VERSION 5.8 ;
BUSBITCHARS "[]" ;
DIVIDERCHAR "/" ;
UNITS
    DATABASE MICRONS 1000 ;
END UNITS

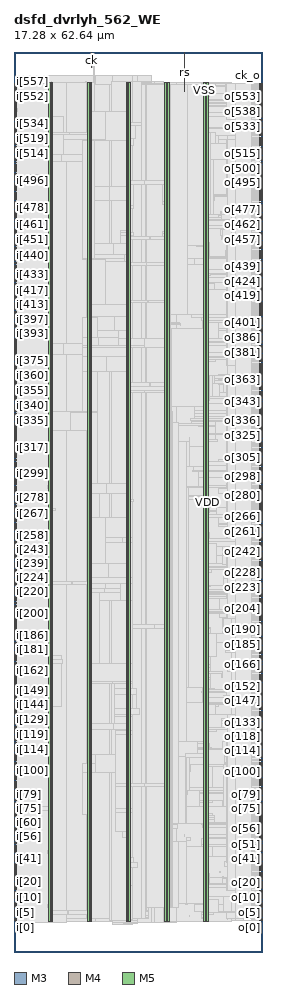
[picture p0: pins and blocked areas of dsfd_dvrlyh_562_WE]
MACRO dsfd_dvrlyh_562_WE
  FOREIGN dsfd_dvrlyh_562_WE 0 0 ;
  CLASS BLOCK ;
  SIZE 17.28 BY 62.64 ;
  PIN ck
    DIRECTION INPUT ;
    USE SIGNAL ;
    PORT
      LAYER M3 ;
        RECT  5.4 62.496 5.418 62.64 ;
    END
    PORT
      LAYER M3 ;
        RECT  5.4 61.579 5.418 62.508 ;
    END
  END ck
  PIN ck_o
    DIRECTION OUTPUT ;
    USE SIGNAL ;
    PORT
      LAYER M4 ;
        RECT  17.088 60.432 17.28 60.456 ;
    END
  END ck_o
  PIN i[0]
    DIRECTION INPUT ;
    USE SIGNAL ;
    PORT
      LAYER M4 ;
        RECT  0 2.208 0.192 2.232 ;
    END
  END i[0]
  PIN i[100]
    DIRECTION INPUT ;
    USE SIGNAL ;
    PORT
      LAYER M4 ;
        RECT  0 12.624 0.192 12.648 ;
    END
  END i[100]
  PIN i[101]
    DIRECTION INPUT ;
    USE SIGNAL ;
    PORT
      LAYER M4 ;
        RECT  0 12.72 0.192 12.744 ;
    END
  END i[101]
  PIN i[102]
    DIRECTION INPUT ;
    USE SIGNAL ;
    PORT
      LAYER M4 ;
        RECT  0 12.816 0.192 12.84 ;
    END
  END i[102]
  PIN i[103]
    DIRECTION INPUT ;
    USE SIGNAL ;
    PORT
      LAYER M4 ;
        RECT  0 12.912 0.192 12.936 ;
    END
  END i[103]
  PIN i[104]
    DIRECTION INPUT ;
    USE SIGNAL ;
    PORT
      LAYER M4 ;
        RECT  0 13.008 0.192 13.032 ;
    END
  END i[104]
  PIN i[105]
    DIRECTION INPUT ;
    USE SIGNAL ;
    PORT
      LAYER M4 ;
        RECT  0 13.104 0.192 13.128 ;
    END
  END i[105]
  PIN i[106]
    DIRECTION INPUT ;
    USE SIGNAL ;
    PORT
      LAYER M4 ;
        RECT  0 13.2 0.192 13.224 ;
    END
  END i[106]
  PIN i[107]
    DIRECTION INPUT ;
    USE SIGNAL ;
    PORT
      LAYER M4 ;
        RECT  0 13.344 0.192 13.368 ;
    END
  END i[107]
  PIN i[108]
    DIRECTION INPUT ;
    USE SIGNAL ;
    PORT
      LAYER M4 ;
        RECT  0 13.44 0.192 13.464 ;
    END
  END i[108]
  PIN i[109]
    DIRECTION INPUT ;
    USE SIGNAL ;
    PORT
      LAYER M4 ;
        RECT  0 13.536 0.192 13.56 ;
    END
  END i[109]
  PIN i[10]
    DIRECTION INPUT ;
    USE SIGNAL ;
    PORT
      LAYER M4 ;
        RECT  0 3.264 0.192 3.288 ;
    END
  END i[10]
  PIN i[110]
    DIRECTION INPUT ;
    USE SIGNAL ;
    PORT
      LAYER M4 ;
        RECT  0 13.632 0.192 13.656 ;
    END
  END i[110]
  PIN i[111]
    DIRECTION INPUT ;
    USE SIGNAL ;
    PORT
      LAYER M4 ;
        RECT  0 13.728 0.192 13.752 ;
    END
  END i[111]
  PIN i[112]
    DIRECTION INPUT ;
    USE SIGNAL ;
    PORT
      LAYER M4 ;
        RECT  0 13.824 0.192 13.848 ;
    END
  END i[112]
  PIN i[113]
    DIRECTION INPUT ;
    USE SIGNAL ;
    PORT
      LAYER M4 ;
        RECT  0 13.968 0.192 13.992 ;
    END
  END i[113]
  PIN i[114]
    DIRECTION INPUT ;
    USE SIGNAL ;
    PORT
      LAYER M4 ;
        RECT  0 14.064 0.192 14.088 ;
    END
  END i[114]
  PIN i[115]
    DIRECTION INPUT ;
    USE SIGNAL ;
    PORT
      LAYER M4 ;
        RECT  0 14.16 0.192 14.184 ;
    END
  END i[115]
  PIN i[116]
    DIRECTION INPUT ;
    USE SIGNAL ;
    PORT
      LAYER M4 ;
        RECT  0 14.256 0.192 14.28 ;
    END
  END i[116]
  PIN i[117]
    DIRECTION INPUT ;
    USE SIGNAL ;
    PORT
      LAYER M4 ;
        RECT  0 14.352 0.192 14.376 ;
    END
  END i[117]
  PIN i[118]
    DIRECTION INPUT ;
    USE SIGNAL ;
    PORT
      LAYER M4 ;
        RECT  0 14.448 0.192 14.472 ;
    END
  END i[118]
  PIN i[119]
    DIRECTION INPUT ;
    USE SIGNAL ;
    PORT
      LAYER M4 ;
        RECT  0 14.592 0.192 14.616 ;
    END
  END i[119]
  PIN i[11]
    DIRECTION INPUT ;
    USE SIGNAL ;
    PORT
      LAYER M4 ;
        RECT  0 3.36 0.192 3.384 ;
    END
  END i[11]
  PIN i[120]
    DIRECTION INPUT ;
    USE SIGNAL ;
    PORT
      LAYER M4 ;
        RECT  0 14.688 0.192 14.712 ;
    END
  END i[120]
  PIN i[121]
    DIRECTION INPUT ;
    USE SIGNAL ;
    PORT
      LAYER M4 ;
        RECT  0 14.784 0.192 14.808 ;
    END
  END i[121]
  PIN i[122]
    DIRECTION INPUT ;
    USE SIGNAL ;
    PORT
      LAYER M4 ;
        RECT  0 14.88 0.192 14.904 ;
    END
  END i[122]
  PIN i[123]
    DIRECTION INPUT ;
    USE SIGNAL ;
    PORT
      LAYER M4 ;
        RECT  0 14.976 0.192 15 ;
    END
  END i[123]
  PIN i[124]
    DIRECTION INPUT ;
    USE SIGNAL ;
    PORT
      LAYER M4 ;
        RECT  0 15.072 0.192 15.096 ;
    END
  END i[124]
  PIN i[125]
    DIRECTION INPUT ;
    USE SIGNAL ;
    PORT
      LAYER M4 ;
        RECT  0 15.216 0.192 15.24 ;
    END
  END i[125]
  PIN i[126]
    DIRECTION INPUT ;
    USE SIGNAL ;
    PORT
      LAYER M4 ;
        RECT  0 15.312 0.192 15.336 ;
    END
  END i[126]
  PIN i[127]
    DIRECTION INPUT ;
    USE SIGNAL ;
    PORT
      LAYER M4 ;
        RECT  0 15.408 0.192 15.432 ;
    END
  END i[127]
  PIN i[128]
    DIRECTION INPUT ;
    USE SIGNAL ;
    PORT
      LAYER M4 ;
        RECT  0 15.504 0.192 15.528 ;
    END
  END i[128]
  PIN i[129]
    DIRECTION INPUT ;
    USE SIGNAL ;
    PORT
      LAYER M4 ;
        RECT  0 15.6 0.192 15.624 ;
    END
  END i[129]
  PIN i[12]
    DIRECTION INPUT ;
    USE SIGNAL ;
    PORT
      LAYER M4 ;
        RECT  0 3.456 0.192 3.48 ;
    END
  END i[12]
  PIN i[130]
    DIRECTION INPUT ;
    USE SIGNAL ;
    PORT
      LAYER M4 ;
        RECT  0 15.696 0.192 15.72 ;
    END
  END i[130]
  PIN i[131]
    DIRECTION INPUT ;
    USE SIGNAL ;
    PORT
      LAYER M4 ;
        RECT  0 15.84 0.192 15.864 ;
    END
  END i[131]
  PIN i[132]
    DIRECTION INPUT ;
    USE SIGNAL ;
    PORT
      LAYER M4 ;
        RECT  0 15.936 0.192 15.96 ;
    END
  END i[132]
  PIN i[133]
    DIRECTION INPUT ;
    USE SIGNAL ;
    PORT
      LAYER M4 ;
        RECT  0 16.032 0.192 16.056 ;
    END
  END i[133]
  PIN i[134]
    DIRECTION INPUT ;
    USE SIGNAL ;
    PORT
      LAYER M4 ;
        RECT  0 16.128 0.192 16.152 ;
    END
  END i[134]
  PIN i[135]
    DIRECTION INPUT ;
    USE SIGNAL ;
    PORT
      LAYER M4 ;
        RECT  0 16.224 0.192 16.248 ;
    END
  END i[135]
  PIN i[136]
    DIRECTION INPUT ;
    USE SIGNAL ;
    PORT
      LAYER M4 ;
        RECT  0 16.32 0.192 16.344 ;
    END
  END i[136]
  PIN i[137]
    DIRECTION INPUT ;
    USE SIGNAL ;
    PORT
      LAYER M4 ;
        RECT  0 16.464 0.192 16.488 ;
    END
  END i[137]
  PIN i[138]
    DIRECTION INPUT ;
    USE SIGNAL ;
    PORT
      LAYER M4 ;
        RECT  0 16.56 0.192 16.584 ;
    END
  END i[138]
  PIN i[139]
    DIRECTION INPUT ;
    USE SIGNAL ;
    PORT
      LAYER M4 ;
        RECT  0 16.656 0.192 16.68 ;
    END
  END i[139]
  PIN i[13]
    DIRECTION INPUT ;
    USE SIGNAL ;
    PORT
      LAYER M4 ;
        RECT  0 3.552 0.192 3.576 ;
    END
  END i[13]
  PIN i[140]
    DIRECTION INPUT ;
    USE SIGNAL ;
    PORT
      LAYER M4 ;
        RECT  0 16.752 0.192 16.776 ;
    END
  END i[140]
  PIN i[141]
    DIRECTION INPUT ;
    USE SIGNAL ;
    PORT
      LAYER M4 ;
        RECT  0 16.848 0.192 16.872 ;
    END
  END i[141]
  PIN i[142]
    DIRECTION INPUT ;
    USE SIGNAL ;
    PORT
      LAYER M4 ;
        RECT  0 16.944 0.192 16.968 ;
    END
  END i[142]
  PIN i[143]
    DIRECTION INPUT ;
    USE SIGNAL ;
    PORT
      LAYER M4 ;
        RECT  0 17.04 0.192 17.064 ;
    END
  END i[143]
  PIN i[144]
    DIRECTION INPUT ;
    USE SIGNAL ;
    PORT
      LAYER M4 ;
        RECT  0 17.184 0.192 17.208 ;
    END
  END i[144]
  PIN i[145]
    DIRECTION INPUT ;
    USE SIGNAL ;
    PORT
      LAYER M4 ;
        RECT  0 17.28 0.192 17.304 ;
    END
  END i[145]
  PIN i[146]
    DIRECTION INPUT ;
    USE SIGNAL ;
    PORT
      LAYER M4 ;
        RECT  0 17.376 0.192 17.4 ;
    END
  END i[146]
  PIN i[147]
    DIRECTION INPUT ;
    USE SIGNAL ;
    PORT
      LAYER M4 ;
        RECT  0 17.472 0.192 17.496 ;
    END
  END i[147]
  PIN i[148]
    DIRECTION INPUT ;
    USE SIGNAL ;
    PORT
      LAYER M4 ;
        RECT  0 17.568 0.192 17.592 ;
    END
  END i[148]
  PIN i[149]
    DIRECTION INPUT ;
    USE SIGNAL ;
    PORT
      LAYER M4 ;
        RECT  0 17.664 0.192 17.688 ;
    END
  END i[149]
  PIN i[14]
    DIRECTION INPUT ;
    USE SIGNAL ;
    PORT
      LAYER M4 ;
        RECT  0 3.696 0.192 3.72 ;
    END
  END i[14]
  PIN i[150]
    DIRECTION INPUT ;
    USE SIGNAL ;
    PORT
      LAYER M4 ;
        RECT  0 17.808 0.192 17.832 ;
    END
  END i[150]
  PIN i[151]
    DIRECTION INPUT ;
    USE SIGNAL ;
    PORT
      LAYER M4 ;
        RECT  0 17.904 0.192 17.928 ;
    END
  END i[151]
  PIN i[152]
    DIRECTION INPUT ;
    USE SIGNAL ;
    PORT
      LAYER M4 ;
        RECT  0 18 0.192 18.024 ;
    END
  END i[152]
  PIN i[153]
    DIRECTION INPUT ;
    USE SIGNAL ;
    PORT
      LAYER M4 ;
        RECT  0 18.096 0.192 18.12 ;
    END
  END i[153]
  PIN i[154]
    DIRECTION INPUT ;
    USE SIGNAL ;
    PORT
      LAYER M4 ;
        RECT  0 18.192 0.192 18.216 ;
    END
  END i[154]
  PIN i[155]
    DIRECTION INPUT ;
    USE SIGNAL ;
    PORT
      LAYER M4 ;
        RECT  0 18.288 0.192 18.312 ;
    END
  END i[155]
  PIN i[156]
    DIRECTION INPUT ;
    USE SIGNAL ;
    PORT
      LAYER M4 ;
        RECT  0 18.432 0.192 18.456 ;
    END
  END i[156]
  PIN i[157]
    DIRECTION INPUT ;
    USE SIGNAL ;
    PORT
      LAYER M4 ;
        RECT  0 18.528 0.192 18.552 ;
    END
  END i[157]
  PIN i[158]
    DIRECTION INPUT ;
    USE SIGNAL ;
    PORT
      LAYER M4 ;
        RECT  0 18.624 0.192 18.648 ;
    END
  END i[158]
  PIN i[159]
    DIRECTION INPUT ;
    USE SIGNAL ;
    PORT
      LAYER M4 ;
        RECT  0 18.72 0.192 18.744 ;
    END
  END i[159]
  PIN i[15]
    DIRECTION INPUT ;
    USE SIGNAL ;
    PORT
      LAYER M4 ;
        RECT  0 3.792 0.192 3.816 ;
    END
  END i[15]
  PIN i[160]
    DIRECTION INPUT ;
    USE SIGNAL ;
    PORT
      LAYER M4 ;
        RECT  0 18.816 0.192 18.84 ;
    END
  END i[160]
  PIN i[161]
    DIRECTION INPUT ;
    USE SIGNAL ;
    PORT
      LAYER M4 ;
        RECT  0 18.912 0.192 18.936 ;
    END
  END i[161]
  PIN i[162]
    DIRECTION INPUT ;
    USE SIGNAL ;
    PORT
      LAYER M4 ;
        RECT  0 19.056 0.192 19.08 ;
    END
  END i[162]
  PIN i[163]
    DIRECTION INPUT ;
    USE SIGNAL ;
    PORT
      LAYER M4 ;
        RECT  0 19.152 0.192 19.176 ;
    END
  END i[163]
  PIN i[164]
    DIRECTION INPUT ;
    USE SIGNAL ;
    PORT
      LAYER M4 ;
        RECT  0 19.248 0.192 19.272 ;
    END
  END i[164]
  PIN i[165]
    DIRECTION INPUT ;
    USE SIGNAL ;
    PORT
      LAYER M4 ;
        RECT  0 19.344 0.192 19.368 ;
    END
  END i[165]
  PIN i[166]
    DIRECTION INPUT ;
    USE SIGNAL ;
    PORT
      LAYER M4 ;
        RECT  0 19.44 0.192 19.464 ;
    END
  END i[166]
  PIN i[167]
    DIRECTION INPUT ;
    USE SIGNAL ;
    PORT
      LAYER M4 ;
        RECT  0 19.536 0.192 19.56 ;
    END
  END i[167]
  PIN i[168]
    DIRECTION INPUT ;
    USE SIGNAL ;
    PORT
      LAYER M4 ;
        RECT  0 19.68 0.192 19.704 ;
    END
  END i[168]
  PIN i[169]
    DIRECTION INPUT ;
    USE SIGNAL ;
    PORT
      LAYER M4 ;
        RECT  0 19.776 0.192 19.8 ;
    END
  END i[169]
  PIN i[16]
    DIRECTION INPUT ;
    USE SIGNAL ;
    PORT
      LAYER M4 ;
        RECT  0 3.888 0.192 3.912 ;
    END
  END i[16]
  PIN i[170]
    DIRECTION INPUT ;
    USE SIGNAL ;
    PORT
      LAYER M4 ;
        RECT  0 19.872 0.192 19.896 ;
    END
  END i[170]
  PIN i[171]
    DIRECTION INPUT ;
    USE SIGNAL ;
    PORT
      LAYER M4 ;
        RECT  0 19.968 0.192 19.992 ;
    END
  END i[171]
  PIN i[172]
    DIRECTION INPUT ;
    USE SIGNAL ;
    PORT
      LAYER M4 ;
        RECT  0 20.064 0.192 20.088 ;
    END
  END i[172]
  PIN i[173]
    DIRECTION INPUT ;
    USE SIGNAL ;
    PORT
      LAYER M4 ;
        RECT  0 20.16 0.192 20.184 ;
    END
  END i[173]
  PIN i[174]
    DIRECTION INPUT ;
    USE SIGNAL ;
    PORT
      LAYER M4 ;
        RECT  0 20.304 0.192 20.328 ;
    END
  END i[174]
  PIN i[175]
    DIRECTION INPUT ;
    USE SIGNAL ;
    PORT
      LAYER M4 ;
        RECT  0 20.4 0.192 20.424 ;
    END
  END i[175]
  PIN i[176]
    DIRECTION INPUT ;
    USE SIGNAL ;
    PORT
      LAYER M4 ;
        RECT  0 20.496 0.192 20.52 ;
    END
  END i[176]
  PIN i[177]
    DIRECTION INPUT ;
    USE SIGNAL ;
    PORT
      LAYER M4 ;
        RECT  0 20.592 0.192 20.616 ;
    END
  END i[177]
  PIN i[178]
    DIRECTION INPUT ;
    USE SIGNAL ;
    PORT
      LAYER M4 ;
        RECT  0 20.688 0.192 20.712 ;
    END
  END i[178]
  PIN i[179]
    DIRECTION INPUT ;
    USE SIGNAL ;
    PORT
      LAYER M4 ;
        RECT  0 20.784 0.192 20.808 ;
    END
  END i[179]
  PIN i[17]
    DIRECTION INPUT ;
    USE SIGNAL ;
    PORT
      LAYER M4 ;
        RECT  0 3.984 0.192 4.008 ;
    END
  END i[17]
  PIN i[180]
    DIRECTION INPUT ;
    USE SIGNAL ;
    PORT
      LAYER M4 ;
        RECT  0 20.88 0.192 20.904 ;
    END
  END i[180]
  PIN i[181]
    DIRECTION INPUT ;
    USE SIGNAL ;
    PORT
      LAYER M4 ;
        RECT  0 21.024 0.192 21.048 ;
    END
  END i[181]
  PIN i[182]
    DIRECTION INPUT ;
    USE SIGNAL ;
    PORT
      LAYER M4 ;
        RECT  0 21.12 0.192 21.144 ;
    END
  END i[182]
  PIN i[183]
    DIRECTION INPUT ;
    USE SIGNAL ;
    PORT
      LAYER M4 ;
        RECT  0 21.216 0.192 21.24 ;
    END
  END i[183]
  PIN i[184]
    DIRECTION INPUT ;
    USE SIGNAL ;
    PORT
      LAYER M4 ;
        RECT  0 21.312 0.192 21.336 ;
    END
  END i[184]
  PIN i[185]
    DIRECTION INPUT ;
    USE SIGNAL ;
    PORT
      LAYER M4 ;
        RECT  0 21.408 0.192 21.432 ;
    END
  END i[185]
  PIN i[186]
    DIRECTION INPUT ;
    USE SIGNAL ;
    PORT
      LAYER M4 ;
        RECT  0 21.504 0.192 21.528 ;
    END
  END i[186]
  PIN i[187]
    DIRECTION INPUT ;
    USE SIGNAL ;
    PORT
      LAYER M4 ;
        RECT  0 21.648 0.192 21.672 ;
    END
  END i[187]
  PIN i[188]
    DIRECTION INPUT ;
    USE SIGNAL ;
    PORT
      LAYER M4 ;
        RECT  0 21.744 0.192 21.768 ;
    END
  END i[188]
  PIN i[189]
    DIRECTION INPUT ;
    USE SIGNAL ;
    PORT
      LAYER M4 ;
        RECT  0 21.84 0.192 21.864 ;
    END
  END i[189]
  PIN i[18]
    DIRECTION INPUT ;
    USE SIGNAL ;
    PORT
      LAYER M4 ;
        RECT  0 4.08 0.192 4.104 ;
    END
  END i[18]
  PIN i[190]
    DIRECTION INPUT ;
    USE SIGNAL ;
    PORT
      LAYER M4 ;
        RECT  0 21.936 0.192 21.96 ;
    END
  END i[190]
  PIN i[191]
    DIRECTION INPUT ;
    USE SIGNAL ;
    PORT
      LAYER M4 ;
        RECT  0 22.032 0.192 22.056 ;
    END
  END i[191]
  PIN i[192]
    DIRECTION INPUT ;
    USE SIGNAL ;
    PORT
      LAYER M4 ;
        RECT  0 22.128 0.192 22.152 ;
    END
  END i[192]
  PIN i[193]
    DIRECTION INPUT ;
    USE SIGNAL ;
    PORT
      LAYER M4 ;
        RECT  0 22.272 0.192 22.296 ;
    END
  END i[193]
  PIN i[194]
    DIRECTION INPUT ;
    USE SIGNAL ;
    PORT
      LAYER M4 ;
        RECT  0 22.368 0.192 22.392 ;
    END
  END i[194]
  PIN i[195]
    DIRECTION INPUT ;
    USE SIGNAL ;
    PORT
      LAYER M4 ;
        RECT  0 22.464 0.192 22.488 ;
    END
  END i[195]
  PIN i[196]
    DIRECTION INPUT ;
    USE SIGNAL ;
    PORT
      LAYER M4 ;
        RECT  0 22.56 0.192 22.584 ;
    END
  END i[196]
  PIN i[197]
    DIRECTION INPUT ;
    USE SIGNAL ;
    PORT
      LAYER M4 ;
        RECT  0 22.656 0.192 22.68 ;
    END
  END i[197]
  PIN i[198]
    DIRECTION INPUT ;
    USE SIGNAL ;
    PORT
      LAYER M4 ;
        RECT  0 22.752 0.192 22.776 ;
    END
  END i[198]
  PIN i[199]
    DIRECTION INPUT ;
    USE SIGNAL ;
    PORT
      LAYER M4 ;
        RECT  0 22.896 0.192 22.92 ;
    END
  END i[199]
  PIN i[19]
    DIRECTION INPUT ;
    USE SIGNAL ;
    PORT
      LAYER M4 ;
        RECT  0 4.176 0.192 4.2 ;
    END
  END i[19]
  PIN i[1]
    DIRECTION INPUT ;
    USE SIGNAL ;
    PORT
      LAYER M4 ;
        RECT  0 2.304 0.192 2.328 ;
    END
  END i[1]
  PIN i[200]
    DIRECTION INPUT ;
    USE SIGNAL ;
    PORT
      LAYER M4 ;
        RECT  0 22.992 0.192 23.016 ;
    END
  END i[200]
  PIN i[201]
    DIRECTION INPUT ;
    USE SIGNAL ;
    PORT
      LAYER M4 ;
        RECT  0 23.088 0.192 23.112 ;
    END
  END i[201]
  PIN i[202]
    DIRECTION INPUT ;
    USE SIGNAL ;
    PORT
      LAYER M4 ;
        RECT  0 23.184 0.192 23.208 ;
    END
  END i[202]
  PIN i[203]
    DIRECTION INPUT ;
    USE SIGNAL ;
    PORT
      LAYER M4 ;
        RECT  0 23.28 0.192 23.304 ;
    END
  END i[203]
  PIN i[204]
    DIRECTION INPUT ;
    USE SIGNAL ;
    PORT
      LAYER M4 ;
        RECT  0 23.376 0.192 23.4 ;
    END
  END i[204]
  PIN i[205]
    DIRECTION INPUT ;
    USE SIGNAL ;
    PORT
      LAYER M4 ;
        RECT  0 23.52 0.192 23.544 ;
    END
  END i[205]
  PIN i[206]
    DIRECTION INPUT ;
    USE SIGNAL ;
    PORT
      LAYER M4 ;
        RECT  0 23.616 0.192 23.64 ;
    END
  END i[206]
  PIN i[207]
    DIRECTION INPUT ;
    USE SIGNAL ;
    PORT
      LAYER M4 ;
        RECT  0 23.712 0.192 23.736 ;
    END
  END i[207]
  PIN i[208]
    DIRECTION INPUT ;
    USE SIGNAL ;
    PORT
      LAYER M4 ;
        RECT  0 23.808 0.192 23.832 ;
    END
  END i[208]
  PIN i[209]
    DIRECTION INPUT ;
    USE SIGNAL ;
    PORT
      LAYER M4 ;
        RECT  0 23.904 0.192 23.928 ;
    END
  END i[209]
  PIN i[20]
    DIRECTION INPUT ;
    USE SIGNAL ;
    PORT
      LAYER M4 ;
        RECT  0 4.32 0.192 4.344 ;
    END
  END i[20]
  PIN i[210]
    DIRECTION INPUT ;
    USE SIGNAL ;
    PORT
      LAYER M4 ;
        RECT  0 24 0.192 24.024 ;
    END
  END i[210]
  PIN i[211]
    DIRECTION INPUT ;
    USE SIGNAL ;
    PORT
      LAYER M4 ;
        RECT  0 24.096 0.192 24.12 ;
    END
  END i[211]
  PIN i[212]
    DIRECTION INPUT ;
    USE SIGNAL ;
    PORT
      LAYER M4 ;
        RECT  0 24.24 0.192 24.264 ;
    END
  END i[212]
  PIN i[213]
    DIRECTION INPUT ;
    USE SIGNAL ;
    PORT
      LAYER M4 ;
        RECT  0 24.336 0.192 24.36 ;
    END
  END i[213]
  PIN i[214]
    DIRECTION INPUT ;
    USE SIGNAL ;
    PORT
      LAYER M4 ;
        RECT  0 24.432 0.192 24.456 ;
    END
  END i[214]
  PIN i[215]
    DIRECTION INPUT ;
    USE SIGNAL ;
    PORT
      LAYER M4 ;
        RECT  0 24.528 0.192 24.552 ;
    END
  END i[215]
  PIN i[216]
    DIRECTION INPUT ;
    USE SIGNAL ;
    PORT
      LAYER M4 ;
        RECT  0 24.624 0.192 24.648 ;
    END
  END i[216]
  PIN i[217]
    DIRECTION INPUT ;
    USE SIGNAL ;
    PORT
      LAYER M4 ;
        RECT  0 24.72 0.192 24.744 ;
    END
  END i[217]
  PIN i[218]
    DIRECTION INPUT ;
    USE SIGNAL ;
    PORT
      LAYER M4 ;
        RECT  0 24.864 0.192 24.888 ;
    END
  END i[218]
  PIN i[219]
    DIRECTION INPUT ;
    USE SIGNAL ;
    PORT
      LAYER M4 ;
        RECT  0 24.96 0.192 24.984 ;
    END
  END i[219]
  PIN i[21]
    DIRECTION INPUT ;
    USE SIGNAL ;
    PORT
      LAYER M4 ;
        RECT  0 4.416 0.192 4.44 ;
    END
  END i[21]
  PIN i[220]
    DIRECTION INPUT ;
    USE SIGNAL ;
    PORT
      LAYER M4 ;
        RECT  0 25.056 0.192 25.08 ;
    END
  END i[220]
  PIN i[221]
    DIRECTION INPUT ;
    USE SIGNAL ;
    PORT
      LAYER M4 ;
        RECT  0 25.152 0.192 25.176 ;
    END
  END i[221]
  PIN i[222]
    DIRECTION INPUT ;
    USE SIGNAL ;
    PORT
      LAYER M4 ;
        RECT  0 25.248 0.192 25.272 ;
    END
  END i[222]
  PIN i[223]
    DIRECTION INPUT ;
    USE SIGNAL ;
    PORT
      LAYER M4 ;
        RECT  0 25.344 0.192 25.368 ;
    END
  END i[223]
  PIN i[224]
    DIRECTION INPUT ;
    USE SIGNAL ;
    PORT
      LAYER M4 ;
        RECT  0 25.488 0.192 25.512 ;
    END
  END i[224]
  PIN i[225]
    DIRECTION INPUT ;
    USE SIGNAL ;
    PORT
      LAYER M4 ;
        RECT  0 25.584 0.192 25.608 ;
    END
  END i[225]
  PIN i[226]
    DIRECTION INPUT ;
    USE SIGNAL ;
    PORT
      LAYER M4 ;
        RECT  0 25.68 0.192 25.704 ;
    END
  END i[226]
  PIN i[227]
    DIRECTION INPUT ;
    USE SIGNAL ;
    PORT
      LAYER M4 ;
        RECT  0 25.776 0.192 25.8 ;
    END
  END i[227]
  PIN i[228]
    DIRECTION INPUT ;
    USE SIGNAL ;
    PORT
      LAYER M4 ;
        RECT  0 25.872 0.192 25.896 ;
    END
  END i[228]
  PIN i[229]
    DIRECTION INPUT ;
    USE SIGNAL ;
    PORT
      LAYER M4 ;
        RECT  0 25.968 0.192 25.992 ;
    END
  END i[229]
  PIN i[22]
    DIRECTION INPUT ;
    USE SIGNAL ;
    PORT
      LAYER M4 ;
        RECT  0 4.512 0.192 4.536 ;
    END
  END i[22]
  PIN i[230]
    DIRECTION INPUT ;
    USE SIGNAL ;
    PORT
      LAYER M4 ;
        RECT  0 26.112 0.192 26.136 ;
    END
  END i[230]
  PIN i[231]
    DIRECTION INPUT ;
    USE SIGNAL ;
    PORT
      LAYER M4 ;
        RECT  0 26.208 0.192 26.232 ;
    END
  END i[231]
  PIN i[232]
    DIRECTION INPUT ;
    USE SIGNAL ;
    PORT
      LAYER M4 ;
        RECT  0 26.304 0.192 26.328 ;
    END
  END i[232]
  PIN i[233]
    DIRECTION INPUT ;
    USE SIGNAL ;
    PORT
      LAYER M4 ;
        RECT  0 26.4 0.192 26.424 ;
    END
  END i[233]
  PIN i[234]
    DIRECTION INPUT ;
    USE SIGNAL ;
    PORT
      LAYER M4 ;
        RECT  0 26.496 0.192 26.52 ;
    END
  END i[234]
  PIN i[235]
    DIRECTION INPUT ;
    USE SIGNAL ;
    PORT
      LAYER M4 ;
        RECT  0 26.592 0.192 26.616 ;
    END
  END i[235]
  PIN i[236]
    DIRECTION INPUT ;
    USE SIGNAL ;
    PORT
      LAYER M4 ;
        RECT  0 26.736 0.192 26.76 ;
    END
  END i[236]
  PIN i[237]
    DIRECTION INPUT ;
    USE SIGNAL ;
    PORT
      LAYER M4 ;
        RECT  0 26.832 0.192 26.856 ;
    END
  END i[237]
  PIN i[238]
    DIRECTION INPUT ;
    USE SIGNAL ;
    PORT
      LAYER M4 ;
        RECT  0 26.928 0.192 26.952 ;
    END
  END i[238]
  PIN i[239]
    DIRECTION INPUT ;
    USE SIGNAL ;
    PORT
      LAYER M4 ;
        RECT  0 27.024 0.192 27.048 ;
    END
  END i[239]
  PIN i[23]
    DIRECTION INPUT ;
    USE SIGNAL ;
    PORT
      LAYER M4 ;
        RECT  0 4.608 0.192 4.632 ;
    END
  END i[23]
  PIN i[240]
    DIRECTION INPUT ;
    USE SIGNAL ;
    PORT
      LAYER M4 ;
        RECT  0 27.12 0.192 27.144 ;
    END
  END i[240]
  PIN i[241]
    DIRECTION INPUT ;
    USE SIGNAL ;
    PORT
      LAYER M4 ;
        RECT  0 27.216 0.192 27.24 ;
    END
  END i[241]
  PIN i[242]
    DIRECTION INPUT ;
    USE SIGNAL ;
    PORT
      LAYER M4 ;
        RECT  0 27.36 0.192 27.384 ;
    END
  END i[242]
  PIN i[243]
    DIRECTION INPUT ;
    USE SIGNAL ;
    PORT
      LAYER M4 ;
        RECT  0 27.456 0.192 27.48 ;
    END
  END i[243]
  PIN i[244]
    DIRECTION INPUT ;
    USE SIGNAL ;
    PORT
      LAYER M4 ;
        RECT  0 27.552 0.192 27.576 ;
    END
  END i[244]
  PIN i[245]
    DIRECTION INPUT ;
    USE SIGNAL ;
    PORT
      LAYER M4 ;
        RECT  0 27.648 0.192 27.672 ;
    END
  END i[245]
  PIN i[246]
    DIRECTION INPUT ;
    USE SIGNAL ;
    PORT
      LAYER M4 ;
        RECT  0 27.744 0.192 27.768 ;
    END
  END i[246]
  PIN i[247]
    DIRECTION INPUT ;
    USE SIGNAL ;
    PORT
      LAYER M4 ;
        RECT  0 27.84 0.192 27.864 ;
    END
  END i[247]
  PIN i[248]
    DIRECTION INPUT ;
    USE SIGNAL ;
    PORT
      LAYER M4 ;
        RECT  0 27.936 0.192 27.96 ;
    END
  END i[248]
  PIN i[249]
    DIRECTION INPUT ;
    USE SIGNAL ;
    PORT
      LAYER M4 ;
        RECT  0 28.08 0.192 28.104 ;
    END
  END i[249]
  PIN i[24]
    DIRECTION INPUT ;
    USE SIGNAL ;
    PORT
      LAYER M4 ;
        RECT  0 4.704 0.192 4.728 ;
    END
  END i[24]
  PIN i[250]
    DIRECTION INPUT ;
    USE SIGNAL ;
    PORT
      LAYER M4 ;
        RECT  0 28.176 0.192 28.2 ;
    END
  END i[250]
  PIN i[251]
    DIRECTION INPUT ;
    USE SIGNAL ;
    PORT
      LAYER M4 ;
        RECT  0 28.272 0.192 28.296 ;
    END
  END i[251]
  PIN i[252]
    DIRECTION INPUT ;
    USE SIGNAL ;
    PORT
      LAYER M4 ;
        RECT  0 28.368 0.192 28.392 ;
    END
  END i[252]
  PIN i[253]
    DIRECTION INPUT ;
    USE SIGNAL ;
    PORT
      LAYER M4 ;
        RECT  0 28.464 0.192 28.488 ;
    END
  END i[253]
  PIN i[254]
    DIRECTION INPUT ;
    USE SIGNAL ;
    PORT
      LAYER M4 ;
        RECT  0 28.56 0.192 28.584 ;
    END
  END i[254]
  PIN i[255]
    DIRECTION INPUT ;
    USE SIGNAL ;
    PORT
      LAYER M4 ;
        RECT  0 28.704 0.192 28.728 ;
    END
  END i[255]
  PIN i[256]
    DIRECTION INPUT ;
    USE SIGNAL ;
    PORT
      LAYER M4 ;
        RECT  0 28.8 0.192 28.824 ;
    END
  END i[256]
  PIN i[257]
    DIRECTION INPUT ;
    USE SIGNAL ;
    PORT
      LAYER M4 ;
        RECT  0 28.896 0.192 28.92 ;
    END
  END i[257]
  PIN i[258]
    DIRECTION INPUT ;
    USE SIGNAL ;
    PORT
      LAYER M4 ;
        RECT  0 28.992 0.192 29.016 ;
    END
  END i[258]
  PIN i[259]
    DIRECTION INPUT ;
    USE SIGNAL ;
    PORT
      LAYER M4 ;
        RECT  0 29.088 0.192 29.112 ;
    END
  END i[259]
  PIN i[25]
    DIRECTION INPUT ;
    USE SIGNAL ;
    PORT
      LAYER M4 ;
        RECT  0 4.8 0.192 4.824 ;
    END
  END i[25]
  PIN i[260]
    DIRECTION INPUT ;
    USE SIGNAL ;
    PORT
      LAYER M4 ;
        RECT  0 29.184 0.192 29.208 ;
    END
  END i[260]
  PIN i[261]
    DIRECTION INPUT ;
    USE SIGNAL ;
    PORT
      LAYER M4 ;
        RECT  0 29.328 0.192 29.352 ;
    END
  END i[261]
  PIN i[262]
    DIRECTION INPUT ;
    USE SIGNAL ;
    PORT
      LAYER M4 ;
        RECT  0 29.424 0.192 29.448 ;
    END
  END i[262]
  PIN i[263]
    DIRECTION INPUT ;
    USE SIGNAL ;
    PORT
      LAYER M4 ;
        RECT  0 29.52 0.192 29.544 ;
    END
  END i[263]
  PIN i[264]
    DIRECTION INPUT ;
    USE SIGNAL ;
    PORT
      LAYER M4 ;
        RECT  0 29.616 0.192 29.64 ;
    END
  END i[264]
  PIN i[265]
    DIRECTION INPUT ;
    USE SIGNAL ;
    PORT
      LAYER M4 ;
        RECT  0 29.712 0.192 29.736 ;
    END
  END i[265]
  PIN i[266]
    DIRECTION INPUT ;
    USE SIGNAL ;
    PORT
      LAYER M4 ;
        RECT  0 29.808 0.192 29.832 ;
    END
  END i[266]
  PIN i[267]
    DIRECTION INPUT ;
    USE SIGNAL ;
    PORT
      LAYER M4 ;
        RECT  0 29.952 0.192 29.976 ;
    END
  END i[267]
  PIN i[268]
    DIRECTION INPUT ;
    USE SIGNAL ;
    PORT
      LAYER M4 ;
        RECT  0 30.048 0.192 30.072 ;
    END
  END i[268]
  PIN i[269]
    DIRECTION INPUT ;
    USE SIGNAL ;
    PORT
      LAYER M4 ;
        RECT  0 30.144 0.192 30.168 ;
    END
  END i[269]
  PIN i[26]
    DIRECTION INPUT ;
    USE SIGNAL ;
    PORT
      LAYER M4 ;
        RECT  0 4.944 0.192 4.968 ;
    END
  END i[26]
  PIN i[270]
    DIRECTION INPUT ;
    USE SIGNAL ;
    PORT
      LAYER M4 ;
        RECT  0 30.24 0.192 30.264 ;
    END
  END i[270]
  PIN i[271]
    DIRECTION INPUT ;
    USE SIGNAL ;
    PORT
      LAYER M4 ;
        RECT  0 30.336 0.192 30.36 ;
    END
  END i[271]
  PIN i[272]
    DIRECTION INPUT ;
    USE SIGNAL ;
    PORT
      LAYER M4 ;
        RECT  0 30.432 0.192 30.456 ;
    END
  END i[272]
  PIN i[273]
    DIRECTION INPUT ;
    USE SIGNAL ;
    PORT
      LAYER M4 ;
        RECT  0 30.576 0.192 30.6 ;
    END
  END i[273]
  PIN i[274]
    DIRECTION INPUT ;
    USE SIGNAL ;
    PORT
      LAYER M4 ;
        RECT  0 30.672 0.192 30.696 ;
    END
  END i[274]
  PIN i[275]
    DIRECTION INPUT ;
    USE SIGNAL ;
    PORT
      LAYER M4 ;
        RECT  0 30.768 0.192 30.792 ;
    END
  END i[275]
  PIN i[276]
    DIRECTION INPUT ;
    USE SIGNAL ;
    PORT
      LAYER M4 ;
        RECT  0 30.864 0.192 30.888 ;
    END
  END i[276]
  PIN i[277]
    DIRECTION INPUT ;
    USE SIGNAL ;
    PORT
      LAYER M4 ;
        RECT  0 30.96 0.192 30.984 ;
    END
  END i[277]
  PIN i[278]
    DIRECTION INPUT ;
    USE SIGNAL ;
    PORT
      LAYER M4 ;
        RECT  0 31.056 0.192 31.08 ;
    END
  END i[278]
  PIN i[279]
    DIRECTION INPUT ;
    USE SIGNAL ;
    PORT
      LAYER M4 ;
        RECT  0 31.2 0.192 31.224 ;
    END
  END i[279]
  PIN i[27]
    DIRECTION INPUT ;
    USE SIGNAL ;
    PORT
      LAYER M4 ;
        RECT  0 5.04 0.192 5.064 ;
    END
  END i[27]
  PIN i[280]
    DIRECTION INPUT ;
    USE SIGNAL ;
    PORT
      LAYER M4 ;
        RECT  0 31.296 0.192 31.32 ;
    END
  END i[280]
  PIN i[281]
    DIRECTION INPUT ;
    USE SIGNAL ;
    PORT
      LAYER M4 ;
        RECT  0 31.392 0.192 31.416 ;
    END
  END i[281]
  PIN i[282]
    DIRECTION INPUT ;
    USE SIGNAL ;
    PORT
      LAYER M4 ;
        RECT  0 31.488 0.192 31.512 ;
    END
  END i[282]
  PIN i[283]
    DIRECTION INPUT ;
    USE SIGNAL ;
    PORT
      LAYER M4 ;
        RECT  0 31.584 0.192 31.608 ;
    END
  END i[283]
  PIN i[284]
    DIRECTION INPUT ;
    USE SIGNAL ;
    PORT
      LAYER M4 ;
        RECT  0 31.68 0.192 31.704 ;
    END
  END i[284]
  PIN i[285]
    DIRECTION INPUT ;
    USE SIGNAL ;
    PORT
      LAYER M4 ;
        RECT  0 31.776 0.192 31.8 ;
    END
  END i[285]
  PIN i[286]
    DIRECTION INPUT ;
    USE SIGNAL ;
    PORT
      LAYER M4 ;
        RECT  0 31.92 0.192 31.944 ;
    END
  END i[286]
  PIN i[287]
    DIRECTION INPUT ;
    USE SIGNAL ;
    PORT
      LAYER M4 ;
        RECT  0 32.016 0.192 32.04 ;
    END
  END i[287]
  PIN i[288]
    DIRECTION INPUT ;
    USE SIGNAL ;
    PORT
      LAYER M4 ;
        RECT  0 32.112 0.192 32.136 ;
    END
  END i[288]
  PIN i[289]
    DIRECTION INPUT ;
    USE SIGNAL ;
    PORT
      LAYER M4 ;
        RECT  0 32.208 0.192 32.232 ;
    END
  END i[289]
  PIN i[28]
    DIRECTION INPUT ;
    USE SIGNAL ;
    PORT
      LAYER M4 ;
        RECT  0 5.136 0.192 5.16 ;
    END
  END i[28]
  PIN i[290]
    DIRECTION INPUT ;
    USE SIGNAL ;
    PORT
      LAYER M4 ;
        RECT  0 32.304 0.192 32.328 ;
    END
  END i[290]
  PIN i[291]
    DIRECTION INPUT ;
    USE SIGNAL ;
    PORT
      LAYER M4 ;
        RECT  0 32.4 0.192 32.424 ;
    END
  END i[291]
  PIN i[292]
    DIRECTION INPUT ;
    USE SIGNAL ;
    PORT
      LAYER M4 ;
        RECT  0 32.544 0.192 32.568 ;
    END
  END i[292]
  PIN i[293]
    DIRECTION INPUT ;
    USE SIGNAL ;
    PORT
      LAYER M4 ;
        RECT  0 32.64 0.192 32.664 ;
    END
  END i[293]
  PIN i[294]
    DIRECTION INPUT ;
    USE SIGNAL ;
    PORT
      LAYER M4 ;
        RECT  0 32.736 0.192 32.76 ;
    END
  END i[294]
  PIN i[295]
    DIRECTION INPUT ;
    USE SIGNAL ;
    PORT
      LAYER M4 ;
        RECT  0 32.832 0.192 32.856 ;
    END
  END i[295]
  PIN i[296]
    DIRECTION INPUT ;
    USE SIGNAL ;
    PORT
      LAYER M4 ;
        RECT  0 32.928 0.192 32.952 ;
    END
  END i[296]
  PIN i[297]
    DIRECTION INPUT ;
    USE SIGNAL ;
    PORT
      LAYER M4 ;
        RECT  0 33.024 0.192 33.048 ;
    END
  END i[297]
  PIN i[298]
    DIRECTION INPUT ;
    USE SIGNAL ;
    PORT
      LAYER M4 ;
        RECT  0 33.168 0.192 33.192 ;
    END
  END i[298]
  PIN i[299]
    DIRECTION INPUT ;
    USE SIGNAL ;
    PORT
      LAYER M4 ;
        RECT  0 33.264 0.192 33.288 ;
    END
  END i[299]
  PIN i[29]
    DIRECTION INPUT ;
    USE SIGNAL ;
    PORT
      LAYER M4 ;
        RECT  0 5.232 0.192 5.256 ;
    END
  END i[29]
  PIN i[2]
    DIRECTION INPUT ;
    USE SIGNAL ;
    PORT
      LAYER M4 ;
        RECT  0 2.448 0.192 2.472 ;
    END
  END i[2]
  PIN i[300]
    DIRECTION INPUT ;
    USE SIGNAL ;
    PORT
      LAYER M4 ;
        RECT  0 33.36 0.192 33.384 ;
    END
  END i[300]
  PIN i[301]
    DIRECTION INPUT ;
    USE SIGNAL ;
    PORT
      LAYER M4 ;
        RECT  0 33.456 0.192 33.48 ;
    END
  END i[301]
  PIN i[302]
    DIRECTION INPUT ;
    USE SIGNAL ;
    PORT
      LAYER M4 ;
        RECT  0 33.552 0.192 33.576 ;
    END
  END i[302]
  PIN i[303]
    DIRECTION INPUT ;
    USE SIGNAL ;
    PORT
      LAYER M4 ;
        RECT  0 33.648 0.192 33.672 ;
    END
  END i[303]
  PIN i[304]
    DIRECTION INPUT ;
    USE SIGNAL ;
    PORT
      LAYER M4 ;
        RECT  0 33.792 0.192 33.816 ;
    END
  END i[304]
  PIN i[305]
    DIRECTION INPUT ;
    USE SIGNAL ;
    PORT
      LAYER M4 ;
        RECT  0 33.888 0.192 33.912 ;
    END
  END i[305]
  PIN i[306]
    DIRECTION INPUT ;
    USE SIGNAL ;
    PORT
      LAYER M4 ;
        RECT  0 33.984 0.192 34.008 ;
    END
  END i[306]
  PIN i[307]
    DIRECTION INPUT ;
    USE SIGNAL ;
    PORT
      LAYER M4 ;
        RECT  0 34.08 0.192 34.104 ;
    END
  END i[307]
  PIN i[308]
    DIRECTION INPUT ;
    USE SIGNAL ;
    PORT
      LAYER M4 ;
        RECT  0 34.176 0.192 34.2 ;
    END
  END i[308]
  PIN i[309]
    DIRECTION INPUT ;
    USE SIGNAL ;
    PORT
      LAYER M4 ;
        RECT  0 34.272 0.192 34.296 ;
    END
  END i[309]
  PIN i[30]
    DIRECTION INPUT ;
    USE SIGNAL ;
    PORT
      LAYER M4 ;
        RECT  0 5.328 0.192 5.352 ;
    END
  END i[30]
  PIN i[310]
    DIRECTION INPUT ;
    USE SIGNAL ;
    PORT
      LAYER M4 ;
        RECT  0 34.416 0.192 34.44 ;
    END
  END i[310]
  PIN i[311]
    DIRECTION INPUT ;
    USE SIGNAL ;
    PORT
      LAYER M4 ;
        RECT  0 34.512 0.192 34.536 ;
    END
  END i[311]
  PIN i[312]
    DIRECTION INPUT ;
    USE SIGNAL ;
    PORT
      LAYER M4 ;
        RECT  0 34.608 0.192 34.632 ;
    END
  END i[312]
  PIN i[313]
    DIRECTION INPUT ;
    USE SIGNAL ;
    PORT
      LAYER M4 ;
        RECT  0 34.704 0.192 34.728 ;
    END
  END i[313]
  PIN i[314]
    DIRECTION INPUT ;
    USE SIGNAL ;
    PORT
      LAYER M4 ;
        RECT  0 34.8 0.192 34.824 ;
    END
  END i[314]
  PIN i[315]
    DIRECTION INPUT ;
    USE SIGNAL ;
    PORT
      LAYER M4 ;
        RECT  0 34.896 0.192 34.92 ;
    END
  END i[315]
  PIN i[316]
    DIRECTION INPUT ;
    USE SIGNAL ;
    PORT
      LAYER M4 ;
        RECT  0 34.992 0.192 35.016 ;
    END
  END i[316]
  PIN i[317]
    DIRECTION INPUT ;
    USE SIGNAL ;
    PORT
      LAYER M4 ;
        RECT  0 35.136 0.192 35.16 ;
    END
  END i[317]
  PIN i[318]
    DIRECTION INPUT ;
    USE SIGNAL ;
    PORT
      LAYER M4 ;
        RECT  0 35.232 0.192 35.256 ;
    END
  END i[318]
  PIN i[319]
    DIRECTION INPUT ;
    USE SIGNAL ;
    PORT
      LAYER M4 ;
        RECT  0 35.328 0.192 35.352 ;
    END
  END i[319]
  PIN i[31]
    DIRECTION INPUT ;
    USE SIGNAL ;
    PORT
      LAYER M4 ;
        RECT  0 5.424 0.192 5.448 ;
    END
  END i[31]
  PIN i[320]
    DIRECTION INPUT ;
    USE SIGNAL ;
    PORT
      LAYER M4 ;
        RECT  0 35.424 0.192 35.448 ;
    END
  END i[320]
  PIN i[321]
    DIRECTION INPUT ;
    USE SIGNAL ;
    PORT
      LAYER M4 ;
        RECT  0 35.52 0.192 35.544 ;
    END
  END i[321]
  PIN i[322]
    DIRECTION INPUT ;
    USE SIGNAL ;
    PORT
      LAYER M4 ;
        RECT  0 35.616 0.192 35.64 ;
    END
  END i[322]
  PIN i[323]
    DIRECTION INPUT ;
    USE SIGNAL ;
    PORT
      LAYER M4 ;
        RECT  0 35.76 0.192 35.784 ;
    END
  END i[323]
  PIN i[324]
    DIRECTION INPUT ;
    USE SIGNAL ;
    PORT
      LAYER M4 ;
        RECT  0 35.856 0.192 35.88 ;
    END
  END i[324]
  PIN i[325]
    DIRECTION INPUT ;
    USE SIGNAL ;
    PORT
      LAYER M4 ;
        RECT  0 35.952 0.192 35.976 ;
    END
  END i[325]
  PIN i[326]
    DIRECTION INPUT ;
    USE SIGNAL ;
    PORT
      LAYER M4 ;
        RECT  0 36.048 0.192 36.072 ;
    END
  END i[326]
  PIN i[327]
    DIRECTION INPUT ;
    USE SIGNAL ;
    PORT
      LAYER M4 ;
        RECT  0 36.144 0.192 36.168 ;
    END
  END i[327]
  PIN i[328]
    DIRECTION INPUT ;
    USE SIGNAL ;
    PORT
      LAYER M4 ;
        RECT  0 36.24 0.192 36.264 ;
    END
  END i[328]
  PIN i[329]
    DIRECTION INPUT ;
    USE SIGNAL ;
    PORT
      LAYER M4 ;
        RECT  0 36.384 0.192 36.408 ;
    END
  END i[329]
  PIN i[32]
    DIRECTION INPUT ;
    USE SIGNAL ;
    PORT
      LAYER M4 ;
        RECT  0 5.568 0.192 5.592 ;
    END
  END i[32]
  PIN i[330]
    DIRECTION INPUT ;
    USE SIGNAL ;
    PORT
      LAYER M4 ;
        RECT  0 36.48 0.192 36.504 ;
    END
  END i[330]
  PIN i[331]
    DIRECTION INPUT ;
    USE SIGNAL ;
    PORT
      LAYER M4 ;
        RECT  0 36.576 0.192 36.6 ;
    END
  END i[331]
  PIN i[332]
    DIRECTION INPUT ;
    USE SIGNAL ;
    PORT
      LAYER M4 ;
        RECT  0 36.672 0.192 36.696 ;
    END
  END i[332]
  PIN i[333]
    DIRECTION INPUT ;
    USE SIGNAL ;
    PORT
      LAYER M4 ;
        RECT  0 36.768 0.192 36.792 ;
    END
  END i[333]
  PIN i[334]
    DIRECTION INPUT ;
    USE SIGNAL ;
    PORT
      LAYER M4 ;
        RECT  0 36.864 0.192 36.888 ;
    END
  END i[334]
  PIN i[335]
    DIRECTION INPUT ;
    USE SIGNAL ;
    PORT
      LAYER M4 ;
        RECT  0 37.008 0.192 37.032 ;
    END
  END i[335]
  PIN i[336]
    DIRECTION INPUT ;
    USE SIGNAL ;
    PORT
      LAYER M4 ;
        RECT  0 37.104 0.192 37.128 ;
    END
  END i[336]
  PIN i[337]
    DIRECTION INPUT ;
    USE SIGNAL ;
    PORT
      LAYER M4 ;
        RECT  0 37.2 0.192 37.224 ;
    END
  END i[337]
  PIN i[338]
    DIRECTION INPUT ;
    USE SIGNAL ;
    PORT
      LAYER M4 ;
        RECT  0 37.296 0.192 37.32 ;
    END
  END i[338]
  PIN i[339]
    DIRECTION INPUT ;
    USE SIGNAL ;
    PORT
      LAYER M4 ;
        RECT  0 37.392 0.192 37.416 ;
    END
  END i[339]
  PIN i[33]
    DIRECTION INPUT ;
    USE SIGNAL ;
    PORT
      LAYER M4 ;
        RECT  0 5.664 0.192 5.688 ;
    END
  END i[33]
  PIN i[340]
    DIRECTION INPUT ;
    USE SIGNAL ;
    PORT
      LAYER M4 ;
        RECT  0 37.488 0.192 37.512 ;
    END
  END i[340]
  PIN i[341]
    DIRECTION INPUT ;
    USE SIGNAL ;
    PORT
      LAYER M4 ;
        RECT  0 37.632 0.192 37.656 ;
    END
  END i[341]
  PIN i[342]
    DIRECTION INPUT ;
    USE SIGNAL ;
    PORT
      LAYER M4 ;
        RECT  0 37.728 0.192 37.752 ;
    END
  END i[342]
  PIN i[343]
    DIRECTION INPUT ;
    USE SIGNAL ;
    PORT
      LAYER M4 ;
        RECT  0 37.824 0.192 37.848 ;
    END
  END i[343]
  PIN i[344]
    DIRECTION INPUT ;
    USE SIGNAL ;
    PORT
      LAYER M4 ;
        RECT  0 37.92 0.192 37.944 ;
    END
  END i[344]
  PIN i[345]
    DIRECTION INPUT ;
    USE SIGNAL ;
    PORT
      LAYER M4 ;
        RECT  0 38.016 0.192 38.04 ;
    END
  END i[345]
  PIN i[346]
    DIRECTION INPUT ;
    USE SIGNAL ;
    PORT
      LAYER M4 ;
        RECT  0 38.112 0.192 38.136 ;
    END
  END i[346]
  PIN i[347]
    DIRECTION INPUT ;
    USE SIGNAL ;
    PORT
      LAYER M4 ;
        RECT  0 38.256 0.192 38.28 ;
    END
  END i[347]
  PIN i[348]
    DIRECTION INPUT ;
    USE SIGNAL ;
    PORT
      LAYER M4 ;
        RECT  0 38.352 0.192 38.376 ;
    END
  END i[348]
  PIN i[349]
    DIRECTION INPUT ;
    USE SIGNAL ;
    PORT
      LAYER M4 ;
        RECT  0 38.448 0.192 38.472 ;
    END
  END i[349]
  PIN i[34]
    DIRECTION INPUT ;
    USE SIGNAL ;
    PORT
      LAYER M4 ;
        RECT  0 5.76 0.192 5.784 ;
    END
  END i[34]
  PIN i[350]
    DIRECTION INPUT ;
    USE SIGNAL ;
    PORT
      LAYER M4 ;
        RECT  0 38.544 0.192 38.568 ;
    END
  END i[350]
  PIN i[351]
    DIRECTION INPUT ;
    USE SIGNAL ;
    PORT
      LAYER M4 ;
        RECT  0 38.64 0.192 38.664 ;
    END
  END i[351]
  PIN i[352]
    DIRECTION INPUT ;
    USE SIGNAL ;
    PORT
      LAYER M4 ;
        RECT  0 38.736 0.192 38.76 ;
    END
  END i[352]
  PIN i[353]
    DIRECTION INPUT ;
    USE SIGNAL ;
    PORT
      LAYER M4 ;
        RECT  0 38.832 0.192 38.856 ;
    END
  END i[353]
  PIN i[354]
    DIRECTION INPUT ;
    USE SIGNAL ;
    PORT
      LAYER M4 ;
        RECT  0 38.976 0.192 39 ;
    END
  END i[354]
  PIN i[355]
    DIRECTION INPUT ;
    USE SIGNAL ;
    PORT
      LAYER M4 ;
        RECT  0 39.072 0.192 39.096 ;
    END
  END i[355]
  PIN i[356]
    DIRECTION INPUT ;
    USE SIGNAL ;
    PORT
      LAYER M4 ;
        RECT  0 39.168 0.192 39.192 ;
    END
  END i[356]
  PIN i[357]
    DIRECTION INPUT ;
    USE SIGNAL ;
    PORT
      LAYER M4 ;
        RECT  0 39.264 0.192 39.288 ;
    END
  END i[357]
  PIN i[358]
    DIRECTION INPUT ;
    USE SIGNAL ;
    PORT
      LAYER M4 ;
        RECT  0 39.36 0.192 39.384 ;
    END
  END i[358]
  PIN i[359]
    DIRECTION INPUT ;
    USE SIGNAL ;
    PORT
      LAYER M4 ;
        RECT  0 39.456 0.192 39.48 ;
    END
  END i[359]
  PIN i[35]
    DIRECTION INPUT ;
    USE SIGNAL ;
    PORT
      LAYER M4 ;
        RECT  0 5.856 0.192 5.88 ;
    END
  END i[35]
  PIN i[360]
    DIRECTION INPUT ;
    USE SIGNAL ;
    PORT
      LAYER M4 ;
        RECT  0 39.6 0.192 39.624 ;
    END
  END i[360]
  PIN i[361]
    DIRECTION INPUT ;
    USE SIGNAL ;
    PORT
      LAYER M4 ;
        RECT  0 39.696 0.192 39.72 ;
    END
  END i[361]
  PIN i[362]
    DIRECTION INPUT ;
    USE SIGNAL ;
    PORT
      LAYER M4 ;
        RECT  0 39.792 0.192 39.816 ;
    END
  END i[362]
  PIN i[363]
    DIRECTION INPUT ;
    USE SIGNAL ;
    PORT
      LAYER M4 ;
        RECT  0 39.888 0.192 39.912 ;
    END
  END i[363]
  PIN i[364]
    DIRECTION INPUT ;
    USE SIGNAL ;
    PORT
      LAYER M4 ;
        RECT  0 39.984 0.192 40.008 ;
    END
  END i[364]
  PIN i[365]
    DIRECTION INPUT ;
    USE SIGNAL ;
    PORT
      LAYER M4 ;
        RECT  0 40.08 0.192 40.104 ;
    END
  END i[365]
  PIN i[366]
    DIRECTION INPUT ;
    USE SIGNAL ;
    PORT
      LAYER M4 ;
        RECT  0 40.224 0.192 40.248 ;
    END
  END i[366]
  PIN i[367]
    DIRECTION INPUT ;
    USE SIGNAL ;
    PORT
      LAYER M4 ;
        RECT  0 40.32 0.192 40.344 ;
    END
  END i[367]
  PIN i[368]
    DIRECTION INPUT ;
    USE SIGNAL ;
    PORT
      LAYER M4 ;
        RECT  0 40.416 0.192 40.44 ;
    END
  END i[368]
  PIN i[369]
    DIRECTION INPUT ;
    USE SIGNAL ;
    PORT
      LAYER M4 ;
        RECT  0 40.512 0.192 40.536 ;
    END
  END i[369]
  PIN i[36]
    DIRECTION INPUT ;
    USE SIGNAL ;
    PORT
      LAYER M4 ;
        RECT  0 5.952 0.192 5.976 ;
    END
  END i[36]
  PIN i[370]
    DIRECTION INPUT ;
    USE SIGNAL ;
    PORT
      LAYER M4 ;
        RECT  0 40.608 0.192 40.632 ;
    END
  END i[370]
  PIN i[371]
    DIRECTION INPUT ;
    USE SIGNAL ;
    PORT
      LAYER M4 ;
        RECT  0 40.704 0.192 40.728 ;
    END
  END i[371]
  PIN i[372]
    DIRECTION INPUT ;
    USE SIGNAL ;
    PORT
      LAYER M4 ;
        RECT  0 40.848 0.192 40.872 ;
    END
  END i[372]
  PIN i[373]
    DIRECTION INPUT ;
    USE SIGNAL ;
    PORT
      LAYER M4 ;
        RECT  0 40.944 0.192 40.968 ;
    END
  END i[373]
  PIN i[374]
    DIRECTION INPUT ;
    USE SIGNAL ;
    PORT
      LAYER M4 ;
        RECT  0 41.04 0.192 41.064 ;
    END
  END i[374]
  PIN i[375]
    DIRECTION INPUT ;
    USE SIGNAL ;
    PORT
      LAYER M4 ;
        RECT  0 41.136 0.192 41.16 ;
    END
  END i[375]
  PIN i[376]
    DIRECTION INPUT ;
    USE SIGNAL ;
    PORT
      LAYER M4 ;
        RECT  0 41.232 0.192 41.256 ;
    END
  END i[376]
  PIN i[377]
    DIRECTION INPUT ;
    USE SIGNAL ;
    PORT
      LAYER M4 ;
        RECT  0 41.328 0.192 41.352 ;
    END
  END i[377]
  PIN i[378]
    DIRECTION INPUT ;
    USE SIGNAL ;
    PORT
      LAYER M4 ;
        RECT  0 41.472 0.192 41.496 ;
    END
  END i[378]
  PIN i[379]
    DIRECTION INPUT ;
    USE SIGNAL ;
    PORT
      LAYER M4 ;
        RECT  0 41.568 0.192 41.592 ;
    END
  END i[379]
  PIN i[37]
    DIRECTION INPUT ;
    USE SIGNAL ;
    PORT
      LAYER M4 ;
        RECT  0 6.048 0.192 6.072 ;
    END
  END i[37]
  PIN i[380]
    DIRECTION INPUT ;
    USE SIGNAL ;
    PORT
      LAYER M4 ;
        RECT  0 41.664 0.192 41.688 ;
    END
  END i[380]
  PIN i[381]
    DIRECTION INPUT ;
    USE SIGNAL ;
    PORT
      LAYER M4 ;
        RECT  0 41.76 0.192 41.784 ;
    END
  END i[381]
  PIN i[382]
    DIRECTION INPUT ;
    USE SIGNAL ;
    PORT
      LAYER M4 ;
        RECT  0 41.856 0.192 41.88 ;
    END
  END i[382]
  PIN i[383]
    DIRECTION INPUT ;
    USE SIGNAL ;
    PORT
      LAYER M4 ;
        RECT  0 41.952 0.192 41.976 ;
    END
  END i[383]
  PIN i[384]
    DIRECTION INPUT ;
    USE SIGNAL ;
    PORT
      LAYER M4 ;
        RECT  0 42.096 0.192 42.12 ;
    END
  END i[384]
  PIN i[385]
    DIRECTION INPUT ;
    USE SIGNAL ;
    PORT
      LAYER M4 ;
        RECT  0 42.192 0.192 42.216 ;
    END
  END i[385]
  PIN i[386]
    DIRECTION INPUT ;
    USE SIGNAL ;
    PORT
      LAYER M4 ;
        RECT  0 42.288 0.192 42.312 ;
    END
  END i[386]
  PIN i[387]
    DIRECTION INPUT ;
    USE SIGNAL ;
    PORT
      LAYER M4 ;
        RECT  0 42.384 0.192 42.408 ;
    END
  END i[387]
  PIN i[388]
    DIRECTION INPUT ;
    USE SIGNAL ;
    PORT
      LAYER M4 ;
        RECT  0 42.48 0.192 42.504 ;
    END
  END i[388]
  PIN i[389]
    DIRECTION INPUT ;
    USE SIGNAL ;
    PORT
      LAYER M4 ;
        RECT  0 42.576 0.192 42.6 ;
    END
  END i[389]
  PIN i[38]
    DIRECTION INPUT ;
    USE SIGNAL ;
    PORT
      LAYER M4 ;
        RECT  0 6.144 0.192 6.168 ;
    END
  END i[38]
  PIN i[390]
    DIRECTION INPUT ;
    USE SIGNAL ;
    PORT
      LAYER M4 ;
        RECT  0 42.672 0.192 42.696 ;
    END
  END i[390]
  PIN i[391]
    DIRECTION INPUT ;
    USE SIGNAL ;
    PORT
      LAYER M4 ;
        RECT  0 42.816 0.192 42.84 ;
    END
  END i[391]
  PIN i[392]
    DIRECTION INPUT ;
    USE SIGNAL ;
    PORT
      LAYER M4 ;
        RECT  0 42.912 0.192 42.936 ;
    END
  END i[392]
  PIN i[393]
    DIRECTION INPUT ;
    USE SIGNAL ;
    PORT
      LAYER M4 ;
        RECT  0 43.008 0.192 43.032 ;
    END
  END i[393]
  PIN i[394]
    DIRECTION INPUT ;
    USE SIGNAL ;
    PORT
      LAYER M4 ;
        RECT  0 43.104 0.192 43.128 ;
    END
  END i[394]
  PIN i[395]
    DIRECTION INPUT ;
    USE SIGNAL ;
    PORT
      LAYER M4 ;
        RECT  0 43.2 0.192 43.224 ;
    END
  END i[395]
  PIN i[396]
    DIRECTION INPUT ;
    USE SIGNAL ;
    PORT
      LAYER M4 ;
        RECT  0 43.296 0.192 43.32 ;
    END
  END i[396]
  PIN i[397]
    DIRECTION INPUT ;
    USE SIGNAL ;
    PORT
      LAYER M4 ;
        RECT  0 43.44 0.192 43.464 ;
    END
  END i[397]
  PIN i[398]
    DIRECTION INPUT ;
    USE SIGNAL ;
    PORT
      LAYER M4 ;
        RECT  0 43.536 0.192 43.56 ;
    END
  END i[398]
  PIN i[399]
    DIRECTION INPUT ;
    USE SIGNAL ;
    PORT
      LAYER M4 ;
        RECT  0 43.632 0.192 43.656 ;
    END
  END i[399]
  PIN i[39]
    DIRECTION INPUT ;
    USE SIGNAL ;
    PORT
      LAYER M4 ;
        RECT  0 6.288 0.192 6.312 ;
    END
  END i[39]
  PIN i[3]
    DIRECTION INPUT ;
    USE SIGNAL ;
    PORT
      LAYER M4 ;
        RECT  0 2.544 0.192 2.568 ;
    END
  END i[3]
  PIN i[400]
    DIRECTION INPUT ;
    USE SIGNAL ;
    PORT
      LAYER M4 ;
        RECT  0 43.728 0.192 43.752 ;
    END
  END i[400]
  PIN i[401]
    DIRECTION INPUT ;
    USE SIGNAL ;
    PORT
      LAYER M4 ;
        RECT  0 43.824 0.192 43.848 ;
    END
  END i[401]
  PIN i[402]
    DIRECTION INPUT ;
    USE SIGNAL ;
    PORT
      LAYER M4 ;
        RECT  0 43.92 0.192 43.944 ;
    END
  END i[402]
  PIN i[403]
    DIRECTION INPUT ;
    USE SIGNAL ;
    PORT
      LAYER M4 ;
        RECT  0 44.064 0.192 44.088 ;
    END
  END i[403]
  PIN i[404]
    DIRECTION INPUT ;
    USE SIGNAL ;
    PORT
      LAYER M4 ;
        RECT  0 44.16 0.192 44.184 ;
    END
  END i[404]
  PIN i[405]
    DIRECTION INPUT ;
    USE SIGNAL ;
    PORT
      LAYER M4 ;
        RECT  0 44.256 0.192 44.28 ;
    END
  END i[405]
  PIN i[406]
    DIRECTION INPUT ;
    USE SIGNAL ;
    PORT
      LAYER M4 ;
        RECT  0 44.352 0.192 44.376 ;
    END
  END i[406]
  PIN i[407]
    DIRECTION INPUT ;
    USE SIGNAL ;
    PORT
      LAYER M4 ;
        RECT  0 44.448 0.192 44.472 ;
    END
  END i[407]
  PIN i[408]
    DIRECTION INPUT ;
    USE SIGNAL ;
    PORT
      LAYER M4 ;
        RECT  0 44.544 0.192 44.568 ;
    END
  END i[408]
  PIN i[409]
    DIRECTION INPUT ;
    USE SIGNAL ;
    PORT
      LAYER M4 ;
        RECT  0 44.688 0.192 44.712 ;
    END
  END i[409]
  PIN i[40]
    DIRECTION INPUT ;
    USE SIGNAL ;
    PORT
      LAYER M4 ;
        RECT  0 6.384 0.192 6.408 ;
    END
  END i[40]
  PIN i[410]
    DIRECTION INPUT ;
    USE SIGNAL ;
    PORT
      LAYER M4 ;
        RECT  0 44.784 0.192 44.808 ;
    END
  END i[410]
  PIN i[411]
    DIRECTION INPUT ;
    USE SIGNAL ;
    PORT
      LAYER M4 ;
        RECT  0 44.88 0.192 44.904 ;
    END
  END i[411]
  PIN i[412]
    DIRECTION INPUT ;
    USE SIGNAL ;
    PORT
      LAYER M4 ;
        RECT  0 44.976 0.192 45 ;
    END
  END i[412]
  PIN i[413]
    DIRECTION INPUT ;
    USE SIGNAL ;
    PORT
      LAYER M4 ;
        RECT  0 45.072 0.192 45.096 ;
    END
  END i[413]
  PIN i[414]
    DIRECTION INPUT ;
    USE SIGNAL ;
    PORT
      LAYER M4 ;
        RECT  0 45.168 0.192 45.192 ;
    END
  END i[414]
  PIN i[415]
    DIRECTION INPUT ;
    USE SIGNAL ;
    PORT
      LAYER M4 ;
        RECT  0 45.312 0.192 45.336 ;
    END
  END i[415]
  PIN i[416]
    DIRECTION INPUT ;
    USE SIGNAL ;
    PORT
      LAYER M4 ;
        RECT  0 45.408 0.192 45.432 ;
    END
  END i[416]
  PIN i[417]
    DIRECTION INPUT ;
    USE SIGNAL ;
    PORT
      LAYER M4 ;
        RECT  0 45.504 0.192 45.528 ;
    END
  END i[417]
  PIN i[418]
    DIRECTION INPUT ;
    USE SIGNAL ;
    PORT
      LAYER M4 ;
        RECT  0 45.6 0.192 45.624 ;
    END
  END i[418]
  PIN i[419]
    DIRECTION INPUT ;
    USE SIGNAL ;
    PORT
      LAYER M4 ;
        RECT  0 45.696 0.192 45.72 ;
    END
  END i[419]
  PIN i[41]
    DIRECTION INPUT ;
    USE SIGNAL ;
    PORT
      LAYER M4 ;
        RECT  0 6.48 0.192 6.504 ;
    END
  END i[41]
  PIN i[420]
    DIRECTION INPUT ;
    USE SIGNAL ;
    PORT
      LAYER M4 ;
        RECT  0 45.792 0.192 45.816 ;
    END
  END i[420]
  PIN i[421]
    DIRECTION INPUT ;
    USE SIGNAL ;
    PORT
      LAYER M4 ;
        RECT  0 45.936 0.192 45.96 ;
    END
  END i[421]
  PIN i[422]
    DIRECTION INPUT ;
    USE SIGNAL ;
    PORT
      LAYER M4 ;
        RECT  0 46.032 0.192 46.056 ;
    END
  END i[422]
  PIN i[423]
    DIRECTION INPUT ;
    USE SIGNAL ;
    PORT
      LAYER M4 ;
        RECT  0 46.128 0.192 46.152 ;
    END
  END i[423]
  PIN i[424]
    DIRECTION INPUT ;
    USE SIGNAL ;
    PORT
      LAYER M4 ;
        RECT  0 46.224 0.192 46.248 ;
    END
  END i[424]
  PIN i[425]
    DIRECTION INPUT ;
    USE SIGNAL ;
    PORT
      LAYER M4 ;
        RECT  0 46.32 0.192 46.344 ;
    END
  END i[425]
  PIN i[426]
    DIRECTION INPUT ;
    USE SIGNAL ;
    PORT
      LAYER M4 ;
        RECT  0 46.416 0.192 46.44 ;
    END
  END i[426]
  PIN i[427]
    DIRECTION INPUT ;
    USE SIGNAL ;
    PORT
      LAYER M4 ;
        RECT  0 46.512 0.192 46.536 ;
    END
  END i[427]
  PIN i[428]
    DIRECTION INPUT ;
    USE SIGNAL ;
    PORT
      LAYER M4 ;
        RECT  0 46.656 0.192 46.68 ;
    END
  END i[428]
  PIN i[429]
    DIRECTION INPUT ;
    USE SIGNAL ;
    PORT
      LAYER M4 ;
        RECT  0 46.752 0.192 46.776 ;
    END
  END i[429]
  PIN i[42]
    DIRECTION INPUT ;
    USE SIGNAL ;
    PORT
      LAYER M4 ;
        RECT  0 6.576 0.192 6.6 ;
    END
  END i[42]
  PIN i[430]
    DIRECTION INPUT ;
    USE SIGNAL ;
    PORT
      LAYER M4 ;
        RECT  0 46.848 0.192 46.872 ;
    END
  END i[430]
  PIN i[431]
    DIRECTION INPUT ;
    USE SIGNAL ;
    PORT
      LAYER M4 ;
        RECT  0 46.944 0.192 46.968 ;
    END
  END i[431]
  PIN i[432]
    DIRECTION INPUT ;
    USE SIGNAL ;
    PORT
      LAYER M4 ;
        RECT  0 47.04 0.192 47.064 ;
    END
  END i[432]
  PIN i[433]
    DIRECTION INPUT ;
    USE SIGNAL ;
    PORT
      LAYER M4 ;
        RECT  0 47.136 0.192 47.16 ;
    END
  END i[433]
  PIN i[434]
    DIRECTION INPUT ;
    USE SIGNAL ;
    PORT
      LAYER M4 ;
        RECT  0 47.28 0.192 47.304 ;
    END
  END i[434]
  PIN i[435]
    DIRECTION INPUT ;
    USE SIGNAL ;
    PORT
      LAYER M4 ;
        RECT  0 47.376 0.192 47.4 ;
    END
  END i[435]
  PIN i[436]
    DIRECTION INPUT ;
    USE SIGNAL ;
    PORT
      LAYER M4 ;
        RECT  0 47.472 0.192 47.496 ;
    END
  END i[436]
  PIN i[437]
    DIRECTION INPUT ;
    USE SIGNAL ;
    PORT
      LAYER M4 ;
        RECT  0 47.568 0.192 47.592 ;
    END
  END i[437]
  PIN i[438]
    DIRECTION INPUT ;
    USE SIGNAL ;
    PORT
      LAYER M4 ;
        RECT  0 47.664 0.192 47.688 ;
    END
  END i[438]
  PIN i[439]
    DIRECTION INPUT ;
    USE SIGNAL ;
    PORT
      LAYER M4 ;
        RECT  0 47.76 0.192 47.784 ;
    END
  END i[439]
  PIN i[43]
    DIRECTION INPUT ;
    USE SIGNAL ;
    PORT
      LAYER M4 ;
        RECT  0 6.672 0.192 6.696 ;
    END
  END i[43]
  PIN i[440]
    DIRECTION INPUT ;
    USE SIGNAL ;
    PORT
      LAYER M4 ;
        RECT  0 47.904 0.192 47.928 ;
    END
  END i[440]
  PIN i[441]
    DIRECTION INPUT ;
    USE SIGNAL ;
    PORT
      LAYER M4 ;
        RECT  0 48 0.192 48.024 ;
    END
  END i[441]
  PIN i[442]
    DIRECTION INPUT ;
    USE SIGNAL ;
    PORT
      LAYER M4 ;
        RECT  0 48.096 0.192 48.12 ;
    END
  END i[442]
  PIN i[443]
    DIRECTION INPUT ;
    USE SIGNAL ;
    PORT
      LAYER M4 ;
        RECT  0 48.192 0.192 48.216 ;
    END
  END i[443]
  PIN i[444]
    DIRECTION INPUT ;
    USE SIGNAL ;
    PORT
      LAYER M4 ;
        RECT  0 48.288 0.192 48.312 ;
    END
  END i[444]
  PIN i[445]
    DIRECTION INPUT ;
    USE SIGNAL ;
    PORT
      LAYER M4 ;
        RECT  0 48.384 0.192 48.408 ;
    END
  END i[445]
  PIN i[446]
    DIRECTION INPUT ;
    USE SIGNAL ;
    PORT
      LAYER M4 ;
        RECT  0 48.528 0.192 48.552 ;
    END
  END i[446]
  PIN i[447]
    DIRECTION INPUT ;
    USE SIGNAL ;
    PORT
      LAYER M4 ;
        RECT  0 48.624 0.192 48.648 ;
    END
  END i[447]
  PIN i[448]
    DIRECTION INPUT ;
    USE SIGNAL ;
    PORT
      LAYER M4 ;
        RECT  0 48.72 0.192 48.744 ;
    END
  END i[448]
  PIN i[449]
    DIRECTION INPUT ;
    USE SIGNAL ;
    PORT
      LAYER M4 ;
        RECT  0 48.816 0.192 48.84 ;
    END
  END i[449]
  PIN i[44]
    DIRECTION INPUT ;
    USE SIGNAL ;
    PORT
      LAYER M4 ;
        RECT  0 6.768 0.192 6.792 ;
    END
  END i[44]
  PIN i[450]
    DIRECTION INPUT ;
    USE SIGNAL ;
    PORT
      LAYER M4 ;
        RECT  0 48.912 0.192 48.936 ;
    END
  END i[450]
  PIN i[451]
    DIRECTION INPUT ;
    USE SIGNAL ;
    PORT
      LAYER M4 ;
        RECT  0 49.008 0.192 49.032 ;
    END
  END i[451]
  PIN i[452]
    DIRECTION INPUT ;
    USE SIGNAL ;
    PORT
      LAYER M4 ;
        RECT  0 49.152 0.192 49.176 ;
    END
  END i[452]
  PIN i[453]
    DIRECTION INPUT ;
    USE SIGNAL ;
    PORT
      LAYER M4 ;
        RECT  0 49.248 0.192 49.272 ;
    END
  END i[453]
  PIN i[454]
    DIRECTION INPUT ;
    USE SIGNAL ;
    PORT
      LAYER M4 ;
        RECT  0 49.344 0.192 49.368 ;
    END
  END i[454]
  PIN i[455]
    DIRECTION INPUT ;
    USE SIGNAL ;
    PORT
      LAYER M4 ;
        RECT  0 49.44 0.192 49.464 ;
    END
  END i[455]
  PIN i[456]
    DIRECTION INPUT ;
    USE SIGNAL ;
    PORT
      LAYER M4 ;
        RECT  0 49.536 0.192 49.56 ;
    END
  END i[456]
  PIN i[457]
    DIRECTION INPUT ;
    USE SIGNAL ;
    PORT
      LAYER M4 ;
        RECT  0 49.632 0.192 49.656 ;
    END
  END i[457]
  PIN i[458]
    DIRECTION INPUT ;
    USE SIGNAL ;
    PORT
      LAYER M4 ;
        RECT  0 49.728 0.192 49.752 ;
    END
  END i[458]
  PIN i[459]
    DIRECTION INPUT ;
    USE SIGNAL ;
    PORT
      LAYER M4 ;
        RECT  0 49.872 0.192 49.896 ;
    END
  END i[459]
  PIN i[45]
    DIRECTION INPUT ;
    USE SIGNAL ;
    PORT
      LAYER M4 ;
        RECT  0 6.912 0.192 6.936 ;
    END
  END i[45]
  PIN i[460]
    DIRECTION INPUT ;
    USE SIGNAL ;
    PORT
      LAYER M4 ;
        RECT  0 49.968 0.192 49.992 ;
    END
  END i[460]
  PIN i[461]
    DIRECTION INPUT ;
    USE SIGNAL ;
    PORT
      LAYER M4 ;
        RECT  0 50.064 0.192 50.088 ;
    END
  END i[461]
  PIN i[462]
    DIRECTION INPUT ;
    USE SIGNAL ;
    PORT
      LAYER M4 ;
        RECT  0 50.16 0.192 50.184 ;
    END
  END i[462]
  PIN i[463]
    DIRECTION INPUT ;
    USE SIGNAL ;
    PORT
      LAYER M4 ;
        RECT  0 50.256 0.192 50.28 ;
    END
  END i[463]
  PIN i[464]
    DIRECTION INPUT ;
    USE SIGNAL ;
    PORT
      LAYER M4 ;
        RECT  0 50.352 0.192 50.376 ;
    END
  END i[464]
  PIN i[465]
    DIRECTION INPUT ;
    USE SIGNAL ;
    PORT
      LAYER M4 ;
        RECT  0 50.496 0.192 50.52 ;
    END
  END i[465]
  PIN i[466]
    DIRECTION INPUT ;
    USE SIGNAL ;
    PORT
      LAYER M4 ;
        RECT  0 50.592 0.192 50.616 ;
    END
  END i[466]
  PIN i[467]
    DIRECTION INPUT ;
    USE SIGNAL ;
    PORT
      LAYER M4 ;
        RECT  0 50.688 0.192 50.712 ;
    END
  END i[467]
  PIN i[468]
    DIRECTION INPUT ;
    USE SIGNAL ;
    PORT
      LAYER M4 ;
        RECT  0 50.784 0.192 50.808 ;
    END
  END i[468]
  PIN i[469]
    DIRECTION INPUT ;
    USE SIGNAL ;
    PORT
      LAYER M4 ;
        RECT  0 50.88 0.192 50.904 ;
    END
  END i[469]
  PIN i[46]
    DIRECTION INPUT ;
    USE SIGNAL ;
    PORT
      LAYER M4 ;
        RECT  0 7.008 0.192 7.032 ;
    END
  END i[46]
  PIN i[470]
    DIRECTION INPUT ;
    USE SIGNAL ;
    PORT
      LAYER M4 ;
        RECT  0 50.976 0.192 51 ;
    END
  END i[470]
  PIN i[471]
    DIRECTION INPUT ;
    USE SIGNAL ;
    PORT
      LAYER M4 ;
        RECT  0 51.12 0.192 51.144 ;
    END
  END i[471]
  PIN i[472]
    DIRECTION INPUT ;
    USE SIGNAL ;
    PORT
      LAYER M4 ;
        RECT  0 51.216 0.192 51.24 ;
    END
  END i[472]
  PIN i[473]
    DIRECTION INPUT ;
    USE SIGNAL ;
    PORT
      LAYER M4 ;
        RECT  0 51.312 0.192 51.336 ;
    END
  END i[473]
  PIN i[474]
    DIRECTION INPUT ;
    USE SIGNAL ;
    PORT
      LAYER M4 ;
        RECT  0 51.408 0.192 51.432 ;
    END
  END i[474]
  PIN i[475]
    DIRECTION INPUT ;
    USE SIGNAL ;
    PORT
      LAYER M4 ;
        RECT  0 51.504 0.192 51.528 ;
    END
  END i[475]
  PIN i[476]
    DIRECTION INPUT ;
    USE SIGNAL ;
    PORT
      LAYER M4 ;
        RECT  0 51.6 0.192 51.624 ;
    END
  END i[476]
  PIN i[477]
    DIRECTION INPUT ;
    USE SIGNAL ;
    PORT
      LAYER M4 ;
        RECT  0 51.744 0.192 51.768 ;
    END
  END i[477]
  PIN i[478]
    DIRECTION INPUT ;
    USE SIGNAL ;
    PORT
      LAYER M4 ;
        RECT  0 51.84 0.192 51.864 ;
    END
  END i[478]
  PIN i[479]
    DIRECTION INPUT ;
    USE SIGNAL ;
    PORT
      LAYER M4 ;
        RECT  0 51.936 0.192 51.96 ;
    END
  END i[479]
  PIN i[47]
    DIRECTION INPUT ;
    USE SIGNAL ;
    PORT
      LAYER M4 ;
        RECT  0 7.104 0.192 7.128 ;
    END
  END i[47]
  PIN i[480]
    DIRECTION INPUT ;
    USE SIGNAL ;
    PORT
      LAYER M4 ;
        RECT  0 52.032 0.192 52.056 ;
    END
  END i[480]
  PIN i[481]
    DIRECTION INPUT ;
    USE SIGNAL ;
    PORT
      LAYER M4 ;
        RECT  0 52.128 0.192 52.152 ;
    END
  END i[481]
  PIN i[482]
    DIRECTION INPUT ;
    USE SIGNAL ;
    PORT
      LAYER M4 ;
        RECT  0 52.224 0.192 52.248 ;
    END
  END i[482]
  PIN i[483]
    DIRECTION INPUT ;
    USE SIGNAL ;
    PORT
      LAYER M4 ;
        RECT  0 52.368 0.192 52.392 ;
    END
  END i[483]
  PIN i[484]
    DIRECTION INPUT ;
    USE SIGNAL ;
    PORT
      LAYER M4 ;
        RECT  0 52.464 0.192 52.488 ;
    END
  END i[484]
  PIN i[485]
    DIRECTION INPUT ;
    USE SIGNAL ;
    PORT
      LAYER M4 ;
        RECT  0 52.56 0.192 52.584 ;
    END
  END i[485]
  PIN i[486]
    DIRECTION INPUT ;
    USE SIGNAL ;
    PORT
      LAYER M4 ;
        RECT  0 52.656 0.192 52.68 ;
    END
  END i[486]
  PIN i[487]
    DIRECTION INPUT ;
    USE SIGNAL ;
    PORT
      LAYER M4 ;
        RECT  0 52.752 0.192 52.776 ;
    END
  END i[487]
  PIN i[488]
    DIRECTION INPUT ;
    USE SIGNAL ;
    PORT
      LAYER M4 ;
        RECT  0 52.848 0.192 52.872 ;
    END
  END i[488]
  PIN i[489]
    DIRECTION INPUT ;
    USE SIGNAL ;
    PORT
      LAYER M4 ;
        RECT  0 52.992 0.192 53.016 ;
    END
  END i[489]
  PIN i[48]
    DIRECTION INPUT ;
    USE SIGNAL ;
    PORT
      LAYER M4 ;
        RECT  0 7.2 0.192 7.224 ;
    END
  END i[48]
  PIN i[490]
    DIRECTION INPUT ;
    USE SIGNAL ;
    PORT
      LAYER M4 ;
        RECT  0 53.088 0.192 53.112 ;
    END
  END i[490]
  PIN i[491]
    DIRECTION INPUT ;
    USE SIGNAL ;
    PORT
      LAYER M4 ;
        RECT  0 53.184 0.192 53.208 ;
    END
  END i[491]
  PIN i[492]
    DIRECTION INPUT ;
    USE SIGNAL ;
    PORT
      LAYER M4 ;
        RECT  0 53.28 0.192 53.304 ;
    END
  END i[492]
  PIN i[493]
    DIRECTION INPUT ;
    USE SIGNAL ;
    PORT
      LAYER M4 ;
        RECT  0 53.376 0.192 53.4 ;
    END
  END i[493]
  PIN i[494]
    DIRECTION INPUT ;
    USE SIGNAL ;
    PORT
      LAYER M4 ;
        RECT  0 53.472 0.192 53.496 ;
    END
  END i[494]
  PIN i[495]
    DIRECTION INPUT ;
    USE SIGNAL ;
    PORT
      LAYER M4 ;
        RECT  0 53.568 0.192 53.592 ;
    END
  END i[495]
  PIN i[496]
    DIRECTION INPUT ;
    USE SIGNAL ;
    PORT
      LAYER M4 ;
        RECT  0 53.712 0.192 53.736 ;
    END
  END i[496]
  PIN i[497]
    DIRECTION INPUT ;
    USE SIGNAL ;
    PORT
      LAYER M4 ;
        RECT  0 53.808 0.192 53.832 ;
    END
  END i[497]
  PIN i[498]
    DIRECTION INPUT ;
    USE SIGNAL ;
    PORT
      LAYER M4 ;
        RECT  0 53.904 0.192 53.928 ;
    END
  END i[498]
  PIN i[499]
    DIRECTION INPUT ;
    USE SIGNAL ;
    PORT
      LAYER M4 ;
        RECT  0 54 0.192 54.024 ;
    END
  END i[499]
  PIN i[49]
    DIRECTION INPUT ;
    USE SIGNAL ;
    PORT
      LAYER M4 ;
        RECT  0 7.296 0.192 7.32 ;
    END
  END i[49]
  PIN i[4]
    DIRECTION INPUT ;
    USE SIGNAL ;
    PORT
      LAYER M4 ;
        RECT  0 2.64 0.192 2.664 ;
    END
  END i[4]
  PIN i[500]
    DIRECTION INPUT ;
    USE SIGNAL ;
    PORT
      LAYER M4 ;
        RECT  0 54.096 0.192 54.12 ;
    END
  END i[500]
  PIN i[501]
    DIRECTION INPUT ;
    USE SIGNAL ;
    PORT
      LAYER M4 ;
        RECT  0 54.192 0.192 54.216 ;
    END
  END i[501]
  PIN i[502]
    DIRECTION INPUT ;
    USE SIGNAL ;
    PORT
      LAYER M4 ;
        RECT  0 54.336 0.192 54.36 ;
    END
  END i[502]
  PIN i[503]
    DIRECTION INPUT ;
    USE SIGNAL ;
    PORT
      LAYER M4 ;
        RECT  0 54.432 0.192 54.456 ;
    END
  END i[503]
  PIN i[504]
    DIRECTION INPUT ;
    USE SIGNAL ;
    PORT
      LAYER M4 ;
        RECT  0 54.528 0.192 54.552 ;
    END
  END i[504]
  PIN i[505]
    DIRECTION INPUT ;
    USE SIGNAL ;
    PORT
      LAYER M4 ;
        RECT  0 54.624 0.192 54.648 ;
    END
  END i[505]
  PIN i[506]
    DIRECTION INPUT ;
    USE SIGNAL ;
    PORT
      LAYER M4 ;
        RECT  0 54.72 0.192 54.744 ;
    END
  END i[506]
  PIN i[507]
    DIRECTION INPUT ;
    USE SIGNAL ;
    PORT
      LAYER M4 ;
        RECT  0 54.816 0.192 54.84 ;
    END
  END i[507]
  PIN i[508]
    DIRECTION INPUT ;
    USE SIGNAL ;
    PORT
      LAYER M4 ;
        RECT  0 54.96 0.192 54.984 ;
    END
  END i[508]
  PIN i[509]
    DIRECTION INPUT ;
    USE SIGNAL ;
    PORT
      LAYER M4 ;
        RECT  0 55.056 0.192 55.08 ;
    END
  END i[509]
  PIN i[50]
    DIRECTION INPUT ;
    USE SIGNAL ;
    PORT
      LAYER M4 ;
        RECT  0 7.392 0.192 7.416 ;
    END
  END i[50]
  PIN i[510]
    DIRECTION INPUT ;
    USE SIGNAL ;
    PORT
      LAYER M4 ;
        RECT  0 55.152 0.192 55.176 ;
    END
  END i[510]
  PIN i[511]
    DIRECTION INPUT ;
    USE SIGNAL ;
    PORT
      LAYER M4 ;
        RECT  0 55.248 0.192 55.272 ;
    END
  END i[511]
  PIN i[512]
    DIRECTION INPUT ;
    USE SIGNAL ;
    PORT
      LAYER M4 ;
        RECT  0 55.344 0.192 55.368 ;
    END
  END i[512]
  PIN i[513]
    DIRECTION INPUT ;
    USE SIGNAL ;
    PORT
      LAYER M4 ;
        RECT  0 55.44 0.192 55.464 ;
    END
  END i[513]
  PIN i[514]
    DIRECTION INPUT ;
    USE SIGNAL ;
    PORT
      LAYER M4 ;
        RECT  0 55.584 0.192 55.608 ;
    END
  END i[514]
  PIN i[515]
    DIRECTION INPUT ;
    USE SIGNAL ;
    PORT
      LAYER M4 ;
        RECT  0 55.68 0.192 55.704 ;
    END
  END i[515]
  PIN i[516]
    DIRECTION INPUT ;
    USE SIGNAL ;
    PORT
      LAYER M4 ;
        RECT  0 55.776 0.192 55.8 ;
    END
  END i[516]
  PIN i[517]
    DIRECTION INPUT ;
    USE SIGNAL ;
    PORT
      LAYER M4 ;
        RECT  0 55.872 0.192 55.896 ;
    END
  END i[517]
  PIN i[518]
    DIRECTION INPUT ;
    USE SIGNAL ;
    PORT
      LAYER M4 ;
        RECT  0 55.968 0.192 55.992 ;
    END
  END i[518]
  PIN i[519]
    DIRECTION INPUT ;
    USE SIGNAL ;
    PORT
      LAYER M4 ;
        RECT  0 56.064 0.192 56.088 ;
    END
  END i[519]
  PIN i[51]
    DIRECTION INPUT ;
    USE SIGNAL ;
    PORT
      LAYER M4 ;
        RECT  0 7.536 0.192 7.56 ;
    END
  END i[51]
  PIN i[520]
    DIRECTION INPUT ;
    USE SIGNAL ;
    PORT
      LAYER M4 ;
        RECT  0 56.208 0.192 56.232 ;
    END
  END i[520]
  PIN i[521]
    DIRECTION INPUT ;
    USE SIGNAL ;
    PORT
      LAYER M4 ;
        RECT  0 56.304 0.192 56.328 ;
    END
  END i[521]
  PIN i[522]
    DIRECTION INPUT ;
    USE SIGNAL ;
    PORT
      LAYER M4 ;
        RECT  0 56.4 0.192 56.424 ;
    END
  END i[522]
  PIN i[523]
    DIRECTION INPUT ;
    USE SIGNAL ;
    PORT
      LAYER M4 ;
        RECT  0 56.496 0.192 56.52 ;
    END
  END i[523]
  PIN i[524]
    DIRECTION INPUT ;
    USE SIGNAL ;
    PORT
      LAYER M4 ;
        RECT  0 56.592 0.192 56.616 ;
    END
  END i[524]
  PIN i[525]
    DIRECTION INPUT ;
    USE SIGNAL ;
    PORT
      LAYER M4 ;
        RECT  0 56.688 0.192 56.712 ;
    END
  END i[525]
  PIN i[526]
    DIRECTION INPUT ;
    USE SIGNAL ;
    PORT
      LAYER M4 ;
        RECT  0 56.832 0.192 56.856 ;
    END
  END i[526]
  PIN i[527]
    DIRECTION INPUT ;
    USE SIGNAL ;
    PORT
      LAYER M4 ;
        RECT  0 56.928 0.192 56.952 ;
    END
  END i[527]
  PIN i[528]
    DIRECTION INPUT ;
    USE SIGNAL ;
    PORT
      LAYER M4 ;
        RECT  0 57.024 0.192 57.048 ;
    END
  END i[528]
  PIN i[529]
    DIRECTION INPUT ;
    USE SIGNAL ;
    PORT
      LAYER M4 ;
        RECT  0 57.12 0.192 57.144 ;
    END
  END i[529]
  PIN i[52]
    DIRECTION INPUT ;
    USE SIGNAL ;
    PORT
      LAYER M4 ;
        RECT  0 7.632 0.192 7.656 ;
    END
  END i[52]
  PIN i[530]
    DIRECTION INPUT ;
    USE SIGNAL ;
    PORT
      LAYER M4 ;
        RECT  0 57.216 0.192 57.24 ;
    END
  END i[530]
  PIN i[531]
    DIRECTION INPUT ;
    USE SIGNAL ;
    PORT
      LAYER M4 ;
        RECT  0 57.312 0.192 57.336 ;
    END
  END i[531]
  PIN i[532]
    DIRECTION INPUT ;
    USE SIGNAL ;
    PORT
      LAYER M4 ;
        RECT  0 57.408 0.192 57.432 ;
    END
  END i[532]
  PIN i[533]
    DIRECTION INPUT ;
    USE SIGNAL ;
    PORT
      LAYER M4 ;
        RECT  0 57.552 0.192 57.576 ;
    END
  END i[533]
  PIN i[534]
    DIRECTION INPUT ;
    USE SIGNAL ;
    PORT
      LAYER M4 ;
        RECT  0 57.648 0.192 57.672 ;
    END
  END i[534]
  PIN i[535]
    DIRECTION INPUT ;
    USE SIGNAL ;
    PORT
      LAYER M4 ;
        RECT  0 57.744 0.192 57.768 ;
    END
  END i[535]
  PIN i[536]
    DIRECTION INPUT ;
    USE SIGNAL ;
    PORT
      LAYER M4 ;
        RECT  0 57.84 0.192 57.864 ;
    END
  END i[536]
  PIN i[537]
    DIRECTION INPUT ;
    USE SIGNAL ;
    PORT
      LAYER M4 ;
        RECT  0 57.936 0.192 57.96 ;
    END
  END i[537]
  PIN i[538]
    DIRECTION INPUT ;
    USE SIGNAL ;
    PORT
      LAYER M4 ;
        RECT  0 58.032 0.192 58.056 ;
    END
  END i[538]
  PIN i[539]
    DIRECTION INPUT ;
    USE SIGNAL ;
    PORT
      LAYER M4 ;
        RECT  0 58.176 0.192 58.2 ;
    END
  END i[539]
  PIN i[53]
    DIRECTION INPUT ;
    USE SIGNAL ;
    PORT
      LAYER M4 ;
        RECT  0 7.728 0.192 7.752 ;
    END
  END i[53]
  PIN i[540]
    DIRECTION INPUT ;
    USE SIGNAL ;
    PORT
      LAYER M4 ;
        RECT  0 58.272 0.192 58.296 ;
    END
  END i[540]
  PIN i[541]
    DIRECTION INPUT ;
    USE SIGNAL ;
    PORT
      LAYER M4 ;
        RECT  0 58.368 0.192 58.392 ;
    END
  END i[541]
  PIN i[542]
    DIRECTION INPUT ;
    USE SIGNAL ;
    PORT
      LAYER M4 ;
        RECT  0 58.464 0.192 58.488 ;
    END
  END i[542]
  PIN i[543]
    DIRECTION INPUT ;
    USE SIGNAL ;
    PORT
      LAYER M4 ;
        RECT  0 58.56 0.192 58.584 ;
    END
  END i[543]
  PIN i[544]
    DIRECTION INPUT ;
    USE SIGNAL ;
    PORT
      LAYER M4 ;
        RECT  0 58.656 0.192 58.68 ;
    END
  END i[544]
  PIN i[545]
    DIRECTION INPUT ;
    USE SIGNAL ;
    PORT
      LAYER M4 ;
        RECT  0 58.8 0.192 58.824 ;
    END
  END i[545]
  PIN i[546]
    DIRECTION INPUT ;
    USE SIGNAL ;
    PORT
      LAYER M4 ;
        RECT  0 58.896 0.192 58.92 ;
    END
  END i[546]
  PIN i[547]
    DIRECTION INPUT ;
    USE SIGNAL ;
    PORT
      LAYER M4 ;
        RECT  0 58.992 0.192 59.016 ;
    END
  END i[547]
  PIN i[548]
    DIRECTION INPUT ;
    USE SIGNAL ;
    PORT
      LAYER M4 ;
        RECT  0 59.088 0.192 59.112 ;
    END
  END i[548]
  PIN i[549]
    DIRECTION INPUT ;
    USE SIGNAL ;
    PORT
      LAYER M4 ;
        RECT  0 59.184 0.192 59.208 ;
    END
  END i[549]
  PIN i[54]
    DIRECTION INPUT ;
    USE SIGNAL ;
    PORT
      LAYER M4 ;
        RECT  0 7.824 0.192 7.848 ;
    END
  END i[54]
  PIN i[550]
    DIRECTION INPUT ;
    USE SIGNAL ;
    PORT
      LAYER M4 ;
        RECT  0 59.28 0.192 59.304 ;
    END
  END i[550]
  PIN i[551]
    DIRECTION INPUT ;
    USE SIGNAL ;
    PORT
      LAYER M4 ;
        RECT  0 59.424 0.192 59.448 ;
    END
  END i[551]
  PIN i[552]
    DIRECTION INPUT ;
    USE SIGNAL ;
    PORT
      LAYER M4 ;
        RECT  0 59.52 0.192 59.544 ;
    END
  END i[552]
  PIN i[553]
    DIRECTION INPUT ;
    USE SIGNAL ;
    PORT
      LAYER M4 ;
        RECT  0 59.616 0.192 59.64 ;
    END
  END i[553]
  PIN i[554]
    DIRECTION INPUT ;
    USE SIGNAL ;
    PORT
      LAYER M4 ;
        RECT  0 59.712 0.192 59.736 ;
    END
  END i[554]
  PIN i[555]
    DIRECTION INPUT ;
    USE SIGNAL ;
    PORT
      LAYER M4 ;
        RECT  0 59.808 0.192 59.832 ;
    END
  END i[555]
  PIN i[556]
    DIRECTION INPUT ;
    USE SIGNAL ;
    PORT
      LAYER M4 ;
        RECT  0 59.904 0.192 59.928 ;
    END
  END i[556]
  PIN i[557]
    DIRECTION INPUT ;
    USE SIGNAL ;
    PORT
      LAYER M4 ;
        RECT  0 60.048 0.192 60.072 ;
    END
  END i[557]
  PIN i[558]
    DIRECTION INPUT ;
    USE SIGNAL ;
    PORT
      LAYER M4 ;
        RECT  0 60.144 0.192 60.168 ;
    END
  END i[558]
  PIN i[559]
    DIRECTION INPUT ;
    USE SIGNAL ;
    PORT
      LAYER M4 ;
        RECT  0 60.24 0.192 60.264 ;
    END
  END i[559]
  PIN i[55]
    DIRECTION INPUT ;
    USE SIGNAL ;
    PORT
      LAYER M4 ;
        RECT  0 7.92 0.192 7.944 ;
    END
  END i[55]
  PIN i[560]
    DIRECTION INPUT ;
    USE SIGNAL ;
    PORT
      LAYER M4 ;
        RECT  0 60.336 0.192 60.36 ;
    END
  END i[560]
  PIN i[561]
    DIRECTION INPUT ;
    USE SIGNAL ;
    PORT
      LAYER M4 ;
        RECT  0 60.432 0.192 60.456 ;
    END
  END i[561]
  PIN i[56]
    DIRECTION INPUT ;
    USE SIGNAL ;
    PORT
      LAYER M4 ;
        RECT  0 8.016 0.192 8.04 ;
    END
  END i[56]
  PIN i[57]
    DIRECTION INPUT ;
    USE SIGNAL ;
    PORT
      LAYER M4 ;
        RECT  0 8.16 0.192 8.184 ;
    END
  END i[57]
  PIN i[58]
    DIRECTION INPUT ;
    USE SIGNAL ;
    PORT
      LAYER M4 ;
        RECT  0 8.256 0.192 8.28 ;
    END
  END i[58]
  PIN i[59]
    DIRECTION INPUT ;
    USE SIGNAL ;
    PORT
      LAYER M4 ;
        RECT  0 8.352 0.192 8.376 ;
    END
  END i[59]
  PIN i[5]
    DIRECTION INPUT ;
    USE SIGNAL ;
    PORT
      LAYER M4 ;
        RECT  0 2.736 0.192 2.76 ;
    END
  END i[5]
  PIN i[60]
    DIRECTION INPUT ;
    USE SIGNAL ;
    PORT
      LAYER M4 ;
        RECT  0 8.448 0.192 8.472 ;
    END
  END i[60]
  PIN i[61]
    DIRECTION INPUT ;
    USE SIGNAL ;
    PORT
      LAYER M4 ;
        RECT  0 8.544 0.192 8.568 ;
    END
  END i[61]
  PIN i[62]
    DIRECTION INPUT ;
    USE SIGNAL ;
    PORT
      LAYER M4 ;
        RECT  0 8.64 0.192 8.664 ;
    END
  END i[62]
  PIN i[63]
    DIRECTION INPUT ;
    USE SIGNAL ;
    PORT
      LAYER M4 ;
        RECT  0 8.784 0.192 8.808 ;
    END
  END i[63]
  PIN i[64]
    DIRECTION INPUT ;
    USE SIGNAL ;
    PORT
      LAYER M4 ;
        RECT  0 8.88 0.192 8.904 ;
    END
  END i[64]
  PIN i[65]
    DIRECTION INPUT ;
    USE SIGNAL ;
    PORT
      LAYER M4 ;
        RECT  0 8.976 0.192 9 ;
    END
  END i[65]
  PIN i[66]
    DIRECTION INPUT ;
    USE SIGNAL ;
    PORT
      LAYER M4 ;
        RECT  0 9.072 0.192 9.096 ;
    END
  END i[66]
  PIN i[67]
    DIRECTION INPUT ;
    USE SIGNAL ;
    PORT
      LAYER M4 ;
        RECT  0 9.168 0.192 9.192 ;
    END
  END i[67]
  PIN i[68]
    DIRECTION INPUT ;
    USE SIGNAL ;
    PORT
      LAYER M4 ;
        RECT  0 9.264 0.192 9.288 ;
    END
  END i[68]
  PIN i[69]
    DIRECTION INPUT ;
    USE SIGNAL ;
    PORT
      LAYER M4 ;
        RECT  0 9.408 0.192 9.432 ;
    END
  END i[69]
  PIN i[6]
    DIRECTION INPUT ;
    USE SIGNAL ;
    PORT
      LAYER M4 ;
        RECT  0 2.832 0.192 2.856 ;
    END
  END i[6]
  PIN i[70]
    DIRECTION INPUT ;
    USE SIGNAL ;
    PORT
      LAYER M4 ;
        RECT  0 9.504 0.192 9.528 ;
    END
  END i[70]
  PIN i[71]
    DIRECTION INPUT ;
    USE SIGNAL ;
    PORT
      LAYER M4 ;
        RECT  0 9.6 0.192 9.624 ;
    END
  END i[71]
  PIN i[72]
    DIRECTION INPUT ;
    USE SIGNAL ;
    PORT
      LAYER M4 ;
        RECT  0 9.696 0.192 9.72 ;
    END
  END i[72]
  PIN i[73]
    DIRECTION INPUT ;
    USE SIGNAL ;
    PORT
      LAYER M4 ;
        RECT  0 9.792 0.192 9.816 ;
    END
  END i[73]
  PIN i[74]
    DIRECTION INPUT ;
    USE SIGNAL ;
    PORT
      LAYER M4 ;
        RECT  0 9.888 0.192 9.912 ;
    END
  END i[74]
  PIN i[75]
    DIRECTION INPUT ;
    USE SIGNAL ;
    PORT
      LAYER M4 ;
        RECT  0 9.984 0.192 10.008 ;
    END
  END i[75]
  PIN i[76]
    DIRECTION INPUT ;
    USE SIGNAL ;
    PORT
      LAYER M4 ;
        RECT  0 10.128 0.192 10.152 ;
    END
  END i[76]
  PIN i[77]
    DIRECTION INPUT ;
    USE SIGNAL ;
    PORT
      LAYER M4 ;
        RECT  0 10.224 0.192 10.248 ;
    END
  END i[77]
  PIN i[78]
    DIRECTION INPUT ;
    USE SIGNAL ;
    PORT
      LAYER M4 ;
        RECT  0 10.32 0.192 10.344 ;
    END
  END i[78]
  PIN i[79]
    DIRECTION INPUT ;
    USE SIGNAL ;
    PORT
      LAYER M4 ;
        RECT  0 10.416 0.192 10.44 ;
    END
  END i[79]
  PIN i[7]
    DIRECTION INPUT ;
    USE SIGNAL ;
    PORT
      LAYER M4 ;
        RECT  0 2.928 0.192 2.952 ;
    END
  END i[7]
  PIN i[80]
    DIRECTION INPUT ;
    USE SIGNAL ;
    PORT
      LAYER M4 ;
        RECT  0 10.512 0.192 10.536 ;
    END
  END i[80]
  PIN i[81]
    DIRECTION INPUT ;
    USE SIGNAL ;
    PORT
      LAYER M4 ;
        RECT  0 10.608 0.192 10.632 ;
    END
  END i[81]
  PIN i[82]
    DIRECTION INPUT ;
    USE SIGNAL ;
    PORT
      LAYER M4 ;
        RECT  0 10.752 0.192 10.776 ;
    END
  END i[82]
  PIN i[83]
    DIRECTION INPUT ;
    USE SIGNAL ;
    PORT
      LAYER M4 ;
        RECT  0 10.848 0.192 10.872 ;
    END
  END i[83]
  PIN i[84]
    DIRECTION INPUT ;
    USE SIGNAL ;
    PORT
      LAYER M4 ;
        RECT  0 10.944 0.192 10.968 ;
    END
  END i[84]
  PIN i[85]
    DIRECTION INPUT ;
    USE SIGNAL ;
    PORT
      LAYER M4 ;
        RECT  0 11.04 0.192 11.064 ;
    END
  END i[85]
  PIN i[86]
    DIRECTION INPUT ;
    USE SIGNAL ;
    PORT
      LAYER M4 ;
        RECT  0 11.136 0.192 11.16 ;
    END
  END i[86]
  PIN i[87]
    DIRECTION INPUT ;
    USE SIGNAL ;
    PORT
      LAYER M4 ;
        RECT  0 11.232 0.192 11.256 ;
    END
  END i[87]
  PIN i[88]
    DIRECTION INPUT ;
    USE SIGNAL ;
    PORT
      LAYER M4 ;
        RECT  0 11.376 0.192 11.4 ;
    END
  END i[88]
  PIN i[89]
    DIRECTION INPUT ;
    USE SIGNAL ;
    PORT
      LAYER M4 ;
        RECT  0 11.472 0.192 11.496 ;
    END
  END i[89]
  PIN i[8]
    DIRECTION INPUT ;
    USE SIGNAL ;
    PORT
      LAYER M4 ;
        RECT  0 3.072 0.192 3.096 ;
    END
  END i[8]
  PIN i[90]
    DIRECTION INPUT ;
    USE SIGNAL ;
    PORT
      LAYER M4 ;
        RECT  0 11.568 0.192 11.592 ;
    END
  END i[90]
  PIN i[91]
    DIRECTION INPUT ;
    USE SIGNAL ;
    PORT
      LAYER M4 ;
        RECT  0 11.664 0.192 11.688 ;
    END
  END i[91]
  PIN i[92]
    DIRECTION INPUT ;
    USE SIGNAL ;
    PORT
      LAYER M4 ;
        RECT  0 11.76 0.192 11.784 ;
    END
  END i[92]
  PIN i[93]
    DIRECTION INPUT ;
    USE SIGNAL ;
    PORT
      LAYER M4 ;
        RECT  0 11.856 0.192 11.88 ;
    END
  END i[93]
  PIN i[94]
    DIRECTION INPUT ;
    USE SIGNAL ;
    PORT
      LAYER M4 ;
        RECT  0 12 0.192 12.024 ;
    END
  END i[94]
  PIN i[95]
    DIRECTION INPUT ;
    USE SIGNAL ;
    PORT
      LAYER M4 ;
        RECT  0 12.096 0.192 12.12 ;
    END
  END i[95]
  PIN i[96]
    DIRECTION INPUT ;
    USE SIGNAL ;
    PORT
      LAYER M4 ;
        RECT  0 12.192 0.192 12.216 ;
    END
  END i[96]
  PIN i[97]
    DIRECTION INPUT ;
    USE SIGNAL ;
    PORT
      LAYER M4 ;
        RECT  0 12.288 0.192 12.312 ;
    END
  END i[97]
  PIN i[98]
    DIRECTION INPUT ;
    USE SIGNAL ;
    PORT
      LAYER M4 ;
        RECT  0 12.384 0.192 12.408 ;
    END
  END i[98]
  PIN i[99]
    DIRECTION INPUT ;
    USE SIGNAL ;
    PORT
      LAYER M4 ;
        RECT  0 12.48 0.192 12.504 ;
    END
  END i[99]
  PIN i[9]
    DIRECTION INPUT ;
    USE SIGNAL ;
    PORT
      LAYER M4 ;
        RECT  0 3.168 0.192 3.192 ;
    END
  END i[9]
  PIN o[0]
    DIRECTION OUTPUT ;
    USE SIGNAL ;
    PORT
      LAYER M4 ;
        RECT  17.088 2.208 17.28 2.232 ;
    END
  END o[0]
  PIN o[100]
    DIRECTION OUTPUT ;
    USE SIGNAL ;
    PORT
      LAYER M4 ;
        RECT  17.088 12.576 17.28 12.6 ;
    END
  END o[100]
  PIN o[101]
    DIRECTION OUTPUT ;
    USE SIGNAL ;
    PORT
      LAYER M4 ;
        RECT  17.088 12.672 17.28 12.696 ;
    END
  END o[101]
  PIN o[102]
    DIRECTION OUTPUT ;
    USE SIGNAL ;
    PORT
      LAYER M4 ;
        RECT  17.088 12.768 17.28 12.792 ;
    END
  END o[102]
  PIN o[103]
    DIRECTION OUTPUT ;
    USE SIGNAL ;
    PORT
      LAYER M4 ;
        RECT  17.088 12.912 17.28 12.936 ;
    END
  END o[103]
  PIN o[104]
    DIRECTION OUTPUT ;
    USE SIGNAL ;
    PORT
      LAYER M4 ;
        RECT  17.088 13.008 17.28 13.032 ;
    END
  END o[104]
  PIN o[105]
    DIRECTION OUTPUT ;
    USE SIGNAL ;
    PORT
      LAYER M4 ;
        RECT  17.088 13.104 17.28 13.128 ;
    END
  END o[105]
  PIN o[106]
    DIRECTION OUTPUT ;
    USE SIGNAL ;
    PORT
      LAYER M4 ;
        RECT  17.088 13.2 17.28 13.224 ;
    END
  END o[106]
  PIN o[107]
    DIRECTION OUTPUT ;
    USE SIGNAL ;
    PORT
      LAYER M4 ;
        RECT  17.088 13.296 17.28 13.32 ;
    END
  END o[107]
  PIN o[108]
    DIRECTION OUTPUT ;
    USE SIGNAL ;
    PORT
      LAYER M4 ;
        RECT  17.088 13.392 17.28 13.416 ;
    END
  END o[108]
  PIN o[109]
    DIRECTION OUTPUT ;
    USE SIGNAL ;
    PORT
      LAYER M4 ;
        RECT  17.088 13.536 17.28 13.56 ;
    END
  END o[109]
  PIN o[10]
    DIRECTION OUTPUT ;
    USE SIGNAL ;
    PORT
      LAYER M4 ;
        RECT  17.088 3.264 17.28 3.288 ;
    END
  END o[10]
  PIN o[110]
    DIRECTION OUTPUT ;
    USE SIGNAL ;
    PORT
      LAYER M4 ;
        RECT  17.088 13.632 17.28 13.656 ;
    END
  END o[110]
  PIN o[111]
    DIRECTION OUTPUT ;
    USE SIGNAL ;
    PORT
      LAYER M4 ;
        RECT  17.088 13.728 17.28 13.752 ;
    END
  END o[111]
  PIN o[112]
    DIRECTION OUTPUT ;
    USE SIGNAL ;
    PORT
      LAYER M4 ;
        RECT  17.088 13.824 17.28 13.848 ;
    END
  END o[112]
  PIN o[113]
    DIRECTION OUTPUT ;
    USE SIGNAL ;
    PORT
      LAYER M4 ;
        RECT  17.088 13.92 17.28 13.944 ;
    END
  END o[113]
  PIN o[114]
    DIRECTION OUTPUT ;
    USE SIGNAL ;
    PORT
      LAYER M4 ;
        RECT  17.088 14.016 17.28 14.04 ;
    END
  END o[114]
  PIN o[115]
    DIRECTION OUTPUT ;
    USE SIGNAL ;
    PORT
      LAYER M4 ;
        RECT  17.088 14.16 17.28 14.184 ;
    END
  END o[115]
  PIN o[116]
    DIRECTION OUTPUT ;
    USE SIGNAL ;
    PORT
      LAYER M4 ;
        RECT  17.088 14.256 17.28 14.28 ;
    END
  END o[116]
  PIN o[117]
    DIRECTION OUTPUT ;
    USE SIGNAL ;
    PORT
      LAYER M4 ;
        RECT  17.088 14.352 17.28 14.376 ;
    END
  END o[117]
  PIN o[118]
    DIRECTION OUTPUT ;
    USE SIGNAL ;
    PORT
      LAYER M4 ;
        RECT  17.088 14.448 17.28 14.472 ;
    END
  END o[118]
  PIN o[119]
    DIRECTION OUTPUT ;
    USE SIGNAL ;
    PORT
      LAYER M4 ;
        RECT  17.088 14.544 17.28 14.568 ;
    END
  END o[119]
  PIN o[11]
    DIRECTION OUTPUT ;
    USE SIGNAL ;
    PORT
      LAYER M4 ;
        RECT  17.088 3.36 17.28 3.384 ;
    END
  END o[11]
  PIN o[120]
    DIRECTION OUTPUT ;
    USE SIGNAL ;
    PORT
      LAYER M4 ;
        RECT  17.088 14.64 17.28 14.664 ;
    END
  END o[120]
  PIN o[121]
    DIRECTION OUTPUT ;
    USE SIGNAL ;
    PORT
      LAYER M4 ;
        RECT  17.088 14.736 17.28 14.76 ;
    END
  END o[121]
  PIN o[122]
    DIRECTION OUTPUT ;
    USE SIGNAL ;
    PORT
      LAYER M4 ;
        RECT  17.088 14.88 17.28 14.904 ;
    END
  END o[122]
  PIN o[123]
    DIRECTION OUTPUT ;
    USE SIGNAL ;
    PORT
      LAYER M4 ;
        RECT  17.088 14.976 17.28 15 ;
    END
  END o[123]
  PIN o[124]
    DIRECTION OUTPUT ;
    USE SIGNAL ;
    PORT
      LAYER M4 ;
        RECT  17.088 15.072 17.28 15.096 ;
    END
  END o[124]
  PIN o[125]
    DIRECTION OUTPUT ;
    USE SIGNAL ;
    PORT
      LAYER M4 ;
        RECT  17.088 15.168 17.28 15.192 ;
    END
  END o[125]
  PIN o[126]
    DIRECTION OUTPUT ;
    USE SIGNAL ;
    PORT
      LAYER M4 ;
        RECT  17.088 15.264 17.28 15.288 ;
    END
  END o[126]
  PIN o[127]
    DIRECTION OUTPUT ;
    USE SIGNAL ;
    PORT
      LAYER M4 ;
        RECT  17.088 15.36 17.28 15.384 ;
    END
  END o[127]
  PIN o[128]
    DIRECTION OUTPUT ;
    USE SIGNAL ;
    PORT
      LAYER M4 ;
        RECT  17.088 15.504 17.28 15.528 ;
    END
  END o[128]
  PIN o[129]
    DIRECTION OUTPUT ;
    USE SIGNAL ;
    PORT
      LAYER M4 ;
        RECT  17.088 15.6 17.28 15.624 ;
    END
  END o[129]
  PIN o[12]
    DIRECTION OUTPUT ;
    USE SIGNAL ;
    PORT
      LAYER M4 ;
        RECT  17.088 3.456 17.28 3.48 ;
    END
  END o[12]
  PIN o[130]
    DIRECTION OUTPUT ;
    USE SIGNAL ;
    PORT
      LAYER M4 ;
        RECT  17.088 15.696 17.28 15.72 ;
    END
  END o[130]
  PIN o[131]
    DIRECTION OUTPUT ;
    USE SIGNAL ;
    PORT
      LAYER M4 ;
        RECT  17.088 15.792 17.28 15.816 ;
    END
  END o[131]
  PIN o[132]
    DIRECTION OUTPUT ;
    USE SIGNAL ;
    PORT
      LAYER M4 ;
        RECT  17.088 15.888 17.28 15.912 ;
    END
  END o[132]
  PIN o[133]
    DIRECTION OUTPUT ;
    USE SIGNAL ;
    PORT
      LAYER M4 ;
        RECT  17.088 15.984 17.28 16.008 ;
    END
  END o[133]
  PIN o[134]
    DIRECTION OUTPUT ;
    USE SIGNAL ;
    PORT
      LAYER M4 ;
        RECT  17.088 16.128 17.28 16.152 ;
    END
  END o[134]
  PIN o[135]
    DIRECTION OUTPUT ;
    USE SIGNAL ;
    PORT
      LAYER M4 ;
        RECT  17.088 16.224 17.28 16.248 ;
    END
  END o[135]
  PIN o[136]
    DIRECTION OUTPUT ;
    USE SIGNAL ;
    PORT
      LAYER M4 ;
        RECT  17.088 16.32 17.28 16.344 ;
    END
  END o[136]
  PIN o[137]
    DIRECTION OUTPUT ;
    USE SIGNAL ;
    PORT
      LAYER M4 ;
        RECT  17.088 16.416 17.28 16.44 ;
    END
  END o[137]
  PIN o[138]
    DIRECTION OUTPUT ;
    USE SIGNAL ;
    PORT
      LAYER M4 ;
        RECT  17.088 16.512 17.28 16.536 ;
    END
  END o[138]
  PIN o[139]
    DIRECTION OUTPUT ;
    USE SIGNAL ;
    PORT
      LAYER M4 ;
        RECT  17.088 16.608 17.28 16.632 ;
    END
  END o[139]
  PIN o[13]
    DIRECTION OUTPUT ;
    USE SIGNAL ;
    PORT
      LAYER M4 ;
        RECT  17.088 3.552 17.28 3.576 ;
    END
  END o[13]
  PIN o[140]
    DIRECTION OUTPUT ;
    USE SIGNAL ;
    PORT
      LAYER M4 ;
        RECT  17.088 16.704 17.28 16.728 ;
    END
  END o[140]
  PIN o[141]
    DIRECTION OUTPUT ;
    USE SIGNAL ;
    PORT
      LAYER M4 ;
        RECT  17.088 16.848 17.28 16.872 ;
    END
  END o[141]
  PIN o[142]
    DIRECTION OUTPUT ;
    USE SIGNAL ;
    PORT
      LAYER M4 ;
        RECT  17.088 16.944 17.28 16.968 ;
    END
  END o[142]
  PIN o[143]
    DIRECTION OUTPUT ;
    USE SIGNAL ;
    PORT
      LAYER M4 ;
        RECT  17.088 17.04 17.28 17.064 ;
    END
  END o[143]
  PIN o[144]
    DIRECTION OUTPUT ;
    USE SIGNAL ;
    PORT
      LAYER M4 ;
        RECT  17.088 17.136 17.28 17.16 ;
    END
  END o[144]
  PIN o[145]
    DIRECTION OUTPUT ;
    USE SIGNAL ;
    PORT
      LAYER M4 ;
        RECT  17.088 17.232 17.28 17.256 ;
    END
  END o[145]
  PIN o[146]
    DIRECTION OUTPUT ;
    USE SIGNAL ;
    PORT
      LAYER M4 ;
        RECT  17.088 17.328 17.28 17.352 ;
    END
  END o[146]
  PIN o[147]
    DIRECTION OUTPUT ;
    USE SIGNAL ;
    PORT
      LAYER M4 ;
        RECT  17.088 17.472 17.28 17.496 ;
    END
  END o[147]
  PIN o[148]
    DIRECTION OUTPUT ;
    USE SIGNAL ;
    PORT
      LAYER M4 ;
        RECT  17.088 17.568 17.28 17.592 ;
    END
  END o[148]
  PIN o[149]
    DIRECTION OUTPUT ;
    USE SIGNAL ;
    PORT
      LAYER M4 ;
        RECT  17.088 17.664 17.28 17.688 ;
    END
  END o[149]
  PIN o[14]
    DIRECTION OUTPUT ;
    USE SIGNAL ;
    PORT
      LAYER M4 ;
        RECT  17.088 3.696 17.28 3.72 ;
    END
  END o[14]
  PIN o[150]
    DIRECTION OUTPUT ;
    USE SIGNAL ;
    PORT
      LAYER M4 ;
        RECT  17.088 17.76 17.28 17.784 ;
    END
  END o[150]
  PIN o[151]
    DIRECTION OUTPUT ;
    USE SIGNAL ;
    PORT
      LAYER M4 ;
        RECT  17.088 17.856 17.28 17.88 ;
    END
  END o[151]
  PIN o[152]
    DIRECTION OUTPUT ;
    USE SIGNAL ;
    PORT
      LAYER M4 ;
        RECT  17.088 17.952 17.28 17.976 ;
    END
  END o[152]
  PIN o[153]
    DIRECTION OUTPUT ;
    USE SIGNAL ;
    PORT
      LAYER M4 ;
        RECT  17.088 18.096 17.28 18.12 ;
    END
  END o[153]
  PIN o[154]
    DIRECTION OUTPUT ;
    USE SIGNAL ;
    PORT
      LAYER M4 ;
        RECT  17.088 18.192 17.28 18.216 ;
    END
  END o[154]
  PIN o[155]
    DIRECTION OUTPUT ;
    USE SIGNAL ;
    PORT
      LAYER M4 ;
        RECT  17.088 18.288 17.28 18.312 ;
    END
  END o[155]
  PIN o[156]
    DIRECTION OUTPUT ;
    USE SIGNAL ;
    PORT
      LAYER M4 ;
        RECT  17.088 18.384 17.28 18.408 ;
    END
  END o[156]
  PIN o[157]
    DIRECTION OUTPUT ;
    USE SIGNAL ;
    PORT
      LAYER M4 ;
        RECT  17.088 18.48 17.28 18.504 ;
    END
  END o[157]
  PIN o[158]
    DIRECTION OUTPUT ;
    USE SIGNAL ;
    PORT
      LAYER M4 ;
        RECT  17.088 18.576 17.28 18.6 ;
    END
  END o[158]
  PIN o[159]
    DIRECTION OUTPUT ;
    USE SIGNAL ;
    PORT
      LAYER M4 ;
        RECT  17.088 18.672 17.28 18.696 ;
    END
  END o[159]
  PIN o[15]
    DIRECTION OUTPUT ;
    USE SIGNAL ;
    PORT
      LAYER M4 ;
        RECT  17.088 3.792 17.28 3.816 ;
    END
  END o[15]
  PIN o[160]
    DIRECTION OUTPUT ;
    USE SIGNAL ;
    PORT
      LAYER M4 ;
        RECT  17.088 18.816 17.28 18.84 ;
    END
  END o[160]
  PIN o[161]
    DIRECTION OUTPUT ;
    USE SIGNAL ;
    PORT
      LAYER M4 ;
        RECT  17.088 18.912 17.28 18.936 ;
    END
  END o[161]
  PIN o[162]
    DIRECTION OUTPUT ;
    USE SIGNAL ;
    PORT
      LAYER M4 ;
        RECT  17.088 19.008 17.28 19.032 ;
    END
  END o[162]
  PIN o[163]
    DIRECTION OUTPUT ;
    USE SIGNAL ;
    PORT
      LAYER M4 ;
        RECT  17.088 19.104 17.28 19.128 ;
    END
  END o[163]
  PIN o[164]
    DIRECTION OUTPUT ;
    USE SIGNAL ;
    PORT
      LAYER M4 ;
        RECT  17.088 19.2 17.28 19.224 ;
    END
  END o[164]
  PIN o[165]
    DIRECTION OUTPUT ;
    USE SIGNAL ;
    PORT
      LAYER M4 ;
        RECT  17.088 19.296 17.28 19.32 ;
    END
  END o[165]
  PIN o[166]
    DIRECTION OUTPUT ;
    USE SIGNAL ;
    PORT
      LAYER M4 ;
        RECT  17.088 19.44 17.28 19.464 ;
    END
  END o[166]
  PIN o[167]
    DIRECTION OUTPUT ;
    USE SIGNAL ;
    PORT
      LAYER M4 ;
        RECT  17.088 19.536 17.28 19.56 ;
    END
  END o[167]
  PIN o[168]
    DIRECTION OUTPUT ;
    USE SIGNAL ;
    PORT
      LAYER M4 ;
        RECT  17.088 19.632 17.28 19.656 ;
    END
  END o[168]
  PIN o[169]
    DIRECTION OUTPUT ;
    USE SIGNAL ;
    PORT
      LAYER M4 ;
        RECT  17.088 19.728 17.28 19.752 ;
    END
  END o[169]
  PIN o[16]
    DIRECTION OUTPUT ;
    USE SIGNAL ;
    PORT
      LAYER M4 ;
        RECT  17.088 3.888 17.28 3.912 ;
    END
  END o[16]
  PIN o[170]
    DIRECTION OUTPUT ;
    USE SIGNAL ;
    PORT
      LAYER M4 ;
        RECT  17.088 19.824 17.28 19.848 ;
    END
  END o[170]
  PIN o[171]
    DIRECTION OUTPUT ;
    USE SIGNAL ;
    PORT
      LAYER M4 ;
        RECT  17.088 19.92 17.28 19.944 ;
    END
  END o[171]
  PIN o[172]
    DIRECTION OUTPUT ;
    USE SIGNAL ;
    PORT
      LAYER M4 ;
        RECT  17.088 20.064 17.28 20.088 ;
    END
  END o[172]
  PIN o[173]
    DIRECTION OUTPUT ;
    USE SIGNAL ;
    PORT
      LAYER M4 ;
        RECT  17.088 20.16 17.28 20.184 ;
    END
  END o[173]
  PIN o[174]
    DIRECTION OUTPUT ;
    USE SIGNAL ;
    PORT
      LAYER M4 ;
        RECT  17.088 20.256 17.28 20.28 ;
    END
  END o[174]
  PIN o[175]
    DIRECTION OUTPUT ;
    USE SIGNAL ;
    PORT
      LAYER M4 ;
        RECT  17.088 20.352 17.28 20.376 ;
    END
  END o[175]
  PIN o[176]
    DIRECTION OUTPUT ;
    USE SIGNAL ;
    PORT
      LAYER M4 ;
        RECT  17.088 20.448 17.28 20.472 ;
    END
  END o[176]
  PIN o[177]
    DIRECTION OUTPUT ;
    USE SIGNAL ;
    PORT
      LAYER M4 ;
        RECT  17.088 20.544 17.28 20.568 ;
    END
  END o[177]
  PIN o[178]
    DIRECTION OUTPUT ;
    USE SIGNAL ;
    PORT
      LAYER M4 ;
        RECT  17.088 20.64 17.28 20.664 ;
    END
  END o[178]
  PIN o[179]
    DIRECTION OUTPUT ;
    USE SIGNAL ;
    PORT
      LAYER M4 ;
        RECT  17.088 20.784 17.28 20.808 ;
    END
  END o[179]
  PIN o[17]
    DIRECTION OUTPUT ;
    USE SIGNAL ;
    PORT
      LAYER M4 ;
        RECT  17.088 3.984 17.28 4.008 ;
    END
  END o[17]
  PIN o[180]
    DIRECTION OUTPUT ;
    USE SIGNAL ;
    PORT
      LAYER M4 ;
        RECT  17.088 20.88 17.28 20.904 ;
    END
  END o[180]
  PIN o[181]
    DIRECTION OUTPUT ;
    USE SIGNAL ;
    PORT
      LAYER M4 ;
        RECT  17.088 20.976 17.28 21 ;
    END
  END o[181]
  PIN o[182]
    DIRECTION OUTPUT ;
    USE SIGNAL ;
    PORT
      LAYER M4 ;
        RECT  17.088 21.072 17.28 21.096 ;
    END
  END o[182]
  PIN o[183]
    DIRECTION OUTPUT ;
    USE SIGNAL ;
    PORT
      LAYER M4 ;
        RECT  17.088 21.168 17.28 21.192 ;
    END
  END o[183]
  PIN o[184]
    DIRECTION OUTPUT ;
    USE SIGNAL ;
    PORT
      LAYER M4 ;
        RECT  17.088 21.264 17.28 21.288 ;
    END
  END o[184]
  PIN o[185]
    DIRECTION OUTPUT ;
    USE SIGNAL ;
    PORT
      LAYER M4 ;
        RECT  17.088 21.408 17.28 21.432 ;
    END
  END o[185]
  PIN o[186]
    DIRECTION OUTPUT ;
    USE SIGNAL ;
    PORT
      LAYER M4 ;
        RECT  17.088 21.504 17.28 21.528 ;
    END
  END o[186]
  PIN o[187]
    DIRECTION OUTPUT ;
    USE SIGNAL ;
    PORT
      LAYER M4 ;
        RECT  17.088 21.6 17.28 21.624 ;
    END
  END o[187]
  PIN o[188]
    DIRECTION OUTPUT ;
    USE SIGNAL ;
    PORT
      LAYER M4 ;
        RECT  17.088 21.696 17.28 21.72 ;
    END
  END o[188]
  PIN o[189]
    DIRECTION OUTPUT ;
    USE SIGNAL ;
    PORT
      LAYER M4 ;
        RECT  17.088 21.792 17.28 21.816 ;
    END
  END o[189]
  PIN o[18]
    DIRECTION OUTPUT ;
    USE SIGNAL ;
    PORT
      LAYER M4 ;
        RECT  17.088 4.08 17.28 4.104 ;
    END
  END o[18]
  PIN o[190]
    DIRECTION OUTPUT ;
    USE SIGNAL ;
    PORT
      LAYER M4 ;
        RECT  17.088 21.888 17.28 21.912 ;
    END
  END o[190]
  PIN o[191]
    DIRECTION OUTPUT ;
    USE SIGNAL ;
    PORT
      LAYER M4 ;
        RECT  17.088 22.032 17.28 22.056 ;
    END
  END o[191]
  PIN o[192]
    DIRECTION OUTPUT ;
    USE SIGNAL ;
    PORT
      LAYER M4 ;
        RECT  17.088 22.128 17.28 22.152 ;
    END
  END o[192]
  PIN o[193]
    DIRECTION OUTPUT ;
    USE SIGNAL ;
    PORT
      LAYER M4 ;
        RECT  17.088 22.224 17.28 22.248 ;
    END
  END o[193]
  PIN o[194]
    DIRECTION OUTPUT ;
    USE SIGNAL ;
    PORT
      LAYER M4 ;
        RECT  17.088 22.32 17.28 22.344 ;
    END
  END o[194]
  PIN o[195]
    DIRECTION OUTPUT ;
    USE SIGNAL ;
    PORT
      LAYER M4 ;
        RECT  17.088 22.416 17.28 22.44 ;
    END
  END o[195]
  PIN o[196]
    DIRECTION OUTPUT ;
    USE SIGNAL ;
    PORT
      LAYER M4 ;
        RECT  17.088 22.512 17.28 22.536 ;
    END
  END o[196]
  PIN o[197]
    DIRECTION OUTPUT ;
    USE SIGNAL ;
    PORT
      LAYER M4 ;
        RECT  17.088 22.608 17.28 22.632 ;
    END
  END o[197]
  PIN o[198]
    DIRECTION OUTPUT ;
    USE SIGNAL ;
    PORT
      LAYER M4 ;
        RECT  17.088 22.752 17.28 22.776 ;
    END
  END o[198]
  PIN o[199]
    DIRECTION OUTPUT ;
    USE SIGNAL ;
    PORT
      LAYER M4 ;
        RECT  17.088 22.848 17.28 22.872 ;
    END
  END o[199]
  PIN o[19]
    DIRECTION OUTPUT ;
    USE SIGNAL ;
    PORT
      LAYER M4 ;
        RECT  17.088 4.176 17.28 4.2 ;
    END
  END o[19]
  PIN o[1]
    DIRECTION OUTPUT ;
    USE SIGNAL ;
    PORT
      LAYER M4 ;
        RECT  17.088 2.304 17.28 2.328 ;
    END
  END o[1]
  PIN o[200]
    DIRECTION OUTPUT ;
    USE SIGNAL ;
    PORT
      LAYER M4 ;
        RECT  17.088 22.944 17.28 22.968 ;
    END
  END o[200]
  PIN o[201]
    DIRECTION OUTPUT ;
    USE SIGNAL ;
    PORT
      LAYER M4 ;
        RECT  17.088 23.04 17.28 23.064 ;
    END
  END o[201]
  PIN o[202]
    DIRECTION OUTPUT ;
    USE SIGNAL ;
    PORT
      LAYER M4 ;
        RECT  17.088 23.136 17.28 23.16 ;
    END
  END o[202]
  PIN o[203]
    DIRECTION OUTPUT ;
    USE SIGNAL ;
    PORT
      LAYER M4 ;
        RECT  17.088 23.232 17.28 23.256 ;
    END
  END o[203]
  PIN o[204]
    DIRECTION OUTPUT ;
    USE SIGNAL ;
    PORT
      LAYER M4 ;
        RECT  17.088 23.376 17.28 23.4 ;
    END
  END o[204]
  PIN o[205]
    DIRECTION OUTPUT ;
    USE SIGNAL ;
    PORT
      LAYER M4 ;
        RECT  17.088 23.472 17.28 23.496 ;
    END
  END o[205]
  PIN o[206]
    DIRECTION OUTPUT ;
    USE SIGNAL ;
    PORT
      LAYER M4 ;
        RECT  17.088 23.568 17.28 23.592 ;
    END
  END o[206]
  PIN o[207]
    DIRECTION OUTPUT ;
    USE SIGNAL ;
    PORT
      LAYER M4 ;
        RECT  17.088 23.664 17.28 23.688 ;
    END
  END o[207]
  PIN o[208]
    DIRECTION OUTPUT ;
    USE SIGNAL ;
    PORT
      LAYER M4 ;
        RECT  17.088 23.76 17.28 23.784 ;
    END
  END o[208]
  PIN o[209]
    DIRECTION OUTPUT ;
    USE SIGNAL ;
    PORT
      LAYER M4 ;
        RECT  17.088 23.856 17.28 23.88 ;
    END
  END o[209]
  PIN o[20]
    DIRECTION OUTPUT ;
    USE SIGNAL ;
    PORT
      LAYER M4 ;
        RECT  17.088 4.272 17.28 4.296 ;
    END
  END o[20]
  PIN o[210]
    DIRECTION OUTPUT ;
    USE SIGNAL ;
    PORT
      LAYER M4 ;
        RECT  17.088 24 17.28 24.024 ;
    END
  END o[210]
  PIN o[211]
    DIRECTION OUTPUT ;
    USE SIGNAL ;
    PORT
      LAYER M4 ;
        RECT  17.088 24.096 17.28 24.12 ;
    END
  END o[211]
  PIN o[212]
    DIRECTION OUTPUT ;
    USE SIGNAL ;
    PORT
      LAYER M4 ;
        RECT  17.088 24.192 17.28 24.216 ;
    END
  END o[212]
  PIN o[213]
    DIRECTION OUTPUT ;
    USE SIGNAL ;
    PORT
      LAYER M4 ;
        RECT  17.088 24.288 17.28 24.312 ;
    END
  END o[213]
  PIN o[214]
    DIRECTION OUTPUT ;
    USE SIGNAL ;
    PORT
      LAYER M4 ;
        RECT  17.088 24.384 17.28 24.408 ;
    END
  END o[214]
  PIN o[215]
    DIRECTION OUTPUT ;
    USE SIGNAL ;
    PORT
      LAYER M4 ;
        RECT  17.088 24.48 17.28 24.504 ;
    END
  END o[215]
  PIN o[216]
    DIRECTION OUTPUT ;
    USE SIGNAL ;
    PORT
      LAYER M4 ;
        RECT  17.088 24.576 17.28 24.6 ;
    END
  END o[216]
  PIN o[217]
    DIRECTION OUTPUT ;
    USE SIGNAL ;
    PORT
      LAYER M4 ;
        RECT  17.088 24.72 17.28 24.744 ;
    END
  END o[217]
  PIN o[218]
    DIRECTION OUTPUT ;
    USE SIGNAL ;
    PORT
      LAYER M4 ;
        RECT  17.088 24.816 17.28 24.84 ;
    END
  END o[218]
  PIN o[219]
    DIRECTION OUTPUT ;
    USE SIGNAL ;
    PORT
      LAYER M4 ;
        RECT  17.088 24.912 17.28 24.936 ;
    END
  END o[219]
  PIN o[21]
    DIRECTION OUTPUT ;
    USE SIGNAL ;
    PORT
      LAYER M4 ;
        RECT  17.088 4.416 17.28 4.44 ;
    END
  END o[21]
  PIN o[220]
    DIRECTION OUTPUT ;
    USE SIGNAL ;
    PORT
      LAYER M4 ;
        RECT  17.088 25.008 17.28 25.032 ;
    END
  END o[220]
  PIN o[221]
    DIRECTION OUTPUT ;
    USE SIGNAL ;
    PORT
      LAYER M4 ;
        RECT  17.088 25.104 17.28 25.128 ;
    END
  END o[221]
  PIN o[222]
    DIRECTION OUTPUT ;
    USE SIGNAL ;
    PORT
      LAYER M4 ;
        RECT  17.088 25.2 17.28 25.224 ;
    END
  END o[222]
  PIN o[223]
    DIRECTION OUTPUT ;
    USE SIGNAL ;
    PORT
      LAYER M4 ;
        RECT  17.088 25.344 17.28 25.368 ;
    END
  END o[223]
  PIN o[224]
    DIRECTION OUTPUT ;
    USE SIGNAL ;
    PORT
      LAYER M4 ;
        RECT  17.088 25.44 17.28 25.464 ;
    END
  END o[224]
  PIN o[225]
    DIRECTION OUTPUT ;
    USE SIGNAL ;
    PORT
      LAYER M4 ;
        RECT  17.088 25.536 17.28 25.56 ;
    END
  END o[225]
  PIN o[226]
    DIRECTION OUTPUT ;
    USE SIGNAL ;
    PORT
      LAYER M4 ;
        RECT  17.088 25.632 17.28 25.656 ;
    END
  END o[226]
  PIN o[227]
    DIRECTION OUTPUT ;
    USE SIGNAL ;
    PORT
      LAYER M4 ;
        RECT  17.088 25.728 17.28 25.752 ;
    END
  END o[227]
  PIN o[228]
    DIRECTION OUTPUT ;
    USE SIGNAL ;
    PORT
      LAYER M4 ;
        RECT  17.088 25.824 17.28 25.848 ;
    END
  END o[228]
  PIN o[229]
    DIRECTION OUTPUT ;
    USE SIGNAL ;
    PORT
      LAYER M4 ;
        RECT  17.088 25.968 17.28 25.992 ;
    END
  END o[229]
  PIN o[22]
    DIRECTION OUTPUT ;
    USE SIGNAL ;
    PORT
      LAYER M4 ;
        RECT  17.088 4.512 17.28 4.536 ;
    END
  END o[22]
  PIN o[230]
    DIRECTION OUTPUT ;
    USE SIGNAL ;
    PORT
      LAYER M4 ;
        RECT  17.088 26.064 17.28 26.088 ;
    END
  END o[230]
  PIN o[231]
    DIRECTION OUTPUT ;
    USE SIGNAL ;
    PORT
      LAYER M4 ;
        RECT  17.088 26.16 17.28 26.184 ;
    END
  END o[231]
  PIN o[232]
    DIRECTION OUTPUT ;
    USE SIGNAL ;
    PORT
      LAYER M4 ;
        RECT  17.088 26.256 17.28 26.28 ;
    END
  END o[232]
  PIN o[233]
    DIRECTION OUTPUT ;
    USE SIGNAL ;
    PORT
      LAYER M4 ;
        RECT  17.088 26.352 17.28 26.376 ;
    END
  END o[233]
  PIN o[234]
    DIRECTION OUTPUT ;
    USE SIGNAL ;
    PORT
      LAYER M4 ;
        RECT  17.088 26.448 17.28 26.472 ;
    END
  END o[234]
  PIN o[235]
    DIRECTION OUTPUT ;
    USE SIGNAL ;
    PORT
      LAYER M4 ;
        RECT  17.088 26.544 17.28 26.568 ;
    END
  END o[235]
  PIN o[236]
    DIRECTION OUTPUT ;
    USE SIGNAL ;
    PORT
      LAYER M4 ;
        RECT  17.088 26.688 17.28 26.712 ;
    END
  END o[236]
  PIN o[237]
    DIRECTION OUTPUT ;
    USE SIGNAL ;
    PORT
      LAYER M4 ;
        RECT  17.088 26.784 17.28 26.808 ;
    END
  END o[237]
  PIN o[238]
    DIRECTION OUTPUT ;
    USE SIGNAL ;
    PORT
      LAYER M4 ;
        RECT  17.088 26.88 17.28 26.904 ;
    END
  END o[238]
  PIN o[239]
    DIRECTION OUTPUT ;
    USE SIGNAL ;
    PORT
      LAYER M4 ;
        RECT  17.088 26.976 17.28 27 ;
    END
  END o[239]
  PIN o[23]
    DIRECTION OUTPUT ;
    USE SIGNAL ;
    PORT
      LAYER M4 ;
        RECT  17.088 4.608 17.28 4.632 ;
    END
  END o[23]
  PIN o[240]
    DIRECTION OUTPUT ;
    USE SIGNAL ;
    PORT
      LAYER M4 ;
        RECT  17.088 27.072 17.28 27.096 ;
    END
  END o[240]
  PIN o[241]
    DIRECTION OUTPUT ;
    USE SIGNAL ;
    PORT
      LAYER M4 ;
        RECT  17.088 27.168 17.28 27.192 ;
    END
  END o[241]
  PIN o[242]
    DIRECTION OUTPUT ;
    USE SIGNAL ;
    PORT
      LAYER M4 ;
        RECT  17.088 27.312 17.28 27.336 ;
    END
  END o[242]
  PIN o[243]
    DIRECTION OUTPUT ;
    USE SIGNAL ;
    PORT
      LAYER M4 ;
        RECT  17.088 27.408 17.28 27.432 ;
    END
  END o[243]
  PIN o[244]
    DIRECTION OUTPUT ;
    USE SIGNAL ;
    PORT
      LAYER M4 ;
        RECT  17.088 27.504 17.28 27.528 ;
    END
  END o[244]
  PIN o[245]
    DIRECTION OUTPUT ;
    USE SIGNAL ;
    PORT
      LAYER M4 ;
        RECT  17.088 27.6 17.28 27.624 ;
    END
  END o[245]
  PIN o[246]
    DIRECTION OUTPUT ;
    USE SIGNAL ;
    PORT
      LAYER M4 ;
        RECT  17.088 27.696 17.28 27.72 ;
    END
  END o[246]
  PIN o[247]
    DIRECTION OUTPUT ;
    USE SIGNAL ;
    PORT
      LAYER M4 ;
        RECT  17.088 27.792 17.28 27.816 ;
    END
  END o[247]
  PIN o[248]
    DIRECTION OUTPUT ;
    USE SIGNAL ;
    PORT
      LAYER M4 ;
        RECT  17.088 27.936 17.28 27.96 ;
    END
  END o[248]
  PIN o[249]
    DIRECTION OUTPUT ;
    USE SIGNAL ;
    PORT
      LAYER M4 ;
        RECT  17.088 28.032 17.28 28.056 ;
    END
  END o[249]
  PIN o[24]
    DIRECTION OUTPUT ;
    USE SIGNAL ;
    PORT
      LAYER M4 ;
        RECT  17.088 4.704 17.28 4.728 ;
    END
  END o[24]
  PIN o[250]
    DIRECTION OUTPUT ;
    USE SIGNAL ;
    PORT
      LAYER M4 ;
        RECT  17.088 28.128 17.28 28.152 ;
    END
  END o[250]
  PIN o[251]
    DIRECTION OUTPUT ;
    USE SIGNAL ;
    PORT
      LAYER M4 ;
        RECT  17.088 28.224 17.28 28.248 ;
    END
  END o[251]
  PIN o[252]
    DIRECTION OUTPUT ;
    USE SIGNAL ;
    PORT
      LAYER M4 ;
        RECT  17.088 28.32 17.28 28.344 ;
    END
  END o[252]
  PIN o[253]
    DIRECTION OUTPUT ;
    USE SIGNAL ;
    PORT
      LAYER M4 ;
        RECT  17.088 28.416 17.28 28.44 ;
    END
  END o[253]
  PIN o[254]
    DIRECTION OUTPUT ;
    USE SIGNAL ;
    PORT
      LAYER M4 ;
        RECT  17.088 28.512 17.28 28.536 ;
    END
  END o[254]
  PIN o[255]
    DIRECTION OUTPUT ;
    USE SIGNAL ;
    PORT
      LAYER M4 ;
        RECT  17.088 28.656 17.28 28.68 ;
    END
  END o[255]
  PIN o[256]
    DIRECTION OUTPUT ;
    USE SIGNAL ;
    PORT
      LAYER M4 ;
        RECT  17.088 28.752 17.28 28.776 ;
    END
  END o[256]
  PIN o[257]
    DIRECTION OUTPUT ;
    USE SIGNAL ;
    PORT
      LAYER M4 ;
        RECT  17.088 28.848 17.28 28.872 ;
    END
  END o[257]
  PIN o[258]
    DIRECTION OUTPUT ;
    USE SIGNAL ;
    PORT
      LAYER M4 ;
        RECT  17.088 28.944 17.28 28.968 ;
    END
  END o[258]
  PIN o[259]
    DIRECTION OUTPUT ;
    USE SIGNAL ;
    PORT
      LAYER M4 ;
        RECT  17.088 29.04 17.28 29.064 ;
    END
  END o[259]
  PIN o[25]
    DIRECTION OUTPUT ;
    USE SIGNAL ;
    PORT
      LAYER M4 ;
        RECT  17.088 4.8 17.28 4.824 ;
    END
  END o[25]
  PIN o[260]
    DIRECTION OUTPUT ;
    USE SIGNAL ;
    PORT
      LAYER M4 ;
        RECT  17.088 29.136 17.28 29.16 ;
    END
  END o[260]
  PIN o[261]
    DIRECTION OUTPUT ;
    USE SIGNAL ;
    PORT
      LAYER M4 ;
        RECT  17.088 29.28 17.28 29.304 ;
    END
  END o[261]
  PIN o[262]
    DIRECTION OUTPUT ;
    USE SIGNAL ;
    PORT
      LAYER M4 ;
        RECT  17.088 29.376 17.28 29.4 ;
    END
  END o[262]
  PIN o[263]
    DIRECTION OUTPUT ;
    USE SIGNAL ;
    PORT
      LAYER M4 ;
        RECT  17.088 29.472 17.28 29.496 ;
    END
  END o[263]
  PIN o[264]
    DIRECTION OUTPUT ;
    USE SIGNAL ;
    PORT
      LAYER M4 ;
        RECT  17.088 29.568 17.28 29.592 ;
    END
  END o[264]
  PIN o[265]
    DIRECTION OUTPUT ;
    USE SIGNAL ;
    PORT
      LAYER M4 ;
        RECT  17.088 29.664 17.28 29.688 ;
    END
  END o[265]
  PIN o[266]
    DIRECTION OUTPUT ;
    USE SIGNAL ;
    PORT
      LAYER M4 ;
        RECT  17.088 29.76 17.28 29.784 ;
    END
  END o[266]
  PIN o[267]
    DIRECTION OUTPUT ;
    USE SIGNAL ;
    PORT
      LAYER M4 ;
        RECT  17.088 29.904 17.28 29.928 ;
    END
  END o[267]
  PIN o[268]
    DIRECTION OUTPUT ;
    USE SIGNAL ;
    PORT
      LAYER M4 ;
        RECT  17.088 30 17.28 30.024 ;
    END
  END o[268]
  PIN o[269]
    DIRECTION OUTPUT ;
    USE SIGNAL ;
    PORT
      LAYER M4 ;
        RECT  17.088 30.096 17.28 30.12 ;
    END
  END o[269]
  PIN o[26]
    DIRECTION OUTPUT ;
    USE SIGNAL ;
    PORT
      LAYER M4 ;
        RECT  17.088 4.896 17.28 4.92 ;
    END
  END o[26]
  PIN o[270]
    DIRECTION OUTPUT ;
    USE SIGNAL ;
    PORT
      LAYER M4 ;
        RECT  17.088 30.192 17.28 30.216 ;
    END
  END o[270]
  PIN o[271]
    DIRECTION OUTPUT ;
    USE SIGNAL ;
    PORT
      LAYER M4 ;
        RECT  17.088 30.288 17.28 30.312 ;
    END
  END o[271]
  PIN o[272]
    DIRECTION OUTPUT ;
    USE SIGNAL ;
    PORT
      LAYER M4 ;
        RECT  17.088 30.384 17.28 30.408 ;
    END
  END o[272]
  PIN o[273]
    DIRECTION OUTPUT ;
    USE SIGNAL ;
    PORT
      LAYER M4 ;
        RECT  17.088 30.48 17.28 30.504 ;
    END
  END o[273]
  PIN o[274]
    DIRECTION OUTPUT ;
    USE SIGNAL ;
    PORT
      LAYER M4 ;
        RECT  17.088 30.624 17.28 30.648 ;
    END
  END o[274]
  PIN o[275]
    DIRECTION OUTPUT ;
    USE SIGNAL ;
    PORT
      LAYER M4 ;
        RECT  17.088 30.72 17.28 30.744 ;
    END
  END o[275]
  PIN o[276]
    DIRECTION OUTPUT ;
    USE SIGNAL ;
    PORT
      LAYER M4 ;
        RECT  17.088 30.816 17.28 30.84 ;
    END
  END o[276]
  PIN o[277]
    DIRECTION OUTPUT ;
    USE SIGNAL ;
    PORT
      LAYER M4 ;
        RECT  17.088 30.912 17.28 30.936 ;
    END
  END o[277]
  PIN o[278]
    DIRECTION OUTPUT ;
    USE SIGNAL ;
    PORT
      LAYER M4 ;
        RECT  17.088 31.008 17.28 31.032 ;
    END
  END o[278]
  PIN o[279]
    DIRECTION OUTPUT ;
    USE SIGNAL ;
    PORT
      LAYER M4 ;
        RECT  17.088 31.104 17.28 31.128 ;
    END
  END o[279]
  PIN o[27]
    DIRECTION OUTPUT ;
    USE SIGNAL ;
    PORT
      LAYER M4 ;
        RECT  17.088 5.04 17.28 5.064 ;
    END
  END o[27]
  PIN o[280]
    DIRECTION OUTPUT ;
    USE SIGNAL ;
    PORT
      LAYER M4 ;
        RECT  17.088 31.248 17.28 31.272 ;
    END
  END o[280]
  PIN o[281]
    DIRECTION OUTPUT ;
    USE SIGNAL ;
    PORT
      LAYER M4 ;
        RECT  17.088 31.344 17.28 31.368 ;
    END
  END o[281]
  PIN o[282]
    DIRECTION OUTPUT ;
    USE SIGNAL ;
    PORT
      LAYER M4 ;
        RECT  17.088 31.44 17.28 31.464 ;
    END
  END o[282]
  PIN o[283]
    DIRECTION OUTPUT ;
    USE SIGNAL ;
    PORT
      LAYER M4 ;
        RECT  17.088 31.536 17.28 31.56 ;
    END
  END o[283]
  PIN o[284]
    DIRECTION OUTPUT ;
    USE SIGNAL ;
    PORT
      LAYER M4 ;
        RECT  17.088 31.632 17.28 31.656 ;
    END
  END o[284]
  PIN o[285]
    DIRECTION OUTPUT ;
    USE SIGNAL ;
    PORT
      LAYER M4 ;
        RECT  17.088 31.728 17.28 31.752 ;
    END
  END o[285]
  PIN o[286]
    DIRECTION OUTPUT ;
    USE SIGNAL ;
    PORT
      LAYER M4 ;
        RECT  17.088 31.872 17.28 31.896 ;
    END
  END o[286]
  PIN o[287]
    DIRECTION OUTPUT ;
    USE SIGNAL ;
    PORT
      LAYER M4 ;
        RECT  17.088 31.968 17.28 31.992 ;
    END
  END o[287]
  PIN o[288]
    DIRECTION OUTPUT ;
    USE SIGNAL ;
    PORT
      LAYER M4 ;
        RECT  17.088 32.064 17.28 32.088 ;
    END
  END o[288]
  PIN o[289]
    DIRECTION OUTPUT ;
    USE SIGNAL ;
    PORT
      LAYER M4 ;
        RECT  17.088 32.16 17.28 32.184 ;
    END
  END o[289]
  PIN o[28]
    DIRECTION OUTPUT ;
    USE SIGNAL ;
    PORT
      LAYER M4 ;
        RECT  17.088 5.136 17.28 5.16 ;
    END
  END o[28]
  PIN o[290]
    DIRECTION OUTPUT ;
    USE SIGNAL ;
    PORT
      LAYER M4 ;
        RECT  17.088 32.256 17.28 32.28 ;
    END
  END o[290]
  PIN o[291]
    DIRECTION OUTPUT ;
    USE SIGNAL ;
    PORT
      LAYER M4 ;
        RECT  17.088 32.352 17.28 32.376 ;
    END
  END o[291]
  PIN o[292]
    DIRECTION OUTPUT ;
    USE SIGNAL ;
    PORT
      LAYER M4 ;
        RECT  17.088 32.448 17.28 32.472 ;
    END
  END o[292]
  PIN o[293]
    DIRECTION OUTPUT ;
    USE SIGNAL ;
    PORT
      LAYER M4 ;
        RECT  17.088 32.592 17.28 32.616 ;
    END
  END o[293]
  PIN o[294]
    DIRECTION OUTPUT ;
    USE SIGNAL ;
    PORT
      LAYER M4 ;
        RECT  17.088 32.688 17.28 32.712 ;
    END
  END o[294]
  PIN o[295]
    DIRECTION OUTPUT ;
    USE SIGNAL ;
    PORT
      LAYER M4 ;
        RECT  17.088 32.784 17.28 32.808 ;
    END
  END o[295]
  PIN o[296]
    DIRECTION OUTPUT ;
    USE SIGNAL ;
    PORT
      LAYER M4 ;
        RECT  17.088 32.88 17.28 32.904 ;
    END
  END o[296]
  PIN o[297]
    DIRECTION OUTPUT ;
    USE SIGNAL ;
    PORT
      LAYER M4 ;
        RECT  17.088 32.976 17.28 33 ;
    END
  END o[297]
  PIN o[298]
    DIRECTION OUTPUT ;
    USE SIGNAL ;
    PORT
      LAYER M4 ;
        RECT  17.088 33.072 17.28 33.096 ;
    END
  END o[298]
  PIN o[299]
    DIRECTION OUTPUT ;
    USE SIGNAL ;
    PORT
      LAYER M4 ;
        RECT  17.088 33.216 17.28 33.24 ;
    END
  END o[299]
  PIN o[29]
    DIRECTION OUTPUT ;
    USE SIGNAL ;
    PORT
      LAYER M4 ;
        RECT  17.088 5.232 17.28 5.256 ;
    END
  END o[29]
  PIN o[2]
    DIRECTION OUTPUT ;
    USE SIGNAL ;
    PORT
      LAYER M4 ;
        RECT  17.088 2.448 17.28 2.472 ;
    END
  END o[2]
  PIN o[300]
    DIRECTION OUTPUT ;
    USE SIGNAL ;
    PORT
      LAYER M4 ;
        RECT  17.088 33.312 17.28 33.336 ;
    END
  END o[300]
  PIN o[301]
    DIRECTION OUTPUT ;
    USE SIGNAL ;
    PORT
      LAYER M4 ;
        RECT  17.088 33.408 17.28 33.432 ;
    END
  END o[301]
  PIN o[302]
    DIRECTION OUTPUT ;
    USE SIGNAL ;
    PORT
      LAYER M4 ;
        RECT  17.088 33.504 17.28 33.528 ;
    END
  END o[302]
  PIN o[303]
    DIRECTION OUTPUT ;
    USE SIGNAL ;
    PORT
      LAYER M4 ;
        RECT  17.088 33.6 17.28 33.624 ;
    END
  END o[303]
  PIN o[304]
    DIRECTION OUTPUT ;
    USE SIGNAL ;
    PORT
      LAYER M4 ;
        RECT  17.088 33.696 17.28 33.72 ;
    END
  END o[304]
  PIN o[305]
    DIRECTION OUTPUT ;
    USE SIGNAL ;
    PORT
      LAYER M4 ;
        RECT  17.088 33.84 17.28 33.864 ;
    END
  END o[305]
  PIN o[306]
    DIRECTION OUTPUT ;
    USE SIGNAL ;
    PORT
      LAYER M4 ;
        RECT  17.088 33.936 17.28 33.96 ;
    END
  END o[306]
  PIN o[307]
    DIRECTION OUTPUT ;
    USE SIGNAL ;
    PORT
      LAYER M4 ;
        RECT  17.088 34.032 17.28 34.056 ;
    END
  END o[307]
  PIN o[308]
    DIRECTION OUTPUT ;
    USE SIGNAL ;
    PORT
      LAYER M4 ;
        RECT  17.088 34.128 17.28 34.152 ;
    END
  END o[308]
  PIN o[309]
    DIRECTION OUTPUT ;
    USE SIGNAL ;
    PORT
      LAYER M4 ;
        RECT  17.088 34.224 17.28 34.248 ;
    END
  END o[309]
  PIN o[30]
    DIRECTION OUTPUT ;
    USE SIGNAL ;
    PORT
      LAYER M4 ;
        RECT  17.088 5.328 17.28 5.352 ;
    END
  END o[30]
  PIN o[310]
    DIRECTION OUTPUT ;
    USE SIGNAL ;
    PORT
      LAYER M4 ;
        RECT  17.088 34.32 17.28 34.344 ;
    END
  END o[310]
  PIN o[311]
    DIRECTION OUTPUT ;
    USE SIGNAL ;
    PORT
      LAYER M4 ;
        RECT  17.088 34.416 17.28 34.44 ;
    END
  END o[311]
  PIN o[312]
    DIRECTION OUTPUT ;
    USE SIGNAL ;
    PORT
      LAYER M4 ;
        RECT  17.088 34.56 17.28 34.584 ;
    END
  END o[312]
  PIN o[313]
    DIRECTION OUTPUT ;
    USE SIGNAL ;
    PORT
      LAYER M4 ;
        RECT  17.088 34.656 17.28 34.68 ;
    END
  END o[313]
  PIN o[314]
    DIRECTION OUTPUT ;
    USE SIGNAL ;
    PORT
      LAYER M4 ;
        RECT  17.088 34.752 17.28 34.776 ;
    END
  END o[314]
  PIN o[315]
    DIRECTION OUTPUT ;
    USE SIGNAL ;
    PORT
      LAYER M4 ;
        RECT  17.088 34.848 17.28 34.872 ;
    END
  END o[315]
  PIN o[316]
    DIRECTION OUTPUT ;
    USE SIGNAL ;
    PORT
      LAYER M4 ;
        RECT  17.088 34.944 17.28 34.968 ;
    END
  END o[316]
  PIN o[317]
    DIRECTION OUTPUT ;
    USE SIGNAL ;
    PORT
      LAYER M4 ;
        RECT  17.088 35.04 17.28 35.064 ;
    END
  END o[317]
  PIN o[318]
    DIRECTION OUTPUT ;
    USE SIGNAL ;
    PORT
      LAYER M4 ;
        RECT  17.088 35.184 17.28 35.208 ;
    END
  END o[318]
  PIN o[319]
    DIRECTION OUTPUT ;
    USE SIGNAL ;
    PORT
      LAYER M4 ;
        RECT  17.088 35.28 17.28 35.304 ;
    END
  END o[319]
  PIN o[31]
    DIRECTION OUTPUT ;
    USE SIGNAL ;
    PORT
      LAYER M4 ;
        RECT  17.088 5.424 17.28 5.448 ;
    END
  END o[31]
  PIN o[320]
    DIRECTION OUTPUT ;
    USE SIGNAL ;
    PORT
      LAYER M4 ;
        RECT  17.088 35.376 17.28 35.4 ;
    END
  END o[320]
  PIN o[321]
    DIRECTION OUTPUT ;
    USE SIGNAL ;
    PORT
      LAYER M4 ;
        RECT  17.088 35.472 17.28 35.496 ;
    END
  END o[321]
  PIN o[322]
    DIRECTION OUTPUT ;
    USE SIGNAL ;
    PORT
      LAYER M4 ;
        RECT  17.088 35.568 17.28 35.592 ;
    END
  END o[322]
  PIN o[323]
    DIRECTION OUTPUT ;
    USE SIGNAL ;
    PORT
      LAYER M4 ;
        RECT  17.088 35.664 17.28 35.688 ;
    END
  END o[323]
  PIN o[324]
    DIRECTION OUTPUT ;
    USE SIGNAL ;
    PORT
      LAYER M4 ;
        RECT  17.088 35.808 17.28 35.832 ;
    END
  END o[324]
  PIN o[325]
    DIRECTION OUTPUT ;
    USE SIGNAL ;
    PORT
      LAYER M4 ;
        RECT  17.088 35.904 17.28 35.928 ;
    END
  END o[325]
  PIN o[326]
    DIRECTION OUTPUT ;
    USE SIGNAL ;
    PORT
      LAYER M4 ;
        RECT  17.088 36 17.28 36.024 ;
    END
  END o[326]
  PIN o[327]
    DIRECTION OUTPUT ;
    USE SIGNAL ;
    PORT
      LAYER M4 ;
        RECT  17.088 36.096 17.28 36.12 ;
    END
  END o[327]
  PIN o[328]
    DIRECTION OUTPUT ;
    USE SIGNAL ;
    PORT
      LAYER M4 ;
        RECT  17.088 36.192 17.28 36.216 ;
    END
  END o[328]
  PIN o[329]
    DIRECTION OUTPUT ;
    USE SIGNAL ;
    PORT
      LAYER M4 ;
        RECT  17.088 36.288 17.28 36.312 ;
    END
  END o[329]
  PIN o[32]
    DIRECTION OUTPUT ;
    USE SIGNAL ;
    PORT
      LAYER M4 ;
        RECT  17.088 5.52 17.28 5.544 ;
    END
  END o[32]
  PIN o[330]
    DIRECTION OUTPUT ;
    USE SIGNAL ;
    PORT
      LAYER M4 ;
        RECT  17.088 36.384 17.28 36.408 ;
    END
  END o[330]
  PIN o[331]
    DIRECTION OUTPUT ;
    USE SIGNAL ;
    PORT
      LAYER M4 ;
        RECT  17.088 36.528 17.28 36.552 ;
    END
  END o[331]
  PIN o[332]
    DIRECTION OUTPUT ;
    USE SIGNAL ;
    PORT
      LAYER M4 ;
        RECT  17.088 36.624 17.28 36.648 ;
    END
  END o[332]
  PIN o[333]
    DIRECTION OUTPUT ;
    USE SIGNAL ;
    PORT
      LAYER M4 ;
        RECT  17.088 36.72 17.28 36.744 ;
    END
  END o[333]
  PIN o[334]
    DIRECTION OUTPUT ;
    USE SIGNAL ;
    PORT
      LAYER M4 ;
        RECT  17.088 36.816 17.28 36.84 ;
    END
  END o[334]
  PIN o[335]
    DIRECTION OUTPUT ;
    USE SIGNAL ;
    PORT
      LAYER M4 ;
        RECT  17.088 36.912 17.28 36.936 ;
    END
  END o[335]
  PIN o[336]
    DIRECTION OUTPUT ;
    USE SIGNAL ;
    PORT
      LAYER M4 ;
        RECT  17.088 37.008 17.28 37.032 ;
    END
  END o[336]
  PIN o[337]
    DIRECTION OUTPUT ;
    USE SIGNAL ;
    PORT
      LAYER M4 ;
        RECT  17.088 37.152 17.28 37.176 ;
    END
  END o[337]
  PIN o[338]
    DIRECTION OUTPUT ;
    USE SIGNAL ;
    PORT
      LAYER M4 ;
        RECT  17.088 37.248 17.28 37.272 ;
    END
  END o[338]
  PIN o[339]
    DIRECTION OUTPUT ;
    USE SIGNAL ;
    PORT
      LAYER M4 ;
        RECT  17.088 37.344 17.28 37.368 ;
    END
  END o[339]
  PIN o[33]
    DIRECTION OUTPUT ;
    USE SIGNAL ;
    PORT
      LAYER M4 ;
        RECT  17.088 5.664 17.28 5.688 ;
    END
  END o[33]
  PIN o[340]
    DIRECTION OUTPUT ;
    USE SIGNAL ;
    PORT
      LAYER M4 ;
        RECT  17.088 37.44 17.28 37.464 ;
    END
  END o[340]
  PIN o[341]
    DIRECTION OUTPUT ;
    USE SIGNAL ;
    PORT
      LAYER M4 ;
        RECT  17.088 37.536 17.28 37.56 ;
    END
  END o[341]
  PIN o[342]
    DIRECTION OUTPUT ;
    USE SIGNAL ;
    PORT
      LAYER M4 ;
        RECT  17.088 37.632 17.28 37.656 ;
    END
  END o[342]
  PIN o[343]
    DIRECTION OUTPUT ;
    USE SIGNAL ;
    PORT
      LAYER M4 ;
        RECT  17.088 37.776 17.28 37.8 ;
    END
  END o[343]
  PIN o[344]
    DIRECTION OUTPUT ;
    USE SIGNAL ;
    PORT
      LAYER M4 ;
        RECT  17.088 37.872 17.28 37.896 ;
    END
  END o[344]
  PIN o[345]
    DIRECTION OUTPUT ;
    USE SIGNAL ;
    PORT
      LAYER M4 ;
        RECT  17.088 37.968 17.28 37.992 ;
    END
  END o[345]
  PIN o[346]
    DIRECTION OUTPUT ;
    USE SIGNAL ;
    PORT
      LAYER M4 ;
        RECT  17.088 38.064 17.28 38.088 ;
    END
  END o[346]
  PIN o[347]
    DIRECTION OUTPUT ;
    USE SIGNAL ;
    PORT
      LAYER M4 ;
        RECT  17.088 38.16 17.28 38.184 ;
    END
  END o[347]
  PIN o[348]
    DIRECTION OUTPUT ;
    USE SIGNAL ;
    PORT
      LAYER M4 ;
        RECT  17.088 38.256 17.28 38.28 ;
    END
  END o[348]
  PIN o[349]
    DIRECTION OUTPUT ;
    USE SIGNAL ;
    PORT
      LAYER M4 ;
        RECT  17.088 38.352 17.28 38.376 ;
    END
  END o[349]
  PIN o[34]
    DIRECTION OUTPUT ;
    USE SIGNAL ;
    PORT
      LAYER M4 ;
        RECT  17.088 5.76 17.28 5.784 ;
    END
  END o[34]
  PIN o[350]
    DIRECTION OUTPUT ;
    USE SIGNAL ;
    PORT
      LAYER M4 ;
        RECT  17.088 38.496 17.28 38.52 ;
    END
  END o[350]
  PIN o[351]
    DIRECTION OUTPUT ;
    USE SIGNAL ;
    PORT
      LAYER M4 ;
        RECT  17.088 38.592 17.28 38.616 ;
    END
  END o[351]
  PIN o[352]
    DIRECTION OUTPUT ;
    USE SIGNAL ;
    PORT
      LAYER M4 ;
        RECT  17.088 38.688 17.28 38.712 ;
    END
  END o[352]
  PIN o[353]
    DIRECTION OUTPUT ;
    USE SIGNAL ;
    PORT
      LAYER M4 ;
        RECT  17.088 38.784 17.28 38.808 ;
    END
  END o[353]
  PIN o[354]
    DIRECTION OUTPUT ;
    USE SIGNAL ;
    PORT
      LAYER M4 ;
        RECT  17.088 38.88 17.28 38.904 ;
    END
  END o[354]
  PIN o[355]
    DIRECTION OUTPUT ;
    USE SIGNAL ;
    PORT
      LAYER M4 ;
        RECT  17.088 38.976 17.28 39 ;
    END
  END o[355]
  PIN o[356]
    DIRECTION OUTPUT ;
    USE SIGNAL ;
    PORT
      LAYER M4 ;
        RECT  17.088 39.12 17.28 39.144 ;
    END
  END o[356]
  PIN o[357]
    DIRECTION OUTPUT ;
    USE SIGNAL ;
    PORT
      LAYER M4 ;
        RECT  17.088 39.216 17.28 39.24 ;
    END
  END o[357]
  PIN o[358]
    DIRECTION OUTPUT ;
    USE SIGNAL ;
    PORT
      LAYER M4 ;
        RECT  17.088 39.312 17.28 39.336 ;
    END
  END o[358]
  PIN o[359]
    DIRECTION OUTPUT ;
    USE SIGNAL ;
    PORT
      LAYER M4 ;
        RECT  17.088 39.408 17.28 39.432 ;
    END
  END o[359]
  PIN o[35]
    DIRECTION OUTPUT ;
    USE SIGNAL ;
    PORT
      LAYER M4 ;
        RECT  17.088 5.856 17.28 5.88 ;
    END
  END o[35]
  PIN o[360]
    DIRECTION OUTPUT ;
    USE SIGNAL ;
    PORT
      LAYER M4 ;
        RECT  17.088 39.504 17.28 39.528 ;
    END
  END o[360]
  PIN o[361]
    DIRECTION OUTPUT ;
    USE SIGNAL ;
    PORT
      LAYER M4 ;
        RECT  17.088 39.6 17.28 39.624 ;
    END
  END o[361]
  PIN o[362]
    DIRECTION OUTPUT ;
    USE SIGNAL ;
    PORT
      LAYER M4 ;
        RECT  17.088 39.744 17.28 39.768 ;
    END
  END o[362]
  PIN o[363]
    DIRECTION OUTPUT ;
    USE SIGNAL ;
    PORT
      LAYER M4 ;
        RECT  17.088 39.84 17.28 39.864 ;
    END
  END o[363]
  PIN o[364]
    DIRECTION OUTPUT ;
    USE SIGNAL ;
    PORT
      LAYER M4 ;
        RECT  17.088 39.936 17.28 39.96 ;
    END
  END o[364]
  PIN o[365]
    DIRECTION OUTPUT ;
    USE SIGNAL ;
    PORT
      LAYER M4 ;
        RECT  17.088 40.032 17.28 40.056 ;
    END
  END o[365]
  PIN o[366]
    DIRECTION OUTPUT ;
    USE SIGNAL ;
    PORT
      LAYER M4 ;
        RECT  17.088 40.128 17.28 40.152 ;
    END
  END o[366]
  PIN o[367]
    DIRECTION OUTPUT ;
    USE SIGNAL ;
    PORT
      LAYER M4 ;
        RECT  17.088 40.224 17.28 40.248 ;
    END
  END o[367]
  PIN o[368]
    DIRECTION OUTPUT ;
    USE SIGNAL ;
    PORT
      LAYER M4 ;
        RECT  17.088 40.368 17.28 40.392 ;
    END
  END o[368]
  PIN o[369]
    DIRECTION OUTPUT ;
    USE SIGNAL ;
    PORT
      LAYER M4 ;
        RECT  17.088 40.464 17.28 40.488 ;
    END
  END o[369]
  PIN o[36]
    DIRECTION OUTPUT ;
    USE SIGNAL ;
    PORT
      LAYER M4 ;
        RECT  17.088 5.952 17.28 5.976 ;
    END
  END o[36]
  PIN o[370]
    DIRECTION OUTPUT ;
    USE SIGNAL ;
    PORT
      LAYER M4 ;
        RECT  17.088 40.56 17.28 40.584 ;
    END
  END o[370]
  PIN o[371]
    DIRECTION OUTPUT ;
    USE SIGNAL ;
    PORT
      LAYER M4 ;
        RECT  17.088 40.656 17.28 40.68 ;
    END
  END o[371]
  PIN o[372]
    DIRECTION OUTPUT ;
    USE SIGNAL ;
    PORT
      LAYER M4 ;
        RECT  17.088 40.752 17.28 40.776 ;
    END
  END o[372]
  PIN o[373]
    DIRECTION OUTPUT ;
    USE SIGNAL ;
    PORT
      LAYER M4 ;
        RECT  17.088 40.848 17.28 40.872 ;
    END
  END o[373]
  PIN o[374]
    DIRECTION OUTPUT ;
    USE SIGNAL ;
    PORT
      LAYER M4 ;
        RECT  17.088 40.944 17.28 40.968 ;
    END
  END o[374]
  PIN o[375]
    DIRECTION OUTPUT ;
    USE SIGNAL ;
    PORT
      LAYER M4 ;
        RECT  17.088 41.088 17.28 41.112 ;
    END
  END o[375]
  PIN o[376]
    DIRECTION OUTPUT ;
    USE SIGNAL ;
    PORT
      LAYER M4 ;
        RECT  17.088 41.184 17.28 41.208 ;
    END
  END o[376]
  PIN o[377]
    DIRECTION OUTPUT ;
    USE SIGNAL ;
    PORT
      LAYER M4 ;
        RECT  17.088 41.28 17.28 41.304 ;
    END
  END o[377]
  PIN o[378]
    DIRECTION OUTPUT ;
    USE SIGNAL ;
    PORT
      LAYER M4 ;
        RECT  17.088 41.376 17.28 41.4 ;
    END
  END o[378]
  PIN o[379]
    DIRECTION OUTPUT ;
    USE SIGNAL ;
    PORT
      LAYER M4 ;
        RECT  17.088 41.472 17.28 41.496 ;
    END
  END o[379]
  PIN o[37]
    DIRECTION OUTPUT ;
    USE SIGNAL ;
    PORT
      LAYER M4 ;
        RECT  17.088 6.048 17.28 6.072 ;
    END
  END o[37]
  PIN o[380]
    DIRECTION OUTPUT ;
    USE SIGNAL ;
    PORT
      LAYER M4 ;
        RECT  17.088 41.568 17.28 41.592 ;
    END
  END o[380]
  PIN o[381]
    DIRECTION OUTPUT ;
    USE SIGNAL ;
    PORT
      LAYER M4 ;
        RECT  17.088 41.712 17.28 41.736 ;
    END
  END o[381]
  PIN o[382]
    DIRECTION OUTPUT ;
    USE SIGNAL ;
    PORT
      LAYER M4 ;
        RECT  17.088 41.808 17.28 41.832 ;
    END
  END o[382]
  PIN o[383]
    DIRECTION OUTPUT ;
    USE SIGNAL ;
    PORT
      LAYER M4 ;
        RECT  17.088 41.904 17.28 41.928 ;
    END
  END o[383]
  PIN o[384]
    DIRECTION OUTPUT ;
    USE SIGNAL ;
    PORT
      LAYER M4 ;
        RECT  17.088 42 17.28 42.024 ;
    END
  END o[384]
  PIN o[385]
    DIRECTION OUTPUT ;
    USE SIGNAL ;
    PORT
      LAYER M4 ;
        RECT  17.088 42.096 17.28 42.12 ;
    END
  END o[385]
  PIN o[386]
    DIRECTION OUTPUT ;
    USE SIGNAL ;
    PORT
      LAYER M4 ;
        RECT  17.088 42.192 17.28 42.216 ;
    END
  END o[386]
  PIN o[387]
    DIRECTION OUTPUT ;
    USE SIGNAL ;
    PORT
      LAYER M4 ;
        RECT  17.088 42.336 17.28 42.36 ;
    END
  END o[387]
  PIN o[388]
    DIRECTION OUTPUT ;
    USE SIGNAL ;
    PORT
      LAYER M4 ;
        RECT  17.088 42.432 17.28 42.456 ;
    END
  END o[388]
  PIN o[389]
    DIRECTION OUTPUT ;
    USE SIGNAL ;
    PORT
      LAYER M4 ;
        RECT  17.088 42.528 17.28 42.552 ;
    END
  END o[389]
  PIN o[38]
    DIRECTION OUTPUT ;
    USE SIGNAL ;
    PORT
      LAYER M4 ;
        RECT  17.088 6.144 17.28 6.168 ;
    END
  END o[38]
  PIN o[390]
    DIRECTION OUTPUT ;
    USE SIGNAL ;
    PORT
      LAYER M4 ;
        RECT  17.088 42.624 17.28 42.648 ;
    END
  END o[390]
  PIN o[391]
    DIRECTION OUTPUT ;
    USE SIGNAL ;
    PORT
      LAYER M4 ;
        RECT  17.088 42.72 17.28 42.744 ;
    END
  END o[391]
  PIN o[392]
    DIRECTION OUTPUT ;
    USE SIGNAL ;
    PORT
      LAYER M4 ;
        RECT  17.088 42.816 17.28 42.84 ;
    END
  END o[392]
  PIN o[393]
    DIRECTION OUTPUT ;
    USE SIGNAL ;
    PORT
      LAYER M4 ;
        RECT  17.088 42.912 17.28 42.936 ;
    END
  END o[393]
  PIN o[394]
    DIRECTION OUTPUT ;
    USE SIGNAL ;
    PORT
      LAYER M4 ;
        RECT  17.088 43.056 17.28 43.08 ;
    END
  END o[394]
  PIN o[395]
    DIRECTION OUTPUT ;
    USE SIGNAL ;
    PORT
      LAYER M4 ;
        RECT  17.088 43.152 17.28 43.176 ;
    END
  END o[395]
  PIN o[396]
    DIRECTION OUTPUT ;
    USE SIGNAL ;
    PORT
      LAYER M4 ;
        RECT  17.088 43.248 17.28 43.272 ;
    END
  END o[396]
  PIN o[397]
    DIRECTION OUTPUT ;
    USE SIGNAL ;
    PORT
      LAYER M4 ;
        RECT  17.088 43.344 17.28 43.368 ;
    END
  END o[397]
  PIN o[398]
    DIRECTION OUTPUT ;
    USE SIGNAL ;
    PORT
      LAYER M4 ;
        RECT  17.088 43.44 17.28 43.464 ;
    END
  END o[398]
  PIN o[399]
    DIRECTION OUTPUT ;
    USE SIGNAL ;
    PORT
      LAYER M4 ;
        RECT  17.088 43.536 17.28 43.56 ;
    END
  END o[399]
  PIN o[39]
    DIRECTION OUTPUT ;
    USE SIGNAL ;
    PORT
      LAYER M4 ;
        RECT  17.088 6.24 17.28 6.264 ;
    END
  END o[39]
  PIN o[3]
    DIRECTION OUTPUT ;
    USE SIGNAL ;
    PORT
      LAYER M4 ;
        RECT  17.088 2.544 17.28 2.568 ;
    END
  END o[3]
  PIN o[400]
    DIRECTION OUTPUT ;
    USE SIGNAL ;
    PORT
      LAYER M4 ;
        RECT  17.088 43.68 17.28 43.704 ;
    END
  END o[400]
  PIN o[401]
    DIRECTION OUTPUT ;
    USE SIGNAL ;
    PORT
      LAYER M4 ;
        RECT  17.088 43.776 17.28 43.8 ;
    END
  END o[401]
  PIN o[402]
    DIRECTION OUTPUT ;
    USE SIGNAL ;
    PORT
      LAYER M4 ;
        RECT  17.088 43.872 17.28 43.896 ;
    END
  END o[402]
  PIN o[403]
    DIRECTION OUTPUT ;
    USE SIGNAL ;
    PORT
      LAYER M4 ;
        RECT  17.088 43.968 17.28 43.992 ;
    END
  END o[403]
  PIN o[404]
    DIRECTION OUTPUT ;
    USE SIGNAL ;
    PORT
      LAYER M4 ;
        RECT  17.088 44.064 17.28 44.088 ;
    END
  END o[404]
  PIN o[405]
    DIRECTION OUTPUT ;
    USE SIGNAL ;
    PORT
      LAYER M4 ;
        RECT  17.088 44.16 17.28 44.184 ;
    END
  END o[405]
  PIN o[406]
    DIRECTION OUTPUT ;
    USE SIGNAL ;
    PORT
      LAYER M4 ;
        RECT  17.088 44.304 17.28 44.328 ;
    END
  END o[406]
  PIN o[407]
    DIRECTION OUTPUT ;
    USE SIGNAL ;
    PORT
      LAYER M4 ;
        RECT  17.088 44.4 17.28 44.424 ;
    END
  END o[407]
  PIN o[408]
    DIRECTION OUTPUT ;
    USE SIGNAL ;
    PORT
      LAYER M4 ;
        RECT  17.088 44.496 17.28 44.52 ;
    END
  END o[408]
  PIN o[409]
    DIRECTION OUTPUT ;
    USE SIGNAL ;
    PORT
      LAYER M4 ;
        RECT  17.088 44.592 17.28 44.616 ;
    END
  END o[409]
  PIN o[40]
    DIRECTION OUTPUT ;
    USE SIGNAL ;
    PORT
      LAYER M4 ;
        RECT  17.088 6.384 17.28 6.408 ;
    END
  END o[40]
  PIN o[410]
    DIRECTION OUTPUT ;
    USE SIGNAL ;
    PORT
      LAYER M4 ;
        RECT  17.088 44.688 17.28 44.712 ;
    END
  END o[410]
  PIN o[411]
    DIRECTION OUTPUT ;
    USE SIGNAL ;
    PORT
      LAYER M4 ;
        RECT  17.088 44.784 17.28 44.808 ;
    END
  END o[411]
  PIN o[412]
    DIRECTION OUTPUT ;
    USE SIGNAL ;
    PORT
      LAYER M4 ;
        RECT  17.088 44.88 17.28 44.904 ;
    END
  END o[412]
  PIN o[413]
    DIRECTION OUTPUT ;
    USE SIGNAL ;
    PORT
      LAYER M4 ;
        RECT  17.088 45.024 17.28 45.048 ;
    END
  END o[413]
  PIN o[414]
    DIRECTION OUTPUT ;
    USE SIGNAL ;
    PORT
      LAYER M4 ;
        RECT  17.088 45.12 17.28 45.144 ;
    END
  END o[414]
  PIN o[415]
    DIRECTION OUTPUT ;
    USE SIGNAL ;
    PORT
      LAYER M4 ;
        RECT  17.088 45.216 17.28 45.24 ;
    END
  END o[415]
  PIN o[416]
    DIRECTION OUTPUT ;
    USE SIGNAL ;
    PORT
      LAYER M4 ;
        RECT  17.088 45.312 17.28 45.336 ;
    END
  END o[416]
  PIN o[417]
    DIRECTION OUTPUT ;
    USE SIGNAL ;
    PORT
      LAYER M4 ;
        RECT  17.088 45.408 17.28 45.432 ;
    END
  END o[417]
  PIN o[418]
    DIRECTION OUTPUT ;
    USE SIGNAL ;
    PORT
      LAYER M4 ;
        RECT  17.088 45.504 17.28 45.528 ;
    END
  END o[418]
  PIN o[419]
    DIRECTION OUTPUT ;
    USE SIGNAL ;
    PORT
      LAYER M4 ;
        RECT  17.088 45.648 17.28 45.672 ;
    END
  END o[419]
  PIN o[41]
    DIRECTION OUTPUT ;
    USE SIGNAL ;
    PORT
      LAYER M4 ;
        RECT  17.088 6.48 17.28 6.504 ;
    END
  END o[41]
  PIN o[420]
    DIRECTION OUTPUT ;
    USE SIGNAL ;
    PORT
      LAYER M4 ;
        RECT  17.088 45.744 17.28 45.768 ;
    END
  END o[420]
  PIN o[421]
    DIRECTION OUTPUT ;
    USE SIGNAL ;
    PORT
      LAYER M4 ;
        RECT  17.088 45.84 17.28 45.864 ;
    END
  END o[421]
  PIN o[422]
    DIRECTION OUTPUT ;
    USE SIGNAL ;
    PORT
      LAYER M4 ;
        RECT  17.088 45.936 17.28 45.96 ;
    END
  END o[422]
  PIN o[423]
    DIRECTION OUTPUT ;
    USE SIGNAL ;
    PORT
      LAYER M4 ;
        RECT  17.088 46.032 17.28 46.056 ;
    END
  END o[423]
  PIN o[424]
    DIRECTION OUTPUT ;
    USE SIGNAL ;
    PORT
      LAYER M4 ;
        RECT  17.088 46.128 17.28 46.152 ;
    END
  END o[424]
  PIN o[425]
    DIRECTION OUTPUT ;
    USE SIGNAL ;
    PORT
      LAYER M4 ;
        RECT  17.088 46.272 17.28 46.296 ;
    END
  END o[425]
  PIN o[426]
    DIRECTION OUTPUT ;
    USE SIGNAL ;
    PORT
      LAYER M4 ;
        RECT  17.088 46.368 17.28 46.392 ;
    END
  END o[426]
  PIN o[427]
    DIRECTION OUTPUT ;
    USE SIGNAL ;
    PORT
      LAYER M4 ;
        RECT  17.088 46.464 17.28 46.488 ;
    END
  END o[427]
  PIN o[428]
    DIRECTION OUTPUT ;
    USE SIGNAL ;
    PORT
      LAYER M4 ;
        RECT  17.088 46.56 17.28 46.584 ;
    END
  END o[428]
  PIN o[429]
    DIRECTION OUTPUT ;
    USE SIGNAL ;
    PORT
      LAYER M4 ;
        RECT  17.088 46.656 17.28 46.68 ;
    END
  END o[429]
  PIN o[42]
    DIRECTION OUTPUT ;
    USE SIGNAL ;
    PORT
      LAYER M4 ;
        RECT  17.088 6.576 17.28 6.6 ;
    END
  END o[42]
  PIN o[430]
    DIRECTION OUTPUT ;
    USE SIGNAL ;
    PORT
      LAYER M4 ;
        RECT  17.088 46.752 17.28 46.776 ;
    END
  END o[430]
  PIN o[431]
    DIRECTION OUTPUT ;
    USE SIGNAL ;
    PORT
      LAYER M4 ;
        RECT  17.088 46.848 17.28 46.872 ;
    END
  END o[431]
  PIN o[432]
    DIRECTION OUTPUT ;
    USE SIGNAL ;
    PORT
      LAYER M4 ;
        RECT  17.088 46.992 17.28 47.016 ;
    END
  END o[432]
  PIN o[433]
    DIRECTION OUTPUT ;
    USE SIGNAL ;
    PORT
      LAYER M4 ;
        RECT  17.088 47.088 17.28 47.112 ;
    END
  END o[433]
  PIN o[434]
    DIRECTION OUTPUT ;
    USE SIGNAL ;
    PORT
      LAYER M4 ;
        RECT  17.088 47.184 17.28 47.208 ;
    END
  END o[434]
  PIN o[435]
    DIRECTION OUTPUT ;
    USE SIGNAL ;
    PORT
      LAYER M4 ;
        RECT  17.088 47.28 17.28 47.304 ;
    END
  END o[435]
  PIN o[436]
    DIRECTION OUTPUT ;
    USE SIGNAL ;
    PORT
      LAYER M4 ;
        RECT  17.088 47.376 17.28 47.4 ;
    END
  END o[436]
  PIN o[437]
    DIRECTION OUTPUT ;
    USE SIGNAL ;
    PORT
      LAYER M4 ;
        RECT  17.088 47.472 17.28 47.496 ;
    END
  END o[437]
  PIN o[438]
    DIRECTION OUTPUT ;
    USE SIGNAL ;
    PORT
      LAYER M4 ;
        RECT  17.088 47.616 17.28 47.64 ;
    END
  END o[438]
  PIN o[439]
    DIRECTION OUTPUT ;
    USE SIGNAL ;
    PORT
      LAYER M4 ;
        RECT  17.088 47.712 17.28 47.736 ;
    END
  END o[439]
  PIN o[43]
    DIRECTION OUTPUT ;
    USE SIGNAL ;
    PORT
      LAYER M4 ;
        RECT  17.088 6.672 17.28 6.696 ;
    END
  END o[43]
  PIN o[440]
    DIRECTION OUTPUT ;
    USE SIGNAL ;
    PORT
      LAYER M4 ;
        RECT  17.088 47.808 17.28 47.832 ;
    END
  END o[440]
  PIN o[441]
    DIRECTION OUTPUT ;
    USE SIGNAL ;
    PORT
      LAYER M4 ;
        RECT  17.088 47.904 17.28 47.928 ;
    END
  END o[441]
  PIN o[442]
    DIRECTION OUTPUT ;
    USE SIGNAL ;
    PORT
      LAYER M4 ;
        RECT  17.088 48 17.28 48.024 ;
    END
  END o[442]
  PIN o[443]
    DIRECTION OUTPUT ;
    USE SIGNAL ;
    PORT
      LAYER M4 ;
        RECT  17.088 48.096 17.28 48.12 ;
    END
  END o[443]
  PIN o[444]
    DIRECTION OUTPUT ;
    USE SIGNAL ;
    PORT
      LAYER M4 ;
        RECT  17.088 48.24 17.28 48.264 ;
    END
  END o[444]
  PIN o[445]
    DIRECTION OUTPUT ;
    USE SIGNAL ;
    PORT
      LAYER M4 ;
        RECT  17.088 48.336 17.28 48.36 ;
    END
  END o[445]
  PIN o[446]
    DIRECTION OUTPUT ;
    USE SIGNAL ;
    PORT
      LAYER M4 ;
        RECT  17.088 48.432 17.28 48.456 ;
    END
  END o[446]
  PIN o[447]
    DIRECTION OUTPUT ;
    USE SIGNAL ;
    PORT
      LAYER M4 ;
        RECT  17.088 48.528 17.28 48.552 ;
    END
  END o[447]
  PIN o[448]
    DIRECTION OUTPUT ;
    USE SIGNAL ;
    PORT
      LAYER M4 ;
        RECT  17.088 48.624 17.28 48.648 ;
    END
  END o[448]
  PIN o[449]
    DIRECTION OUTPUT ;
    USE SIGNAL ;
    PORT
      LAYER M4 ;
        RECT  17.088 48.72 17.28 48.744 ;
    END
  END o[449]
  PIN o[44]
    DIRECTION OUTPUT ;
    USE SIGNAL ;
    PORT
      LAYER M4 ;
        RECT  17.088 6.768 17.28 6.792 ;
    END
  END o[44]
  PIN o[450]
    DIRECTION OUTPUT ;
    USE SIGNAL ;
    PORT
      LAYER M4 ;
        RECT  17.088 48.816 17.28 48.84 ;
    END
  END o[450]
  PIN o[451]
    DIRECTION OUTPUT ;
    USE SIGNAL ;
    PORT
      LAYER M4 ;
        RECT  17.088 48.96 17.28 48.984 ;
    END
  END o[451]
  PIN o[452]
    DIRECTION OUTPUT ;
    USE SIGNAL ;
    PORT
      LAYER M4 ;
        RECT  17.088 49.056 17.28 49.08 ;
    END
  END o[452]
  PIN o[453]
    DIRECTION OUTPUT ;
    USE SIGNAL ;
    PORT
      LAYER M4 ;
        RECT  17.088 49.152 17.28 49.176 ;
    END
  END o[453]
  PIN o[454]
    DIRECTION OUTPUT ;
    USE SIGNAL ;
    PORT
      LAYER M4 ;
        RECT  17.088 49.248 17.28 49.272 ;
    END
  END o[454]
  PIN o[455]
    DIRECTION OUTPUT ;
    USE SIGNAL ;
    PORT
      LAYER M4 ;
        RECT  17.088 49.344 17.28 49.368 ;
    END
  END o[455]
  PIN o[456]
    DIRECTION OUTPUT ;
    USE SIGNAL ;
    PORT
      LAYER M4 ;
        RECT  17.088 49.44 17.28 49.464 ;
    END
  END o[456]
  PIN o[457]
    DIRECTION OUTPUT ;
    USE SIGNAL ;
    PORT
      LAYER M4 ;
        RECT  17.088 49.584 17.28 49.608 ;
    END
  END o[457]
  PIN o[458]
    DIRECTION OUTPUT ;
    USE SIGNAL ;
    PORT
      LAYER M4 ;
        RECT  17.088 49.68 17.28 49.704 ;
    END
  END o[458]
  PIN o[459]
    DIRECTION OUTPUT ;
    USE SIGNAL ;
    PORT
      LAYER M4 ;
        RECT  17.088 49.776 17.28 49.8 ;
    END
  END o[459]
  PIN o[45]
    DIRECTION OUTPUT ;
    USE SIGNAL ;
    PORT
      LAYER M4 ;
        RECT  17.088 6.864 17.28 6.888 ;
    END
  END o[45]
  PIN o[460]
    DIRECTION OUTPUT ;
    USE SIGNAL ;
    PORT
      LAYER M4 ;
        RECT  17.088 49.872 17.28 49.896 ;
    END
  END o[460]
  PIN o[461]
    DIRECTION OUTPUT ;
    USE SIGNAL ;
    PORT
      LAYER M4 ;
        RECT  17.088 49.968 17.28 49.992 ;
    END
  END o[461]
  PIN o[462]
    DIRECTION OUTPUT ;
    USE SIGNAL ;
    PORT
      LAYER M4 ;
        RECT  17.088 50.064 17.28 50.088 ;
    END
  END o[462]
  PIN o[463]
    DIRECTION OUTPUT ;
    USE SIGNAL ;
    PORT
      LAYER M4 ;
        RECT  17.088 50.208 17.28 50.232 ;
    END
  END o[463]
  PIN o[464]
    DIRECTION OUTPUT ;
    USE SIGNAL ;
    PORT
      LAYER M4 ;
        RECT  17.088 50.304 17.28 50.328 ;
    END
  END o[464]
  PIN o[465]
    DIRECTION OUTPUT ;
    USE SIGNAL ;
    PORT
      LAYER M4 ;
        RECT  17.088 50.4 17.28 50.424 ;
    END
  END o[465]
  PIN o[466]
    DIRECTION OUTPUT ;
    USE SIGNAL ;
    PORT
      LAYER M4 ;
        RECT  17.088 50.496 17.28 50.52 ;
    END
  END o[466]
  PIN o[467]
    DIRECTION OUTPUT ;
    USE SIGNAL ;
    PORT
      LAYER M4 ;
        RECT  17.088 50.592 17.28 50.616 ;
    END
  END o[467]
  PIN o[468]
    DIRECTION OUTPUT ;
    USE SIGNAL ;
    PORT
      LAYER M4 ;
        RECT  17.088 50.688 17.28 50.712 ;
    END
  END o[468]
  PIN o[469]
    DIRECTION OUTPUT ;
    USE SIGNAL ;
    PORT
      LAYER M4 ;
        RECT  17.088 50.784 17.28 50.808 ;
    END
  END o[469]
  PIN o[46]
    DIRECTION OUTPUT ;
    USE SIGNAL ;
    PORT
      LAYER M4 ;
        RECT  17.088 7.008 17.28 7.032 ;
    END
  END o[46]
  PIN o[470]
    DIRECTION OUTPUT ;
    USE SIGNAL ;
    PORT
      LAYER M4 ;
        RECT  17.088 50.928 17.28 50.952 ;
    END
  END o[470]
  PIN o[471]
    DIRECTION OUTPUT ;
    USE SIGNAL ;
    PORT
      LAYER M4 ;
        RECT  17.088 51.024 17.28 51.048 ;
    END
  END o[471]
  PIN o[472]
    DIRECTION OUTPUT ;
    USE SIGNAL ;
    PORT
      LAYER M4 ;
        RECT  17.088 51.12 17.28 51.144 ;
    END
  END o[472]
  PIN o[473]
    DIRECTION OUTPUT ;
    USE SIGNAL ;
    PORT
      LAYER M4 ;
        RECT  17.088 51.216 17.28 51.24 ;
    END
  END o[473]
  PIN o[474]
    DIRECTION OUTPUT ;
    USE SIGNAL ;
    PORT
      LAYER M4 ;
        RECT  17.088 51.312 17.28 51.336 ;
    END
  END o[474]
  PIN o[475]
    DIRECTION OUTPUT ;
    USE SIGNAL ;
    PORT
      LAYER M4 ;
        RECT  17.088 51.408 17.28 51.432 ;
    END
  END o[475]
  PIN o[476]
    DIRECTION OUTPUT ;
    USE SIGNAL ;
    PORT
      LAYER M4 ;
        RECT  17.088 51.552 17.28 51.576 ;
    END
  END o[476]
  PIN o[477]
    DIRECTION OUTPUT ;
    USE SIGNAL ;
    PORT
      LAYER M4 ;
        RECT  17.088 51.648 17.28 51.672 ;
    END
  END o[477]
  PIN o[478]
    DIRECTION OUTPUT ;
    USE SIGNAL ;
    PORT
      LAYER M4 ;
        RECT  17.088 51.744 17.28 51.768 ;
    END
  END o[478]
  PIN o[479]
    DIRECTION OUTPUT ;
    USE SIGNAL ;
    PORT
      LAYER M4 ;
        RECT  17.088 51.84 17.28 51.864 ;
    END
  END o[479]
  PIN o[47]
    DIRECTION OUTPUT ;
    USE SIGNAL ;
    PORT
      LAYER M4 ;
        RECT  17.088 7.104 17.28 7.128 ;
    END
  END o[47]
  PIN o[480]
    DIRECTION OUTPUT ;
    USE SIGNAL ;
    PORT
      LAYER M4 ;
        RECT  17.088 51.936 17.28 51.96 ;
    END
  END o[480]
  PIN o[481]
    DIRECTION OUTPUT ;
    USE SIGNAL ;
    PORT
      LAYER M4 ;
        RECT  17.088 52.032 17.28 52.056 ;
    END
  END o[481]
  PIN o[482]
    DIRECTION OUTPUT ;
    USE SIGNAL ;
    PORT
      LAYER M4 ;
        RECT  17.088 52.176 17.28 52.2 ;
    END
  END o[482]
  PIN o[483]
    DIRECTION OUTPUT ;
    USE SIGNAL ;
    PORT
      LAYER M4 ;
        RECT  17.088 52.272 17.28 52.296 ;
    END
  END o[483]
  PIN o[484]
    DIRECTION OUTPUT ;
    USE SIGNAL ;
    PORT
      LAYER M4 ;
        RECT  17.088 52.368 17.28 52.392 ;
    END
  END o[484]
  PIN o[485]
    DIRECTION OUTPUT ;
    USE SIGNAL ;
    PORT
      LAYER M4 ;
        RECT  17.088 52.464 17.28 52.488 ;
    END
  END o[485]
  PIN o[486]
    DIRECTION OUTPUT ;
    USE SIGNAL ;
    PORT
      LAYER M4 ;
        RECT  17.088 52.56 17.28 52.584 ;
    END
  END o[486]
  PIN o[487]
    DIRECTION OUTPUT ;
    USE SIGNAL ;
    PORT
      LAYER M4 ;
        RECT  17.088 52.656 17.28 52.68 ;
    END
  END o[487]
  PIN o[488]
    DIRECTION OUTPUT ;
    USE SIGNAL ;
    PORT
      LAYER M4 ;
        RECT  17.088 52.752 17.28 52.776 ;
    END
  END o[488]
  PIN o[489]
    DIRECTION OUTPUT ;
    USE SIGNAL ;
    PORT
      LAYER M4 ;
        RECT  17.088 52.896 17.28 52.92 ;
    END
  END o[489]
  PIN o[48]
    DIRECTION OUTPUT ;
    USE SIGNAL ;
    PORT
      LAYER M4 ;
        RECT  17.088 7.2 17.28 7.224 ;
    END
  END o[48]
  PIN o[490]
    DIRECTION OUTPUT ;
    USE SIGNAL ;
    PORT
      LAYER M4 ;
        RECT  17.088 52.992 17.28 53.016 ;
    END
  END o[490]
  PIN o[491]
    DIRECTION OUTPUT ;
    USE SIGNAL ;
    PORT
      LAYER M4 ;
        RECT  17.088 53.088 17.28 53.112 ;
    END
  END o[491]
  PIN o[492]
    DIRECTION OUTPUT ;
    USE SIGNAL ;
    PORT
      LAYER M4 ;
        RECT  17.088 53.184 17.28 53.208 ;
    END
  END o[492]
  PIN o[493]
    DIRECTION OUTPUT ;
    USE SIGNAL ;
    PORT
      LAYER M4 ;
        RECT  17.088 53.28 17.28 53.304 ;
    END
  END o[493]
  PIN o[494]
    DIRECTION OUTPUT ;
    USE SIGNAL ;
    PORT
      LAYER M4 ;
        RECT  17.088 53.376 17.28 53.4 ;
    END
  END o[494]
  PIN o[495]
    DIRECTION OUTPUT ;
    USE SIGNAL ;
    PORT
      LAYER M4 ;
        RECT  17.088 53.52 17.28 53.544 ;
    END
  END o[495]
  PIN o[496]
    DIRECTION OUTPUT ;
    USE SIGNAL ;
    PORT
      LAYER M4 ;
        RECT  17.088 53.616 17.28 53.64 ;
    END
  END o[496]
  PIN o[497]
    DIRECTION OUTPUT ;
    USE SIGNAL ;
    PORT
      LAYER M4 ;
        RECT  17.088 53.712 17.28 53.736 ;
    END
  END o[497]
  PIN o[498]
    DIRECTION OUTPUT ;
    USE SIGNAL ;
    PORT
      LAYER M4 ;
        RECT  17.088 53.808 17.28 53.832 ;
    END
  END o[498]
  PIN o[499]
    DIRECTION OUTPUT ;
    USE SIGNAL ;
    PORT
      LAYER M4 ;
        RECT  17.088 53.904 17.28 53.928 ;
    END
  END o[499]
  PIN o[49]
    DIRECTION OUTPUT ;
    USE SIGNAL ;
    PORT
      LAYER M4 ;
        RECT  17.088 7.296 17.28 7.32 ;
    END
  END o[49]
  PIN o[4]
    DIRECTION OUTPUT ;
    USE SIGNAL ;
    PORT
      LAYER M4 ;
        RECT  17.088 2.64 17.28 2.664 ;
    END
  END o[4]
  PIN o[500]
    DIRECTION OUTPUT ;
    USE SIGNAL ;
    PORT
      LAYER M4 ;
        RECT  17.088 54 17.28 54.024 ;
    END
  END o[500]
  PIN o[501]
    DIRECTION OUTPUT ;
    USE SIGNAL ;
    PORT
      LAYER M4 ;
        RECT  17.088 54.144 17.28 54.168 ;
    END
  END o[501]
  PIN o[502]
    DIRECTION OUTPUT ;
    USE SIGNAL ;
    PORT
      LAYER M4 ;
        RECT  17.088 54.24 17.28 54.264 ;
    END
  END o[502]
  PIN o[503]
    DIRECTION OUTPUT ;
    USE SIGNAL ;
    PORT
      LAYER M4 ;
        RECT  17.088 54.336 17.28 54.36 ;
    END
  END o[503]
  PIN o[504]
    DIRECTION OUTPUT ;
    USE SIGNAL ;
    PORT
      LAYER M4 ;
        RECT  17.088 54.432 17.28 54.456 ;
    END
  END o[504]
  PIN o[505]
    DIRECTION OUTPUT ;
    USE SIGNAL ;
    PORT
      LAYER M4 ;
        RECT  17.088 54.528 17.28 54.552 ;
    END
  END o[505]
  PIN o[506]
    DIRECTION OUTPUT ;
    USE SIGNAL ;
    PORT
      LAYER M4 ;
        RECT  17.088 54.624 17.28 54.648 ;
    END
  END o[506]
  PIN o[507]
    DIRECTION OUTPUT ;
    USE SIGNAL ;
    PORT
      LAYER M4 ;
        RECT  17.088 54.72 17.28 54.744 ;
    END
  END o[507]
  PIN o[508]
    DIRECTION OUTPUT ;
    USE SIGNAL ;
    PORT
      LAYER M4 ;
        RECT  17.088 54.864 17.28 54.888 ;
    END
  END o[508]
  PIN o[509]
    DIRECTION OUTPUT ;
    USE SIGNAL ;
    PORT
      LAYER M4 ;
        RECT  17.088 54.96 17.28 54.984 ;
    END
  END o[509]
  PIN o[50]
    DIRECTION OUTPUT ;
    USE SIGNAL ;
    PORT
      LAYER M4 ;
        RECT  17.088 7.392 17.28 7.416 ;
    END
  END o[50]
  PIN o[510]
    DIRECTION OUTPUT ;
    USE SIGNAL ;
    PORT
      LAYER M4 ;
        RECT  17.088 55.056 17.28 55.08 ;
    END
  END o[510]
  PIN o[511]
    DIRECTION OUTPUT ;
    USE SIGNAL ;
    PORT
      LAYER M4 ;
        RECT  17.088 55.152 17.28 55.176 ;
    END
  END o[511]
  PIN o[512]
    DIRECTION OUTPUT ;
    USE SIGNAL ;
    PORT
      LAYER M4 ;
        RECT  17.088 55.248 17.28 55.272 ;
    END
  END o[512]
  PIN o[513]
    DIRECTION OUTPUT ;
    USE SIGNAL ;
    PORT
      LAYER M4 ;
        RECT  17.088 55.344 17.28 55.368 ;
    END
  END o[513]
  PIN o[514]
    DIRECTION OUTPUT ;
    USE SIGNAL ;
    PORT
      LAYER M4 ;
        RECT  17.088 55.488 17.28 55.512 ;
    END
  END o[514]
  PIN o[515]
    DIRECTION OUTPUT ;
    USE SIGNAL ;
    PORT
      LAYER M4 ;
        RECT  17.088 55.584 17.28 55.608 ;
    END
  END o[515]
  PIN o[516]
    DIRECTION OUTPUT ;
    USE SIGNAL ;
    PORT
      LAYER M4 ;
        RECT  17.088 55.68 17.28 55.704 ;
    END
  END o[516]
  PIN o[517]
    DIRECTION OUTPUT ;
    USE SIGNAL ;
    PORT
      LAYER M4 ;
        RECT  17.088 55.776 17.28 55.8 ;
    END
  END o[517]
  PIN o[518]
    DIRECTION OUTPUT ;
    USE SIGNAL ;
    PORT
      LAYER M4 ;
        RECT  17.088 55.872 17.28 55.896 ;
    END
  END o[518]
  PIN o[519]
    DIRECTION OUTPUT ;
    USE SIGNAL ;
    PORT
      LAYER M4 ;
        RECT  17.088 55.968 17.28 55.992 ;
    END
  END o[519]
  PIN o[51]
    DIRECTION OUTPUT ;
    USE SIGNAL ;
    PORT
      LAYER M4 ;
        RECT  17.088 7.488 17.28 7.512 ;
    END
  END o[51]
  PIN o[520]
    DIRECTION OUTPUT ;
    USE SIGNAL ;
    PORT
      LAYER M4 ;
        RECT  17.088 56.112 17.28 56.136 ;
    END
  END o[520]
  PIN o[521]
    DIRECTION OUTPUT ;
    USE SIGNAL ;
    PORT
      LAYER M4 ;
        RECT  17.088 56.208 17.28 56.232 ;
    END
  END o[521]
  PIN o[522]
    DIRECTION OUTPUT ;
    USE SIGNAL ;
    PORT
      LAYER M4 ;
        RECT  17.088 56.304 17.28 56.328 ;
    END
  END o[522]
  PIN o[523]
    DIRECTION OUTPUT ;
    USE SIGNAL ;
    PORT
      LAYER M4 ;
        RECT  17.088 56.4 17.28 56.424 ;
    END
  END o[523]
  PIN o[524]
    DIRECTION OUTPUT ;
    USE SIGNAL ;
    PORT
      LAYER M4 ;
        RECT  17.088 56.496 17.28 56.52 ;
    END
  END o[524]
  PIN o[525]
    DIRECTION OUTPUT ;
    USE SIGNAL ;
    PORT
      LAYER M4 ;
        RECT  17.088 56.592 17.28 56.616 ;
    END
  END o[525]
  PIN o[526]
    DIRECTION OUTPUT ;
    USE SIGNAL ;
    PORT
      LAYER M4 ;
        RECT  17.088 56.688 17.28 56.712 ;
    END
  END o[526]
  PIN o[527]
    DIRECTION OUTPUT ;
    USE SIGNAL ;
    PORT
      LAYER M4 ;
        RECT  17.088 56.832 17.28 56.856 ;
    END
  END o[527]
  PIN o[528]
    DIRECTION OUTPUT ;
    USE SIGNAL ;
    PORT
      LAYER M4 ;
        RECT  17.088 56.928 17.28 56.952 ;
    END
  END o[528]
  PIN o[529]
    DIRECTION OUTPUT ;
    USE SIGNAL ;
    PORT
      LAYER M4 ;
        RECT  17.088 57.024 17.28 57.048 ;
    END
  END o[529]
  PIN o[52]
    DIRECTION OUTPUT ;
    USE SIGNAL ;
    PORT
      LAYER M4 ;
        RECT  17.088 7.632 17.28 7.656 ;
    END
  END o[52]
  PIN o[530]
    DIRECTION OUTPUT ;
    USE SIGNAL ;
    PORT
      LAYER M4 ;
        RECT  17.088 57.12 17.28 57.144 ;
    END
  END o[530]
  PIN o[531]
    DIRECTION OUTPUT ;
    USE SIGNAL ;
    PORT
      LAYER M4 ;
        RECT  17.088 57.216 17.28 57.24 ;
    END
  END o[531]
  PIN o[532]
    DIRECTION OUTPUT ;
    USE SIGNAL ;
    PORT
      LAYER M4 ;
        RECT  17.088 57.312 17.28 57.336 ;
    END
  END o[532]
  PIN o[533]
    DIRECTION OUTPUT ;
    USE SIGNAL ;
    PORT
      LAYER M4 ;
        RECT  17.088 57.456 17.28 57.48 ;
    END
  END o[533]
  PIN o[534]
    DIRECTION OUTPUT ;
    USE SIGNAL ;
    PORT
      LAYER M4 ;
        RECT  17.088 57.552 17.28 57.576 ;
    END
  END o[534]
  PIN o[535]
    DIRECTION OUTPUT ;
    USE SIGNAL ;
    PORT
      LAYER M4 ;
        RECT  17.088 57.648 17.28 57.672 ;
    END
  END o[535]
  PIN o[536]
    DIRECTION OUTPUT ;
    USE SIGNAL ;
    PORT
      LAYER M4 ;
        RECT  17.088 57.744 17.28 57.768 ;
    END
  END o[536]
  PIN o[537]
    DIRECTION OUTPUT ;
    USE SIGNAL ;
    PORT
      LAYER M4 ;
        RECT  17.088 57.84 17.28 57.864 ;
    END
  END o[537]
  PIN o[538]
    DIRECTION OUTPUT ;
    USE SIGNAL ;
    PORT
      LAYER M4 ;
        RECT  17.088 57.936 17.28 57.96 ;
    END
  END o[538]
  PIN o[539]
    DIRECTION OUTPUT ;
    USE SIGNAL ;
    PORT
      LAYER M4 ;
        RECT  17.088 58.08 17.28 58.104 ;
    END
  END o[539]
  PIN o[53]
    DIRECTION OUTPUT ;
    USE SIGNAL ;
    PORT
      LAYER M4 ;
        RECT  17.088 7.728 17.28 7.752 ;
    END
  END o[53]
  PIN o[540]
    DIRECTION OUTPUT ;
    USE SIGNAL ;
    PORT
      LAYER M4 ;
        RECT  17.088 58.176 17.28 58.2 ;
    END
  END o[540]
  PIN o[541]
    DIRECTION OUTPUT ;
    USE SIGNAL ;
    PORT
      LAYER M4 ;
        RECT  17.088 58.272 17.28 58.296 ;
    END
  END o[541]
  PIN o[542]
    DIRECTION OUTPUT ;
    USE SIGNAL ;
    PORT
      LAYER M4 ;
        RECT  17.088 58.368 17.28 58.392 ;
    END
  END o[542]
  PIN o[543]
    DIRECTION OUTPUT ;
    USE SIGNAL ;
    PORT
      LAYER M4 ;
        RECT  17.088 58.464 17.28 58.488 ;
    END
  END o[543]
  PIN o[544]
    DIRECTION OUTPUT ;
    USE SIGNAL ;
    PORT
      LAYER M4 ;
        RECT  17.088 58.56 17.28 58.584 ;
    END
  END o[544]
  PIN o[545]
    DIRECTION OUTPUT ;
    USE SIGNAL ;
    PORT
      LAYER M4 ;
        RECT  17.088 58.656 17.28 58.68 ;
    END
  END o[545]
  PIN o[546]
    DIRECTION OUTPUT ;
    USE SIGNAL ;
    PORT
      LAYER M4 ;
        RECT  17.088 58.8 17.28 58.824 ;
    END
  END o[546]
  PIN o[547]
    DIRECTION OUTPUT ;
    USE SIGNAL ;
    PORT
      LAYER M4 ;
        RECT  17.088 58.896 17.28 58.92 ;
    END
  END o[547]
  PIN o[548]
    DIRECTION OUTPUT ;
    USE SIGNAL ;
    PORT
      LAYER M4 ;
        RECT  17.088 58.992 17.28 59.016 ;
    END
  END o[548]
  PIN o[549]
    DIRECTION OUTPUT ;
    USE SIGNAL ;
    PORT
      LAYER M4 ;
        RECT  17.088 59.088 17.28 59.112 ;
    END
  END o[549]
  PIN o[54]
    DIRECTION OUTPUT ;
    USE SIGNAL ;
    PORT
      LAYER M4 ;
        RECT  17.088 7.824 17.28 7.848 ;
    END
  END o[54]
  PIN o[550]
    DIRECTION OUTPUT ;
    USE SIGNAL ;
    PORT
      LAYER M4 ;
        RECT  17.088 59.184 17.28 59.208 ;
    END
  END o[550]
  PIN o[551]
    DIRECTION OUTPUT ;
    USE SIGNAL ;
    PORT
      LAYER M4 ;
        RECT  17.088 59.28 17.28 59.304 ;
    END
  END o[551]
  PIN o[552]
    DIRECTION OUTPUT ;
    USE SIGNAL ;
    PORT
      LAYER M4 ;
        RECT  17.088 59.424 17.28 59.448 ;
    END
  END o[552]
  PIN o[553]
    DIRECTION OUTPUT ;
    USE SIGNAL ;
    PORT
      LAYER M4 ;
        RECT  17.088 59.52 17.28 59.544 ;
    END
  END o[553]
  PIN o[554]
    DIRECTION OUTPUT ;
    USE SIGNAL ;
    PORT
      LAYER M4 ;
        RECT  17.088 59.616 17.28 59.64 ;
    END
  END o[554]
  PIN o[555]
    DIRECTION OUTPUT ;
    USE SIGNAL ;
    PORT
      LAYER M4 ;
        RECT  17.088 59.712 17.28 59.736 ;
    END
  END o[555]
  PIN o[556]
    DIRECTION OUTPUT ;
    USE SIGNAL ;
    PORT
      LAYER M4 ;
        RECT  17.088 59.808 17.28 59.832 ;
    END
  END o[556]
  PIN o[557]
    DIRECTION OUTPUT ;
    USE SIGNAL ;
    PORT
      LAYER M4 ;
        RECT  17.088 59.904 17.28 59.928 ;
    END
  END o[557]
  PIN o[558]
    DIRECTION OUTPUT ;
    USE SIGNAL ;
    PORT
      LAYER M4 ;
        RECT  17.088 60.048 17.28 60.072 ;
    END
  END o[558]
  PIN o[559]
    DIRECTION OUTPUT ;
    USE SIGNAL ;
    PORT
      LAYER M4 ;
        RECT  17.088 60.144 17.28 60.168 ;
    END
  END o[559]
  PIN o[55]
    DIRECTION OUTPUT ;
    USE SIGNAL ;
    PORT
      LAYER M4 ;
        RECT  17.088 7.92 17.28 7.944 ;
    END
  END o[55]
  PIN o[560]
    DIRECTION OUTPUT ;
    USE SIGNAL ;
    PORT
      LAYER M4 ;
        RECT  17.088 60.24 17.28 60.264 ;
    END
  END o[560]
  PIN o[561]
    DIRECTION OUTPUT ;
    USE SIGNAL ;
    PORT
      LAYER M4 ;
        RECT  17.088 60.336 17.28 60.36 ;
    END
  END o[561]
  PIN o[56]
    DIRECTION OUTPUT ;
    USE SIGNAL ;
    PORT
      LAYER M4 ;
        RECT  17.088 8.016 17.28 8.04 ;
    END
  END o[56]
  PIN o[57]
    DIRECTION OUTPUT ;
    USE SIGNAL ;
    PORT
      LAYER M4 ;
        RECT  17.088 8.112 17.28 8.136 ;
    END
  END o[57]
  PIN o[58]
    DIRECTION OUTPUT ;
    USE SIGNAL ;
    PORT
      LAYER M4 ;
        RECT  17.088 8.208 17.28 8.232 ;
    END
  END o[58]
  PIN o[59]
    DIRECTION OUTPUT ;
    USE SIGNAL ;
    PORT
      LAYER M4 ;
        RECT  17.088 8.352 17.28 8.376 ;
    END
  END o[59]
  PIN o[5]
    DIRECTION OUTPUT ;
    USE SIGNAL ;
    PORT
      LAYER M4 ;
        RECT  17.088 2.736 17.28 2.76 ;
    END
  END o[5]
  PIN o[60]
    DIRECTION OUTPUT ;
    USE SIGNAL ;
    PORT
      LAYER M4 ;
        RECT  17.088 8.448 17.28 8.472 ;
    END
  END o[60]
  PIN o[61]
    DIRECTION OUTPUT ;
    USE SIGNAL ;
    PORT
      LAYER M4 ;
        RECT  17.088 8.544 17.28 8.568 ;
    END
  END o[61]
  PIN o[62]
    DIRECTION OUTPUT ;
    USE SIGNAL ;
    PORT
      LAYER M4 ;
        RECT  17.088 8.64 17.28 8.664 ;
    END
  END o[62]
  PIN o[63]
    DIRECTION OUTPUT ;
    USE SIGNAL ;
    PORT
      LAYER M4 ;
        RECT  17.088 8.736 17.28 8.76 ;
    END
  END o[63]
  PIN o[64]
    DIRECTION OUTPUT ;
    USE SIGNAL ;
    PORT
      LAYER M4 ;
        RECT  17.088 8.832 17.28 8.856 ;
    END
  END o[64]
  PIN o[65]
    DIRECTION OUTPUT ;
    USE SIGNAL ;
    PORT
      LAYER M4 ;
        RECT  17.088 8.976 17.28 9 ;
    END
  END o[65]
  PIN o[66]
    DIRECTION OUTPUT ;
    USE SIGNAL ;
    PORT
      LAYER M4 ;
        RECT  17.088 9.072 17.28 9.096 ;
    END
  END o[66]
  PIN o[67]
    DIRECTION OUTPUT ;
    USE SIGNAL ;
    PORT
      LAYER M4 ;
        RECT  17.088 9.168 17.28 9.192 ;
    END
  END o[67]
  PIN o[68]
    DIRECTION OUTPUT ;
    USE SIGNAL ;
    PORT
      LAYER M4 ;
        RECT  17.088 9.264 17.28 9.288 ;
    END
  END o[68]
  PIN o[69]
    DIRECTION OUTPUT ;
    USE SIGNAL ;
    PORT
      LAYER M4 ;
        RECT  17.088 9.36 17.28 9.384 ;
    END
  END o[69]
  PIN o[6]
    DIRECTION OUTPUT ;
    USE SIGNAL ;
    PORT
      LAYER M4 ;
        RECT  17.088 2.832 17.28 2.856 ;
    END
  END o[6]
  PIN o[70]
    DIRECTION OUTPUT ;
    USE SIGNAL ;
    PORT
      LAYER M4 ;
        RECT  17.088 9.456 17.28 9.48 ;
    END
  END o[70]
  PIN o[71]
    DIRECTION OUTPUT ;
    USE SIGNAL ;
    PORT
      LAYER M4 ;
        RECT  17.088 9.6 17.28 9.624 ;
    END
  END o[71]
  PIN o[72]
    DIRECTION OUTPUT ;
    USE SIGNAL ;
    PORT
      LAYER M4 ;
        RECT  17.088 9.696 17.28 9.72 ;
    END
  END o[72]
  PIN o[73]
    DIRECTION OUTPUT ;
    USE SIGNAL ;
    PORT
      LAYER M4 ;
        RECT  17.088 9.792 17.28 9.816 ;
    END
  END o[73]
  PIN o[74]
    DIRECTION OUTPUT ;
    USE SIGNAL ;
    PORT
      LAYER M4 ;
        RECT  17.088 9.888 17.28 9.912 ;
    END
  END o[74]
  PIN o[75]
    DIRECTION OUTPUT ;
    USE SIGNAL ;
    PORT
      LAYER M4 ;
        RECT  17.088 9.984 17.28 10.008 ;
    END
  END o[75]
  PIN o[76]
    DIRECTION OUTPUT ;
    USE SIGNAL ;
    PORT
      LAYER M4 ;
        RECT  17.088 10.08 17.28 10.104 ;
    END
  END o[76]
  PIN o[77]
    DIRECTION OUTPUT ;
    USE SIGNAL ;
    PORT
      LAYER M4 ;
        RECT  17.088 10.224 17.28 10.248 ;
    END
  END o[77]
  PIN o[78]
    DIRECTION OUTPUT ;
    USE SIGNAL ;
    PORT
      LAYER M4 ;
        RECT  17.088 10.32 17.28 10.344 ;
    END
  END o[78]
  PIN o[79]
    DIRECTION OUTPUT ;
    USE SIGNAL ;
    PORT
      LAYER M4 ;
        RECT  17.088 10.416 17.28 10.44 ;
    END
  END o[79]
  PIN o[7]
    DIRECTION OUTPUT ;
    USE SIGNAL ;
    PORT
      LAYER M4 ;
        RECT  17.088 2.928 17.28 2.952 ;
    END
  END o[7]
  PIN o[80]
    DIRECTION OUTPUT ;
    USE SIGNAL ;
    PORT
      LAYER M4 ;
        RECT  17.088 10.512 17.28 10.536 ;
    END
  END o[80]
  PIN o[81]
    DIRECTION OUTPUT ;
    USE SIGNAL ;
    PORT
      LAYER M4 ;
        RECT  17.088 10.608 17.28 10.632 ;
    END
  END o[81]
  PIN o[82]
    DIRECTION OUTPUT ;
    USE SIGNAL ;
    PORT
      LAYER M4 ;
        RECT  17.088 10.704 17.28 10.728 ;
    END
  END o[82]
  PIN o[83]
    DIRECTION OUTPUT ;
    USE SIGNAL ;
    PORT
      LAYER M4 ;
        RECT  17.088 10.8 17.28 10.824 ;
    END
  END o[83]
  PIN o[84]
    DIRECTION OUTPUT ;
    USE SIGNAL ;
    PORT
      LAYER M4 ;
        RECT  17.088 10.944 17.28 10.968 ;
    END
  END o[84]
  PIN o[85]
    DIRECTION OUTPUT ;
    USE SIGNAL ;
    PORT
      LAYER M4 ;
        RECT  17.088 11.04 17.28 11.064 ;
    END
  END o[85]
  PIN o[86]
    DIRECTION OUTPUT ;
    USE SIGNAL ;
    PORT
      LAYER M4 ;
        RECT  17.088 11.136 17.28 11.16 ;
    END
  END o[86]
  PIN o[87]
    DIRECTION OUTPUT ;
    USE SIGNAL ;
    PORT
      LAYER M4 ;
        RECT  17.088 11.232 17.28 11.256 ;
    END
  END o[87]
  PIN o[88]
    DIRECTION OUTPUT ;
    USE SIGNAL ;
    PORT
      LAYER M4 ;
        RECT  17.088 11.328 17.28 11.352 ;
    END
  END o[88]
  PIN o[89]
    DIRECTION OUTPUT ;
    USE SIGNAL ;
    PORT
      LAYER M4 ;
        RECT  17.088 11.424 17.28 11.448 ;
    END
  END o[89]
  PIN o[8]
    DIRECTION OUTPUT ;
    USE SIGNAL ;
    PORT
      LAYER M4 ;
        RECT  17.088 3.072 17.28 3.096 ;
    END
  END o[8]
  PIN o[90]
    DIRECTION OUTPUT ;
    USE SIGNAL ;
    PORT
      LAYER M4 ;
        RECT  17.088 11.568 17.28 11.592 ;
    END
  END o[90]
  PIN o[91]
    DIRECTION OUTPUT ;
    USE SIGNAL ;
    PORT
      LAYER M4 ;
        RECT  17.088 11.664 17.28 11.688 ;
    END
  END o[91]
  PIN o[92]
    DIRECTION OUTPUT ;
    USE SIGNAL ;
    PORT
      LAYER M4 ;
        RECT  17.088 11.76 17.28 11.784 ;
    END
  END o[92]
  PIN o[93]
    DIRECTION OUTPUT ;
    USE SIGNAL ;
    PORT
      LAYER M4 ;
        RECT  17.088 11.856 17.28 11.88 ;
    END
  END o[93]
  PIN o[94]
    DIRECTION OUTPUT ;
    USE SIGNAL ;
    PORT
      LAYER M4 ;
        RECT  17.088 11.952 17.28 11.976 ;
    END
  END o[94]
  PIN o[95]
    DIRECTION OUTPUT ;
    USE SIGNAL ;
    PORT
      LAYER M4 ;
        RECT  17.088 12.048 17.28 12.072 ;
    END
  END o[95]
  PIN o[96]
    DIRECTION OUTPUT ;
    USE SIGNAL ;
    PORT
      LAYER M4 ;
        RECT  17.088 12.192 17.28 12.216 ;
    END
  END o[96]
  PIN o[97]
    DIRECTION OUTPUT ;
    USE SIGNAL ;
    PORT
      LAYER M4 ;
        RECT  17.088 12.288 17.28 12.312 ;
    END
  END o[97]
  PIN o[98]
    DIRECTION OUTPUT ;
    USE SIGNAL ;
    PORT
      LAYER M4 ;
        RECT  17.088 12.384 17.28 12.408 ;
    END
  END o[98]
  PIN o[99]
    DIRECTION OUTPUT ;
    USE SIGNAL ;
    PORT
      LAYER M4 ;
        RECT  17.088 12.48 17.28 12.504 ;
    END
  END o[99]
  PIN o[9]
    DIRECTION OUTPUT ;
    USE SIGNAL ;
    PORT
      LAYER M4 ;
        RECT  17.088 3.168 17.28 3.192 ;
    END
  END o[9]
  PIN rs
    DIRECTION INPUT ;
    USE SIGNAL ;
    PORT
      LAYER M5 ;
        RECT  11.856 62.448 11.88 62.64 ;
    END
    PORT
      LAYER M5 ;
        RECT  11.856 59.893 11.88 62.48 ;
    END
  END rs
  PIN VDD
    DIRECTION INOUT ;
    USE POWER ;
    PORT
      LAYER M5 ;
        RECT  13.392 2.151 13.512 60.489 ;
        RECT  10.692 2.151 10.812 60.489 ;
        RECT  7.992 2.151 8.112 60.489 ;
        RECT  5.292 2.151 5.412 60.489 ;
        RECT  2.592 2.151 2.712 60.489 ;
    END
  END VDD
  PIN VSS
    DIRECTION INOUT ;
    USE GROUND ;
    PORT
      LAYER M5 ;
        RECT  13.2 2.137 13.32 60.503 ;
        RECT  10.5 2.137 10.62 60.503 ;
        RECT  7.8 2.137 7.92 60.503 ;
        RECT  5.1 2.137 5.22 60.503 ;
        RECT  2.4 2.137 2.52 60.503 ;
    END
  END VSS
  # OT_OBS_CLOSED layer=M5 d_um=1.536 added=56
  OBS
    LAYER RVTN ;
     RECT  2.16 2.16 15.12 2.295 ;
     RECT  2.16 2.565 15.12 2.835 ;
     RECT  2.16 3.105 15.12 3.375 ;
     RECT  2.16 3.645 15.12 3.915 ;
     RECT  2.16 4.185 15.12 4.455 ;
     RECT  2.16 4.725 15.12 4.995 ;
     RECT  2.16 5.265 15.12 5.535 ;
     RECT  2.16 5.805 15.12 6.075 ;
     RECT  2.16 6.345 15.12 6.615 ;
     RECT  2.16 6.885 15.12 7.155 ;
     RECT  2.16 7.425 15.12 7.695 ;
     RECT  2.16 7.965 15.12 8.235 ;
     RECT  2.16 8.505 15.12 8.775 ;
     RECT  2.16 9.045 15.12 9.315 ;
     RECT  2.16 9.585 15.12 9.855 ;
     RECT  2.16 10.125 15.12 10.395 ;
     RECT  2.16 10.665 15.12 10.935 ;
     RECT  2.16 11.205 15.12 11.475 ;
     RECT  2.16 11.745 15.12 12.015 ;
     RECT  2.16 12.285 15.12 12.555 ;
     RECT  2.16 12.825 15.12 13.095 ;
     RECT  2.16 13.365 15.12 13.635 ;
     RECT  2.16 13.905 15.12 14.175 ;
     RECT  2.16 14.445 15.12 14.715 ;
     RECT  2.16 14.985 15.12 15.255 ;
     RECT  2.16 15.525 15.12 15.795 ;
     RECT  2.16 16.065 15.12 16.335 ;
     RECT  2.16 16.605 15.12 16.875 ;
     RECT  2.16 17.145 15.12 17.415 ;
     RECT  2.16 17.685 15.12 17.955 ;
     RECT  2.16 18.225 15.12 18.495 ;
     RECT  2.16 18.765 15.12 19.035 ;
     RECT  2.16 19.305 15.12 19.575 ;
     RECT  2.16 19.845 15.12 20.115 ;
     RECT  2.16 20.385 15.12 20.655 ;
     RECT  2.16 20.925 15.12 21.195 ;
     RECT  2.16 21.465 15.12 21.735 ;
     RECT  2.16 22.005 15.12 22.275 ;
     RECT  2.16 22.545 15.12 22.815 ;
     RECT  2.16 23.085 15.12 23.355 ;
     RECT  2.16 23.625 15.12 23.895 ;
     RECT  2.16 24.165 15.12 24.435 ;
     RECT  2.16 24.705 15.12 24.975 ;
     RECT  2.16 25.245 15.12 25.515 ;
     RECT  2.16 25.785 15.12 26.055 ;
     RECT  2.16 26.325 15.12 26.595 ;
     RECT  2.16 26.865 15.12 27.135 ;
     RECT  2.16 27.405 15.12 27.675 ;
     RECT  2.16 27.945 15.12 28.215 ;
     RECT  2.16 28.485 15.12 28.755 ;
     RECT  2.16 29.025 15.12 29.295 ;
     RECT  2.16 29.565 15.12 29.835 ;
     RECT  2.16 30.105 15.12 30.375 ;
     RECT  2.16 30.645 15.12 30.915 ;
     RECT  2.16 31.185 15.12 31.455 ;
     RECT  2.16 31.725 15.12 31.995 ;
     RECT  2.16 32.265 15.12 32.535 ;
     RECT  2.16 32.805 15.12 33.075 ;
     RECT  2.16 33.345 15.12 33.615 ;
     RECT  2.16 33.885 15.12 34.155 ;
     RECT  2.16 34.425 15.12 34.695 ;
     RECT  2.16 34.965 15.12 35.235 ;
     RECT  2.16 35.505 15.12 35.775 ;
     RECT  2.16 36.045 15.12 36.315 ;
     RECT  2.16 36.585 15.12 36.855 ;
     RECT  2.16 37.125 15.12 37.395 ;
     RECT  2.16 37.665 15.12 37.935 ;
     RECT  2.16 38.205 15.12 38.475 ;
     RECT  2.16 38.745 15.12 39.015 ;
     RECT  2.16 39.285 15.12 39.555 ;
     RECT  2.16 39.825 15.12 40.095 ;
     RECT  2.16 40.365 15.12 40.635 ;
     RECT  2.16 40.905 15.12 41.175 ;
     RECT  2.16 41.445 15.12 41.715 ;
     RECT  2.16 41.985 15.12 42.255 ;
     RECT  2.16 42.525 15.12 42.795 ;
     RECT  2.16 43.065 15.12 43.335 ;
     RECT  2.16 43.605 15.12 43.875 ;
     RECT  2.16 44.145 15.12 44.415 ;
     RECT  2.16 44.685 15.12 44.955 ;
     RECT  2.16 45.225 15.12 45.495 ;
     RECT  2.16 45.765 15.12 46.035 ;
     RECT  2.16 46.305 15.12 46.575 ;
     RECT  2.16 46.845 15.12 47.115 ;
     RECT  2.16 47.385 15.12 47.655 ;
     RECT  2.16 47.925 15.12 48.195 ;
     RECT  2.16 48.465 15.12 48.735 ;
     RECT  2.16 49.005 15.12 49.275 ;
     RECT  2.16 49.545 15.12 49.815 ;
     RECT  2.16 50.085 15.12 50.355 ;
     RECT  2.16 50.625 15.12 50.895 ;
     RECT  2.16 51.165 15.12 51.435 ;
     RECT  2.16 51.705 15.12 51.975 ;
     RECT  2.16 52.245 15.12 52.515 ;
     RECT  2.16 52.785 15.12 53.055 ;
     RECT  2.16 53.325 15.12 53.595 ;
     RECT  2.16 53.865 15.12 54.135 ;
     RECT  2.16 54.405 15.12 54.675 ;
     RECT  2.16 54.945 15.12 55.215 ;
     RECT  2.16 55.485 15.12 55.755 ;
     RECT  2.16 56.025 15.12 56.295 ;
     RECT  2.16 56.565 15.12 56.835 ;
     RECT  2.16 57.105 15.12 57.375 ;
     RECT  2.16 57.645 15.12 57.915 ;
     RECT  2.16 58.185 15.12 58.455 ;
     RECT  2.16 58.725 15.12 58.995 ;
     RECT  2.16 59.265 15.12 59.535 ;
     RECT  2.16 59.805 15.12 60.075 ;
     RECT  2.16 60.345 15.12 60.48 ;
    LAYER RVTP ;
     RECT  2.16 2.295 15.12 2.565 ;
     RECT  2.16 2.835 15.12 3.105 ;
     RECT  2.16 3.375 15.12 3.645 ;
     RECT  2.16 3.915 15.12 4.185 ;
     RECT  2.16 4.455 15.12 4.725 ;
     RECT  2.16 4.995 15.12 5.265 ;
     RECT  2.16 5.535 15.12 5.805 ;
     RECT  2.16 6.075 15.12 6.345 ;
     RECT  2.16 6.615 15.12 6.885 ;
     RECT  2.16 7.155 15.12 7.425 ;
     RECT  2.16 7.695 15.12 7.965 ;
     RECT  2.16 8.235 15.12 8.505 ;
     RECT  2.16 8.775 15.12 9.045 ;
     RECT  2.16 9.315 15.12 9.585 ;
     RECT  2.16 9.855 15.12 10.125 ;
     RECT  2.16 10.395 15.12 10.665 ;
     RECT  2.16 10.935 15.12 11.205 ;
     RECT  2.16 11.475 15.12 11.745 ;
     RECT  2.16 12.015 15.12 12.285 ;
     RECT  2.16 12.555 15.12 12.825 ;
     RECT  2.16 13.095 15.12 13.365 ;
     RECT  2.16 13.635 15.12 13.905 ;
     RECT  2.16 14.175 15.12 14.445 ;
     RECT  2.16 14.715 15.12 14.985 ;
     RECT  2.16 15.255 15.12 15.525 ;
     RECT  2.16 15.795 15.12 16.065 ;
     RECT  2.16 16.335 15.12 16.605 ;
     RECT  2.16 16.875 15.12 17.145 ;
     RECT  2.16 17.415 15.12 17.685 ;
     RECT  2.16 17.955 15.12 18.225 ;
     RECT  2.16 18.495 15.12 18.765 ;
     RECT  2.16 19.035 15.12 19.305 ;
     RECT  2.16 19.575 15.12 19.845 ;
     RECT  2.16 20.115 15.12 20.385 ;
     RECT  2.16 20.655 15.12 20.925 ;
     RECT  2.16 21.195 15.12 21.465 ;
     RECT  2.16 21.735 15.12 22.005 ;
     RECT  2.16 22.275 15.12 22.545 ;
     RECT  2.16 22.815 15.12 23.085 ;
     RECT  2.16 23.355 15.12 23.625 ;
     RECT  2.16 23.895 15.12 24.165 ;
     RECT  2.16 24.435 15.12 24.705 ;
     RECT  2.16 24.975 15.12 25.245 ;
     RECT  2.16 25.515 15.12 25.785 ;
     RECT  2.16 26.055 15.12 26.325 ;
     RECT  2.16 26.595 15.12 26.865 ;
     RECT  2.16 27.135 15.12 27.405 ;
     RECT  2.16 27.675 15.12 27.945 ;
     RECT  2.16 28.215 15.12 28.485 ;
     RECT  2.16 28.755 15.12 29.025 ;
     RECT  2.16 29.295 15.12 29.565 ;
     RECT  2.16 29.835 15.12 30.105 ;
     RECT  2.16 30.375 15.12 30.645 ;
     RECT  2.16 30.915 15.12 31.185 ;
     RECT  2.16 31.455 15.12 31.725 ;
     RECT  2.16 31.995 15.12 32.265 ;
     RECT  2.16 32.535 15.12 32.805 ;
     RECT  2.16 33.075 15.12 33.345 ;
     RECT  2.16 33.615 15.12 33.885 ;
     RECT  2.16 34.155 15.12 34.425 ;
     RECT  2.16 34.695 15.12 34.965 ;
     RECT  2.16 35.235 15.12 35.505 ;
     RECT  2.16 35.775 15.12 36.045 ;
     RECT  2.16 36.315 15.12 36.585 ;
     RECT  2.16 36.855 15.12 37.125 ;
     RECT  2.16 37.395 15.12 37.665 ;
     RECT  2.16 37.935 15.12 38.205 ;
     RECT  2.16 38.475 15.12 38.745 ;
     RECT  2.16 39.015 15.12 39.285 ;
     RECT  2.16 39.555 15.12 39.825 ;
     RECT  2.16 40.095 15.12 40.365 ;
     RECT  2.16 40.635 15.12 40.905 ;
     RECT  2.16 41.175 15.12 41.445 ;
     RECT  2.16 41.715 15.12 41.985 ;
     RECT  2.16 42.255 15.12 42.525 ;
     RECT  2.16 42.795 15.12 43.065 ;
     RECT  2.16 43.335 15.12 43.605 ;
     RECT  2.16 43.875 15.12 44.145 ;
     RECT  2.16 44.415 15.12 44.685 ;
     RECT  2.16 44.955 15.12 45.225 ;
     RECT  2.16 45.495 15.12 45.765 ;
     RECT  2.16 46.035 15.12 46.305 ;
     RECT  2.16 46.575 15.12 46.845 ;
     RECT  2.16 47.115 15.12 47.385 ;
     RECT  2.16 47.655 15.12 47.925 ;
     RECT  2.16 48.195 15.12 48.465 ;
     RECT  2.16 48.735 15.12 49.005 ;
     RECT  2.16 49.275 15.12 49.545 ;
     RECT  2.16 49.815 15.12 50.085 ;
     RECT  2.16 50.355 15.12 50.625 ;
     RECT  2.16 50.895 15.12 51.165 ;
     RECT  2.16 51.435 15.12 51.705 ;
     RECT  2.16 51.975 15.12 52.245 ;
     RECT  2.16 52.515 15.12 52.785 ;
     RECT  2.16 53.055 15.12 53.325 ;
     RECT  2.16 53.595 15.12 53.865 ;
     RECT  2.16 54.135 15.12 54.405 ;
     RECT  2.16 54.675 15.12 54.945 ;
     RECT  2.16 55.215 15.12 55.485 ;
     RECT  2.16 55.755 15.12 56.025 ;
     RECT  2.16 56.295 15.12 56.565 ;
     RECT  2.16 56.835 15.12 57.105 ;
     RECT  2.16 57.375 15.12 57.645 ;
     RECT  2.16 57.915 15.12 58.185 ;
     RECT  2.16 58.455 15.12 58.725 ;
     RECT  2.16 58.995 15.12 59.265 ;
     RECT  2.16 59.535 15.12 59.805 ;
     RECT  2.16 60.075 15.12 60.345 ;
    LAYER M1 ;
     RECT  2.16 2.151 15.12 60.489 ;
    LAYER M2 ;
     RECT  0.211 23.481 0.247 23.499 ;
     RECT  0.211 9.126 0.311 9.144 ;
     RECT  0.211 12.762 0.311 12.78 ;
     RECT  0.211 13.68 0.311 13.698 ;
     RECT  0.211 15.651 0.311 15.669 ;
     RECT  0.247 23.4 0.311 23.499 ;
     RECT  0.211 32.436 0.311 32.454 ;
     RECT  0.211 34.974 0.311 34.992 ;
     RECT  0.211 35.748 0.311 36.459 ;
     RECT  0.211 48.366 0.347 48.384 ;
     RECT  0.211 55.728 0.347 55.746 ;
     RECT  0.211 56.736 0.347 56.754 ;
     RECT  0.283 54.846 0.383 54.864 ;
     RECT  0.283 44.964 0.419 44.982 ;
     RECT  0.319 51.336 0.419 51.354 ;
     RECT  0.355 12.096 0.491 12.114 ;
     RECT  0.283 41.922 0.491 41.94 ;
     RECT  0.211 17.082 0.535 17.1 ;
     RECT  0.211 37.746 0.535 37.764 ;
     RECT  0.211 53.406 0.535 53.424 ;
     RECT  1.183 20.394 1.219 20.412 ;
     RECT  1.183 56.61 1.283 56.628 ;
     RECT  1.219 20.322 1.319 20.412 ;
     RECT  1.319 20.394 1.355 20.412 ;
     RECT  0.211 10.674 2.16 10.692 ;
     RECT  0.535 14.22 2.16 14.238 ;
     RECT  0.535 15.84 2.16 15.858 ;
     RECT  0.535 17.082 2.16 17.676 ;
     RECT  0.211 21.636 2.16 21.654 ;
     RECT  0.311 23.4 2.16 23.418 ;
     RECT  0.211 24.984 2.16 25.002 ;
     RECT  0.211 26.496 2.16 26.514 ;
     RECT  0.211 27.882 2.16 27.9 ;
     RECT  0.319 30.726 2.16 30.744 ;
     RECT  0.319 36.558 2.16 36.576 ;
     RECT  0.535 37.746 2.16 38.196 ;
     RECT  0.535 41.148 2.16 41.166 ;
     RECT  0.535 47.862 2.16 47.88 ;
     RECT  0.535 53.406 2.16 54.126 ;
     RECT  0.535 57.456 2.16 57.474 ;
     RECT  0.211 61.011 2.16 61.029 ;
     RECT  2.16 2.151 5.683 61.029 ;
     RECT  5.683 2.106 6.835 61.029 ;
     RECT  6.835 1.926 8.267 61.029 ;
     RECT  8.267 1.998 8.591 61.029 ;
     RECT  8.591 2.034 9.563 61.029 ;
     RECT  9.563 2.034 9.779 60.606 ;
     RECT  9.779 2.07 10.427 60.606 ;
     RECT  10.427 2.07 11.291 60.489 ;
     RECT  11.291 2.106 13.487 60.489 ;
     RECT  13.487 2.151 15.12 60.489 ;
     RECT  15.12 2.196 15.431 60.408 ;
     RECT  15.431 12.186 15.467 47.484 ;
     RECT  15.431 48.276 15.467 60.408 ;
     RECT  15.431 2.196 16.007 11.394 ;
     RECT  15.467 12.186 16.007 37.62 ;
     RECT  15.467 38.646 16.007 47.484 ;
     RECT  15.467 48.276 16.007 53.658 ;
     RECT  15.467 54.576 16.007 59.328 ;
     RECT  16.007 12.186 16.043 17.334 ;
     RECT  16.007 38.646 16.043 47.178 ;
     RECT  15.467 60.084 16.043 60.408 ;
     RECT  16.007 35.442 16.079 37.386 ;
     RECT  16.007 3.114 16.511 11.394 ;
     RECT  16.043 12.186 16.511 16.092 ;
     RECT  16.043 17.154 16.511 17.334 ;
     RECT  16.007 19.116 16.511 21.654 ;
     RECT  16.007 22.59 16.511 34.452 ;
     RECT  16.079 35.442 16.511 37.314 ;
     RECT  16.043 38.646 16.511 46.332 ;
     RECT  16.007 50.526 16.511 52.074 ;
     RECT  16.007 54.684 16.511 58.824 ;
     RECT  16.007 2.196 16.547 2.214 ;
     RECT  16.511 3.114 16.547 3.744 ;
     RECT  16.511 4.77 16.547 9.144 ;
     RECT  16.511 10.674 16.547 11.394 ;
     RECT  16.511 12.186 16.547 12.204 ;
     RECT  16.511 12.996 16.547 16.092 ;
     RECT  16.511 17.154 16.547 17.172 ;
     RECT  16.007 18.162 16.547 18.216 ;
     RECT  16.511 19.116 16.547 21.564 ;
     RECT  16.511 22.59 16.547 30.672 ;
     RECT  16.511 31.806 16.547 34.452 ;
     RECT  16.511 35.478 16.547 35.496 ;
     RECT  16.511 36.864 16.547 37.314 ;
     RECT  16.511 38.646 16.547 39.114 ;
     RECT  16.511 39.906 16.547 42.444 ;
     RECT  16.511 43.686 16.547 46.332 ;
     RECT  16.043 47.088 16.547 47.178 ;
     RECT  16.007 48.276 16.547 49.5 ;
     RECT  16.511 50.598 16.547 52.074 ;
     RECT  16.007 52.992 16.547 53.658 ;
     RECT  16.511 54.684 16.547 54.936 ;
     RECT  16.511 55.692 16.547 56.016 ;
     RECT  16.511 56.844 16.547 58.824 ;
     RECT  16.043 60.084 16.547 60.102 ;
     RECT  16.547 7.974 16.583 8.604 ;
     RECT  16.547 14.454 16.583 15.552 ;
     RECT  16.547 19.278 16.583 19.296 ;
     RECT  16.547 20.736 16.583 20.754 ;
     RECT  16.547 22.626 16.583 23.31 ;
     RECT  16.547 34.434 16.583 34.452 ;
     RECT  16.547 38.718 16.583 38.736 ;
     RECT  16.547 40.446 16.583 41.166 ;
     RECT  16.547 42.426 16.583 42.444 ;
     RECT  16.547 43.848 16.583 43.866 ;
     RECT  16.547 46.314 16.583 46.332 ;
     RECT  16.547 57.186 16.583 57.744 ;
     RECT  16.547 58.806 16.583 58.824 ;
     RECT  16.547 10.674 16.619 10.962 ;
     RECT  16.547 13.032 16.619 13.05 ;
     RECT  16.547 18.198 16.619 18.216 ;
     RECT  16.583 22.626 16.619 22.644 ;
     RECT  16.547 26.721 16.619 26.784 ;
     RECT  16.547 52.056 16.619 52.074 ;
     RECT  16.547 53.64 16.619 53.658 ;
     RECT  16.619 10.674 16.655 10.809 ;
     RECT  16.583 15.192 16.655 15.21 ;
     RECT  16.655 10.674 16.691 10.692 ;
    LAYER M3 ;
     RECT  8.244 1.921 8.262 1.993 ;
     RECT  6.84 1.921 6.858 2.029 ;
     RECT  7.596 1.993 8.586 2.029 ;
     RECT  5.688 2.101 5.706 2.143 ;
     RECT  11.268 2.065 11.286 2.143 ;
     RECT  13.464 2.101 13.482 2.143 ;
     RECT  6.84 2.029 8.586 2.203 ;
     RECT  9.756 2.029 9.774 2.219 ;
     RECT  0.216 2.059 0.234 2.237 ;
     RECT  2.415 2.143 2.505 2.263 ;
     RECT  3.6 2.059 3.618 2.263 ;
     RECT  5.115 2.143 5.706 2.299 ;
     RECT  6.66 2.203 8.586 2.299 ;
     RECT  13.215 2.143 13.482 2.299 ;
     RECT  5.115 2.299 8.586 2.335 ;
     RECT  5.115 2.335 9.342 2.371 ;
     RECT  13.032 2.299 13.482 2.413 ;
     RECT  14.832 2.263 14.85 2.443 ;
     RECT  14.832 2.443 15.426 2.461 ;
     RECT  0.252 2.347 0.27 2.477 ;
     RECT  4.968 2.371 9.342 2.533 ;
     RECT  12.204 2.461 12.222 2.561 ;
     RECT  4.896 2.533 9.342 2.569 ;
     RECT  2.415 2.263 3.618 2.635 ;
     RECT  14.832 2.461 15.462 2.635 ;
     RECT  16.524 2.191 16.542 2.635 ;
     RECT  13.032 2.413 13.497 2.641 ;
     RECT  13.032 2.641 13.914 2.725 ;
     RECT  14.832 2.635 16.542 2.725 ;
     RECT  0.288 2.587 0.306 2.731 ;
     RECT  13.032 2.725 16.542 2.759 ;
     RECT  13.032 2.759 15.498 2.831 ;
     RECT  2.304 2.635 3.618 2.839 ;
     RECT  4.392 2.569 9.342 2.839 ;
     RECT  13.032 2.831 14.598 2.839 ;
     RECT  0.288 2.731 0.414 2.861 ;
     RECT  2.304 2.839 9.342 2.912 ;
     RECT  3.96 2.912 9.342 3.109 ;
     RECT  10.515 2.143 11.286 3.115 ;
     RECT  3.96 3.109 9.378 3.181 ;
     RECT  10.515 3.115 11.43 3.209 ;
     RECT  12.528 2.839 14.598 3.299 ;
     RECT  3.96 3.181 9.594 3.343 ;
     RECT  3.96 3.343 9.666 3.499 ;
     RECT  10.515 3.209 10.926 3.499 ;
     RECT  16.524 2.759 16.542 3.541 ;
     RECT  3.96 3.499 10.926 3.569 ;
     RECT  11.952 3.307 12.042 3.569 ;
     RECT  3.96 3.569 4.194 3.605 ;
     RECT  5.115 3.569 10.926 3.725 ;
     RECT  16.488 3.541 16.542 3.749 ;
     RECT  15.408 2.831 15.498 3.787 ;
     RECT  16.488 3.749 16.506 3.787 ;
     RECT  13.212 3.299 14.598 3.847 ;
     RECT  15.408 3.787 16.506 3.847 ;
     RECT  5.115 3.725 9.738 4.019 ;
     RECT  11.952 3.569 11.97 4.117 ;
     RECT  11.808 4.117 11.97 4.157 ;
     RECT  2.304 2.912 3.222 4.315 ;
     RECT  10.515 3.725 10.926 4.387 ;
     RECT  10.515 4.387 11.07 4.445 ;
     RECT  2.268 4.315 3.222 4.487 ;
     RECT  0.252 4.075 0.27 4.493 ;
     RECT  11.916 4.157 11.97 4.507 ;
     RECT  13.212 3.847 16.506 4.507 ;
     RECT  4.032 3.605 4.194 4.657 ;
     RECT  11.916 4.507 16.506 4.699 ;
     RECT  11.916 4.699 16.542 4.757 ;
     RECT  5.115 4.019 9.702 4.891 ;
     RECT  10.515 4.445 10.797 4.891 ;
     RECT  11.916 4.757 13.626 4.927 ;
     RECT  14.544 4.757 16.542 5.099 ;
     RECT  2.304 4.487 3.222 5.131 ;
     RECT  3.96 4.657 4.194 5.131 ;
     RECT  2.304 5.131 4.194 5.179 ;
     RECT  5.115 4.891 10.797 5.179 ;
     RECT  14.544 5.099 14.562 5.225 ;
     RECT  11.808 4.927 13.626 5.459 ;
     RECT  1.152 5.323 1.17 5.501 ;
     RECT  2.304 5.179 10.797 5.515 ;
     RECT  11.808 5.459 13.554 5.515 ;
     RECT  2.304 5.515 13.554 5.531 ;
     RECT  14.328 5.503 14.346 5.603 ;
     RECT  2.304 5.531 13.497 5.947 ;
     RECT  15.408 5.099 16.542 5.947 ;
     RECT  2.268 5.947 13.497 6.035 ;
     RECT  2.304 6.035 13.497 6.269 ;
     RECT  14.616 5.947 16.542 6.269 ;
     RECT  15.408 6.269 16.542 6.605 ;
     RECT  15.408 6.605 15.462 6.611 ;
     RECT  13.032 6.269 13.497 6.619 ;
     RECT  2.304 6.269 12.186 6.809 ;
     RECT  13.032 6.619 14.49 6.845 ;
     RECT  2.304 6.809 12.006 6.859 ;
     RECT  2.196 6.859 12.006 6.917 ;
     RECT  2.304 6.917 12.006 6.941 ;
     RECT  13.068 6.845 14.49 7.231 ;
     RECT  13.068 7.231 14.526 7.321 ;
     RECT  15.408 6.611 15.426 7.321 ;
     RECT  13.068 7.321 15.426 7.483 ;
     RECT  16.488 6.605 16.542 7.483 ;
     RECT  1.26 7.435 1.278 7.531 ;
     RECT  1.152 7.531 1.278 7.661 ;
     RECT  2.304 6.941 10.854 7.757 ;
     RECT  11.988 6.941 12.006 7.771 ;
     RECT  0.252 5.515 0.27 7.853 ;
     RECT  2.304 7.757 10.797 7.889 ;
     RECT  13.068 7.483 16.542 7.889 ;
     RECT  11.988 7.771 12.294 7.961 ;
     RECT  13.215 7.889 16.542 7.969 ;
     RECT  13.215 7.969 16.578 8.159 ;
     RECT  11.88 8.041 11.898 8.195 ;
     RECT  3.96 7.889 10.797 8.231 ;
     RECT  15.984 8.159 16.578 8.381 ;
     RECT  4.032 8.231 10.797 8.429 ;
     RECT  6.12 8.429 10.797 8.539 ;
     RECT  6.12 8.539 11.034 8.581 ;
     RECT  13.215 8.159 14.85 8.671 ;
     RECT  1.26 8.635 1.278 8.779 ;
     RECT  1.152 8.779 1.278 8.813 ;
     RECT  13.14 8.671 14.85 8.851 ;
     RECT  16.488 8.381 16.578 8.861 ;
     RECT  6.12 8.581 11.394 8.879 ;
     RECT  4.032 8.429 5.397 8.977 ;
     RECT  1.152 8.813 1.17 9.005 ;
     RECT  13.068 8.851 14.85 9.005 ;
     RECT  0.216 8.971 0.234 9.019 ;
     RECT  3.96 8.977 5.397 9.053 ;
     RECT  0.216 9.019 0.306 9.149 ;
     RECT  16.488 8.861 16.542 9.149 ;
     RECT  0.288 9.149 0.306 9.163 ;
     RECT  14.832 9.005 14.85 9.163 ;
     RECT  13.068 9.005 13.986 9.247 ;
     RECT  0.288 9.163 0.45 9.293 ;
     RECT  5.004 9.053 5.397 9.307 ;
     RECT  6.12 8.879 10.854 9.307 ;
     RECT  14.832 9.163 15.426 9.319 ;
     RECT  16.488 9.149 16.506 9.319 ;
     RECT  12.708 9.247 13.986 9.355 ;
     RECT  2.304 7.889 3.222 9.391 ;
     RECT  3.96 9.053 4.194 9.391 ;
     RECT  12.564 9.355 13.986 9.391 ;
     RECT  0.288 9.293 0.378 9.437 ;
     RECT  2.304 9.391 4.194 9.509 ;
     RECT  12.168 9.391 13.986 9.509 ;
     RECT  5.004 9.307 10.854 9.581 ;
     RECT  14.832 9.319 16.506 9.629 ;
     RECT  12.78 9.509 13.806 9.653 ;
     RECT  1.368 9.787 1.386 9.835 ;
     RECT  12.78 9.653 13.497 9.869 ;
     RECT  1.152 9.835 1.386 9.917 ;
     RECT  5.115 9.581 10.854 10.027 ;
     RECT  0.252 9.979 0.27 10.109 ;
     RECT  1.152 9.917 1.17 10.109 ;
     RECT  11.952 9.931 11.97 10.109 ;
     RECT  14.832 9.629 15.462 10.12 ;
     RECT  5.115 10.027 10.89 10.157 ;
     RECT  12.924 9.869 13.497 10.435 ;
     RECT  16.488 9.629 16.506 10.507 ;
     RECT  5.115 10.157 10.797 10.552 ;
     RECT  12.924 10.435 13.806 10.561 ;
     RECT  14.544 10.12 15.462 10.561 ;
     RECT  2.304 9.509 4.158 10.597 ;
     RECT  5.076 10.552 10.797 10.597 ;
     RECT  16.488 10.507 16.578 10.669 ;
     RECT  0.216 10.669 0.234 10.781 ;
     RECT  16.488 10.669 16.686 10.829 ;
     RECT  2.304 10.597 10.797 10.859 ;
     RECT  11.736 10.597 11.754 10.939 ;
     RECT  16.488 10.829 16.614 10.967 ;
     RECT  12.924 10.561 15.462 11.039 ;
     RECT  12.924 11.039 14.598 11.129 ;
     RECT  16.488 10.967 16.542 11.129 ;
     RECT  11.736 10.939 12.078 11.173 ;
     RECT  15.408 11.039 15.462 11.173 ;
     RECT  11.592 11.173 12.078 11.209 ;
     RECT  12.924 11.129 14.562 11.209 ;
     RECT  11.592 11.209 14.562 11.273 ;
     RECT  11.988 11.273 14.562 11.435 ;
     RECT  3.996 10.859 10.797 11.453 ;
     RECT  11.988 11.435 13.842 11.471 ;
     RECT  15.408 11.173 15.498 11.597 ;
     RECT  4.032 11.453 10.797 11.641 ;
     RECT  4.032 11.641 10.89 11.669 ;
     RECT  4.068 11.669 10.89 11.849 ;
     RECT  4.068 11.849 10.854 11.939 ;
     RECT  0.252 10.891 0.342 12.043 ;
     RECT  14.58 11.947 14.598 12.091 ;
     RECT  15.408 11.597 15.426 12.091 ;
     RECT  0.252 12.043 0.486 12.119 ;
     RECT  16.524 11.129 16.542 12.283 ;
     RECT  14.58 12.091 15.426 12.317 ;
     RECT  11.988 11.471 12.186 12.325 ;
     RECT  4.068 11.939 4.194 12.427 ;
     RECT  11.844 12.325 12.186 12.559 ;
     RECT  2.304 10.859 3.258 12.631 ;
     RECT  3.996 12.427 4.194 12.631 ;
     RECT  0.252 12.119 0.378 12.748 ;
     RECT  2.304 12.631 4.194 12.785 ;
     RECT  3.996 12.785 4.194 12.793 ;
     RECT  5.115 11.939 10.797 12.793 ;
     RECT  3.996 12.793 10.797 12.859 ;
     RECT  11.844 12.559 12.258 12.859 ;
     RECT  13.215 11.471 13.842 12.901 ;
     RECT  14.58 12.317 14.85 12.901 ;
     RECT  16.488 12.283 16.542 12.907 ;
     RECT  0.216 12.748 0.378 12.941 ;
     RECT  13.215 12.901 14.85 13.019 ;
     RECT  16.488 12.907 16.614 13.055 ;
     RECT  14.616 13.019 14.85 13.09 ;
     RECT  13.215 13.019 13.518 13.091 ;
     RECT  13.215 13.091 13.497 13.171 ;
     RECT  14.616 13.09 14.886 13.195 ;
     RECT  3.996 12.859 12.258 13.325 ;
     RECT  16.488 13.055 16.542 13.325 ;
     RECT  11.916 13.325 12.258 13.387 ;
     RECT  13.104 13.171 13.497 13.387 ;
     RECT  2.304 12.785 3.258 13.531 ;
     RECT  3.996 13.325 10.818 13.531 ;
     RECT  14.616 13.195 15.426 13.639 ;
     RECT  0.216 12.941 0.306 13.703 ;
     RECT  11.916 13.387 13.497 13.829 ;
     RECT  14.616 13.639 15.462 13.853 ;
     RECT  0.252 13.703 0.306 13.915 ;
     RECT  2.304 13.531 10.818 13.937 ;
     RECT  2.304 13.937 9.594 14.009 ;
     RECT  12.744 13.829 13.497 14.071 ;
     RECT  14.616 13.853 14.886 14.071 ;
     RECT  10.515 13.937 10.818 14.107 ;
     RECT  2.34 14.009 9.594 14.171 ;
     RECT  12.744 14.071 14.886 14.171 ;
     RECT  0.252 13.915 0.342 14.215 ;
     RECT  16.524 13.325 16.542 14.242 ;
     RECT  12.744 14.171 13.77 14.243 ;
     RECT  0.252 14.215 0.558 14.381 ;
     RECT  12.744 14.243 13.626 14.477 ;
     RECT  16.524 14.242 16.578 14.539 ;
     RECT  14.508 14.171 14.85 14.639 ;
     RECT  10.515 14.107 11.43 14.72 ;
     RECT  12.744 14.477 13.497 14.765 ;
     RECT  2.34 14.171 4.374 14.779 ;
     RECT  12.816 14.765 13.497 14.813 ;
     RECT  5.112 14.171 9.594 14.875 ;
     RECT  10.515 14.72 11.394 14.875 ;
     RECT  16.488 14.539 16.578 15.067 ;
     RECT  16.488 15.067 16.65 15.215 ;
     RECT  16.488 15.215 16.578 15.259 ;
     RECT  2.304 14.779 4.374 15.295 ;
     RECT  5.112 14.875 11.394 15.295 ;
     RECT  13.104 14.813 13.497 15.331 ;
     RECT  2.304 15.295 11.394 15.359 ;
     RECT  0.252 14.381 0.27 15.403 ;
     RECT  0.216 15.403 0.27 15.451 ;
     RECT  13.104 15.331 14.094 15.493 ;
     RECT  14.832 14.639 14.85 15.493 ;
     RECT  0.216 15.451 0.306 15.547 ;
     RECT  15.984 15.259 16.578 15.557 ;
     RECT  13.104 15.493 14.85 15.593 ;
     RECT  14.472 15.593 14.85 15.595 ;
     RECT  0.216 15.547 0.342 15.692 ;
     RECT  0.252 15.692 0.342 15.835 ;
     RECT  12.132 15.601 12.15 15.835 ;
     RECT  13.104 15.593 13.497 15.835 ;
     RECT  14.472 15.595 14.886 15.883 ;
     RECT  15.984 15.557 16.542 15.883 ;
     RECT  0.252 15.835 0.558 16.061 ;
     RECT  12.132 15.835 13.497 16.075 ;
     RECT  14.472 15.883 16.542 16.097 ;
     RECT  2.304 15.359 10.926 16.169 ;
     RECT  0.252 16.061 0.27 16.253 ;
     RECT  14.472 16.097 16.038 16.259 ;
     RECT  11.952 16.075 13.497 16.501 ;
     RECT  11.952 16.501 13.986 16.673 ;
     RECT  2.304 16.169 10.854 16.807 ;
     RECT  2.268 16.807 10.854 16.835 ;
     RECT  2.268 16.835 9.702 16.877 ;
     RECT  11.88 16.795 11.898 16.951 ;
     RECT  11.808 16.951 11.898 16.979 ;
     RECT  11.808 16.979 11.826 17.069 ;
     RECT  12.96 16.673 13.986 17.069 ;
     RECT  13.104 17.069 13.986 17.077 ;
     RECT  15.408 16.259 16.038 17.149 ;
     RECT  13.104 17.077 14.238 17.221 ;
     RECT  15.408 17.149 16.542 17.221 ;
     RECT  13.104 17.221 16.542 17.261 ;
     RECT  0.216 17.077 0.234 17.309 ;
     RECT  13.104 17.261 16.506 17.357 ;
     RECT  10.515 16.835 10.854 17.455 ;
     RECT  10.515 17.455 10.998 17.491 ;
     RECT  2.304 16.877 9.702 17.563 ;
     RECT  10.515 17.491 11.394 17.645 ;
     RECT  0.252 17.653 0.558 17.659 ;
     RECT  2.304 17.563 9.738 17.659 ;
     RECT  10.515 17.645 10.926 17.659 ;
     RECT  2.304 17.659 10.926 17.681 ;
     RECT  13.104 17.357 16.002 17.693 ;
     RECT  11.988 17.947 12.006 17.987 ;
     RECT  13.104 17.693 15.462 18.031 ;
     RECT  4.392 17.681 10.926 18.059 ;
     RECT  13.032 18.031 15.462 18.059 ;
     RECT  0.252 17.659 0.666 18.125 ;
     RECT  13.032 18.059 14.85 18.149 ;
     RECT  2.304 17.681 3.618 18.185 ;
     RECT  16.524 18.091 16.542 18.193 ;
     RECT  4.392 18.059 10.89 18.194 ;
     RECT  13.104 18.149 14.85 18.257 ;
     RECT  16.524 18.193 16.614 18.317 ;
     RECT  13.104 18.257 13.986 18.329 ;
     RECT  16.524 18.317 16.542 18.475 ;
     RECT  2.34 18.185 3.618 18.499 ;
     RECT  4.392 18.194 10.854 18.499 ;
     RECT  1.152 18.283 1.17 18.509 ;
     RECT  2.34 18.499 10.854 18.527 ;
     RECT  2.34 18.527 4.194 18.563 ;
     RECT  5.115 18.527 10.854 18.599 ;
     RECT  3.996 18.563 4.194 18.689 ;
     RECT  14.832 18.257 14.85 18.689 ;
     RECT  15.984 18.475 16.542 18.797 ;
     RECT  2.34 18.563 3.222 18.907 ;
     RECT  15.408 18.811 15.462 18.959 ;
     RECT  5.115 18.599 10.818 19.037 ;
     RECT  11.988 18.769 12.006 19.067 ;
     RECT  13.215 18.329 13.662 19.075 ;
     RECT  16.488 18.797 16.542 19.099 ;
     RECT  12.168 19.111 12.186 19.229 ;
     RECT  16.488 19.099 16.578 19.301 ;
     RECT  13.032 19.075 13.662 19.381 ;
     RECT  14.436 19.075 14.526 19.381 ;
     RECT  5.115 19.037 10.797 19.471 ;
     RECT  13.032 19.381 14.526 19.499 ;
     RECT  16.488 19.301 16.542 19.499 ;
     RECT  1.26 19.435 1.278 19.531 ;
     RECT  15.408 18.959 15.426 19.543 ;
     RECT  1.152 19.531 1.278 19.565 ;
     RECT  4.032 18.689 4.194 19.627 ;
     RECT  5.004 19.471 10.797 19.627 ;
     RECT  2.304 18.907 3.222 19.805 ;
     RECT  13.032 19.499 13.698 19.813 ;
     RECT  14.832 19.543 15.426 19.841 ;
     RECT  1.152 19.565 1.17 19.853 ;
     RECT  12.924 19.813 13.698 20.011 ;
     RECT  15.408 19.841 15.426 20.059 ;
     RECT  0.252 18.125 0.27 20.141 ;
     RECT  4.032 19.627 10.797 20.155 ;
     RECT  3.636 20.155 10.797 20.281 ;
     RECT  3.636 20.281 10.854 20.309 ;
     RECT  1.188 20.299 1.35 20.417 ;
     RECT  1.188 20.417 1.314 20.429 ;
     RECT  16.524 19.499 16.542 20.443 ;
     RECT  16.524 20.443 16.578 20.539 ;
     RECT  12.312 20.011 13.698 20.551 ;
     RECT  2.304 19.805 2.79 20.587 ;
     RECT  12.312 20.551 14.094 20.621 ;
     RECT  3.96 20.309 10.854 20.623 ;
     RECT  3.96 20.623 11.322 20.669 ;
     RECT  12.312 20.621 13.77 20.683 ;
     RECT  0.288 20.587 0.414 20.717 ;
     RECT  16.488 20.539 16.578 20.759 ;
     RECT  1.188 20.429 1.278 20.779 ;
     RECT  15.408 20.059 15.462 20.857 ;
     RECT  14.724 20.857 15.462 20.875 ;
     RECT  16.488 20.759 16.542 20.875 ;
     RECT  1.152 20.779 1.278 20.909 ;
     RECT  11.736 20.683 13.77 20.957 ;
     RECT  14.724 20.875 16.542 20.957 ;
     RECT  0.288 20.717 0.378 21.005 ;
     RECT  1.26 20.909 1.278 21.005 ;
     RECT  3.96 20.669 10.854 21.155 ;
     RECT  15.408 20.957 16.542 21.227 ;
     RECT  12.528 20.957 13.77 21.547 ;
     RECT  14.544 21.541 14.634 21.547 ;
     RECT  0.216 21.211 0.234 21.659 ;
     RECT  11.7 21.541 11.718 21.659 ;
     RECT  12.528 21.547 14.634 21.731 ;
     RECT  13.104 21.731 14.634 21.787 ;
     RECT  15.408 21.227 15.462 21.787 ;
     RECT  13.104 21.787 15.462 21.839 ;
     RECT  4.104 21.155 9.594 21.931 ;
     RECT  4.104 21.931 9.702 21.937 ;
     RECT  3.996 21.937 9.702 21.979 ;
     RECT  10.44 21.155 10.854 21.979 ;
     RECT  3.996 21.979 10.854 22.027 ;
     RECT  15.408 21.839 15.462 22.171 ;
     RECT  16.488 21.227 16.542 22.171 ;
     RECT  13.104 21.839 14.598 22.199 ;
     RECT  15.408 22.171 16.542 22.253 ;
     RECT  0.252 21.835 0.27 22.397 ;
     RECT  16.524 22.253 16.542 22.411 ;
     RECT  13.104 22.199 13.662 22.513 ;
     RECT  12.456 22.513 13.662 22.555 ;
     RECT  12.312 22.555 13.662 22.577 ;
     RECT  12.312 22.577 13.497 22.621 ;
     RECT  16.524 22.411 16.614 22.649 ;
     RECT  3.996 22.027 10.926 22.711 ;
     RECT  12.204 22.621 13.497 22.811 ;
     RECT  15.408 22.253 15.462 22.811 ;
     RECT  3.996 22.711 11.43 22.891 ;
     RECT  12.204 22.811 12.222 22.891 ;
     RECT  2.304 20.587 3.222 22.981 ;
     RECT  3.996 22.891 12.222 22.981 ;
     RECT  2.304 22.981 12.222 23.009 ;
     RECT  2.304 23.009 11.43 23.021 ;
     RECT  12.204 23.009 12.222 23.117 ;
     RECT  0.288 23.131 0.306 23.179 ;
     RECT  14.508 22.199 14.598 23.227 ;
     RECT  15.408 22.811 15.426 23.227 ;
     RECT  14.508 23.227 15.426 23.287 ;
     RECT  16.524 22.649 16.578 23.315 ;
     RECT  3.996 23.021 11.43 23.357 ;
     RECT  16.524 23.315 16.542 23.371 ;
     RECT  0.216 23.179 0.306 23.516 ;
     RECT  13.032 22.811 13.497 23.557 ;
     RECT  14.292 23.287 15.426 23.557 ;
     RECT  13.032 23.557 15.426 23.656 ;
     RECT  12.564 23.656 15.426 23.659 ;
     RECT  16.488 23.371 16.542 23.659 ;
     RECT  12.564 23.659 16.542 23.693 ;
     RECT  13.104 23.693 16.542 23.819 ;
     RECT  13.104 23.819 14.274 23.837 ;
     RECT  15.408 23.819 16.542 23.927 ;
     RECT  2.304 23.021 3.222 23.935 ;
     RECT  3.996 23.357 10.797 23.935 ;
     RECT  2.304 23.935 10.797 24.089 ;
     RECT  4.14 24.089 10.797 24.187 ;
     RECT  11.52 23.947 12.366 24.187 ;
     RECT  4.14 24.187 12.366 24.197 ;
     RECT  0.252 23.516 0.306 24.331 ;
     RECT  12.348 24.197 12.366 24.359 ;
     RECT  0.252 24.331 0.414 24.461 ;
     RECT  13.215 23.837 14.274 24.571 ;
     RECT  15.408 23.927 15.426 24.571 ;
     RECT  13.215 24.571 15.426 24.715 ;
     RECT  0.252 24.461 0.27 24.893 ;
     RECT  12.564 24.715 15.426 24.907 ;
     RECT  12.564 24.907 15.462 24.941 ;
     RECT  13.104 24.941 15.462 25.003 ;
     RECT  16.452 23.927 16.542 25.003 ;
     RECT  0.216 24.955 0.234 25.007 ;
     RECT  4.14 24.197 11.394 25.051 ;
     RECT  13.104 25.003 16.542 25.079 ;
     RECT  13.104 25.079 14.886 25.229 ;
     RECT  3.96 25.051 11.394 25.285 ;
     RECT  2.304 24.089 3.222 25.291 ;
     RECT  3.96 25.285 12.078 25.291 ;
     RECT  2.304 25.291 12.078 25.439 ;
     RECT  13.215 25.229 14.886 25.511 ;
     RECT  15.984 25.079 16.542 25.661 ;
     RECT  2.304 25.439 11.97 25.817 ;
     RECT  14.58 25.511 14.886 26.023 ;
     RECT  13.215 25.511 13.497 26.221 ;
     RECT  12.708 26.221 13.497 26.299 ;
     RECT  0.216 26.203 0.234 26.347 ;
     RECT  12.564 26.299 13.497 26.401 ;
     RECT  0.216 26.347 0.306 26.491 ;
     RECT  16.488 25.661 16.542 26.518 ;
     RECT  0.216 26.491 0.414 26.519 ;
     RECT  0.252 26.519 0.414 26.621 ;
     RECT  12.564 26.401 13.734 26.627 ;
     RECT  12.888 26.627 13.734 26.635 ;
     RECT  14.58 26.023 15.426 26.635 ;
     RECT  2.304 25.817 11.43 26.671 ;
     RECT  16.452 26.518 16.542 26.716 ;
     RECT  12.888 26.635 15.426 26.761 ;
     RECT  16.452 26.716 16.614 26.761 ;
     RECT  12.888 26.761 16.614 26.789 ;
     RECT  12.888 26.789 16.542 26.813 ;
     RECT  2.304 26.671 11.97 26.909 ;
     RECT  2.304 26.909 11.502 27.329 ;
     RECT  12.888 26.813 15.426 27.329 ;
     RECT  0.252 26.621 0.27 27.403 ;
     RECT  12.888 27.329 13.77 27.409 ;
     RECT  12.456 27.409 13.77 27.599 ;
     RECT  2.304 27.329 10.854 27.671 ;
     RECT  4.932 27.671 10.854 27.68 ;
     RECT  14.544 27.329 15.426 27.841 ;
     RECT  16.488 26.813 16.542 27.841 ;
     RECT  0.252 27.403 0.306 27.869 ;
     RECT  12.96 27.599 13.77 27.941 ;
     RECT  0.216 27.877 0.234 27.965 ;
     RECT  13.215 27.941 13.77 28.255 ;
     RECT  14.544 27.841 16.542 28.255 ;
     RECT  11.7 27.751 11.718 28.409 ;
     RECT  2.304 27.671 4.158 28.417 ;
     RECT  4.932 27.68 10.797 28.417 ;
     RECT  2.304 28.417 10.797 28.445 ;
     RECT  13.215 28.255 16.542 28.541 ;
     RECT  11.952 28.561 11.97 28.747 ;
     RECT  13.215 28.541 15.462 28.747 ;
     RECT  11.952 28.747 15.462 28.787 ;
     RECT  14.832 28.787 15.462 28.877 ;
     RECT  11.952 28.787 13.626 28.949 ;
     RECT  2.304 28.445 6.282 29.083 ;
     RECT  2.268 29.083 6.282 29.129 ;
     RECT  5.112 29.129 6.282 29.191 ;
     RECT  7.02 28.445 10.797 29.191 ;
     RECT  12.636 28.949 13.626 29.219 ;
     RECT  0.252 29.275 0.27 29.453 ;
     RECT  12.636 29.219 13.497 29.597 ;
     RECT  14.832 28.877 15.426 29.641 ;
     RECT  14.256 29.641 15.426 29.755 ;
     RECT  14.256 29.755 15.462 29.831 ;
     RECT  16.488 28.541 16.542 30.029 ;
     RECT  5.112 29.191 10.797 30.145 ;
     RECT  2.304 29.129 4.302 30.271 ;
     RECT  5.112 30.145 10.854 30.271 ;
     RECT  12.888 29.597 13.497 30.271 ;
     RECT  14.256 29.831 15.426 30.271 ;
     RECT  0.252 30.235 0.27 30.427 ;
     RECT  12.888 30.271 15.426 30.479 ;
     RECT  0.252 30.427 0.306 30.653 ;
     RECT  0.288 30.653 0.306 30.667 ;
     RECT  12.888 30.479 14.094 30.667 ;
     RECT  12.564 30.667 14.094 30.713 ;
     RECT  16.524 30.029 16.542 30.749 ;
     RECT  0.288 30.667 0.342 30.763 ;
     RECT  2.304 30.271 10.854 30.883 ;
     RECT  0.288 30.763 0.45 30.893 ;
     RECT  14.832 30.479 15.426 31.003 ;
     RECT  13.104 30.713 14.094 31.019 ;
     RECT  0.288 30.893 0.378 31.037 ;
     RECT  0.36 31.037 0.378 31.085 ;
     RECT  13.104 31.019 14.022 31.109 ;
     RECT  2.304 30.883 11.43 31.387 ;
     RECT  14.832 31.003 15.462 31.469 ;
     RECT  13.104 31.109 13.878 31.559 ;
     RECT  16.488 30.907 16.506 31.627 ;
     RECT  2.304 31.387 11.502 31.675 ;
     RECT  2.304 31.675 12.042 31.693 ;
     RECT  13.104 31.559 13.497 31.693 ;
     RECT  16.488 31.627 16.542 31.693 ;
     RECT  2.304 31.693 13.497 31.805 ;
     RECT  14.832 31.469 14.922 31.891 ;
     RECT  2.304 31.805 4.194 31.955 ;
     RECT  15.984 31.693 16.542 31.997 ;
     RECT  5.004 31.805 10.797 32.237 ;
     RECT  14.22 31.891 14.922 32.251 ;
     RECT  5.004 32.237 9.702 32.261 ;
     RECT  11.952 31.805 13.497 32.341 ;
     RECT  14.22 32.251 15.426 32.341 ;
     RECT  11.952 32.341 15.426 32.369 ;
     RECT  10.515 32.237 10.797 32.587 ;
     RECT  11.952 32.369 12.006 32.587 ;
     RECT  0.216 32.428 0.306 32.621 ;
     RECT  0.216 32.621 0.234 32.669 ;
     RECT  4.068 31.955 4.194 32.737 ;
     RECT  5.004 32.261 9.666 32.737 ;
     RECT  12.816 32.369 15.426 33.005 ;
     RECT  3.996 32.737 9.666 33.007 ;
     RECT  10.515 32.587 12.006 33.007 ;
     RECT  16.488 31.997 16.542 33.007 ;
     RECT  3.996 33.007 12.006 33.071 ;
     RECT  12.816 33.005 14.886 33.421 ;
     RECT  15.984 33.007 16.542 33.437 ;
     RECT  3.996 33.071 11.538 33.539 ;
     RECT  12.456 33.421 14.886 33.539 ;
     RECT  3.996 33.539 11.43 33.575 ;
     RECT  0.252 33.451 0.27 33.643 ;
     RECT  3.996 33.575 9.738 33.655 ;
     RECT  12.492 33.539 14.886 33.835 ;
     RECT  0.252 33.643 0.342 33.965 ;
     RECT  16.524 33.437 16.542 34.114 ;
     RECT  3.96 33.655 9.738 34.115 ;
     RECT  12.492 33.835 15.462 34.115 ;
     RECT  14.256 34.115 15.462 34.259 ;
     RECT  14.724 34.259 15.462 34.321 ;
     RECT  16.524 34.114 16.578 34.321 ;
     RECT  3.996 34.115 9.738 34.393 ;
     RECT  10.515 33.575 11.43 34.456 ;
     RECT  14.724 34.321 16.578 34.457 ;
     RECT  10.515 34.456 12.366 34.493 ;
     RECT  14.724 34.457 16.002 34.493 ;
     RECT  2.304 31.955 3.222 34.655 ;
     RECT  12.348 34.493 12.366 34.727 ;
     RECT  14.832 34.493 16.002 34.763 ;
     RECT  3.996 34.393 9.774 34.861 ;
     RECT  10.515 34.493 11.394 34.861 ;
     RECT  14.832 34.763 15.462 34.889 ;
     RECT  13.215 34.115 13.497 34.933 ;
     RECT  0.252 33.965 0.27 34.969 ;
     RECT  12.564 34.933 13.497 35.021 ;
     RECT  14.832 34.889 15.426 35.069 ;
     RECT  0.216 34.969 0.306 35.083 ;
     RECT  13.104 35.021 13.497 35.165 ;
     RECT  0.216 35.083 0.378 35.309 ;
     RECT  3.996 34.861 11.394 35.437 ;
     RECT  16.488 35.275 16.542 35.501 ;
     RECT  13.215 35.165 13.497 35.545 ;
     RECT  14.868 35.069 15.426 35.659 ;
     RECT  16.488 35.501 16.506 35.659 ;
     RECT  13.215 35.545 14.13 35.699 ;
     RECT  14.868 35.659 16.506 35.803 ;
     RECT  12.204 35.515 12.222 35.807 ;
     RECT  3.96 35.437 11.394 36.04 ;
     RECT  2.415 34.655 3.222 36.049 ;
     RECT  3.96 36.04 11.43 36.049 ;
     RECT  13.215 35.699 14.058 36.083 ;
     RECT  2.415 36.049 11.43 36.235 ;
     RECT  2.34 36.235 11.43 36.365 ;
     RECT  14.832 35.803 16.506 36.419 ;
     RECT  0.216 35.309 0.306 36.475 ;
     RECT  0.216 36.475 0.342 36.476 ;
     RECT  3.96 36.365 11.43 36.509 ;
     RECT  13.215 36.083 14.022 36.589 ;
     RECT  12.816 36.589 14.022 36.619 ;
     RECT  15.984 36.419 16.506 36.619 ;
     RECT  2.34 36.365 3.222 36.667 ;
     RECT  0.288 36.476 0.342 36.763 ;
     RECT  5.004 36.509 11.43 36.887 ;
     RECT  12.348 36.619 14.022 36.931 ;
     RECT  14.832 36.419 14.85 36.931 ;
     RECT  0.288 36.763 0.414 37.003 ;
     RECT  12.348 36.931 14.85 37.021 ;
     RECT  12.276 37.021 14.85 37.121 ;
     RECT  0.288 37.003 0.594 37.133 ;
     RECT  0.288 37.133 0.414 37.229 ;
     RECT  12.564 37.121 14.85 37.243 ;
     RECT  15.984 36.619 16.542 37.243 ;
     RECT  0.288 37.229 0.342 37.291 ;
     RECT  12.564 37.243 16.542 37.469 ;
     RECT  3.96 36.509 4.194 37.471 ;
     RECT  5.004 36.887 10.998 37.471 ;
     RECT  2.304 36.667 3.222 37.579 ;
     RECT  3.96 37.471 10.998 37.579 ;
     RECT  2.304 37.579 10.998 37.589 ;
     RECT  2.304 37.589 10.926 37.625 ;
     RECT  12.564 37.469 16.002 37.661 ;
     RECT  0.216 37.291 0.342 37.769 ;
     RECT  3.996 37.625 10.818 37.901 ;
     RECT  0.252 37.769 0.342 38.173 ;
     RECT  0.252 38.173 0.558 38.189 ;
     RECT  3.996 37.901 10.797 38.189 ;
     RECT  12.564 37.661 15.462 38.201 ;
     RECT  0.54 38.189 0.558 38.285 ;
     RECT  12.564 38.201 15.426 38.551 ;
     RECT  2.304 37.625 3.222 38.635 ;
     RECT  3.996 38.189 9.486 38.635 ;
     RECT  12.492 38.551 15.426 38.641 ;
     RECT  16.56 38.587 16.578 38.641 ;
     RECT  12.348 38.641 15.426 38.675 ;
     RECT  16.524 38.641 16.578 38.752 ;
     RECT  10.515 38.189 10.797 38.779 ;
     RECT  10.515 38.779 11.178 38.911 ;
     RECT  14.292 38.675 15.426 38.939 ;
     RECT  2.304 38.635 9.486 38.947 ;
     RECT  2.304 38.947 9.558 38.983 ;
     RECT  10.515 38.911 11.286 38.983 ;
     RECT  16.524 38.752 16.542 39.115 ;
     RECT  2.304 38.983 11.286 39.361 ;
     RECT  12.348 38.675 13.497 39.361 ;
     RECT  14.292 38.939 14.598 39.487 ;
     RECT  0.252 39.499 0.27 39.547 ;
     RECT  14.256 39.487 14.598 39.721 ;
     RECT  15.372 38.939 15.426 39.721 ;
     RECT  0.252 39.547 0.342 39.821 ;
     RECT  14.256 39.721 15.426 39.829 ;
     RECT  2.304 39.361 13.497 39.901 ;
     RECT  14.22 39.829 15.426 39.901 ;
     RECT  2.304 39.901 15.426 39.931 ;
     RECT  16.488 39.115 16.542 39.931 ;
     RECT  2.304 39.931 16.542 40.127 ;
     RECT  2.304 40.127 13.497 40.163 ;
     RECT  14.22 40.127 15.462 40.199 ;
     RECT  16.488 40.127 16.542 40.219 ;
     RECT  0.252 39.821 0.27 40.253 ;
     RECT  4.14 40.163 13.497 40.289 ;
     RECT  4.14 40.289 11.97 40.469 ;
     RECT  4.14 40.469 11.862 40.925 ;
     RECT  12.924 40.289 13.497 41.071 ;
     RECT  12.924 41.071 14.058 41.215 ;
     RECT  14.832 40.199 15.462 41.215 ;
     RECT  16.488 40.219 16.578 41.309 ;
     RECT  0.54 41.143 0.558 41.323 ;
     RECT  12.924 41.215 15.462 41.368 ;
     RECT  4.14 40.925 10.854 41.377 ;
     RECT  12.708 41.368 15.462 41.449 ;
     RECT  16.488 41.309 16.542 41.449 ;
     RECT  0.252 41.323 0.558 41.453 ;
     RECT  11.844 40.925 11.862 41.549 ;
     RECT  0.288 41.453 0.558 41.597 ;
     RECT  2.304 40.163 3.258 41.611 ;
     RECT  2.304 41.611 3.294 41.755 ;
     RECT  4.032 41.377 10.854 41.755 ;
     RECT  12.708 41.449 16.542 41.755 ;
     RECT  11.988 41.755 16.542 41.933 ;
     RECT  0.288 41.597 0.486 41.945 ;
     RECT  0.288 41.945 0.414 41.981 ;
     RECT  12.06 41.933 16.542 42.089 ;
     RECT  2.304 41.755 10.854 42.179 ;
     RECT  12.852 42.089 16.542 42.421 ;
     RECT  12.852 42.421 16.578 42.485 ;
     RECT  16.488 42.485 16.578 42.653 ;
     RECT  0.252 42.235 0.27 42.701 ;
     RECT  12.06 42.089 12.078 42.719 ;
     RECT  12.852 42.485 15.426 42.719 ;
     RECT  2.304 42.179 10.797 42.755 ;
     RECT  11.916 42.811 12.042 43.099 ;
     RECT  11.592 43.099 12.042 43.259 ;
     RECT  14.256 42.719 15.426 43.267 ;
     RECT  0.396 43.195 0.414 43.325 ;
     RECT  2.304 42.755 3.546 43.367 ;
     RECT  14.256 43.267 15.498 43.373 ;
     RECT  16.488 42.653 16.506 43.435 ;
     RECT  4.392 42.755 10.797 43.609 ;
     RECT  16.488 43.435 16.542 43.675 ;
     RECT  4.104 43.609 10.797 43.681 ;
     RECT  11.556 43.573 11.574 43.681 ;
     RECT  4.104 43.681 11.574 43.709 ;
     RECT  4.104 43.709 11.502 43.799 ;
     RECT  13.104 42.719 13.497 43.843 ;
     RECT  14.256 43.373 15.426 43.843 ;
     RECT  16.488 43.675 16.578 43.871 ;
     RECT  13.104 43.843 15.426 43.951 ;
     RECT  2.304 43.367 3.222 44.113 ;
     RECT  4.104 43.799 10.854 44.113 ;
     RECT  13.032 43.951 15.426 44.185 ;
     RECT  0.252 44.203 0.27 44.251 ;
     RECT  12.384 44.185 15.426 44.339 ;
     RECT  12.564 44.339 15.426 44.381 ;
     RECT  14.256 44.381 15.426 44.491 ;
     RECT  16.488 43.871 16.542 44.491 ;
     RECT  2.304 44.113 10.854 44.609 ;
     RECT  14.256 44.491 16.542 44.717 ;
     RECT  0.252 44.251 0.414 45.005 ;
     RECT  5.004 44.609 10.854 45.031 ;
     RECT  14.256 44.717 15.426 45.149 ;
     RECT  5.004 45.031 11.25 45.211 ;
     RECT  12.564 44.381 13.497 45.229 ;
     RECT  5.004 45.211 11.322 45.257 ;
     RECT  5.004 45.257 11.25 45.293 ;
     RECT  0.252 45.005 0.306 45.341 ;
     RECT  12.492 45.229 13.497 45.455 ;
     RECT  2.304 44.609 4.194 45.499 ;
     RECT  5.004 45.293 11.07 45.499 ;
     RECT  14.472 45.149 15.426 45.499 ;
     RECT  12.672 45.455 13.497 45.599 ;
     RECT  14.472 45.499 15.462 45.599 ;
     RECT  14.832 45.599 15.462 45.643 ;
     RECT  16.488 44.717 16.542 45.643 ;
     RECT  12.96 45.599 13.497 45.761 ;
     RECT  14.832 45.643 16.542 45.761 ;
     RECT  2.304 45.499 11.07 45.841 ;
     RECT  13.212 45.761 13.497 45.841 ;
     RECT  2.268 45.841 11.07 46.067 ;
     RECT  13.212 45.841 13.518 46.075 ;
     RECT  2.304 46.067 11.07 46.229 ;
     RECT  16.488 45.761 16.542 46.309 ;
     RECT  10.515 46.229 11.07 46.315 ;
     RECT  16.488 46.309 16.578 46.493 ;
     RECT  12.348 46.381 12.366 46.507 ;
     RECT  12.168 46.507 12.366 46.544 ;
     RECT  13.212 46.075 13.986 46.555 ;
     RECT  10.515 46.315 11.43 46.603 ;
     RECT  12.564 46.555 13.986 46.615 ;
     RECT  14.832 45.761 15.426 46.615 ;
     RECT  12.564 46.615 15.426 46.921 ;
     RECT  16.488 46.493 16.542 46.921 ;
     RECT  2.304 46.229 9.774 47.011 ;
     RECT  10.515 46.603 11.682 47.011 ;
     RECT  2.304 47.011 11.682 47.183 ;
     RECT  12.564 46.921 16.542 47.213 ;
     RECT  0.252 45.341 0.27 47.309 ;
     RECT  12.564 47.213 16.002 47.489 ;
     RECT  0.288 47.323 0.342 47.563 ;
     RECT  6.12 47.183 11.682 47.611 ;
     RECT  2.304 47.183 5.397 47.849 ;
     RECT  0.288 47.563 0.414 47.857 ;
     RECT  0.288 47.857 0.558 47.933 ;
     RECT  5.004 47.849 5.397 48.001 ;
     RECT  6.12 47.611 11.826 48.001 ;
     RECT  0.288 47.933 0.414 48.043 ;
     RECT  2.304 47.849 4.158 48.043 ;
     RECT  5.004 48.001 11.826 48.128 ;
     RECT  2.232 48.043 4.158 48.155 ;
     RECT  0.252 48.043 0.414 48.221 ;
     RECT  5.115 48.128 11.826 48.235 ;
     RECT  12.564 47.489 15.462 48.235 ;
     RECT  5.115 48.235 15.462 48.263 ;
     RECT  0.252 48.221 0.342 48.361 ;
     RECT  13.215 48.263 15.462 48.361 ;
     RECT  16.524 48.235 16.542 48.361 ;
     RECT  5.115 48.263 12.042 48.389 ;
     RECT  0.216 48.361 0.342 48.413 ;
     RECT  6.12 48.389 12.042 48.425 ;
     RECT  13.215 48.361 16.542 48.425 ;
     RECT  6.12 48.425 11.646 48.461 ;
     RECT  14.724 48.425 16.542 48.461 ;
     RECT  4.104 48.155 4.158 48.775 ;
     RECT  14.724 48.461 15.426 48.803 ;
     RECT  2.304 48.155 3.33 48.955 ;
     RECT  4.104 48.775 4.302 48.955 ;
     RECT  6.12 48.461 11.43 49.001 ;
     RECT  6.12 49.001 10.962 49.073 ;
     RECT  13.215 48.425 13.59 49.081 ;
     RECT  1.116 49.003 1.134 49.133 ;
     RECT  6.12 49.073 9.702 49.181 ;
     RECT  2.304 48.955 4.302 49.195 ;
     RECT  5.115 48.389 5.397 49.195 ;
     RECT  0.252 48.413 0.342 49.277 ;
     RECT  12.672 49.081 13.59 49.379 ;
     RECT  14.832 48.803 15.426 49.379 ;
     RECT  16.524 48.461 16.542 49.505 ;
     RECT  15.408 49.379 15.426 49.585 ;
     RECT  2.304 49.195 5.397 49.711 ;
     RECT  6.12 49.181 9.378 49.711 ;
     RECT  11.808 49.585 11.826 49.711 ;
     RECT  12.672 49.379 13.497 49.711 ;
     RECT  2.304 49.711 9.378 49.739 ;
     RECT  15.408 49.585 15.498 49.771 ;
     RECT  10.515 49.073 10.962 49.819 ;
     RECT  15.408 49.771 16.002 49.847 ;
     RECT  2.304 49.739 2.898 49.853 ;
     RECT  14.472 49.621 14.49 49.891 ;
     RECT  15.408 49.847 15.498 49.901 ;
     RECT  11.808 49.711 13.497 50.009 ;
     RECT  3.708 49.739 9.378 50.051 ;
     RECT  4.5 50.051 9.378 50.081 ;
     RECT  15.408 49.901 15.462 50.093 ;
     RECT  10.515 49.819 11.07 50.107 ;
     RECT  4.896 50.081 9.378 50.203 ;
     RECT  10.224 50.107 11.07 50.203 ;
     RECT  12.564 50.009 13.497 50.279 ;
     RECT  14.4 49.891 14.49 50.299 ;
     RECT  15.408 50.093 15.426 50.299 ;
     RECT  12.708 50.279 13.497 50.359 ;
     RECT  14.4 50.299 15.426 50.359 ;
     RECT  12.708 50.359 15.426 50.549 ;
     RECT  16.488 50.395 16.506 50.587 ;
     RECT  4.896 50.203 11.07 50.701 ;
     RECT  2.304 49.853 2.862 50.855 ;
     RECT  12.924 50.549 15.426 50.899 ;
     RECT  16.488 50.587 16.542 50.899 ;
     RECT  2.34 50.855 2.862 50.935 ;
     RECT  3.708 50.051 3.762 50.935 ;
     RECT  4.896 50.701 11.25 50.935 ;
     RECT  4.716 50.935 11.25 50.963 ;
     RECT  12.924 50.899 16.542 50.999 ;
     RECT  0.252 49.277 0.27 51.005 ;
     RECT  4.716 50.963 10.854 51.089 ;
     RECT  2.34 50.935 3.978 51.097 ;
     RECT  12.924 50.999 14.418 51.125 ;
     RECT  15.408 50.999 16.542 51.161 ;
     RECT  14.256 51.125 14.418 51.233 ;
     RECT  14.292 51.233 14.418 51.269 ;
     RECT  0.324 51.307 0.342 51.331 ;
     RECT  14.328 51.269 14.418 51.359 ;
     RECT  0.324 51.331 0.414 51.389 ;
     RECT  12.924 51.125 13.497 51.403 ;
     RECT  14.4 51.359 14.418 51.539 ;
     RECT  2.34 51.097 4.05 51.595 ;
     RECT  0.324 51.389 0.342 51.725 ;
     RECT  5.115 51.089 10.854 51.736 ;
     RECT  5.115 51.736 11.286 51.781 ;
     RECT  5.115 51.781 11.394 51.835 ;
     RECT  16.524 51.161 16.542 51.931 ;
     RECT  12.564 51.403 13.497 52.051 ;
     RECT  16.524 51.931 16.614 52.079 ;
     RECT  5.004 51.835 11.394 52.141 ;
     RECT  12.528 52.051 13.497 52.141 ;
     RECT  15.408 51.161 15.462 52.171 ;
     RECT  2.304 51.595 4.05 52.213 ;
     RECT  2.304 52.213 4.194 52.241 ;
     RECT  3.96 52.241 4.194 52.249 ;
     RECT  5.004 52.141 13.497 52.249 ;
     RECT  3.96 52.249 13.497 52.267 ;
     RECT  3.96 52.267 13.878 52.321 ;
     RECT  14.868 52.171 15.462 52.321 ;
     RECT  3.96 52.321 13.95 52.591 ;
     RECT  14.868 52.321 15.498 52.591 ;
     RECT  3.96 52.591 16.002 52.685 ;
     RECT  3.96 52.685 15.462 52.709 ;
     RECT  3.96 52.709 12.186 52.829 ;
     RECT  3.96 52.829 10.926 52.853 ;
     RECT  0.252 51.979 0.27 53.179 ;
     RECT  2.304 52.241 3.222 53.401 ;
     RECT  3.96 52.853 10.797 53.401 ;
     RECT  0.216 53.179 0.27 53.429 ;
     RECT  13.104 52.709 15.462 53.515 ;
     RECT  16.524 52.987 16.542 53.515 ;
     RECT  11.952 52.829 12.186 53.519 ;
     RECT  13.104 53.515 16.542 53.555 ;
     RECT  16.524 53.555 16.542 53.635 ;
     RECT  13.104 53.555 15.462 53.699 ;
     RECT  2.304 53.401 10.797 53.761 ;
     RECT  13.104 53.699 14.094 53.761 ;
     RECT  1.26 53.563 1.278 53.803 ;
     RECT  2.304 53.761 10.854 53.803 ;
     RECT  16.524 53.635 16.614 53.837 ;
     RECT  2.304 53.803 11.43 53.995 ;
     RECT  0.252 53.429 0.27 54.029 ;
     RECT  2.232 53.995 11.43 54.059 ;
     RECT  2.232 54.059 10.962 54.077 ;
     RECT  2.232 54.077 10.89 54.095 ;
     RECT  1.152 53.803 1.278 54.103 ;
     RECT  0.54 54.103 1.278 54.125 ;
     RECT  12.528 53.761 14.094 54.125 ;
     RECT  13.215 54.125 14.094 54.131 ;
     RECT  0.54 54.125 0.558 54.221 ;
     RECT  14.832 53.699 15.462 54.427 ;
     RECT  16.524 53.837 16.542 54.427 ;
     RECT  14.832 54.427 16.542 54.509 ;
     RECT  11.988 54.427 12.042 54.653 ;
     RECT  12.024 54.653 12.042 54.671 ;
     RECT  14.544 54.571 14.634 54.701 ;
     RECT  2.304 54.095 10.89 54.707 ;
     RECT  15.408 54.509 16.542 54.905 ;
     RECT  13.215 54.131 13.77 54.985 ;
     RECT  13.215 54.985 14.49 55.139 ;
     RECT  16.488 54.905 16.542 55.139 ;
     RECT  13.215 55.139 13.986 55.181 ;
     RECT  15.408 54.905 15.462 55.483 ;
     RECT  14.868 55.483 15.462 55.589 ;
     RECT  2.304 54.707 10.854 55.675 ;
     RECT  11.988 55.531 12.006 55.675 ;
     RECT  0.288 54.811 0.378 55.708 ;
     RECT  14.868 55.589 15.426 55.867 ;
     RECT  2.304 55.675 12.006 56.029 ;
     RECT  13.215 55.181 13.662 56.101 ;
     RECT  16.524 55.139 16.542 56.107 ;
     RECT  2.304 56.029 12.222 56.129 ;
     RECT  16.488 56.107 16.542 56.219 ;
     RECT  13.104 56.101 13.662 56.251 ;
     RECT  4.068 56.129 12.222 56.299 ;
     RECT  13.104 56.251 14.022 56.299 ;
     RECT  0.216 55.708 0.378 56.395 ;
     RECT  14.832 55.867 15.426 56.395 ;
     RECT  14.832 56.395 15.462 56.489 ;
     RECT  0.216 56.395 0.594 56.587 ;
     RECT  0.216 56.587 1.314 56.621 ;
     RECT  0.216 56.621 0.414 56.717 ;
     RECT  1.152 56.621 1.314 56.765 ;
     RECT  4.068 56.299 14.022 56.827 ;
     RECT  14.832 56.489 15.426 56.827 ;
     RECT  16.524 56.219 16.542 56.827 ;
     RECT  4.068 56.827 15.426 56.831 ;
     RECT  1.152 56.765 1.278 56.861 ;
     RECT  2.304 56.129 3.33 56.869 ;
     RECT  4.068 56.831 5.397 56.869 ;
     RECT  0.216 56.717 0.342 56.957 ;
     RECT  2.304 56.869 5.397 57.181 ;
     RECT  2.268 57.181 5.397 57.245 ;
     RECT  16.524 56.827 16.578 57.271 ;
     RECT  6.192 56.831 15.426 57.299 ;
     RECT  13.176 57.299 15.426 57.415 ;
     RECT  16.488 57.271 16.578 57.415 ;
     RECT  0.288 56.957 0.342 57.451 ;
     RECT  0.288 57.451 0.558 57.581 ;
     RECT  6.192 57.299 12.438 58.109 ;
     RECT  13.176 57.415 16.578 58.123 ;
     RECT  0.288 57.581 0.45 58.171 ;
     RECT  6.192 58.109 11.862 58.225 ;
     RECT  0.216 58.171 0.45 58.493 ;
     RECT  0.216 58.493 0.414 58.589 ;
     RECT  0.216 58.589 0.306 58.685 ;
     RECT  2.304 57.245 5.397 58.801 ;
     RECT  6.12 58.225 11.862 58.801 ;
     RECT  12.78 58.123 16.578 58.829 ;
     RECT  2.304 58.801 11.862 58.891 ;
     RECT  2.268 58.891 11.862 58.928 ;
     RECT  2.304 58.928 11.862 58.939 ;
     RECT  12.78 58.829 16.542 58.939 ;
     RECT  2.304 58.939 16.542 59.021 ;
     RECT  2.304 59.021 16.002 59.117 ;
     RECT  10.515 59.117 16.002 59.297 ;
     RECT  11.844 59.297 16.002 59.333 ;
     RECT  11.844 59.333 15.462 59.729 ;
     RECT  2.304 59.117 9.774 59.899 ;
     RECT  10.515 59.297 10.797 59.899 ;
     RECT  11.844 59.729 12.006 59.933 ;
     RECT  0.216 58.685 0.27 59.995 ;
     RECT  2.304 59.899 10.797 59.999 ;
     RECT  11.988 59.933 12.006 60.125 ;
     RECT  16.524 60.079 16.542 60.173 ;
     RECT  4.104 59.999 10.797 60.227 ;
     RECT  0.216 59.995 0.342 60.269 ;
     RECT  12.852 59.729 15.462 60.269 ;
     RECT  2.304 59.999 3.222 60.305 ;
     RECT  4.104 60.227 10.605 60.305 ;
     RECT  13.068 60.269 15.462 60.331 ;
     RECT  4.176 60.305 5.205 60.341 ;
     RECT  6.372 60.305 10.605 60.341 ;
     RECT  13.068 60.331 16.038 60.341 ;
     RECT  4.536 60.341 5.205 60.365 ;
     RECT  2.304 60.305 2.898 60.377 ;
     RECT  6.768 60.341 10.605 60.413 ;
     RECT  13.068 60.341 14.022 60.413 ;
     RECT  16.02 60.341 16.038 60.413 ;
     RECT  13.215 60.413 14.022 60.461 ;
     RECT  5.004 60.365 5.205 60.497 ;
     RECT  6.768 60.413 7.905 60.497 ;
     RECT  10.404 60.413 10.605 60.497 ;
     RECT  13.215 60.461 13.305 60.497 ;
     RECT  2.304 60.377 2.61 60.539 ;
     RECT  6.768 60.497 7.398 60.539 ;
     RECT  8.712 60.413 9.558 60.539 ;
     RECT  2.592 60.539 2.61 60.557 ;
     RECT  5.004 60.497 5.022 60.557 ;
     RECT  6.768 60.539 7.146 60.605 ;
     RECT  7.128 60.605 7.146 60.611 ;
     RECT  8.784 60.539 9.558 60.611 ;
     RECT  10.404 60.497 10.422 60.611 ;
     RECT  0.216 60.269 0.234 61.034 ;
     RECT  9.54 60.611 9.558 61.034 ;
    LAYER M4 ;
     RECT  0.192 2.208 0.205 2.232 ;
     RECT  0.156 2.232 0.205 2.304 ;
     RECT  0.192 2.304 0.205 2.328 ;
     RECT  0.156 2.328 0.205 2.448 ;
     RECT  0.192 2.448 0.205 2.472 ;
     RECT  0.156 2.472 0.205 2.544 ;
     RECT  0.192 2.544 0.205 2.568 ;
     RECT  0.156 2.568 0.205 2.64 ;
     RECT  0.192 2.64 0.205 2.664 ;
     RECT  0.156 2.664 0.205 2.736 ;
     RECT  0.192 2.736 0.205 2.76 ;
     RECT  0.156 2.76 0.205 2.832 ;
     RECT  0.192 2.832 0.205 2.856 ;
     RECT  0.156 2.856 0.205 2.928 ;
     RECT  0.192 2.928 0.205 2.952 ;
     RECT  0.156 2.952 0.205 3.072 ;
     RECT  0.192 3.072 0.205 3.096 ;
     RECT  0.156 3.096 0.205 3.168 ;
     RECT  0.192 3.168 0.205 3.192 ;
     RECT  0.156 3.192 0.205 3.264 ;
     RECT  0.192 3.264 0.205 3.288 ;
     RECT  0.156 3.288 0.205 3.36 ;
     RECT  0.192 3.36 0.205 3.384 ;
     RECT  0.156 3.384 0.205 3.456 ;
     RECT  0.192 3.456 0.205 3.48 ;
     RECT  0.156 3.48 0.205 3.552 ;
     RECT  0.192 3.552 0.205 3.576 ;
     RECT  0.156 3.576 0.205 3.696 ;
     RECT  0.192 3.696 0.205 3.72 ;
     RECT  0.156 3.72 0.205 3.792 ;
     RECT  0.192 3.792 0.205 3.816 ;
     RECT  0.156 3.816 0.205 3.888 ;
     RECT  0.192 3.888 0.205 3.912 ;
     RECT  0.156 3.912 0.205 3.984 ;
     RECT  0.192 3.984 0.205 4.008 ;
     RECT  0.156 4.008 0.205 4.08 ;
     RECT  0.192 4.08 0.205 4.104 ;
     RECT  0.156 4.104 0.205 4.176 ;
     RECT  0.192 4.176 0.205 4.2 ;
     RECT  0.156 4.2 0.205 4.32 ;
     RECT  0.192 4.32 0.205 4.344 ;
     RECT  0.156 4.344 0.205 4.416 ;
     RECT  0.192 4.416 0.205 4.44 ;
     RECT  0.156 4.44 0.205 4.512 ;
     RECT  0.192 4.512 0.205 4.536 ;
     RECT  0.156 4.536 0.205 4.608 ;
     RECT  0.192 4.608 0.205 4.632 ;
     RECT  0.156 4.632 0.205 4.704 ;
     RECT  0.192 4.704 0.205 4.728 ;
     RECT  0.156 4.728 0.205 4.8 ;
     RECT  0.192 4.8 0.205 4.824 ;
     RECT  0.156 4.824 0.205 4.944 ;
     RECT  0.192 4.944 0.205 4.968 ;
     RECT  0.156 4.968 0.205 5.04 ;
     RECT  0.192 5.04 0.205 5.064 ;
     RECT  0.156 5.064 0.205 5.136 ;
     RECT  0.192 5.136 0.205 5.16 ;
     RECT  0.156 5.16 0.205 5.232 ;
     RECT  0.192 5.232 0.205 5.256 ;
     RECT  0.156 5.256 0.205 5.328 ;
     RECT  0.192 5.328 0.205 5.352 ;
     RECT  0.156 5.352 0.205 5.424 ;
     RECT  0.192 5.424 0.205 5.448 ;
     RECT  0.156 5.448 0.205 5.568 ;
     RECT  0.192 5.568 0.205 5.592 ;
     RECT  0.156 5.592 0.205 5.664 ;
     RECT  0.192 5.664 0.205 5.688 ;
     RECT  0.156 5.688 0.205 5.76 ;
     RECT  0.192 5.76 0.205 5.784 ;
     RECT  0.156 5.784 0.205 5.856 ;
     RECT  0.192 5.856 0.205 5.88 ;
     RECT  0.156 5.88 0.205 5.952 ;
     RECT  0.192 5.952 0.205 5.976 ;
     RECT  0.156 5.976 0.205 6.048 ;
     RECT  0.192 6.048 0.205 6.072 ;
     RECT  0.156 6.072 0.205 6.144 ;
     RECT  0.192 6.144 0.205 6.168 ;
     RECT  0.156 6.168 0.205 6.288 ;
     RECT  0.192 6.288 0.205 6.312 ;
     RECT  0.156 6.312 0.205 6.384 ;
     RECT  0.192 6.384 0.205 6.408 ;
     RECT  0.156 6.408 0.205 6.48 ;
     RECT  0.192 6.48 0.205 6.504 ;
     RECT  0.156 6.504 0.205 6.576 ;
     RECT  0.192 6.576 0.205 6.6 ;
     RECT  0.156 6.6 0.205 6.672 ;
     RECT  0.192 6.672 0.205 6.696 ;
     RECT  0.156 6.696 0.205 6.768 ;
     RECT  0.192 6.768 0.205 6.792 ;
     RECT  0.156 6.792 0.205 6.912 ;
     RECT  0.192 6.912 0.205 6.936 ;
     RECT  0.156 6.936 0.205 7.008 ;
     RECT  0.192 7.008 0.205 7.032 ;
     RECT  0.156 7.032 0.205 7.104 ;
     RECT  0.192 7.104 0.205 7.128 ;
     RECT  0.156 7.128 0.205 7.2 ;
     RECT  0.192 7.2 0.205 7.224 ;
     RECT  0.156 7.224 0.205 7.296 ;
     RECT  0.192 7.296 0.205 7.32 ;
     RECT  0.156 7.32 0.205 7.392 ;
     RECT  0.192 7.392 0.205 7.416 ;
     RECT  0.156 7.416 0.205 7.536 ;
     RECT  0.192 7.536 0.205 7.56 ;
     RECT  0.156 7.56 0.205 7.632 ;
     RECT  0.192 7.632 0.205 7.656 ;
     RECT  0.156 7.656 0.205 7.728 ;
     RECT  0.192 7.728 0.205 7.752 ;
     RECT  0.156 7.752 0.205 7.824 ;
     RECT  0.192 7.824 0.205 7.848 ;
     RECT  0.156 7.848 0.205 7.92 ;
     RECT  0.192 7.92 0.205 7.944 ;
     RECT  0.156 7.944 0.205 8.016 ;
     RECT  0.192 8.016 0.205 8.04 ;
     RECT  0.156 8.04 0.205 8.16 ;
     RECT  0.192 8.16 0.205 8.184 ;
     RECT  0.156 8.184 0.205 8.256 ;
     RECT  0.192 8.256 0.205 8.28 ;
     RECT  0.156 8.28 0.205 8.352 ;
     RECT  0.192 8.352 0.205 8.376 ;
     RECT  0.156 8.376 0.205 8.448 ;
     RECT  0.192 8.448 0.205 8.472 ;
     RECT  0.156 8.472 0.205 8.544 ;
     RECT  0.192 8.544 0.205 8.568 ;
     RECT  0.156 8.568 0.205 8.64 ;
     RECT  0.192 8.64 0.205 8.664 ;
     RECT  0.156 8.664 0.205 8.784 ;
     RECT  0.192 8.784 0.205 8.808 ;
     RECT  0.156 8.808 0.205 8.88 ;
     RECT  0.192 8.88 0.205 8.904 ;
     RECT  0.156 8.904 0.205 8.976 ;
     RECT  0.192 8.976 0.205 9 ;
     RECT  0.156 9 0.205 9.072 ;
     RECT  0.192 9.072 0.205 9.096 ;
     RECT  0.156 9.096 0.205 9.168 ;
     RECT  0.192 9.168 0.205 9.192 ;
     RECT  0.156 9.192 0.205 9.264 ;
     RECT  0.192 9.264 0.205 9.288 ;
     RECT  0.156 9.288 0.205 9.408 ;
     RECT  0.192 9.408 0.205 9.432 ;
     RECT  0.156 9.432 0.205 9.504 ;
     RECT  0.192 9.504 0.205 9.528 ;
     RECT  0.156 9.528 0.205 9.6 ;
     RECT  0.192 9.6 0.205 9.624 ;
     RECT  0.156 9.624 0.205 9.696 ;
     RECT  0.192 9.696 0.205 9.72 ;
     RECT  0.156 9.72 0.205 9.792 ;
     RECT  0.192 9.792 0.205 9.816 ;
     RECT  0.156 9.816 0.205 9.888 ;
     RECT  0.192 9.888 0.205 9.912 ;
     RECT  0.156 9.912 0.205 9.984 ;
     RECT  0.192 9.984 0.205 10.008 ;
     RECT  0.156 10.008 0.205 10.128 ;
     RECT  0.192 10.128 0.205 10.152 ;
     RECT  0.156 10.152 0.205 10.224 ;
     RECT  0.192 10.224 0.205 10.248 ;
     RECT  0.156 10.248 0.205 10.32 ;
     RECT  0.192 10.32 0.205 10.344 ;
     RECT  0.156 10.344 0.205 10.416 ;
     RECT  0.192 10.416 0.205 10.44 ;
     RECT  0.156 10.44 0.205 10.512 ;
     RECT  0.192 10.512 0.205 10.536 ;
     RECT  0.156 10.536 0.205 10.608 ;
     RECT  0.192 10.608 0.205 10.632 ;
     RECT  0.156 10.632 0.205 10.752 ;
     RECT  0.192 10.752 0.205 10.776 ;
     RECT  0.156 10.776 0.205 10.848 ;
     RECT  0.192 10.848 0.205 10.872 ;
     RECT  0.156 10.872 0.205 10.944 ;
     RECT  0.192 10.944 0.205 10.968 ;
     RECT  0.156 10.968 0.205 11.04 ;
     RECT  0.192 11.04 0.205 11.064 ;
     RECT  0.156 11.064 0.205 11.136 ;
     RECT  0.192 11.136 0.205 11.16 ;
     RECT  0.156 11.16 0.205 11.232 ;
     RECT  0.192 11.232 0.205 11.256 ;
     RECT  0.156 11.256 0.205 11.376 ;
     RECT  0.192 11.376 0.205 11.4 ;
     RECT  0.156 11.4 0.205 11.472 ;
     RECT  0.192 11.472 0.205 11.496 ;
     RECT  0.156 11.496 0.205 11.568 ;
     RECT  0.192 11.568 0.205 11.592 ;
     RECT  0.156 11.592 0.205 11.664 ;
     RECT  0.192 11.664 0.205 11.688 ;
     RECT  0.156 11.688 0.205 11.76 ;
     RECT  0.192 11.76 0.205 11.784 ;
     RECT  0.156 11.784 0.205 11.856 ;
     RECT  0.192 11.856 0.205 11.88 ;
     RECT  0.156 11.88 0.205 12 ;
     RECT  0.192 12 0.205 12.024 ;
     RECT  0.156 12.024 0.205 12.096 ;
     RECT  0.192 12.096 0.205 12.12 ;
     RECT  0.156 12.12 0.205 12.192 ;
     RECT  0.192 12.192 0.205 12.216 ;
     RECT  0.156 12.216 0.205 12.288 ;
     RECT  0.192 12.288 0.205 12.312 ;
     RECT  0.156 12.312 0.205 12.384 ;
     RECT  0.192 12.384 0.205 12.408 ;
     RECT  0.156 12.408 0.205 12.48 ;
     RECT  0.192 12.48 0.205 12.504 ;
     RECT  0.156 12.504 0.205 12.624 ;
     RECT  0.192 12.624 0.205 12.648 ;
     RECT  0.156 12.648 0.205 12.72 ;
     RECT  0.192 12.72 0.205 12.744 ;
     RECT  0.156 12.744 0.205 12.816 ;
     RECT  0.192 12.816 0.205 12.84 ;
     RECT  0.156 12.84 0.205 12.912 ;
     RECT  0.192 12.912 0.205 12.936 ;
     RECT  0.156 12.936 0.205 13.008 ;
     RECT  0.192 13.008 0.205 13.032 ;
     RECT  0.156 13.032 0.205 13.104 ;
     RECT  0.192 13.104 0.205 13.128 ;
     RECT  0.156 13.128 0.205 13.2 ;
     RECT  0.192 13.2 0.205 13.224 ;
     RECT  0.156 13.224 0.205 13.344 ;
     RECT  0.192 13.344 0.205 13.368 ;
     RECT  0.156 13.368 0.205 13.44 ;
     RECT  0.192 13.44 0.205 13.464 ;
     RECT  0.156 13.464 0.205 13.536 ;
     RECT  0.192 13.536 0.205 13.56 ;
     RECT  0.156 13.56 0.205 13.632 ;
     RECT  0.192 13.632 0.205 13.656 ;
     RECT  0.156 13.656 0.205 13.728 ;
     RECT  0.192 13.728 0.205 13.752 ;
     RECT  0.156 13.752 0.205 13.824 ;
     RECT  0.192 13.824 0.205 13.848 ;
     RECT  0.156 13.848 0.205 13.968 ;
     RECT  0.192 13.968 0.205 13.992 ;
     RECT  0.156 13.992 0.205 14.064 ;
     RECT  0.192 14.064 0.205 14.088 ;
     RECT  0.156 14.088 0.205 14.16 ;
     RECT  0.192 14.16 0.205 14.184 ;
     RECT  0.156 14.184 0.205 14.256 ;
     RECT  0.192 14.256 0.205 14.28 ;
     RECT  0.156 14.28 0.205 14.352 ;
     RECT  0.192 14.352 0.205 14.376 ;
     RECT  0.156 14.376 0.205 14.448 ;
     RECT  0.192 14.448 0.205 14.472 ;
     RECT  0.156 14.472 0.205 14.592 ;
     RECT  0.192 14.592 0.205 14.616 ;
     RECT  0.156 14.616 0.205 14.688 ;
     RECT  0.192 14.688 0.205 14.712 ;
     RECT  0.156 14.712 0.205 14.784 ;
     RECT  0.192 14.784 0.205 14.808 ;
     RECT  0.156 14.808 0.205 14.88 ;
     RECT  0.192 14.88 0.205 14.904 ;
     RECT  0.156 14.904 0.205 14.976 ;
     RECT  0.192 14.976 0.205 15 ;
     RECT  0.156 15 0.205 15.072 ;
     RECT  0.192 15.072 0.205 15.096 ;
     RECT  0.156 15.096 0.205 15.216 ;
     RECT  0.192 15.216 0.205 15.24 ;
     RECT  0.156 15.24 0.205 15.312 ;
     RECT  0.192 15.312 0.205 15.336 ;
     RECT  0.156 15.336 0.205 15.408 ;
     RECT  0.192 15.408 0.205 15.432 ;
     RECT  0.156 15.432 0.205 15.504 ;
     RECT  0.192 15.504 0.205 15.528 ;
     RECT  0.156 15.528 0.205 15.6 ;
     RECT  0.192 15.6 0.205 15.624 ;
     RECT  0.156 15.624 0.205 15.696 ;
     RECT  0.192 15.696 0.205 15.72 ;
     RECT  0.156 15.72 0.205 15.84 ;
     RECT  0.192 15.84 0.205 15.864 ;
     RECT  0.156 15.864 0.205 15.936 ;
     RECT  0.192 15.936 0.205 15.96 ;
     RECT  0.156 15.96 0.205 16.032 ;
     RECT  0.192 16.032 0.205 16.056 ;
     RECT  0.156 16.056 0.205 16.128 ;
     RECT  0.192 16.128 0.205 16.152 ;
     RECT  0.156 16.152 0.205 16.224 ;
     RECT  0.192 16.224 0.205 16.248 ;
     RECT  0.156 16.248 0.205 16.32 ;
     RECT  0.192 16.32 0.205 16.344 ;
     RECT  0.156 16.344 0.205 16.464 ;
     RECT  0.192 16.464 0.205 16.488 ;
     RECT  0.156 16.488 0.205 16.56 ;
     RECT  0.192 16.56 0.205 16.584 ;
     RECT  0.156 16.584 0.205 16.656 ;
     RECT  0.192 16.656 0.205 16.68 ;
     RECT  0.156 16.68 0.205 16.752 ;
     RECT  0.192 16.752 0.205 16.776 ;
     RECT  0.156 16.776 0.205 16.848 ;
     RECT  0.192 16.848 0.205 16.872 ;
     RECT  0.156 16.872 0.205 16.944 ;
     RECT  0.192 16.944 0.205 16.968 ;
     RECT  0.156 16.968 0.205 17.04 ;
     RECT  0.192 17.04 0.205 17.064 ;
     RECT  0.156 17.064 0.205 17.184 ;
     RECT  0.192 17.184 0.205 17.208 ;
     RECT  0.156 17.208 0.205 17.28 ;
     RECT  0.192 17.28 0.205 17.304 ;
     RECT  0.156 17.304 0.205 17.376 ;
     RECT  0.192 17.376 0.205 17.4 ;
     RECT  0.156 17.4 0.205 17.472 ;
     RECT  0.192 17.472 0.205 17.496 ;
     RECT  0.156 17.496 0.205 17.568 ;
     RECT  0.192 17.568 0.205 17.592 ;
     RECT  0.156 17.592 0.205 17.664 ;
     RECT  0.192 17.664 0.205 17.688 ;
     RECT  0.156 17.688 0.205 17.808 ;
     RECT  0.192 17.808 0.205 17.832 ;
     RECT  0.156 17.832 0.205 17.904 ;
     RECT  0.192 17.904 0.205 17.928 ;
     RECT  0.156 17.928 0.205 18 ;
     RECT  0.192 18 0.205 18.024 ;
     RECT  0.156 18.024 0.205 18.096 ;
     RECT  0.192 18.096 0.205 18.12 ;
     RECT  0.156 18.12 0.205 18.192 ;
     RECT  0.192 18.192 0.205 18.216 ;
     RECT  0.156 18.216 0.205 18.288 ;
     RECT  0.192 18.288 0.205 18.312 ;
     RECT  0.156 18.312 0.205 18.432 ;
     RECT  0.192 18.432 0.205 18.456 ;
     RECT  0.156 18.456 0.205 18.528 ;
     RECT  0.192 18.528 0.205 18.552 ;
     RECT  0.156 18.552 0.205 18.624 ;
     RECT  0.192 18.624 0.205 18.648 ;
     RECT  0.156 18.648 0.205 18.72 ;
     RECT  0.192 18.72 0.205 18.744 ;
     RECT  0.156 18.744 0.205 18.816 ;
     RECT  0.192 18.816 0.205 18.84 ;
     RECT  0.156 18.84 0.205 18.912 ;
     RECT  0.192 18.912 0.205 18.936 ;
     RECT  0.156 18.936 0.205 19.056 ;
     RECT  0.192 19.056 0.205 19.08 ;
     RECT  0.156 19.08 0.205 19.152 ;
     RECT  0.192 19.152 0.205 19.176 ;
     RECT  0.156 19.176 0.205 19.248 ;
     RECT  0.192 19.248 0.205 19.272 ;
     RECT  0.156 19.272 0.205 19.344 ;
     RECT  0.192 19.344 0.205 19.368 ;
     RECT  0.156 19.368 0.205 19.44 ;
     RECT  0.192 19.44 0.205 19.464 ;
     RECT  0.156 19.464 0.205 19.536 ;
     RECT  0.192 19.536 0.205 19.56 ;
     RECT  0.156 19.56 0.205 19.68 ;
     RECT  0.192 19.68 0.205 19.704 ;
     RECT  0.156 19.704 0.205 19.776 ;
     RECT  0.192 19.776 0.205 19.8 ;
     RECT  0.156 19.8 0.205 19.872 ;
     RECT  0.192 19.872 0.205 19.896 ;
     RECT  0.156 19.896 0.205 19.968 ;
     RECT  0.192 19.968 0.205 19.992 ;
     RECT  0.156 19.992 0.205 20.064 ;
     RECT  0.192 20.064 0.205 20.088 ;
     RECT  0.156 20.088 0.205 20.16 ;
     RECT  0.192 20.16 0.205 20.184 ;
     RECT  0.156 20.184 0.205 20.304 ;
     RECT  0.192 20.304 0.205 20.328 ;
     RECT  0.156 20.328 0.205 20.4 ;
     RECT  0.192 20.4 0.205 20.424 ;
     RECT  0.156 20.424 0.205 20.496 ;
     RECT  0.192 20.496 0.205 20.52 ;
     RECT  0.156 20.52 0.205 20.592 ;
     RECT  0.192 20.592 0.205 20.616 ;
     RECT  0.156 20.616 0.205 20.688 ;
     RECT  0.192 20.688 0.205 20.712 ;
     RECT  0.156 20.712 0.205 20.784 ;
     RECT  0.192 20.784 0.205 20.808 ;
     RECT  0.156 20.808 0.205 20.88 ;
     RECT  0.192 20.88 0.205 20.904 ;
     RECT  0.156 20.904 0.205 21.024 ;
     RECT  0.192 21.024 0.205 21.048 ;
     RECT  0.156 21.048 0.205 21.12 ;
     RECT  0.192 21.12 0.205 21.144 ;
     RECT  0.156 21.144 0.205 21.216 ;
     RECT  0.192 21.216 0.205 21.24 ;
     RECT  0.156 21.24 0.205 21.312 ;
     RECT  0.192 21.312 0.205 21.336 ;
     RECT  0.156 21.336 0.205 21.408 ;
     RECT  0.192 21.408 0.205 21.432 ;
     RECT  0.156 21.432 0.205 21.504 ;
     RECT  0.192 21.504 0.205 21.528 ;
     RECT  0.156 21.528 0.205 21.648 ;
     RECT  0.192 21.648 0.205 21.672 ;
     RECT  0.156 21.672 0.205 21.744 ;
     RECT  0.192 21.744 0.205 21.768 ;
     RECT  0.156 21.768 0.205 21.84 ;
     RECT  0.192 21.84 0.205 21.864 ;
     RECT  0.156 21.864 0.205 21.936 ;
     RECT  0.192 21.936 0.205 21.96 ;
     RECT  0.156 21.96 0.205 22.032 ;
     RECT  0.192 22.032 0.205 22.056 ;
     RECT  0.156 22.056 0.205 22.128 ;
     RECT  0.192 22.128 0.205 22.152 ;
     RECT  0.156 22.152 0.205 22.272 ;
     RECT  0.192 22.272 0.205 22.296 ;
     RECT  0.156 22.296 0.205 22.368 ;
     RECT  0.192 22.368 0.205 22.392 ;
     RECT  0.156 22.392 0.205 22.464 ;
     RECT  0.192 22.464 0.205 22.488 ;
     RECT  0.156 22.488 0.205 22.56 ;
     RECT  0.192 22.56 0.205 22.584 ;
     RECT  0.156 22.584 0.205 22.656 ;
     RECT  0.192 22.656 0.205 22.68 ;
     RECT  0.156 22.68 0.205 22.752 ;
     RECT  0.192 22.752 0.205 22.776 ;
     RECT  0.156 22.776 0.205 22.896 ;
     RECT  0.192 22.896 0.205 22.92 ;
     RECT  0.156 22.92 0.205 22.992 ;
     RECT  0.192 22.992 0.205 23.016 ;
     RECT  0.156 23.016 0.205 23.088 ;
     RECT  0.192 23.088 0.205 23.112 ;
     RECT  0.156 23.112 0.205 23.184 ;
     RECT  0.192 23.184 0.205 23.208 ;
     RECT  0.156 23.208 0.205 23.28 ;
     RECT  0.192 23.28 0.205 23.304 ;
     RECT  0.156 23.304 0.205 23.376 ;
     RECT  0.192 23.376 0.205 23.4 ;
     RECT  0.156 23.4 0.205 23.52 ;
     RECT  0.192 23.52 0.205 23.544 ;
     RECT  0.156 23.544 0.205 23.616 ;
     RECT  0.192 23.616 0.205 23.64 ;
     RECT  0.156 23.64 0.205 23.712 ;
     RECT  0.192 23.712 0.205 23.736 ;
     RECT  0.156 23.736 0.205 23.808 ;
     RECT  0.192 23.808 0.205 23.832 ;
     RECT  0.156 23.832 0.205 23.904 ;
     RECT  0.192 23.904 0.205 23.928 ;
     RECT  0.156 23.928 0.205 24 ;
     RECT  0.192 24 0.205 24.024 ;
     RECT  0.156 24.024 0.205 24.096 ;
     RECT  0.192 24.096 0.205 24.12 ;
     RECT  0.156 24.12 0.205 24.24 ;
     RECT  0.192 24.24 0.205 24.264 ;
     RECT  0.156 24.264 0.205 24.336 ;
     RECT  0.192 24.336 0.205 24.36 ;
     RECT  0.156 24.36 0.205 24.432 ;
     RECT  0.192 24.432 0.205 24.456 ;
     RECT  0.156 24.456 0.205 24.528 ;
     RECT  0.192 24.528 0.205 24.552 ;
     RECT  0.156 24.552 0.205 24.624 ;
     RECT  0.192 24.624 0.205 24.648 ;
     RECT  0.156 24.648 0.205 24.72 ;
     RECT  0.192 24.72 0.205 24.744 ;
     RECT  0.156 24.744 0.205 24.864 ;
     RECT  0.192 24.864 0.205 24.888 ;
     RECT  0.156 24.888 0.205 24.96 ;
     RECT  0.192 24.96 0.205 24.984 ;
     RECT  0.156 24.984 0.205 25.056 ;
     RECT  0.192 25.056 0.205 25.08 ;
     RECT  0.156 25.08 0.205 25.152 ;
     RECT  0.192 25.152 0.205 25.176 ;
     RECT  0.156 25.176 0.205 25.248 ;
     RECT  0.192 25.248 0.205 25.272 ;
     RECT  0.156 25.272 0.205 25.344 ;
     RECT  0.192 25.344 0.205 25.368 ;
     RECT  0.156 25.368 0.205 25.488 ;
     RECT  0.192 25.488 0.205 25.512 ;
     RECT  0.156 25.512 0.205 25.584 ;
     RECT  0.192 25.584 0.205 25.608 ;
     RECT  0.156 25.608 0.205 25.68 ;
     RECT  0.192 25.68 0.205 25.704 ;
     RECT  0.156 25.704 0.205 25.776 ;
     RECT  0.192 25.776 0.205 25.8 ;
     RECT  0.156 25.8 0.205 25.872 ;
     RECT  0.192 25.872 0.205 25.896 ;
     RECT  0.156 25.896 0.205 25.968 ;
     RECT  0.192 25.968 0.205 25.992 ;
     RECT  0.156 25.992 0.205 26.112 ;
     RECT  0.192 26.112 0.205 26.136 ;
     RECT  0.156 26.136 0.205 26.208 ;
     RECT  0.192 26.208 0.205 26.232 ;
     RECT  0.156 26.232 0.205 26.304 ;
     RECT  0.192 26.304 0.205 26.328 ;
     RECT  0.156 26.328 0.205 26.4 ;
     RECT  0.192 26.4 0.205 26.424 ;
     RECT  0.156 26.424 0.205 26.496 ;
     RECT  0.192 26.496 0.205 26.52 ;
     RECT  0.156 26.52 0.205 26.592 ;
     RECT  0.192 26.592 0.205 26.616 ;
     RECT  0.156 26.616 0.205 26.736 ;
     RECT  0.192 26.736 0.205 26.76 ;
     RECT  0.156 26.76 0.205 26.832 ;
     RECT  0.192 26.832 0.205 26.856 ;
     RECT  0.156 26.856 0.205 26.928 ;
     RECT  0.192 26.928 0.205 26.952 ;
     RECT  0.156 26.952 0.205 27.024 ;
     RECT  0.192 27.024 0.205 27.048 ;
     RECT  0.156 27.048 0.205 27.12 ;
     RECT  0.192 27.12 0.205 27.144 ;
     RECT  0.156 27.144 0.205 27.216 ;
     RECT  0.192 27.216 0.205 27.24 ;
     RECT  0.156 27.24 0.205 27.36 ;
     RECT  0.192 27.36 0.205 27.384 ;
     RECT  0.156 27.384 0.205 27.456 ;
     RECT  0.192 27.456 0.205 27.48 ;
     RECT  0.156 27.48 0.205 27.552 ;
     RECT  0.192 27.552 0.205 27.576 ;
     RECT  0.156 27.576 0.205 27.648 ;
     RECT  0.192 27.648 0.205 27.672 ;
     RECT  0.156 27.672 0.205 27.744 ;
     RECT  0.192 27.744 0.205 27.768 ;
     RECT  0.156 27.768 0.205 27.84 ;
     RECT  0.192 27.84 0.205 27.864 ;
     RECT  0.156 27.864 0.205 27.936 ;
     RECT  0.192 27.936 0.205 27.96 ;
     RECT  0.156 27.96 0.205 28.08 ;
     RECT  0.192 28.08 0.205 28.104 ;
     RECT  0.156 28.104 0.205 28.176 ;
     RECT  0.192 28.176 0.205 28.2 ;
     RECT  0.156 28.2 0.205 28.272 ;
     RECT  0.192 28.272 0.205 28.296 ;
     RECT  0.156 28.296 0.205 28.368 ;
     RECT  0.192 28.368 0.205 28.392 ;
     RECT  0.156 28.392 0.205 28.464 ;
     RECT  0.192 28.464 0.205 28.488 ;
     RECT  0.156 28.488 0.205 28.56 ;
     RECT  0.192 28.56 0.205 28.584 ;
     RECT  0.156 28.584 0.205 28.704 ;
     RECT  0.192 28.704 0.205 28.728 ;
     RECT  0.156 28.728 0.205 28.8 ;
     RECT  0.192 28.8 0.205 28.824 ;
     RECT  0.156 28.824 0.205 28.896 ;
     RECT  0.192 28.896 0.205 28.92 ;
     RECT  0.156 28.92 0.205 28.992 ;
     RECT  0.192 28.992 0.205 29.016 ;
     RECT  0.156 29.016 0.205 29.088 ;
     RECT  0.192 29.088 0.205 29.112 ;
     RECT  0.156 29.112 0.205 29.184 ;
     RECT  0.192 29.184 0.205 29.208 ;
     RECT  0.156 29.208 0.205 29.328 ;
     RECT  0.192 29.328 0.205 29.352 ;
     RECT  0.156 29.352 0.205 29.424 ;
     RECT  0.192 29.424 0.205 29.448 ;
     RECT  0.156 29.448 0.205 29.52 ;
     RECT  0.192 29.52 0.205 29.544 ;
     RECT  0.156 29.544 0.205 29.616 ;
     RECT  0.192 29.616 0.205 29.64 ;
     RECT  0.156 29.64 0.205 29.712 ;
     RECT  0.192 29.712 0.205 29.736 ;
     RECT  0.156 29.736 0.205 29.808 ;
     RECT  0.192 29.808 0.205 29.832 ;
     RECT  0.156 29.832 0.205 29.952 ;
     RECT  0.192 29.952 0.205 29.976 ;
     RECT  0.156 29.976 0.205 30.048 ;
     RECT  0.192 30.048 0.205 30.072 ;
     RECT  0.156 30.072 0.205 30.144 ;
     RECT  0.192 30.144 0.205 30.168 ;
     RECT  0.156 30.168 0.205 30.24 ;
     RECT  0.192 30.24 0.205 30.264 ;
     RECT  0.156 30.264 0.205 30.336 ;
     RECT  0.192 30.336 0.205 30.36 ;
     RECT  0.156 30.36 0.205 30.432 ;
     RECT  0.192 30.432 0.205 30.456 ;
     RECT  0.156 30.456 0.205 30.576 ;
     RECT  0.192 30.576 0.205 30.6 ;
     RECT  0.156 30.6 0.205 30.672 ;
     RECT  0.192 30.672 0.205 30.696 ;
     RECT  0.156 30.696 0.205 30.768 ;
     RECT  0.192 30.768 0.205 30.792 ;
     RECT  0.156 30.792 0.205 30.864 ;
     RECT  0.192 30.864 0.205 30.888 ;
     RECT  0.156 30.888 0.205 30.96 ;
     RECT  0.192 30.96 0.205 30.984 ;
     RECT  0.156 30.984 0.205 31.056 ;
     RECT  0.192 31.056 0.205 31.08 ;
     RECT  0.156 31.08 0.205 31.2 ;
     RECT  0.192 31.2 0.205 31.224 ;
     RECT  0.156 31.224 0.205 31.296 ;
     RECT  0.192 31.296 0.205 31.32 ;
     RECT  0.156 31.32 0.205 31.392 ;
     RECT  0.192 31.392 0.205 31.416 ;
     RECT  0.156 31.416 0.205 31.488 ;
     RECT  0.192 31.488 0.205 31.512 ;
     RECT  0.156 31.512 0.205 31.584 ;
     RECT  0.192 31.584 0.205 31.608 ;
     RECT  0.156 31.608 0.205 31.68 ;
     RECT  0.192 31.68 0.205 31.704 ;
     RECT  0.156 31.704 0.205 31.776 ;
     RECT  0.192 31.776 0.205 31.8 ;
     RECT  0.156 31.8 0.205 31.92 ;
     RECT  0.192 31.92 0.205 31.944 ;
     RECT  0.156 31.944 0.205 32.016 ;
     RECT  0.192 32.016 0.205 32.04 ;
     RECT  0.156 32.04 0.205 32.112 ;
     RECT  0.192 32.112 0.205 32.136 ;
     RECT  0.156 32.136 0.205 32.208 ;
     RECT  0.192 32.208 0.205 32.232 ;
     RECT  0.156 32.232 0.205 32.304 ;
     RECT  0.192 32.304 0.205 32.328 ;
     RECT  0.156 32.328 0.205 32.4 ;
     RECT  0.192 32.4 0.205 32.424 ;
     RECT  0.156 32.424 0.205 32.544 ;
     RECT  0.192 32.544 0.205 32.568 ;
     RECT  0.156 32.568 0.205 32.64 ;
     RECT  0.192 32.64 0.205 32.664 ;
     RECT  0.156 32.664 0.205 32.736 ;
     RECT  0.192 32.736 0.205 32.76 ;
     RECT  0.156 32.76 0.205 32.832 ;
     RECT  0.192 32.832 0.205 32.856 ;
     RECT  0.156 32.856 0.205 32.928 ;
     RECT  0.192 32.928 0.205 32.952 ;
     RECT  0.156 32.952 0.205 33.024 ;
     RECT  0.192 33.024 0.205 33.048 ;
     RECT  0.156 33.048 0.205 33.168 ;
     RECT  0.192 33.168 0.205 33.192 ;
     RECT  0.156 33.192 0.205 33.264 ;
     RECT  0.192 33.264 0.205 33.288 ;
     RECT  0.156 33.288 0.205 33.36 ;
     RECT  0.192 33.36 0.205 33.384 ;
     RECT  0.156 33.384 0.205 33.456 ;
     RECT  0.192 33.456 0.205 33.48 ;
     RECT  0.156 33.48 0.205 33.552 ;
     RECT  0.192 33.552 0.205 33.576 ;
     RECT  0.156 33.576 0.205 33.648 ;
     RECT  0.192 33.648 0.205 33.672 ;
     RECT  0.156 33.672 0.205 33.792 ;
     RECT  0.192 33.792 0.205 33.816 ;
     RECT  0.156 33.816 0.205 33.888 ;
     RECT  0.192 33.888 0.205 33.912 ;
     RECT  0.156 33.912 0.205 33.984 ;
     RECT  0.192 33.984 0.205 34.008 ;
     RECT  0.156 34.008 0.205 34.08 ;
     RECT  0.192 34.08 0.205 34.104 ;
     RECT  0.156 34.104 0.205 34.176 ;
     RECT  0.192 34.176 0.205 34.2 ;
     RECT  0.156 34.2 0.205 34.272 ;
     RECT  0.192 34.272 0.205 34.296 ;
     RECT  0.156 34.296 0.205 34.416 ;
     RECT  0.192 34.416 0.205 34.44 ;
     RECT  0.156 34.44 0.205 34.512 ;
     RECT  0.192 34.512 0.205 34.536 ;
     RECT  0.156 34.536 0.205 34.608 ;
     RECT  0.192 34.608 0.205 34.632 ;
     RECT  0.156 34.632 0.205 34.704 ;
     RECT  0.192 34.704 0.205 34.728 ;
     RECT  0.156 34.728 0.205 34.8 ;
     RECT  0.192 34.8 0.205 34.824 ;
     RECT  0.156 34.824 0.205 34.896 ;
     RECT  0.192 34.896 0.205 34.92 ;
     RECT  0.156 34.92 0.205 34.992 ;
     RECT  0.192 34.992 0.205 35.016 ;
     RECT  0.156 35.016 0.205 35.136 ;
     RECT  0.192 35.136 0.205 35.16 ;
     RECT  0.156 35.16 0.205 35.232 ;
     RECT  0.192 35.232 0.205 35.256 ;
     RECT  0.156 35.256 0.205 35.328 ;
     RECT  0.192 35.328 0.205 35.352 ;
     RECT  0.156 35.352 0.205 35.424 ;
     RECT  0.192 35.424 0.205 35.448 ;
     RECT  0.156 35.448 0.205 35.52 ;
     RECT  0.192 35.52 0.205 35.544 ;
     RECT  0.156 35.544 0.205 35.616 ;
     RECT  0.192 35.616 0.205 35.64 ;
     RECT  0.156 35.64 0.205 35.76 ;
     RECT  0.192 35.76 0.205 35.784 ;
     RECT  0.156 35.784 0.205 35.856 ;
     RECT  0.192 35.856 0.205 35.88 ;
     RECT  0.156 35.88 0.205 35.952 ;
     RECT  0.192 35.952 0.205 35.976 ;
     RECT  0.156 35.976 0.205 36.048 ;
     RECT  0.192 36.048 0.205 36.072 ;
     RECT  0.156 36.072 0.205 36.144 ;
     RECT  0.192 36.144 0.205 36.168 ;
     RECT  0.156 36.168 0.205 36.24 ;
     RECT  0.192 36.24 0.205 36.264 ;
     RECT  0.156 36.264 0.205 36.384 ;
     RECT  0.192 36.384 0.205 36.408 ;
     RECT  0.156 36.408 0.205 36.48 ;
     RECT  0.192 36.48 0.205 36.504 ;
     RECT  0.156 36.504 0.205 36.576 ;
     RECT  0.192 36.576 0.205 36.6 ;
     RECT  0.156 36.6 0.205 36.672 ;
     RECT  0.192 36.672 0.205 36.696 ;
     RECT  0.156 36.696 0.205 36.768 ;
     RECT  0.192 36.768 0.205 36.792 ;
     RECT  0.156 36.792 0.205 36.864 ;
     RECT  0.192 36.864 0.205 36.888 ;
     RECT  0.156 36.888 0.205 37.008 ;
     RECT  0.192 37.008 0.205 37.032 ;
     RECT  0.156 37.032 0.205 37.104 ;
     RECT  0.192 37.104 0.205 37.128 ;
     RECT  0.156 37.128 0.205 37.2 ;
     RECT  0.192 37.2 0.205 37.224 ;
     RECT  0.156 37.224 0.205 37.296 ;
     RECT  0.192 37.296 0.205 37.32 ;
     RECT  0.156 37.32 0.205 37.392 ;
     RECT  0.192 37.392 0.205 37.416 ;
     RECT  0.156 37.416 0.205 37.488 ;
     RECT  0.192 37.488 0.205 37.512 ;
     RECT  0.156 37.512 0.205 37.632 ;
     RECT  0.192 37.632 0.205 37.656 ;
     RECT  0.156 37.656 0.205 37.728 ;
     RECT  0.192 37.728 0.205 37.752 ;
     RECT  0.156 37.752 0.205 37.824 ;
     RECT  0.192 37.824 0.205 37.848 ;
     RECT  0.156 37.848 0.205 37.92 ;
     RECT  0.192 37.92 0.205 37.944 ;
     RECT  0.156 37.944 0.205 38.016 ;
     RECT  0.192 38.016 0.205 38.04 ;
     RECT  0.156 38.04 0.205 38.112 ;
     RECT  0.192 38.112 0.205 38.136 ;
     RECT  0.156 38.136 0.205 38.256 ;
     RECT  0.192 38.256 0.205 38.28 ;
     RECT  0.156 38.28 0.205 38.352 ;
     RECT  0.192 38.352 0.205 38.376 ;
     RECT  0.156 38.376 0.205 38.448 ;
     RECT  0.192 38.448 0.205 38.472 ;
     RECT  0.156 38.472 0.205 38.544 ;
     RECT  0.192 38.544 0.205 38.568 ;
     RECT  0.156 38.568 0.205 38.64 ;
     RECT  0.192 38.64 0.205 38.664 ;
     RECT  0.156 38.664 0.205 38.736 ;
     RECT  0.192 38.736 0.205 38.76 ;
     RECT  0.156 38.76 0.205 38.832 ;
     RECT  0.192 38.832 0.205 38.856 ;
     RECT  0.156 38.856 0.205 38.976 ;
     RECT  0.192 38.976 0.205 39 ;
     RECT  0.156 39 0.205 39.072 ;
     RECT  0.192 39.072 0.205 39.096 ;
     RECT  0.156 39.096 0.205 39.168 ;
     RECT  0.192 39.168 0.205 39.192 ;
     RECT  0.156 39.192 0.205 39.264 ;
     RECT  0.192 39.264 0.205 39.288 ;
     RECT  0.156 39.288 0.205 39.36 ;
     RECT  0.192 39.36 0.205 39.384 ;
     RECT  0.156 39.384 0.205 39.456 ;
     RECT  0.192 39.456 0.205 39.48 ;
     RECT  0.156 39.48 0.205 39.6 ;
     RECT  0.192 39.6 0.205 39.624 ;
     RECT  0.156 39.624 0.205 39.696 ;
     RECT  0.192 39.696 0.205 39.72 ;
     RECT  0.156 39.72 0.205 39.792 ;
     RECT  0.192 39.792 0.205 39.816 ;
     RECT  0.156 39.816 0.205 39.888 ;
     RECT  0.192 39.888 0.205 39.912 ;
     RECT  0.156 39.912 0.205 39.984 ;
     RECT  0.192 39.984 0.205 40.008 ;
     RECT  0.156 40.008 0.205 40.08 ;
     RECT  0.192 40.08 0.205 40.104 ;
     RECT  0.156 40.104 0.205 40.224 ;
     RECT  0.192 40.224 0.205 40.248 ;
     RECT  0.156 40.248 0.205 40.32 ;
     RECT  0.192 40.32 0.205 40.344 ;
     RECT  0.156 40.344 0.205 40.416 ;
     RECT  0.192 40.416 0.205 40.44 ;
     RECT  0.156 40.44 0.205 40.512 ;
     RECT  0.192 40.512 0.205 40.536 ;
     RECT  0.156 40.536 0.205 40.608 ;
     RECT  0.192 40.608 0.205 40.632 ;
     RECT  0.156 40.632 0.205 40.704 ;
     RECT  0.192 40.704 0.205 40.728 ;
     RECT  0.156 40.728 0.205 40.848 ;
     RECT  0.192 40.848 0.205 40.872 ;
     RECT  0.156 40.872 0.205 40.944 ;
     RECT  0.192 40.944 0.205 40.968 ;
     RECT  0.156 40.968 0.205 41.04 ;
     RECT  0.192 41.04 0.205 41.064 ;
     RECT  0.156 41.064 0.205 41.136 ;
     RECT  0.192 41.136 0.205 41.16 ;
     RECT  0.156 41.16 0.205 41.232 ;
     RECT  0.192 41.232 0.205 41.256 ;
     RECT  0.156 41.256 0.205 41.328 ;
     RECT  0.192 41.328 0.205 41.352 ;
     RECT  0.156 41.352 0.205 41.472 ;
     RECT  0.192 41.472 0.205 41.496 ;
     RECT  0.156 41.496 0.205 41.568 ;
     RECT  0.192 41.568 0.205 41.592 ;
     RECT  0.156 41.592 0.205 41.664 ;
     RECT  0.192 41.664 0.205 41.688 ;
     RECT  0.156 41.688 0.205 41.76 ;
     RECT  0.192 41.76 0.205 41.784 ;
     RECT  0.156 41.784 0.205 41.856 ;
     RECT  0.192 41.856 0.205 41.88 ;
     RECT  0.156 41.88 0.205 41.952 ;
     RECT  0.192 41.952 0.205 41.976 ;
     RECT  0.156 41.976 0.205 42.096 ;
     RECT  0.192 42.096 0.205 42.12 ;
     RECT  0.156 42.12 0.205 42.192 ;
     RECT  0.192 42.192 0.205 42.216 ;
     RECT  0.156 42.216 0.205 42.288 ;
     RECT  0.192 42.288 0.205 42.312 ;
     RECT  0.156 42.312 0.205 42.384 ;
     RECT  0.192 42.384 0.205 42.408 ;
     RECT  0.156 42.408 0.205 42.48 ;
     RECT  0.192 42.48 0.205 42.504 ;
     RECT  0.156 42.504 0.205 42.576 ;
     RECT  0.192 42.576 0.205 42.6 ;
     RECT  0.156 42.6 0.205 42.672 ;
     RECT  0.192 42.672 0.205 42.696 ;
     RECT  0.156 42.696 0.205 42.816 ;
     RECT  0.192 42.816 0.205 42.84 ;
     RECT  0.156 42.84 0.205 42.912 ;
     RECT  0.192 42.912 0.205 42.936 ;
     RECT  0.156 42.936 0.205 43.008 ;
     RECT  0.192 43.008 0.205 43.032 ;
     RECT  0.156 43.032 0.205 43.104 ;
     RECT  0.192 43.104 0.205 43.128 ;
     RECT  0.156 43.128 0.205 43.2 ;
     RECT  0.192 43.2 0.205 43.224 ;
     RECT  0.156 43.224 0.205 43.296 ;
     RECT  0.192 43.296 0.205 43.32 ;
     RECT  0.156 43.32 0.205 43.44 ;
     RECT  0.192 43.44 0.205 43.464 ;
     RECT  0.156 43.464 0.205 43.536 ;
     RECT  0.192 43.536 0.205 43.56 ;
     RECT  0.156 43.56 0.205 43.632 ;
     RECT  0.192 43.632 0.205 43.656 ;
     RECT  0.156 43.656 0.205 43.728 ;
     RECT  0.192 43.728 0.205 43.752 ;
     RECT  0.156 43.752 0.205 43.824 ;
     RECT  0.192 43.824 0.205 43.848 ;
     RECT  0.156 43.848 0.205 43.92 ;
     RECT  0.192 43.92 0.205 43.944 ;
     RECT  0.156 43.944 0.205 44.064 ;
     RECT  0.192 44.064 0.205 44.088 ;
     RECT  0.156 44.088 0.205 44.16 ;
     RECT  0.192 44.16 0.205 44.184 ;
     RECT  0.156 44.184 0.205 44.256 ;
     RECT  0.192 44.256 0.205 44.28 ;
     RECT  0.156 44.28 0.205 44.352 ;
     RECT  0.192 44.352 0.205 44.376 ;
     RECT  0.156 44.376 0.205 44.448 ;
     RECT  0.192 44.448 0.205 44.472 ;
     RECT  0.156 44.472 0.205 44.544 ;
     RECT  0.192 44.544 0.205 44.568 ;
     RECT  0.156 44.568 0.205 44.688 ;
     RECT  0.192 44.688 0.205 44.712 ;
     RECT  0.156 44.712 0.205 44.784 ;
     RECT  0.192 44.784 0.205 44.808 ;
     RECT  0.156 44.808 0.205 44.88 ;
     RECT  0.192 44.88 0.205 44.904 ;
     RECT  0.156 44.904 0.205 44.976 ;
     RECT  0.192 44.976 0.205 45 ;
     RECT  0.156 45 0.205 45.072 ;
     RECT  0.192 45.072 0.205 45.096 ;
     RECT  0.156 45.096 0.205 45.168 ;
     RECT  0.192 45.168 0.205 45.192 ;
     RECT  0.156 45.192 0.205 45.312 ;
     RECT  0.192 45.312 0.205 45.336 ;
     RECT  0.156 45.336 0.205 45.408 ;
     RECT  0.192 45.408 0.205 45.432 ;
     RECT  0.156 45.432 0.205 45.504 ;
     RECT  0.192 45.504 0.205 45.528 ;
     RECT  0.156 45.528 0.205 45.6 ;
     RECT  0.192 45.6 0.205 45.624 ;
     RECT  0.156 45.624 0.205 45.696 ;
     RECT  0.192 45.696 0.205 45.72 ;
     RECT  0.156 45.72 0.205 45.792 ;
     RECT  0.192 45.792 0.205 45.816 ;
     RECT  0.156 45.816 0.205 45.936 ;
     RECT  0.192 45.936 0.205 45.96 ;
     RECT  0.156 45.96 0.205 46.032 ;
     RECT  0.192 46.032 0.205 46.056 ;
     RECT  0.156 46.056 0.205 46.128 ;
     RECT  0.192 46.128 0.205 46.152 ;
     RECT  0.156 46.152 0.205 46.224 ;
     RECT  0.192 46.224 0.205 46.248 ;
     RECT  0.156 46.248 0.205 46.32 ;
     RECT  0.192 46.32 0.205 46.344 ;
     RECT  0.156 46.344 0.205 46.416 ;
     RECT  0.192 46.416 0.205 46.44 ;
     RECT  0.156 46.44 0.205 46.512 ;
     RECT  0.192 46.512 0.205 46.536 ;
     RECT  0.156 46.536 0.205 46.656 ;
     RECT  0.192 46.656 0.205 46.68 ;
     RECT  0.156 46.68 0.205 46.752 ;
     RECT  0.192 46.752 0.205 46.776 ;
     RECT  0.156 46.776 0.205 46.848 ;
     RECT  0.192 46.848 0.205 46.872 ;
     RECT  0.156 46.872 0.205 46.944 ;
     RECT  0.192 46.944 0.205 46.968 ;
     RECT  0.156 46.968 0.205 47.04 ;
     RECT  0.192 47.04 0.205 47.064 ;
     RECT  0.156 47.064 0.205 47.136 ;
     RECT  0.192 47.136 0.205 47.16 ;
     RECT  0.156 47.16 0.205 47.28 ;
     RECT  0.192 47.28 0.205 47.304 ;
     RECT  0.156 47.304 0.205 47.376 ;
     RECT  0.192 47.376 0.205 47.4 ;
     RECT  0.156 47.4 0.205 47.472 ;
     RECT  0.192 47.472 0.205 47.496 ;
     RECT  0.156 47.496 0.205 47.568 ;
     RECT  0.192 47.568 0.205 47.592 ;
     RECT  0.156 47.592 0.205 47.664 ;
     RECT  0.192 47.664 0.205 47.688 ;
     RECT  0.156 47.688 0.205 47.76 ;
     RECT  0.192 47.76 0.205 47.784 ;
     RECT  0.156 47.784 0.205 47.904 ;
     RECT  0.192 47.904 0.205 47.928 ;
     RECT  0.156 47.928 0.205 48 ;
     RECT  0.192 48 0.205 48.024 ;
     RECT  0.156 48.024 0.205 48.096 ;
     RECT  0.192 48.096 0.205 48.12 ;
     RECT  0.156 48.12 0.205 48.192 ;
     RECT  0.192 48.192 0.205 48.216 ;
     RECT  0.156 48.216 0.205 48.288 ;
     RECT  0.192 48.288 0.205 48.312 ;
     RECT  0.156 48.312 0.205 48.384 ;
     RECT  0.192 48.384 0.205 48.408 ;
     RECT  0.156 48.408 0.205 48.528 ;
     RECT  0.192 48.528 0.205 48.552 ;
     RECT  0.156 48.552 0.205 48.624 ;
     RECT  0.192 48.624 0.205 48.648 ;
     RECT  0.156 48.648 0.205 48.72 ;
     RECT  0.192 48.72 0.205 48.744 ;
     RECT  0.156 48.744 0.205 48.816 ;
     RECT  0.192 48.816 0.205 48.84 ;
     RECT  0.156 48.84 0.205 48.912 ;
     RECT  0.192 48.912 0.205 48.936 ;
     RECT  0.156 48.936 0.205 49.008 ;
     RECT  0.192 49.008 0.205 49.032 ;
     RECT  0.156 49.032 0.205 49.152 ;
     RECT  0.192 49.152 0.205 49.176 ;
     RECT  0.156 49.176 0.205 49.248 ;
     RECT  0.192 49.248 0.205 49.272 ;
     RECT  0.156 49.272 0.205 49.344 ;
     RECT  0.192 49.344 0.205 49.368 ;
     RECT  0.156 49.368 0.205 49.44 ;
     RECT  0.192 49.44 0.205 49.464 ;
     RECT  0.156 49.464 0.205 49.536 ;
     RECT  0.192 49.536 0.205 49.56 ;
     RECT  0.156 49.56 0.205 49.632 ;
     RECT  0.192 49.632 0.205 49.656 ;
     RECT  0.156 49.656 0.205 49.728 ;
     RECT  0.192 49.728 0.205 49.752 ;
     RECT  0.156 49.752 0.205 49.872 ;
     RECT  0.192 49.872 0.205 49.896 ;
     RECT  0.156 49.896 0.205 49.968 ;
     RECT  0.192 49.968 0.205 49.992 ;
     RECT  0.156 49.992 0.205 50.064 ;
     RECT  0.192 50.064 0.205 50.088 ;
     RECT  0.156 50.088 0.205 50.16 ;
     RECT  0.192 50.16 0.205 50.184 ;
     RECT  0.156 50.184 0.205 50.256 ;
     RECT  0.192 50.256 0.205 50.28 ;
     RECT  0.156 50.28 0.205 50.352 ;
     RECT  0.192 50.352 0.205 50.376 ;
     RECT  0.156 50.376 0.205 50.496 ;
     RECT  0.192 50.496 0.205 50.52 ;
     RECT  0.156 50.52 0.205 50.592 ;
     RECT  0.192 50.592 0.205 50.616 ;
     RECT  0.156 50.616 0.205 50.688 ;
     RECT  0.192 50.688 0.205 50.712 ;
     RECT  0.156 50.712 0.205 50.784 ;
     RECT  0.192 50.784 0.205 50.808 ;
     RECT  0.156 50.808 0.205 50.88 ;
     RECT  0.192 50.88 0.205 50.904 ;
     RECT  0.156 50.904 0.205 50.976 ;
     RECT  0.192 50.976 0.205 51 ;
     RECT  0.156 51 0.205 51.12 ;
     RECT  0.192 51.12 0.205 51.144 ;
     RECT  0.156 51.144 0.205 51.216 ;
     RECT  0.192 51.216 0.205 51.24 ;
     RECT  0.156 51.24 0.205 51.312 ;
     RECT  0.192 51.312 0.205 51.336 ;
     RECT  0.156 51.336 0.205 51.408 ;
     RECT  0.192 51.408 0.205 51.432 ;
     RECT  0.156 51.432 0.205 51.504 ;
     RECT  0.192 51.504 0.205 51.528 ;
     RECT  0.156 51.528 0.205 51.6 ;
     RECT  0.192 51.6 0.205 51.624 ;
     RECT  0.156 51.624 0.205 51.744 ;
     RECT  0.192 51.744 0.205 51.768 ;
     RECT  0.156 51.768 0.205 51.84 ;
     RECT  0.192 51.84 0.205 51.864 ;
     RECT  0.156 51.864 0.205 51.936 ;
     RECT  0.192 51.936 0.205 51.96 ;
     RECT  0.156 51.96 0.205 52.032 ;
     RECT  0.192 52.032 0.205 52.056 ;
     RECT  0.156 52.056 0.205 52.128 ;
     RECT  0.192 52.128 0.205 52.152 ;
     RECT  0.156 52.152 0.205 52.224 ;
     RECT  0.192 52.224 0.205 52.248 ;
     RECT  0.156 52.248 0.205 52.368 ;
     RECT  0.192 52.368 0.205 52.392 ;
     RECT  0.156 52.392 0.205 52.464 ;
     RECT  0.192 52.464 0.205 52.488 ;
     RECT  0.156 52.488 0.205 52.56 ;
     RECT  0.192 52.56 0.205 52.584 ;
     RECT  0.156 52.584 0.205 52.656 ;
     RECT  0.192 52.656 0.205 52.68 ;
     RECT  0.156 52.68 0.205 52.752 ;
     RECT  0.192 52.752 0.205 52.776 ;
     RECT  0.156 52.776 0.205 52.848 ;
     RECT  0.192 52.848 0.205 52.872 ;
     RECT  0.156 52.872 0.205 52.992 ;
     RECT  0.192 52.992 0.205 53.016 ;
     RECT  0.156 53.016 0.205 53.088 ;
     RECT  0.192 53.088 0.205 53.112 ;
     RECT  0.156 53.112 0.205 53.184 ;
     RECT  0.192 53.184 0.205 53.208 ;
     RECT  0.156 53.208 0.205 53.28 ;
     RECT  0.192 53.28 0.205 53.304 ;
     RECT  0.156 53.304 0.205 53.376 ;
     RECT  0.192 53.376 0.205 53.4 ;
     RECT  0.156 53.4 0.205 53.472 ;
     RECT  0.192 53.472 0.205 53.496 ;
     RECT  0.156 53.496 0.205 53.568 ;
     RECT  0.192 53.568 0.205 53.592 ;
     RECT  0.156 53.592 0.205 53.712 ;
     RECT  0.192 53.712 0.205 53.736 ;
     RECT  0.156 53.736 0.205 53.808 ;
     RECT  0.192 53.808 0.205 53.832 ;
     RECT  0.156 53.832 0.205 53.904 ;
     RECT  0.192 53.904 0.205 53.928 ;
     RECT  0.156 53.928 0.205 54 ;
     RECT  0.192 54 0.205 54.024 ;
     RECT  0.156 54.024 0.205 54.096 ;
     RECT  0.192 54.096 0.205 54.12 ;
     RECT  0.156 54.12 0.205 54.192 ;
     RECT  0.192 54.192 0.205 54.216 ;
     RECT  0.156 54.216 0.205 54.336 ;
     RECT  0.192 54.336 0.205 54.36 ;
     RECT  0.156 54.36 0.205 54.432 ;
     RECT  0.192 54.432 0.205 54.456 ;
     RECT  0.156 54.456 0.205 54.528 ;
     RECT  0.192 54.528 0.205 54.552 ;
     RECT  0.156 54.552 0.205 54.624 ;
     RECT  0.192 54.624 0.205 54.648 ;
     RECT  0.156 54.648 0.205 54.72 ;
     RECT  0.192 54.72 0.205 54.744 ;
     RECT  0.156 54.744 0.205 54.816 ;
     RECT  0.192 54.816 0.205 54.84 ;
     RECT  0.156 54.84 0.205 54.96 ;
     RECT  0.192 54.96 0.205 54.984 ;
     RECT  0.156 54.984 0.205 55.056 ;
     RECT  0.192 55.056 0.205 55.08 ;
     RECT  0.156 55.08 0.205 55.152 ;
     RECT  0.192 55.152 0.205 55.176 ;
     RECT  0.156 55.176 0.205 55.248 ;
     RECT  0.192 55.248 0.205 55.272 ;
     RECT  0.156 55.272 0.205 55.344 ;
     RECT  0.192 55.344 0.205 55.368 ;
     RECT  0.156 55.368 0.205 55.44 ;
     RECT  0.192 55.44 0.205 55.464 ;
     RECT  0.156 55.464 0.205 55.584 ;
     RECT  0.192 55.584 0.205 55.608 ;
     RECT  0.156 55.608 0.205 55.68 ;
     RECT  0.192 55.68 0.205 55.704 ;
     RECT  0.156 55.704 0.205 55.776 ;
     RECT  0.192 55.776 0.205 55.8 ;
     RECT  0.156 55.8 0.205 55.872 ;
     RECT  0.192 55.872 0.205 55.896 ;
     RECT  0.156 55.896 0.205 55.968 ;
     RECT  0.192 55.968 0.205 55.992 ;
     RECT  0.156 55.992 0.205 56.064 ;
     RECT  0.192 56.064 0.205 56.088 ;
     RECT  0.156 56.088 0.205 56.208 ;
     RECT  0.192 56.208 0.205 56.232 ;
     RECT  0.156 56.232 0.205 56.304 ;
     RECT  0.192 56.304 0.205 56.328 ;
     RECT  0.156 56.328 0.205 56.4 ;
     RECT  0.192 56.4 0.205 56.424 ;
     RECT  0.156 56.424 0.205 56.496 ;
     RECT  0.192 56.496 0.205 56.52 ;
     RECT  0.156 56.52 0.205 56.592 ;
     RECT  0.192 56.592 0.205 56.616 ;
     RECT  0.156 56.616 0.205 56.688 ;
     RECT  0.192 56.688 0.205 56.712 ;
     RECT  0.156 56.712 0.205 56.832 ;
     RECT  0.192 56.832 0.205 56.856 ;
     RECT  0.156 56.856 0.205 56.928 ;
     RECT  0.192 56.928 0.205 56.952 ;
     RECT  0.156 56.952 0.205 57.024 ;
     RECT  0.192 57.024 0.205 57.048 ;
     RECT  0.156 57.048 0.205 57.12 ;
     RECT  0.192 57.12 0.205 57.144 ;
     RECT  0.156 57.144 0.205 57.216 ;
     RECT  0.192 57.216 0.205 57.24 ;
     RECT  0.156 57.24 0.205 57.312 ;
     RECT  0.192 57.312 0.205 57.336 ;
     RECT  0.156 57.336 0.205 57.408 ;
     RECT  0.192 57.408 0.205 57.432 ;
     RECT  0.156 57.432 0.205 57.552 ;
     RECT  0.192 57.552 0.205 57.576 ;
     RECT  0.156 57.576 0.205 57.648 ;
     RECT  0.192 57.648 0.205 57.672 ;
     RECT  0.156 57.672 0.205 57.744 ;
     RECT  0.192 57.744 0.205 57.768 ;
     RECT  0.156 57.768 0.205 57.84 ;
     RECT  0.192 57.84 0.205 57.864 ;
     RECT  0.156 57.864 0.205 57.936 ;
     RECT  0.192 57.936 0.205 57.96 ;
     RECT  0.156 57.96 0.205 58.032 ;
     RECT  0.192 58.032 0.205 58.056 ;
     RECT  0.156 58.056 0.205 58.176 ;
     RECT  0.192 58.176 0.205 58.2 ;
     RECT  0.156 58.2 0.205 58.272 ;
     RECT  0.192 58.272 0.205 58.296 ;
     RECT  0.156 58.296 0.205 58.368 ;
     RECT  0.192 58.368 0.205 58.392 ;
     RECT  0.156 58.392 0.205 58.464 ;
     RECT  0.192 58.464 0.205 58.488 ;
     RECT  0.156 58.488 0.205 58.56 ;
     RECT  0.192 58.56 0.205 58.584 ;
     RECT  0.156 58.584 0.205 58.656 ;
     RECT  0.192 58.656 0.205 58.68 ;
     RECT  0.156 58.68 0.205 58.8 ;
     RECT  0.192 58.8 0.205 58.824 ;
     RECT  0.156 58.824 0.205 58.896 ;
     RECT  0.192 58.896 0.205 58.92 ;
     RECT  0.156 58.92 0.205 58.992 ;
     RECT  0.192 58.992 0.205 59.016 ;
     RECT  0.156 59.016 0.205 59.088 ;
     RECT  0.192 59.088 0.205 59.112 ;
     RECT  0.156 59.112 0.205 59.184 ;
     RECT  0.192 59.184 0.205 59.208 ;
     RECT  0.156 59.208 0.205 59.28 ;
     RECT  0.192 59.28 0.205 59.304 ;
     RECT  0.156 59.304 0.205 59.424 ;
     RECT  0.192 59.424 0.205 59.448 ;
     RECT  0.156 59.448 0.205 59.52 ;
     RECT  0.192 59.52 0.205 59.544 ;
     RECT  0.156 59.544 0.205 59.616 ;
     RECT  0.192 59.616 0.205 59.64 ;
     RECT  0.156 59.64 0.205 59.712 ;
     RECT  0.192 59.712 0.205 59.736 ;
     RECT  0.156 59.736 0.205 59.808 ;
     RECT  0.192 59.808 0.205 59.832 ;
     RECT  0.156 59.832 0.205 59.904 ;
     RECT  0.192 59.904 0.205 59.928 ;
     RECT  0.156 59.928 0.205 60.048 ;
     RECT  0.192 60.048 0.205 60.072 ;
     RECT  0.156 60.072 0.205 60.144 ;
     RECT  0.192 60.144 0.205 60.168 ;
     RECT  0.156 60.168 0.205 60.24 ;
     RECT  0.192 60.24 0.205 60.264 ;
     RECT  0.156 60.264 0.205 60.336 ;
     RECT  0.192 60.336 0.205 60.36 ;
     RECT  0.156 60.36 0.205 60.432 ;
     RECT  0.192 60.432 0.205 60.456 ;
     RECT  0.205 2.064 2.408 60.456 ;
     RECT  2.408 2.064 2.581 60.492 ;
     RECT  2.581 2.064 3.629 60.552 ;
     RECT  3.629 2.304 5.033 60.552 ;
     RECT  5.033 2.304 5.108 60.492 ;
     RECT  5.108 2.148 5.212 60.492 ;
     RECT  5.389 61.584 5.603 61.608 ;
     RECT  5.212 2.304 6.649 60.408 ;
     RECT  6.649 2.208 6.757 60.408 ;
     RECT  6.757 2.208 7.808 60.6 ;
     RECT  7.808 2.148 7.912 60.6 ;
     RECT  7.912 2.256 8.237 60.6 ;
     RECT  8.237 2.352 8.885 60.6 ;
     RECT  8.885 2.352 9.137 60.408 ;
     RECT  9.137 2.88 9.209 60.408 ;
     RECT  9.209 3.12 10.508 60.408 ;
     RECT  10.508 2.148 10.612 60.492 ;
     RECT  10.612 2.418 10.804 60.408 ;
     RECT  10.804 3.12 10.865 60.408 ;
     RECT  10.865 3.12 10.973 43.368 ;
     RECT  10.973 3.12 11.045 36.84 ;
     RECT  11.045 3.12 11.441 7.704 ;
     RECT  11.045 8.976 11.441 36.84 ;
     RECT  11.441 8.976 11.945 13.608 ;
     RECT  11.441 3.408 12.017 7.704 ;
     RECT  11.945 8.976 12.017 13.56 ;
     RECT  11.441 14.64 12.017 35.544 ;
     RECT  10.865 44.352 12.053 60.408 ;
     RECT  12.017 18.432 12.125 32.328 ;
     RECT  12.125 18.432 12.161 32.232 ;
     RECT  12.017 11.232 12.197 13.56 ;
     RECT  12.197 11.232 12.233 11.256 ;
     RECT  12.017 33.792 12.233 35.544 ;
     RECT  12.017 3.408 13.208 7.368 ;
     RECT  12.017 8.976 13.208 10.152 ;
     RECT  12.197 13.056 13.208 13.56 ;
     RECT  12.017 14.64 13.208 17.352 ;
     RECT  12.161 18.432 13.208 31.464 ;
     RECT  12.233 33.792 13.208 35.16 ;
     RECT  11.441 36.624 13.208 36.792 ;
     RECT  10.973 37.968 13.208 43.368 ;
     RECT  12.053 44.352 13.208 47.88 ;
     RECT  12.053 49.2 13.208 60.408 ;
     RECT  13.208 2.148 13.312 60.492 ;
     RECT  13.312 2.418 13.504 60.456 ;
     RECT  13.504 18.432 13.565 18.984 ;
     RECT  13.504 30.624 13.565 32.472 ;
     RECT  13.565 30.624 13.601 30.936 ;
     RECT  13.504 38.4 13.601 40.104 ;
     RECT  13.504 59.52 13.601 60.456 ;
     RECT  13.565 18.96 13.673 18.984 ;
     RECT  13.504 25.44 13.673 25.464 ;
     RECT  13.504 47.088 13.673 47.208 ;
     RECT  13.504 51.312 13.673 57.048 ;
     RECT  13.504 6.624 13.817 7.368 ;
     RECT  13.601 38.64 13.817 40.104 ;
     RECT  13.673 51.312 13.889 55.176 ;
     RECT  13.817 39.552 13.961 40.104 ;
     RECT  13.504 16.512 13.997 17.208 ;
     RECT  13.673 56.256 14.033 57.048 ;
     RECT  13.504 20.592 14.105 22.152 ;
     RECT  13.504 27.072 14.105 28.44 ;
     RECT  14.033 56.256 14.213 56.856 ;
     RECT  13.504 2.736 14.249 3.624 ;
     RECT  14.105 27.072 14.533 27.624 ;
     RECT  13.504 10.128 14.569 10.152 ;
     RECT  13.504 13.056 14.569 13.08 ;
     RECT  13.601 60.432 14.713 60.456 ;
     RECT  14.249 2.736 14.821 2.76 ;
     RECT  13.504 5.184 14.821 5.208 ;
     RECT  13.817 6.624 14.821 7.32 ;
     RECT  13.504 8.976 14.821 9 ;
     RECT  14.569 10.128 14.821 13.08 ;
     RECT  14.605 17.856 14.821 17.88 ;
     RECT  13.504 23.568 14.821 23.592 ;
     RECT  14.533 26.976 14.821 27.624 ;
     RECT  13.601 30.912 14.821 30.936 ;
     RECT  13.565 32.352 14.821 32.472 ;
     RECT  13.504 36.048 14.821 36.072 ;
     RECT  13.961 39.552 14.821 39.768 ;
     RECT  13.504 41.712 14.821 42.216 ;
     RECT  13.504 44.352 14.821 46.104 ;
     RECT  13.673 47.184 14.821 47.208 ;
     RECT  13.504 48.288 14.821 48.312 ;
     RECT  13.889 52.752 14.821 55.176 ;
     RECT  14.213 56.256 14.821 56.52 ;
     RECT  13.504 58.416 14.821 58.44 ;
     RECT  14.713 59.808 14.821 60.456 ;
     RECT  14.821 4.272 14.857 5.208 ;
     RECT  14.821 6.24 14.857 14.904 ;
     RECT  13.997 16.512 14.857 16.536 ;
     RECT  14.821 23.232 14.857 23.592 ;
     RECT  14.821 24.576 14.857 24.84 ;
     RECT  14.821 25.968 14.857 27.624 ;
     RECT  14.821 28.752 14.857 28.968 ;
     RECT  14.821 30.384 14.857 31.368 ;
     RECT  14.821 32.352 14.857 32.616 ;
     RECT  14.821 33.6 14.857 39.768 ;
     RECT  14.821 40.848 14.857 49.176 ;
     RECT  13.889 51.312 14.857 51.336 ;
     RECT  14.821 52.752 14.857 56.52 ;
     RECT  14.821 2.304 15.397 2.76 ;
     RECT  14.857 4.272 15.397 16.536 ;
     RECT  14.821 17.856 15.397 18.6 ;
     RECT  14.821 19.632 15.397 19.752 ;
     RECT  14.105 21.552 15.397 22.152 ;
     RECT  14.857 23.232 15.397 27.624 ;
     RECT  14.857 28.752 15.397 39.768 ;
     RECT  14.857 40.848 15.397 49.272 ;
     RECT  14.821 50.304 15.397 50.328 ;
     RECT  14.857 51.312 15.397 56.52 ;
     RECT  14.821 57.936 15.397 60.456 ;
     RECT  15.397 2.304 16.513 60.456 ;
     RECT  16.513 2.208 17.088 2.232 ;
     RECT  16.513 2.232 17.1 2.304 ;
     RECT  16.513 2.304 17.088 2.328 ;
     RECT  16.513 2.328 17.1 2.448 ;
     RECT  16.513 2.448 17.088 2.472 ;
     RECT  16.513 2.472 17.1 2.544 ;
     RECT  16.513 2.544 17.088 2.568 ;
     RECT  16.513 2.568 17.1 2.64 ;
     RECT  16.513 2.64 17.088 2.664 ;
     RECT  16.513 2.664 17.1 2.736 ;
     RECT  16.513 2.736 17.088 2.76 ;
     RECT  16.513 2.76 17.1 2.832 ;
     RECT  16.513 2.832 17.088 2.856 ;
     RECT  16.513 2.856 17.1 2.928 ;
     RECT  16.513 2.928 17.088 2.952 ;
     RECT  16.513 2.952 17.1 3.072 ;
     RECT  16.513 3.072 17.088 3.096 ;
     RECT  16.513 3.096 17.1 3.168 ;
     RECT  16.513 3.168 17.088 3.192 ;
     RECT  16.513 3.192 17.1 3.264 ;
     RECT  16.513 3.264 17.088 3.288 ;
     RECT  16.513 3.288 17.1 3.36 ;
     RECT  16.513 3.36 17.088 3.384 ;
     RECT  16.513 3.384 17.1 3.456 ;
     RECT  16.513 3.456 17.088 3.48 ;
     RECT  16.513 3.48 17.1 3.552 ;
     RECT  16.513 3.552 17.088 3.576 ;
     RECT  16.513 3.576 17.1 3.696 ;
     RECT  16.513 3.696 17.088 3.72 ;
     RECT  16.513 3.72 17.1 3.792 ;
     RECT  16.513 3.792 17.088 3.816 ;
     RECT  16.513 3.816 17.1 3.888 ;
     RECT  16.513 3.888 17.088 3.912 ;
     RECT  16.513 3.912 17.1 3.984 ;
     RECT  16.513 3.984 17.088 4.008 ;
     RECT  16.513 4.008 17.1 4.08 ;
     RECT  16.513 4.08 17.088 4.104 ;
     RECT  16.513 4.104 17.1 4.176 ;
     RECT  16.513 4.176 17.088 4.2 ;
     RECT  16.513 4.2 17.1 4.272 ;
     RECT  16.513 4.272 17.088 4.296 ;
     RECT  16.513 4.296 17.1 4.416 ;
     RECT  16.513 4.416 17.088 4.44 ;
     RECT  16.513 4.44 17.1 4.512 ;
     RECT  16.513 4.512 17.088 4.536 ;
     RECT  16.513 4.536 17.1 4.608 ;
     RECT  16.513 4.608 17.088 4.632 ;
     RECT  16.513 4.632 17.1 4.704 ;
     RECT  16.513 4.704 17.088 4.728 ;
     RECT  16.513 4.728 17.1 4.8 ;
     RECT  16.513 4.8 17.088 4.824 ;
     RECT  16.513 4.824 17.1 4.896 ;
     RECT  16.513 4.896 17.088 4.92 ;
     RECT  16.513 4.92 17.1 5.04 ;
     RECT  16.513 5.04 17.088 5.064 ;
     RECT  16.513 5.064 17.1 5.136 ;
     RECT  16.513 5.136 17.088 5.16 ;
     RECT  16.513 5.16 17.1 5.232 ;
     RECT  16.513 5.232 17.088 5.256 ;
     RECT  16.513 5.256 17.1 5.328 ;
     RECT  16.513 5.328 17.088 5.352 ;
     RECT  16.513 5.352 17.1 5.424 ;
     RECT  16.513 5.424 17.088 5.448 ;
     RECT  16.513 5.448 17.1 5.52 ;
     RECT  16.513 5.52 17.088 5.544 ;
     RECT  16.513 5.544 17.1 5.664 ;
     RECT  16.513 5.664 17.088 5.688 ;
     RECT  16.513 5.688 17.1 5.76 ;
     RECT  16.513 5.76 17.088 5.784 ;
     RECT  16.513 5.784 17.1 5.856 ;
     RECT  16.513 5.856 17.088 5.88 ;
     RECT  16.513 5.88 17.1 5.952 ;
     RECT  16.513 5.952 17.088 5.976 ;
     RECT  16.513 5.976 17.1 6.048 ;
     RECT  16.513 6.048 17.088 6.072 ;
     RECT  16.513 6.072 17.1 6.144 ;
     RECT  16.513 6.144 17.088 6.168 ;
     RECT  16.513 6.168 17.1 6.24 ;
     RECT  16.513 6.24 17.088 6.264 ;
     RECT  16.513 6.264 17.1 6.384 ;
     RECT  16.513 6.384 17.088 6.408 ;
     RECT  16.513 6.408 17.1 6.48 ;
     RECT  16.513 6.48 17.088 6.504 ;
     RECT  16.513 6.504 17.1 6.576 ;
     RECT  16.513 6.576 17.088 6.6 ;
     RECT  16.513 6.6 17.1 6.672 ;
     RECT  16.513 6.672 17.088 6.696 ;
     RECT  16.513 6.696 17.1 6.768 ;
     RECT  16.513 6.768 17.088 6.792 ;
     RECT  16.513 6.792 17.1 6.864 ;
     RECT  16.513 6.864 17.088 6.888 ;
     RECT  16.513 6.888 17.1 7.008 ;
     RECT  16.513 7.008 17.088 7.032 ;
     RECT  16.513 7.032 17.1 7.104 ;
     RECT  16.513 7.104 17.088 7.128 ;
     RECT  16.513 7.128 17.1 7.2 ;
     RECT  16.513 7.2 17.088 7.224 ;
     RECT  16.513 7.224 17.1 7.296 ;
     RECT  16.513 7.296 17.088 7.32 ;
     RECT  16.513 7.32 17.1 7.392 ;
     RECT  16.513 7.392 17.088 7.416 ;
     RECT  16.513 7.416 17.1 7.488 ;
     RECT  16.513 7.488 17.088 7.512 ;
     RECT  16.513 7.512 17.1 7.632 ;
     RECT  16.513 7.632 17.088 7.656 ;
     RECT  16.513 7.656 17.1 7.728 ;
     RECT  16.513 7.728 17.088 7.752 ;
     RECT  16.513 7.752 17.1 7.824 ;
     RECT  16.513 7.824 17.088 7.848 ;
     RECT  16.513 7.848 17.1 7.92 ;
     RECT  16.513 7.92 17.088 7.944 ;
     RECT  16.513 7.944 17.1 8.016 ;
     RECT  16.513 8.016 17.088 8.04 ;
     RECT  16.513 8.04 17.1 8.112 ;
     RECT  16.513 8.112 17.088 8.136 ;
     RECT  16.513 8.136 17.1 8.208 ;
     RECT  16.513 8.208 17.088 8.232 ;
     RECT  16.513 8.232 17.1 8.352 ;
     RECT  16.513 8.352 17.088 8.376 ;
     RECT  16.513 8.376 17.1 8.448 ;
     RECT  16.513 8.448 17.088 8.472 ;
     RECT  16.513 8.472 17.1 8.544 ;
     RECT  16.513 8.544 17.088 8.568 ;
     RECT  16.513 8.568 17.1 8.64 ;
     RECT  16.513 8.64 17.088 8.664 ;
     RECT  16.513 8.664 17.1 8.736 ;
     RECT  16.513 8.736 17.088 8.76 ;
     RECT  16.513 8.76 17.1 8.832 ;
     RECT  16.513 8.832 17.088 8.856 ;
     RECT  16.513 8.856 17.1 8.976 ;
     RECT  16.513 8.976 17.088 9 ;
     RECT  16.513 9 17.1 9.072 ;
     RECT  16.513 9.072 17.088 9.096 ;
     RECT  16.513 9.096 17.1 9.168 ;
     RECT  16.513 9.168 17.088 9.192 ;
     RECT  16.513 9.192 17.1 9.264 ;
     RECT  16.513 9.264 17.088 9.288 ;
     RECT  16.513 9.288 17.1 9.36 ;
     RECT  16.513 9.36 17.088 9.384 ;
     RECT  16.513 9.384 17.1 9.456 ;
     RECT  16.513 9.456 17.088 9.48 ;
     RECT  16.513 9.48 17.1 9.6 ;
     RECT  16.513 9.6 17.088 9.624 ;
     RECT  16.513 9.624 17.1 9.696 ;
     RECT  16.513 9.696 17.088 9.72 ;
     RECT  16.513 9.72 17.1 9.792 ;
     RECT  16.513 9.792 17.088 9.816 ;
     RECT  16.513 9.816 17.1 9.888 ;
     RECT  16.513 9.888 17.088 9.912 ;
     RECT  16.513 9.912 17.1 9.984 ;
     RECT  16.513 9.984 17.088 10.008 ;
     RECT  16.513 10.008 17.1 10.08 ;
     RECT  16.513 10.08 17.088 10.104 ;
     RECT  16.513 10.104 17.1 10.224 ;
     RECT  16.513 10.224 17.088 10.248 ;
     RECT  16.513 10.248 17.1 10.32 ;
     RECT  16.513 10.32 17.088 10.344 ;
     RECT  16.513 10.344 17.1 10.416 ;
     RECT  16.513 10.416 17.088 10.44 ;
     RECT  16.513 10.44 17.1 10.512 ;
     RECT  16.513 10.512 17.088 10.536 ;
     RECT  16.513 10.536 17.1 10.608 ;
     RECT  16.513 10.608 17.088 10.632 ;
     RECT  16.513 10.632 17.1 10.704 ;
     RECT  16.513 10.704 17.088 10.728 ;
     RECT  16.513 10.728 17.1 10.8 ;
     RECT  16.513 10.8 17.088 10.824 ;
     RECT  16.513 10.824 17.1 10.944 ;
     RECT  16.513 10.944 17.088 10.968 ;
     RECT  16.513 10.968 17.1 11.04 ;
     RECT  16.513 11.04 17.088 11.064 ;
     RECT  16.513 11.064 17.1 11.136 ;
     RECT  16.513 11.136 17.088 11.16 ;
     RECT  16.513 11.16 17.1 11.232 ;
     RECT  16.513 11.232 17.088 11.256 ;
     RECT  16.513 11.256 17.1 11.328 ;
     RECT  16.513 11.328 17.088 11.352 ;
     RECT  16.513 11.352 17.1 11.424 ;
     RECT  16.513 11.424 17.088 11.448 ;
     RECT  16.513 11.448 17.1 11.568 ;
     RECT  16.513 11.568 17.088 11.592 ;
     RECT  16.513 11.592 17.1 11.664 ;
     RECT  16.513 11.664 17.088 11.688 ;
     RECT  16.513 11.688 17.1 11.76 ;
     RECT  16.513 11.76 17.088 11.784 ;
     RECT  16.513 11.784 17.1 11.856 ;
     RECT  16.513 11.856 17.088 11.88 ;
     RECT  16.513 11.88 17.1 11.952 ;
     RECT  16.513 11.952 17.088 11.976 ;
     RECT  16.513 11.976 17.1 12.048 ;
     RECT  16.513 12.048 17.088 12.072 ;
     RECT  16.513 12.072 17.1 12.192 ;
     RECT  16.513 12.192 17.088 12.216 ;
     RECT  16.513 12.216 17.1 12.288 ;
     RECT  16.513 12.288 17.088 12.312 ;
     RECT  16.513 12.312 17.1 12.384 ;
     RECT  16.513 12.384 17.088 12.408 ;
     RECT  16.513 12.408 17.1 12.48 ;
     RECT  16.513 12.48 17.088 12.504 ;
     RECT  16.513 12.504 17.1 12.576 ;
     RECT  16.513 12.576 17.088 12.6 ;
     RECT  16.513 12.6 17.1 12.672 ;
     RECT  16.513 12.672 17.088 12.696 ;
     RECT  16.513 12.696 17.1 12.768 ;
     RECT  16.513 12.768 17.088 12.792 ;
     RECT  16.513 12.792 17.1 12.912 ;
     RECT  16.513 12.912 17.088 12.936 ;
     RECT  16.513 12.936 17.1 13.008 ;
     RECT  16.513 13.008 17.088 13.032 ;
     RECT  16.513 13.032 17.1 13.104 ;
     RECT  16.513 13.104 17.088 13.128 ;
     RECT  16.513 13.128 17.1 13.2 ;
     RECT  16.513 13.2 17.088 13.224 ;
     RECT  16.513 13.224 17.1 13.296 ;
     RECT  16.513 13.296 17.088 13.32 ;
     RECT  16.513 13.32 17.1 13.392 ;
     RECT  16.513 13.392 17.088 13.416 ;
     RECT  16.513 13.416 17.1 13.536 ;
     RECT  16.513 13.536 17.088 13.56 ;
     RECT  16.513 13.56 17.1 13.632 ;
     RECT  16.513 13.632 17.088 13.656 ;
     RECT  16.513 13.656 17.1 13.728 ;
     RECT  16.513 13.728 17.088 13.752 ;
     RECT  16.513 13.752 17.1 13.824 ;
     RECT  16.513 13.824 17.088 13.848 ;
     RECT  16.513 13.848 17.1 13.92 ;
     RECT  16.513 13.92 17.088 13.944 ;
     RECT  16.513 13.944 17.1 14.016 ;
     RECT  16.513 14.016 17.088 14.04 ;
     RECT  16.513 14.04 17.1 14.16 ;
     RECT  16.513 14.16 17.088 14.184 ;
     RECT  16.513 14.184 17.1 14.256 ;
     RECT  16.513 14.256 17.088 14.28 ;
     RECT  16.513 14.28 17.1 14.352 ;
     RECT  16.513 14.352 17.088 14.376 ;
     RECT  16.513 14.376 17.1 14.448 ;
     RECT  16.513 14.448 17.088 14.472 ;
     RECT  16.513 14.472 17.1 14.544 ;
     RECT  16.513 14.544 17.088 14.568 ;
     RECT  16.513 14.568 17.1 14.64 ;
     RECT  16.513 14.64 17.088 14.664 ;
     RECT  16.513 14.664 17.1 14.736 ;
     RECT  16.513 14.736 17.088 14.76 ;
     RECT  16.513 14.76 17.1 14.88 ;
     RECT  16.513 14.88 17.088 14.904 ;
     RECT  16.513 14.904 17.1 14.976 ;
     RECT  16.513 14.976 17.088 15 ;
     RECT  16.513 15 17.1 15.072 ;
     RECT  16.513 15.072 17.088 15.096 ;
     RECT  16.513 15.096 17.1 15.168 ;
     RECT  16.513 15.168 17.088 15.192 ;
     RECT  16.513 15.192 17.1 15.264 ;
     RECT  16.513 15.264 17.088 15.288 ;
     RECT  16.513 15.288 17.1 15.36 ;
     RECT  16.513 15.36 17.088 15.384 ;
     RECT  16.513 15.384 17.1 15.504 ;
     RECT  16.513 15.504 17.088 15.528 ;
     RECT  16.513 15.528 17.1 15.6 ;
     RECT  16.513 15.6 17.088 15.624 ;
     RECT  16.513 15.624 17.1 15.696 ;
     RECT  16.513 15.696 17.088 15.72 ;
     RECT  16.513 15.72 17.1 15.792 ;
     RECT  16.513 15.792 17.088 15.816 ;
     RECT  16.513 15.816 17.1 15.888 ;
     RECT  16.513 15.888 17.088 15.912 ;
     RECT  16.513 15.912 17.1 15.984 ;
     RECT  16.513 15.984 17.088 16.008 ;
     RECT  16.513 16.008 17.1 16.128 ;
     RECT  16.513 16.128 17.088 16.152 ;
     RECT  16.513 16.152 17.1 16.224 ;
     RECT  16.513 16.224 17.088 16.248 ;
     RECT  16.513 16.248 17.1 16.32 ;
     RECT  16.513 16.32 17.088 16.344 ;
     RECT  16.513 16.344 17.1 16.416 ;
     RECT  16.513 16.416 17.088 16.44 ;
     RECT  16.513 16.44 17.1 16.512 ;
     RECT  16.513 16.512 17.088 16.536 ;
     RECT  16.513 16.536 17.1 16.608 ;
     RECT  16.513 16.608 17.088 16.632 ;
     RECT  16.513 16.632 17.1 16.704 ;
     RECT  16.513 16.704 17.088 16.728 ;
     RECT  16.513 16.728 17.1 16.848 ;
     RECT  16.513 16.848 17.088 16.872 ;
     RECT  16.513 16.872 17.1 16.944 ;
     RECT  16.513 16.944 17.088 16.968 ;
     RECT  16.513 16.968 17.1 17.04 ;
     RECT  16.513 17.04 17.088 17.064 ;
     RECT  16.513 17.064 17.1 17.136 ;
     RECT  16.513 17.136 17.088 17.16 ;
     RECT  16.513 17.16 17.1 17.232 ;
     RECT  16.513 17.232 17.088 17.256 ;
     RECT  16.513 17.256 17.1 17.328 ;
     RECT  16.513 17.328 17.088 17.352 ;
     RECT  16.513 17.352 17.1 17.472 ;
     RECT  16.513 17.472 17.088 17.496 ;
     RECT  16.513 17.496 17.1 17.568 ;
     RECT  16.513 17.568 17.088 17.592 ;
     RECT  16.513 17.592 17.1 17.664 ;
     RECT  16.513 17.664 17.088 17.688 ;
     RECT  16.513 17.688 17.1 17.76 ;
     RECT  16.513 17.76 17.088 17.784 ;
     RECT  16.513 17.784 17.1 17.856 ;
     RECT  16.513 17.856 17.088 17.88 ;
     RECT  16.513 17.88 17.1 17.952 ;
     RECT  16.513 17.952 17.088 17.976 ;
     RECT  16.513 17.976 17.1 18.096 ;
     RECT  16.513 18.096 17.088 18.12 ;
     RECT  16.513 18.12 17.1 18.192 ;
     RECT  16.513 18.192 17.088 18.216 ;
     RECT  16.513 18.216 17.1 18.288 ;
     RECT  16.513 18.288 17.088 18.312 ;
     RECT  16.513 18.312 17.1 18.384 ;
     RECT  16.513 18.384 17.088 18.408 ;
     RECT  16.513 18.408 17.1 18.48 ;
     RECT  16.513 18.48 17.088 18.504 ;
     RECT  16.513 18.504 17.1 18.576 ;
     RECT  16.513 18.576 17.088 18.6 ;
     RECT  16.513 18.6 17.1 18.672 ;
     RECT  16.513 18.672 17.088 18.696 ;
     RECT  16.513 18.696 17.1 18.816 ;
     RECT  16.513 18.816 17.088 18.84 ;
     RECT  16.513 18.84 17.1 18.912 ;
     RECT  16.513 18.912 17.088 18.936 ;
     RECT  16.513 18.936 17.1 19.008 ;
     RECT  16.513 19.008 17.088 19.032 ;
     RECT  16.513 19.032 17.1 19.104 ;
     RECT  16.513 19.104 17.088 19.128 ;
     RECT  16.513 19.128 17.1 19.2 ;
     RECT  16.513 19.2 17.088 19.224 ;
     RECT  16.513 19.224 17.1 19.296 ;
     RECT  16.513 19.296 17.088 19.32 ;
     RECT  16.513 19.32 17.1 19.44 ;
     RECT  16.513 19.44 17.088 19.464 ;
     RECT  16.513 19.464 17.1 19.536 ;
     RECT  16.513 19.536 17.088 19.56 ;
     RECT  16.513 19.56 17.1 19.632 ;
     RECT  16.513 19.632 17.088 19.656 ;
     RECT  16.513 19.656 17.1 19.728 ;
     RECT  16.513 19.728 17.088 19.752 ;
     RECT  16.513 19.752 17.1 19.824 ;
     RECT  16.513 19.824 17.088 19.848 ;
     RECT  16.513 19.848 17.1 19.92 ;
     RECT  16.513 19.92 17.088 19.944 ;
     RECT  16.513 19.944 17.1 20.064 ;
     RECT  16.513 20.064 17.088 20.088 ;
     RECT  16.513 20.088 17.1 20.16 ;
     RECT  16.513 20.16 17.088 20.184 ;
     RECT  16.513 20.184 17.1 20.256 ;
     RECT  16.513 20.256 17.088 20.28 ;
     RECT  16.513 20.28 17.1 20.352 ;
     RECT  16.513 20.352 17.088 20.376 ;
     RECT  16.513 20.376 17.1 20.448 ;
     RECT  16.513 20.448 17.088 20.472 ;
     RECT  16.513 20.472 17.1 20.544 ;
     RECT  16.513 20.544 17.088 20.568 ;
     RECT  16.513 20.568 17.1 20.64 ;
     RECT  16.513 20.64 17.088 20.664 ;
     RECT  16.513 20.664 17.1 20.784 ;
     RECT  16.513 20.784 17.088 20.808 ;
     RECT  16.513 20.808 17.1 20.88 ;
     RECT  16.513 20.88 17.088 20.904 ;
     RECT  16.513 20.904 17.1 20.976 ;
     RECT  16.513 20.976 17.088 21 ;
     RECT  16.513 21 17.1 21.072 ;
     RECT  16.513 21.072 17.088 21.096 ;
     RECT  16.513 21.096 17.1 21.168 ;
     RECT  16.513 21.168 17.088 21.192 ;
     RECT  16.513 21.192 17.1 21.264 ;
     RECT  16.513 21.264 17.088 21.288 ;
     RECT  16.513 21.288 17.1 21.408 ;
     RECT  16.513 21.408 17.088 21.432 ;
     RECT  16.513 21.432 17.1 21.504 ;
     RECT  16.513 21.504 17.088 21.528 ;
     RECT  16.513 21.528 17.1 21.6 ;
     RECT  16.513 21.6 17.088 21.624 ;
     RECT  16.513 21.624 17.1 21.696 ;
     RECT  16.513 21.696 17.088 21.72 ;
     RECT  16.513 21.72 17.1 21.792 ;
     RECT  16.513 21.792 17.088 21.816 ;
     RECT  16.513 21.816 17.1 21.888 ;
     RECT  16.513 21.888 17.088 21.912 ;
     RECT  16.513 21.912 17.1 22.032 ;
     RECT  16.513 22.032 17.088 22.056 ;
     RECT  16.513 22.056 17.1 22.128 ;
     RECT  16.513 22.128 17.088 22.152 ;
     RECT  16.513 22.152 17.1 22.224 ;
     RECT  16.513 22.224 17.088 22.248 ;
     RECT  16.513 22.248 17.1 22.32 ;
     RECT  16.513 22.32 17.088 22.344 ;
     RECT  16.513 22.344 17.1 22.416 ;
     RECT  16.513 22.416 17.088 22.44 ;
     RECT  16.513 22.44 17.1 22.512 ;
     RECT  16.513 22.512 17.088 22.536 ;
     RECT  16.513 22.536 17.1 22.608 ;
     RECT  16.513 22.608 17.088 22.632 ;
     RECT  16.513 22.632 17.1 22.752 ;
     RECT  16.513 22.752 17.088 22.776 ;
     RECT  16.513 22.776 17.1 22.848 ;
     RECT  16.513 22.848 17.088 22.872 ;
     RECT  16.513 22.872 17.1 22.944 ;
     RECT  16.513 22.944 17.088 22.968 ;
     RECT  16.513 22.968 17.1 23.04 ;
     RECT  16.513 23.04 17.088 23.064 ;
     RECT  16.513 23.064 17.1 23.136 ;
     RECT  16.513 23.136 17.088 23.16 ;
     RECT  16.513 23.16 17.1 23.232 ;
     RECT  16.513 23.232 17.088 23.256 ;
     RECT  16.513 23.256 17.1 23.376 ;
     RECT  16.513 23.376 17.088 23.4 ;
     RECT  16.513 23.4 17.1 23.472 ;
     RECT  16.513 23.472 17.088 23.496 ;
     RECT  16.513 23.496 17.1 23.568 ;
     RECT  16.513 23.568 17.088 23.592 ;
     RECT  16.513 23.592 17.1 23.664 ;
     RECT  16.513 23.664 17.088 23.688 ;
     RECT  16.513 23.688 17.1 23.76 ;
     RECT  16.513 23.76 17.088 23.784 ;
     RECT  16.513 23.784 17.1 23.856 ;
     RECT  16.513 23.856 17.088 23.88 ;
     RECT  16.513 23.88 17.1 24 ;
     RECT  16.513 24 17.088 24.024 ;
     RECT  16.513 24.024 17.1 24.096 ;
     RECT  16.513 24.096 17.088 24.12 ;
     RECT  16.513 24.12 17.1 24.192 ;
     RECT  16.513 24.192 17.088 24.216 ;
     RECT  16.513 24.216 17.1 24.288 ;
     RECT  16.513 24.288 17.088 24.312 ;
     RECT  16.513 24.312 17.1 24.384 ;
     RECT  16.513 24.384 17.088 24.408 ;
     RECT  16.513 24.408 17.1 24.48 ;
     RECT  16.513 24.48 17.088 24.504 ;
     RECT  16.513 24.504 17.1 24.576 ;
     RECT  16.513 24.576 17.088 24.6 ;
     RECT  16.513 24.6 17.1 24.72 ;
     RECT  16.513 24.72 17.088 24.744 ;
     RECT  16.513 24.744 17.1 24.816 ;
     RECT  16.513 24.816 17.088 24.84 ;
     RECT  16.513 24.84 17.1 24.912 ;
     RECT  16.513 24.912 17.088 24.936 ;
     RECT  16.513 24.936 17.1 25.008 ;
     RECT  16.513 25.008 17.088 25.032 ;
     RECT  16.513 25.032 17.1 25.104 ;
     RECT  16.513 25.104 17.088 25.128 ;
     RECT  16.513 25.128 17.1 25.2 ;
     RECT  16.513 25.2 17.088 25.224 ;
     RECT  16.513 25.224 17.1 25.344 ;
     RECT  16.513 25.344 17.088 25.368 ;
     RECT  16.513 25.368 17.1 25.44 ;
     RECT  16.513 25.44 17.088 25.464 ;
     RECT  16.513 25.464 17.1 25.536 ;
     RECT  16.513 25.536 17.088 25.56 ;
     RECT  16.513 25.56 17.1 25.632 ;
     RECT  16.513 25.632 17.088 25.656 ;
     RECT  16.513 25.656 17.1 25.728 ;
     RECT  16.513 25.728 17.088 25.752 ;
     RECT  16.513 25.752 17.1 25.824 ;
     RECT  16.513 25.824 17.088 25.848 ;
     RECT  16.513 25.848 17.1 25.968 ;
     RECT  16.513 25.968 17.088 25.992 ;
     RECT  16.513 25.992 17.1 26.064 ;
     RECT  16.513 26.064 17.088 26.088 ;
     RECT  16.513 26.088 17.1 26.16 ;
     RECT  16.513 26.16 17.088 26.184 ;
     RECT  16.513 26.184 17.1 26.256 ;
     RECT  16.513 26.256 17.088 26.28 ;
     RECT  16.513 26.28 17.1 26.352 ;
     RECT  16.513 26.352 17.088 26.376 ;
     RECT  16.513 26.376 17.1 26.448 ;
     RECT  16.513 26.448 17.088 26.472 ;
     RECT  16.513 26.472 17.1 26.544 ;
     RECT  16.513 26.544 17.088 26.568 ;
     RECT  16.513 26.568 17.1 26.688 ;
     RECT  16.513 26.688 17.088 26.712 ;
     RECT  16.513 26.712 17.1 26.784 ;
     RECT  16.513 26.784 17.088 26.808 ;
     RECT  16.513 26.808 17.1 26.88 ;
     RECT  16.513 26.88 17.088 26.904 ;
     RECT  16.513 26.904 17.1 26.976 ;
     RECT  16.513 26.976 17.088 27 ;
     RECT  16.513 27 17.1 27.072 ;
     RECT  16.513 27.072 17.088 27.096 ;
     RECT  16.513 27.096 17.1 27.168 ;
     RECT  16.513 27.168 17.088 27.192 ;
     RECT  16.513 27.192 17.1 27.312 ;
     RECT  16.513 27.312 17.088 27.336 ;
     RECT  16.513 27.336 17.1 27.408 ;
     RECT  16.513 27.408 17.088 27.432 ;
     RECT  16.513 27.432 17.1 27.504 ;
     RECT  16.513 27.504 17.088 27.528 ;
     RECT  16.513 27.528 17.1 27.6 ;
     RECT  16.513 27.6 17.088 27.624 ;
     RECT  16.513 27.624 17.1 27.696 ;
     RECT  16.513 27.696 17.088 27.72 ;
     RECT  16.513 27.72 17.1 27.792 ;
     RECT  16.513 27.792 17.088 27.816 ;
     RECT  16.513 27.816 17.1 27.936 ;
     RECT  16.513 27.936 17.088 27.96 ;
     RECT  16.513 27.96 17.1 28.032 ;
     RECT  16.513 28.032 17.088 28.056 ;
     RECT  16.513 28.056 17.1 28.128 ;
     RECT  16.513 28.128 17.088 28.152 ;
     RECT  16.513 28.152 17.1 28.224 ;
     RECT  16.513 28.224 17.088 28.248 ;
     RECT  16.513 28.248 17.1 28.32 ;
     RECT  16.513 28.32 17.088 28.344 ;
     RECT  16.513 28.344 17.1 28.416 ;
     RECT  16.513 28.416 17.088 28.44 ;
     RECT  16.513 28.44 17.1 28.512 ;
     RECT  16.513 28.512 17.088 28.536 ;
     RECT  16.513 28.536 17.1 28.656 ;
     RECT  16.513 28.656 17.088 28.68 ;
     RECT  16.513 28.68 17.1 28.752 ;
     RECT  16.513 28.752 17.088 28.776 ;
     RECT  16.513 28.776 17.1 28.848 ;
     RECT  16.513 28.848 17.088 28.872 ;
     RECT  16.513 28.872 17.1 28.944 ;
     RECT  16.513 28.944 17.088 28.968 ;
     RECT  16.513 28.968 17.1 29.04 ;
     RECT  16.513 29.04 17.088 29.064 ;
     RECT  16.513 29.064 17.1 29.136 ;
     RECT  16.513 29.136 17.088 29.16 ;
     RECT  16.513 29.16 17.1 29.28 ;
     RECT  16.513 29.28 17.088 29.304 ;
     RECT  16.513 29.304 17.1 29.376 ;
     RECT  16.513 29.376 17.088 29.4 ;
     RECT  16.513 29.4 17.1 29.472 ;
     RECT  16.513 29.472 17.088 29.496 ;
     RECT  16.513 29.496 17.1 29.568 ;
     RECT  16.513 29.568 17.088 29.592 ;
     RECT  16.513 29.592 17.1 29.664 ;
     RECT  16.513 29.664 17.088 29.688 ;
     RECT  16.513 29.688 17.1 29.76 ;
     RECT  16.513 29.76 17.088 29.784 ;
     RECT  16.513 29.784 17.1 29.904 ;
     RECT  16.513 29.904 17.088 29.928 ;
     RECT  16.513 29.928 17.1 30 ;
     RECT  16.513 30 17.088 30.024 ;
     RECT  16.513 30.024 17.1 30.096 ;
     RECT  16.513 30.096 17.088 30.12 ;
     RECT  16.513 30.12 17.1 30.192 ;
     RECT  16.513 30.192 17.088 30.216 ;
     RECT  16.513 30.216 17.1 30.288 ;
     RECT  16.513 30.288 17.088 30.312 ;
     RECT  16.513 30.312 17.1 30.384 ;
     RECT  16.513 30.384 17.088 30.408 ;
     RECT  16.513 30.408 17.1 30.48 ;
     RECT  16.513 30.48 17.088 30.504 ;
     RECT  16.513 30.504 17.1 30.624 ;
     RECT  16.513 30.624 17.088 30.648 ;
     RECT  16.513 30.648 17.1 30.72 ;
     RECT  16.513 30.72 17.088 30.744 ;
     RECT  16.513 30.744 17.1 30.816 ;
     RECT  16.513 30.816 17.088 30.84 ;
     RECT  16.513 30.84 17.1 30.912 ;
     RECT  16.513 30.912 17.088 30.936 ;
     RECT  16.513 30.936 17.1 31.008 ;
     RECT  16.513 31.008 17.088 31.032 ;
     RECT  16.513 31.032 17.1 31.104 ;
     RECT  16.513 31.104 17.088 31.128 ;
     RECT  16.513 31.128 17.1 31.248 ;
     RECT  16.513 31.248 17.088 31.272 ;
     RECT  16.513 31.272 17.1 31.344 ;
     RECT  16.513 31.344 17.088 31.368 ;
     RECT  16.513 31.368 17.1 31.44 ;
     RECT  16.513 31.44 17.088 31.464 ;
     RECT  16.513 31.464 17.1 31.536 ;
     RECT  16.513 31.536 17.088 31.56 ;
     RECT  16.513 31.56 17.1 31.632 ;
     RECT  16.513 31.632 17.088 31.656 ;
     RECT  16.513 31.656 17.1 31.728 ;
     RECT  16.513 31.728 17.088 31.752 ;
     RECT  16.513 31.752 17.1 31.872 ;
     RECT  16.513 31.872 17.088 31.896 ;
     RECT  16.513 31.896 17.1 31.968 ;
     RECT  16.513 31.968 17.088 31.992 ;
     RECT  16.513 31.992 17.1 32.064 ;
     RECT  16.513 32.064 17.088 32.088 ;
     RECT  16.513 32.088 17.1 32.16 ;
     RECT  16.513 32.16 17.088 32.184 ;
     RECT  16.513 32.184 17.1 32.256 ;
     RECT  16.513 32.256 17.088 32.28 ;
     RECT  16.513 32.28 17.1 32.352 ;
     RECT  16.513 32.352 17.088 32.376 ;
     RECT  16.513 32.376 17.1 32.448 ;
     RECT  16.513 32.448 17.088 32.472 ;
     RECT  16.513 32.472 17.1 32.592 ;
     RECT  16.513 32.592 17.088 32.616 ;
     RECT  16.513 32.616 17.1 32.688 ;
     RECT  16.513 32.688 17.088 32.712 ;
     RECT  16.513 32.712 17.1 32.784 ;
     RECT  16.513 32.784 17.088 32.808 ;
     RECT  16.513 32.808 17.1 32.88 ;
     RECT  16.513 32.88 17.088 32.904 ;
     RECT  16.513 32.904 17.1 32.976 ;
     RECT  16.513 32.976 17.088 33 ;
     RECT  16.513 33 17.1 33.072 ;
     RECT  16.513 33.072 17.088 33.096 ;
     RECT  16.513 33.096 17.1 33.216 ;
     RECT  16.513 33.216 17.088 33.24 ;
     RECT  16.513 33.24 17.1 33.312 ;
     RECT  16.513 33.312 17.088 33.336 ;
     RECT  16.513 33.336 17.1 33.408 ;
     RECT  16.513 33.408 17.088 33.432 ;
     RECT  16.513 33.432 17.1 33.504 ;
     RECT  16.513 33.504 17.088 33.528 ;
     RECT  16.513 33.528 17.1 33.6 ;
     RECT  16.513 33.6 17.088 33.624 ;
     RECT  16.513 33.624 17.1 33.696 ;
     RECT  16.513 33.696 17.088 33.72 ;
     RECT  16.513 33.72 17.1 33.84 ;
     RECT  16.513 33.84 17.088 33.864 ;
     RECT  16.513 33.864 17.1 33.936 ;
     RECT  16.513 33.936 17.088 33.96 ;
     RECT  16.513 33.96 17.1 34.032 ;
     RECT  16.513 34.032 17.088 34.056 ;
     RECT  16.513 34.056 17.1 34.128 ;
     RECT  16.513 34.128 17.088 34.152 ;
     RECT  16.513 34.152 17.1 34.224 ;
     RECT  16.513 34.224 17.088 34.248 ;
     RECT  16.513 34.248 17.1 34.32 ;
     RECT  16.513 34.32 17.088 34.344 ;
     RECT  16.513 34.344 17.1 34.416 ;
     RECT  16.513 34.416 17.088 34.44 ;
     RECT  16.513 34.44 17.1 34.56 ;
     RECT  16.513 34.56 17.088 34.584 ;
     RECT  16.513 34.584 17.1 34.656 ;
     RECT  16.513 34.656 17.088 34.68 ;
     RECT  16.513 34.68 17.1 34.752 ;
     RECT  16.513 34.752 17.088 34.776 ;
     RECT  16.513 34.776 17.1 34.848 ;
     RECT  16.513 34.848 17.088 34.872 ;
     RECT  16.513 34.872 17.1 34.944 ;
     RECT  16.513 34.944 17.088 34.968 ;
     RECT  16.513 34.968 17.1 35.04 ;
     RECT  16.513 35.04 17.088 35.064 ;
     RECT  16.513 35.064 17.1 35.184 ;
     RECT  16.513 35.184 17.088 35.208 ;
     RECT  16.513 35.208 17.1 35.28 ;
     RECT  16.513 35.28 17.088 35.304 ;
     RECT  16.513 35.304 17.1 35.376 ;
     RECT  16.513 35.376 17.088 35.4 ;
     RECT  16.513 35.4 17.1 35.472 ;
     RECT  16.513 35.472 17.088 35.496 ;
     RECT  16.513 35.496 17.1 35.568 ;
     RECT  16.513 35.568 17.088 35.592 ;
     RECT  16.513 35.592 17.1 35.664 ;
     RECT  16.513 35.664 17.088 35.688 ;
     RECT  16.513 35.688 17.1 35.808 ;
     RECT  16.513 35.808 17.088 35.832 ;
     RECT  16.513 35.832 17.1 35.904 ;
     RECT  16.513 35.904 17.088 35.928 ;
     RECT  16.513 35.928 17.1 36 ;
     RECT  16.513 36 17.088 36.024 ;
     RECT  16.513 36.024 17.1 36.096 ;
     RECT  16.513 36.096 17.088 36.12 ;
     RECT  16.513 36.12 17.1 36.192 ;
     RECT  16.513 36.192 17.088 36.216 ;
     RECT  16.513 36.216 17.1 36.288 ;
     RECT  16.513 36.288 17.088 36.312 ;
     RECT  16.513 36.312 17.1 36.384 ;
     RECT  16.513 36.384 17.088 36.408 ;
     RECT  16.513 36.408 17.1 36.528 ;
     RECT  16.513 36.528 17.088 36.552 ;
     RECT  16.513 36.552 17.1 36.624 ;
     RECT  16.513 36.624 17.088 36.648 ;
     RECT  16.513 36.648 17.1 36.72 ;
     RECT  16.513 36.72 17.088 36.744 ;
     RECT  16.513 36.744 17.1 36.816 ;
     RECT  16.513 36.816 17.088 36.84 ;
     RECT  16.513 36.84 17.1 36.912 ;
     RECT  16.513 36.912 17.088 36.936 ;
     RECT  16.513 36.936 17.1 37.008 ;
     RECT  16.513 37.008 17.088 37.032 ;
     RECT  16.513 37.032 17.1 37.152 ;
     RECT  16.513 37.152 17.088 37.176 ;
     RECT  16.513 37.176 17.1 37.248 ;
     RECT  16.513 37.248 17.088 37.272 ;
     RECT  16.513 37.272 17.1 37.344 ;
     RECT  16.513 37.344 17.088 37.368 ;
     RECT  16.513 37.368 17.1 37.44 ;
     RECT  16.513 37.44 17.088 37.464 ;
     RECT  16.513 37.464 17.1 37.536 ;
     RECT  16.513 37.536 17.088 37.56 ;
     RECT  16.513 37.56 17.1 37.632 ;
     RECT  16.513 37.632 17.088 37.656 ;
     RECT  16.513 37.656 17.1 37.776 ;
     RECT  16.513 37.776 17.088 37.8 ;
     RECT  16.513 37.8 17.1 37.872 ;
     RECT  16.513 37.872 17.088 37.896 ;
     RECT  16.513 37.896 17.1 37.968 ;
     RECT  16.513 37.968 17.088 37.992 ;
     RECT  16.513 37.992 17.1 38.064 ;
     RECT  16.513 38.064 17.088 38.088 ;
     RECT  16.513 38.088 17.1 38.16 ;
     RECT  16.513 38.16 17.088 38.184 ;
     RECT  16.513 38.184 17.1 38.256 ;
     RECT  16.513 38.256 17.088 38.28 ;
     RECT  16.513 38.28 17.1 38.352 ;
     RECT  16.513 38.352 17.088 38.376 ;
     RECT  16.513 38.376 17.1 38.496 ;
     RECT  16.513 38.496 17.088 38.52 ;
     RECT  16.513 38.52 17.1 38.592 ;
     RECT  16.513 38.592 17.088 38.616 ;
     RECT  16.513 38.616 17.1 38.688 ;
     RECT  16.513 38.688 17.088 38.712 ;
     RECT  16.513 38.712 17.1 38.784 ;
     RECT  16.513 38.784 17.088 38.808 ;
     RECT  16.513 38.808 17.1 38.88 ;
     RECT  16.513 38.88 17.088 38.904 ;
     RECT  16.513 38.904 17.1 38.976 ;
     RECT  16.513 38.976 17.088 39 ;
     RECT  16.513 39 17.1 39.12 ;
     RECT  16.513 39.12 17.088 39.144 ;
     RECT  16.513 39.144 17.1 39.216 ;
     RECT  16.513 39.216 17.088 39.24 ;
     RECT  16.513 39.24 17.1 39.312 ;
     RECT  16.513 39.312 17.088 39.336 ;
     RECT  16.513 39.336 17.1 39.408 ;
     RECT  16.513 39.408 17.088 39.432 ;
     RECT  16.513 39.432 17.1 39.504 ;
     RECT  16.513 39.504 17.088 39.528 ;
     RECT  16.513 39.528 17.1 39.6 ;
     RECT  16.513 39.6 17.088 39.624 ;
     RECT  16.513 39.624 17.1 39.744 ;
     RECT  16.513 39.744 17.088 39.768 ;
     RECT  16.513 39.768 17.1 39.84 ;
     RECT  16.513 39.84 17.088 39.864 ;
     RECT  16.513 39.864 17.1 39.936 ;
     RECT  16.513 39.936 17.088 39.96 ;
     RECT  16.513 39.96 17.1 40.032 ;
     RECT  16.513 40.032 17.088 40.056 ;
     RECT  16.513 40.056 17.1 40.128 ;
     RECT  16.513 40.128 17.088 40.152 ;
     RECT  16.513 40.152 17.1 40.224 ;
     RECT  16.513 40.224 17.088 40.248 ;
     RECT  16.513 40.248 17.1 40.368 ;
     RECT  16.513 40.368 17.088 40.392 ;
     RECT  16.513 40.392 17.1 40.464 ;
     RECT  16.513 40.464 17.088 40.488 ;
     RECT  16.513 40.488 17.1 40.56 ;
     RECT  16.513 40.56 17.088 40.584 ;
     RECT  16.513 40.584 17.1 40.656 ;
     RECT  16.513 40.656 17.088 40.68 ;
     RECT  16.513 40.68 17.1 40.752 ;
     RECT  16.513 40.752 17.088 40.776 ;
     RECT  16.513 40.776 17.1 40.848 ;
     RECT  16.513 40.848 17.088 40.872 ;
     RECT  16.513 40.872 17.1 40.944 ;
     RECT  16.513 40.944 17.088 40.968 ;
     RECT  16.513 40.968 17.1 41.088 ;
     RECT  16.513 41.088 17.088 41.112 ;
     RECT  16.513 41.112 17.1 41.184 ;
     RECT  16.513 41.184 17.088 41.208 ;
     RECT  16.513 41.208 17.1 41.28 ;
     RECT  16.513 41.28 17.088 41.304 ;
     RECT  16.513 41.304 17.1 41.376 ;
     RECT  16.513 41.376 17.088 41.4 ;
     RECT  16.513 41.4 17.1 41.472 ;
     RECT  16.513 41.472 17.088 41.496 ;
     RECT  16.513 41.496 17.1 41.568 ;
     RECT  16.513 41.568 17.088 41.592 ;
     RECT  16.513 41.592 17.1 41.712 ;
     RECT  16.513 41.712 17.088 41.736 ;
     RECT  16.513 41.736 17.1 41.808 ;
     RECT  16.513 41.808 17.088 41.832 ;
     RECT  16.513 41.832 17.1 41.904 ;
     RECT  16.513 41.904 17.088 41.928 ;
     RECT  16.513 41.928 17.1 42 ;
     RECT  16.513 42 17.088 42.024 ;
     RECT  16.513 42.024 17.1 42.096 ;
     RECT  16.513 42.096 17.088 42.12 ;
     RECT  16.513 42.12 17.1 42.192 ;
     RECT  16.513 42.192 17.088 42.216 ;
     RECT  16.513 42.216 17.1 42.336 ;
     RECT  16.513 42.336 17.088 42.36 ;
     RECT  16.513 42.36 17.1 42.432 ;
     RECT  16.513 42.432 17.088 42.456 ;
     RECT  16.513 42.456 17.1 42.528 ;
     RECT  16.513 42.528 17.088 42.552 ;
     RECT  16.513 42.552 17.1 42.624 ;
     RECT  16.513 42.624 17.088 42.648 ;
     RECT  16.513 42.648 17.1 42.72 ;
     RECT  16.513 42.72 17.088 42.744 ;
     RECT  16.513 42.744 17.1 42.816 ;
     RECT  16.513 42.816 17.088 42.84 ;
     RECT  16.513 42.84 17.1 42.912 ;
     RECT  16.513 42.912 17.088 42.936 ;
     RECT  16.513 42.936 17.1 43.056 ;
     RECT  16.513 43.056 17.088 43.08 ;
     RECT  16.513 43.08 17.1 43.152 ;
     RECT  16.513 43.152 17.088 43.176 ;
     RECT  16.513 43.176 17.1 43.248 ;
     RECT  16.513 43.248 17.088 43.272 ;
     RECT  16.513 43.272 17.1 43.344 ;
     RECT  16.513 43.344 17.088 43.368 ;
     RECT  16.513 43.368 17.1 43.44 ;
     RECT  16.513 43.44 17.088 43.464 ;
     RECT  16.513 43.464 17.1 43.536 ;
     RECT  16.513 43.536 17.088 43.56 ;
     RECT  16.513 43.56 17.1 43.68 ;
     RECT  16.513 43.68 17.088 43.704 ;
     RECT  16.513 43.704 17.1 43.776 ;
     RECT  16.513 43.776 17.088 43.8 ;
     RECT  16.513 43.8 17.1 43.872 ;
     RECT  16.513 43.872 17.088 43.896 ;
     RECT  16.513 43.896 17.1 43.968 ;
     RECT  16.513 43.968 17.088 43.992 ;
     RECT  16.513 43.992 17.1 44.064 ;
     RECT  16.513 44.064 17.088 44.088 ;
     RECT  16.513 44.088 17.1 44.16 ;
     RECT  16.513 44.16 17.088 44.184 ;
     RECT  16.513 44.184 17.1 44.304 ;
     RECT  16.513 44.304 17.088 44.328 ;
     RECT  16.513 44.328 17.1 44.4 ;
     RECT  16.513 44.4 17.088 44.424 ;
     RECT  16.513 44.424 17.1 44.496 ;
     RECT  16.513 44.496 17.088 44.52 ;
     RECT  16.513 44.52 17.1 44.592 ;
     RECT  16.513 44.592 17.088 44.616 ;
     RECT  16.513 44.616 17.1 44.688 ;
     RECT  16.513 44.688 17.088 44.712 ;
     RECT  16.513 44.712 17.1 44.784 ;
     RECT  16.513 44.784 17.088 44.808 ;
     RECT  16.513 44.808 17.1 44.88 ;
     RECT  16.513 44.88 17.088 44.904 ;
     RECT  16.513 44.904 17.1 45.024 ;
     RECT  16.513 45.024 17.088 45.048 ;
     RECT  16.513 45.048 17.1 45.12 ;
     RECT  16.513 45.12 17.088 45.144 ;
     RECT  16.513 45.144 17.1 45.216 ;
     RECT  16.513 45.216 17.088 45.24 ;
     RECT  16.513 45.24 17.1 45.312 ;
     RECT  16.513 45.312 17.088 45.336 ;
     RECT  16.513 45.336 17.1 45.408 ;
     RECT  16.513 45.408 17.088 45.432 ;
     RECT  16.513 45.432 17.1 45.504 ;
     RECT  16.513 45.504 17.088 45.528 ;
     RECT  16.513 45.528 17.1 45.648 ;
     RECT  16.513 45.648 17.088 45.672 ;
     RECT  16.513 45.672 17.1 45.744 ;
     RECT  16.513 45.744 17.088 45.768 ;
     RECT  16.513 45.768 17.1 45.84 ;
     RECT  16.513 45.84 17.088 45.864 ;
     RECT  16.513 45.864 17.1 45.936 ;
     RECT  16.513 45.936 17.088 45.96 ;
     RECT  16.513 45.96 17.1 46.032 ;
     RECT  16.513 46.032 17.088 46.056 ;
     RECT  16.513 46.056 17.1 46.128 ;
     RECT  16.513 46.128 17.088 46.152 ;
     RECT  16.513 46.152 17.1 46.272 ;
     RECT  16.513 46.272 17.088 46.296 ;
     RECT  16.513 46.296 17.1 46.368 ;
     RECT  16.513 46.368 17.088 46.392 ;
     RECT  16.513 46.392 17.1 46.464 ;
     RECT  16.513 46.464 17.088 46.488 ;
     RECT  16.513 46.488 17.1 46.56 ;
     RECT  16.513 46.56 17.088 46.584 ;
     RECT  16.513 46.584 17.1 46.656 ;
     RECT  16.513 46.656 17.088 46.68 ;
     RECT  16.513 46.68 17.1 46.752 ;
     RECT  16.513 46.752 17.088 46.776 ;
     RECT  16.513 46.776 17.1 46.848 ;
     RECT  16.513 46.848 17.088 46.872 ;
     RECT  16.513 46.872 17.1 46.992 ;
     RECT  16.513 46.992 17.088 47.016 ;
     RECT  16.513 47.016 17.1 47.088 ;
     RECT  16.513 47.088 17.088 47.112 ;
     RECT  16.513 47.112 17.1 47.184 ;
     RECT  16.513 47.184 17.088 47.208 ;
     RECT  16.513 47.208 17.1 47.28 ;
     RECT  16.513 47.28 17.088 47.304 ;
     RECT  16.513 47.304 17.1 47.376 ;
     RECT  16.513 47.376 17.088 47.4 ;
     RECT  16.513 47.4 17.1 47.472 ;
     RECT  16.513 47.472 17.088 47.496 ;
     RECT  16.513 47.496 17.1 47.616 ;
     RECT  16.513 47.616 17.088 47.64 ;
     RECT  16.513 47.64 17.1 47.712 ;
     RECT  16.513 47.712 17.088 47.736 ;
     RECT  16.513 47.736 17.1 47.808 ;
     RECT  16.513 47.808 17.088 47.832 ;
     RECT  16.513 47.832 17.1 47.904 ;
     RECT  16.513 47.904 17.088 47.928 ;
     RECT  16.513 47.928 17.1 48 ;
     RECT  16.513 48 17.088 48.024 ;
     RECT  16.513 48.024 17.1 48.096 ;
     RECT  16.513 48.096 17.088 48.12 ;
     RECT  16.513 48.12 17.1 48.24 ;
     RECT  16.513 48.24 17.088 48.264 ;
     RECT  16.513 48.264 17.1 48.336 ;
     RECT  16.513 48.336 17.088 48.36 ;
     RECT  16.513 48.36 17.1 48.432 ;
     RECT  16.513 48.432 17.088 48.456 ;
     RECT  16.513 48.456 17.1 48.528 ;
     RECT  16.513 48.528 17.088 48.552 ;
     RECT  16.513 48.552 17.1 48.624 ;
     RECT  16.513 48.624 17.088 48.648 ;
     RECT  16.513 48.648 17.1 48.72 ;
     RECT  16.513 48.72 17.088 48.744 ;
     RECT  16.513 48.744 17.1 48.816 ;
     RECT  16.513 48.816 17.088 48.84 ;
     RECT  16.513 48.84 17.1 48.96 ;
     RECT  16.513 48.96 17.088 48.984 ;
     RECT  16.513 48.984 17.1 49.056 ;
     RECT  16.513 49.056 17.088 49.08 ;
     RECT  16.513 49.08 17.1 49.152 ;
     RECT  16.513 49.152 17.088 49.176 ;
     RECT  16.513 49.176 17.1 49.248 ;
     RECT  16.513 49.248 17.088 49.272 ;
     RECT  16.513 49.272 17.1 49.344 ;
     RECT  16.513 49.344 17.088 49.368 ;
     RECT  16.513 49.368 17.1 49.44 ;
     RECT  16.513 49.44 17.088 49.464 ;
     RECT  16.513 49.464 17.1 49.584 ;
     RECT  16.513 49.584 17.088 49.608 ;
     RECT  16.513 49.608 17.1 49.68 ;
     RECT  16.513 49.68 17.088 49.704 ;
     RECT  16.513 49.704 17.1 49.776 ;
     RECT  16.513 49.776 17.088 49.8 ;
     RECT  16.513 49.8 17.1 49.872 ;
     RECT  16.513 49.872 17.088 49.896 ;
     RECT  16.513 49.896 17.1 49.968 ;
     RECT  16.513 49.968 17.088 49.992 ;
     RECT  16.513 49.992 17.1 50.064 ;
     RECT  16.513 50.064 17.088 50.088 ;
     RECT  16.513 50.088 17.1 50.208 ;
     RECT  16.513 50.208 17.088 50.232 ;
     RECT  16.513 50.232 17.1 50.304 ;
     RECT  16.513 50.304 17.088 50.328 ;
     RECT  16.513 50.328 17.1 50.4 ;
     RECT  16.513 50.4 17.088 50.424 ;
     RECT  16.513 50.424 17.1 50.496 ;
     RECT  16.513 50.496 17.088 50.52 ;
     RECT  16.513 50.52 17.1 50.592 ;
     RECT  16.513 50.592 17.088 50.616 ;
     RECT  16.513 50.616 17.1 50.688 ;
     RECT  16.513 50.688 17.088 50.712 ;
     RECT  16.513 50.712 17.1 50.784 ;
     RECT  16.513 50.784 17.088 50.808 ;
     RECT  16.513 50.808 17.1 50.928 ;
     RECT  16.513 50.928 17.088 50.952 ;
     RECT  16.513 50.952 17.1 51.024 ;
     RECT  16.513 51.024 17.088 51.048 ;
     RECT  16.513 51.048 17.1 51.12 ;
     RECT  16.513 51.12 17.088 51.144 ;
     RECT  16.513 51.144 17.1 51.216 ;
     RECT  16.513 51.216 17.088 51.24 ;
     RECT  16.513 51.24 17.1 51.312 ;
     RECT  16.513 51.312 17.088 51.336 ;
     RECT  16.513 51.336 17.1 51.408 ;
     RECT  16.513 51.408 17.088 51.432 ;
     RECT  16.513 51.432 17.1 51.552 ;
     RECT  16.513 51.552 17.088 51.576 ;
     RECT  16.513 51.576 17.1 51.648 ;
     RECT  16.513 51.648 17.088 51.672 ;
     RECT  16.513 51.672 17.1 51.744 ;
     RECT  16.513 51.744 17.088 51.768 ;
     RECT  16.513 51.768 17.1 51.84 ;
     RECT  16.513 51.84 17.088 51.864 ;
     RECT  16.513 51.864 17.1 51.936 ;
     RECT  16.513 51.936 17.088 51.96 ;
     RECT  16.513 51.96 17.1 52.032 ;
     RECT  16.513 52.032 17.088 52.056 ;
     RECT  16.513 52.056 17.1 52.176 ;
     RECT  16.513 52.176 17.088 52.2 ;
     RECT  16.513 52.2 17.1 52.272 ;
     RECT  16.513 52.272 17.088 52.296 ;
     RECT  16.513 52.296 17.1 52.368 ;
     RECT  16.513 52.368 17.088 52.392 ;
     RECT  16.513 52.392 17.1 52.464 ;
     RECT  16.513 52.464 17.088 52.488 ;
     RECT  16.513 52.488 17.1 52.56 ;
     RECT  16.513 52.56 17.088 52.584 ;
     RECT  16.513 52.584 17.1 52.656 ;
     RECT  16.513 52.656 17.088 52.68 ;
     RECT  16.513 52.68 17.1 52.752 ;
     RECT  16.513 52.752 17.088 52.776 ;
     RECT  16.513 52.776 17.1 52.896 ;
     RECT  16.513 52.896 17.088 52.92 ;
     RECT  16.513 52.92 17.1 52.992 ;
     RECT  16.513 52.992 17.088 53.016 ;
     RECT  16.513 53.016 17.1 53.088 ;
     RECT  16.513 53.088 17.088 53.112 ;
     RECT  16.513 53.112 17.1 53.184 ;
     RECT  16.513 53.184 17.088 53.208 ;
     RECT  16.513 53.208 17.1 53.28 ;
     RECT  16.513 53.28 17.088 53.304 ;
     RECT  16.513 53.304 17.1 53.376 ;
     RECT  16.513 53.376 17.088 53.4 ;
     RECT  16.513 53.4 17.1 53.52 ;
     RECT  16.513 53.52 17.088 53.544 ;
     RECT  16.513 53.544 17.1 53.616 ;
     RECT  16.513 53.616 17.088 53.64 ;
     RECT  16.513 53.64 17.1 53.712 ;
     RECT  16.513 53.712 17.088 53.736 ;
     RECT  16.513 53.736 17.1 53.808 ;
     RECT  16.513 53.808 17.088 53.832 ;
     RECT  16.513 53.832 17.1 53.904 ;
     RECT  16.513 53.904 17.088 53.928 ;
     RECT  16.513 53.928 17.1 54 ;
     RECT  16.513 54 17.088 54.024 ;
     RECT  16.513 54.024 17.1 54.144 ;
     RECT  16.513 54.144 17.088 54.168 ;
     RECT  16.513 54.168 17.1 54.24 ;
     RECT  16.513 54.24 17.088 54.264 ;
     RECT  16.513 54.264 17.1 54.336 ;
     RECT  16.513 54.336 17.088 54.36 ;
     RECT  16.513 54.36 17.1 54.432 ;
     RECT  16.513 54.432 17.088 54.456 ;
     RECT  16.513 54.456 17.1 54.528 ;
     RECT  16.513 54.528 17.088 54.552 ;
     RECT  16.513 54.552 17.1 54.624 ;
     RECT  16.513 54.624 17.088 54.648 ;
     RECT  16.513 54.648 17.1 54.72 ;
     RECT  16.513 54.72 17.088 54.744 ;
     RECT  16.513 54.744 17.1 54.864 ;
     RECT  16.513 54.864 17.088 54.888 ;
     RECT  16.513 54.888 17.1 54.96 ;
     RECT  16.513 54.96 17.088 54.984 ;
     RECT  16.513 54.984 17.1 55.056 ;
     RECT  16.513 55.056 17.088 55.08 ;
     RECT  16.513 55.08 17.1 55.152 ;
     RECT  16.513 55.152 17.088 55.176 ;
     RECT  16.513 55.176 17.1 55.248 ;
     RECT  16.513 55.248 17.088 55.272 ;
     RECT  16.513 55.272 17.1 55.344 ;
     RECT  16.513 55.344 17.088 55.368 ;
     RECT  16.513 55.368 17.1 55.488 ;
     RECT  16.513 55.488 17.088 55.512 ;
     RECT  16.513 55.512 17.1 55.584 ;
     RECT  16.513 55.584 17.088 55.608 ;
     RECT  16.513 55.608 17.1 55.68 ;
     RECT  16.513 55.68 17.088 55.704 ;
     RECT  16.513 55.704 17.1 55.776 ;
     RECT  16.513 55.776 17.088 55.8 ;
     RECT  16.513 55.8 17.1 55.872 ;
     RECT  16.513 55.872 17.088 55.896 ;
     RECT  16.513 55.896 17.1 55.968 ;
     RECT  16.513 55.968 17.088 55.992 ;
     RECT  16.513 55.992 17.1 56.112 ;
     RECT  16.513 56.112 17.088 56.136 ;
     RECT  16.513 56.136 17.1 56.208 ;
     RECT  16.513 56.208 17.088 56.232 ;
     RECT  16.513 56.232 17.1 56.304 ;
     RECT  16.513 56.304 17.088 56.328 ;
     RECT  16.513 56.328 17.1 56.4 ;
     RECT  16.513 56.4 17.088 56.424 ;
     RECT  16.513 56.424 17.1 56.496 ;
     RECT  16.513 56.496 17.088 56.52 ;
     RECT  16.513 56.52 17.1 56.592 ;
     RECT  16.513 56.592 17.088 56.616 ;
     RECT  16.513 56.616 17.1 56.688 ;
     RECT  16.513 56.688 17.088 56.712 ;
     RECT  16.513 56.712 17.1 56.832 ;
     RECT  16.513 56.832 17.088 56.856 ;
     RECT  16.513 56.856 17.1 56.928 ;
     RECT  16.513 56.928 17.088 56.952 ;
     RECT  16.513 56.952 17.1 57.024 ;
     RECT  16.513 57.024 17.088 57.048 ;
     RECT  16.513 57.048 17.1 57.12 ;
     RECT  16.513 57.12 17.088 57.144 ;
     RECT  16.513 57.144 17.1 57.216 ;
     RECT  16.513 57.216 17.088 57.24 ;
     RECT  16.513 57.24 17.1 57.312 ;
     RECT  16.513 57.312 17.088 57.336 ;
     RECT  16.513 57.336 17.1 57.456 ;
     RECT  16.513 57.456 17.088 57.48 ;
     RECT  16.513 57.48 17.1 57.552 ;
     RECT  16.513 57.552 17.088 57.576 ;
     RECT  16.513 57.576 17.1 57.648 ;
     RECT  16.513 57.648 17.088 57.672 ;
     RECT  16.513 57.672 17.1 57.744 ;
     RECT  16.513 57.744 17.088 57.768 ;
     RECT  16.513 57.768 17.1 57.84 ;
     RECT  16.513 57.84 17.088 57.864 ;
     RECT  16.513 57.864 17.1 57.936 ;
     RECT  16.513 57.936 17.088 57.96 ;
     RECT  16.513 57.96 17.1 58.08 ;
     RECT  16.513 58.08 17.088 58.104 ;
     RECT  16.513 58.104 17.1 58.176 ;
     RECT  16.513 58.176 17.088 58.2 ;
     RECT  16.513 58.2 17.1 58.272 ;
     RECT  16.513 58.272 17.088 58.296 ;
     RECT  16.513 58.296 17.1 58.368 ;
     RECT  16.513 58.368 17.088 58.392 ;
     RECT  16.513 58.392 17.1 58.464 ;
     RECT  16.513 58.464 17.088 58.488 ;
     RECT  16.513 58.488 17.1 58.56 ;
     RECT  16.513 58.56 17.088 58.584 ;
     RECT  16.513 58.584 17.1 58.656 ;
     RECT  16.513 58.656 17.088 58.68 ;
     RECT  16.513 58.68 17.1 58.8 ;
     RECT  16.513 58.8 17.088 58.824 ;
     RECT  16.513 58.824 17.1 58.896 ;
     RECT  16.513 58.896 17.088 58.92 ;
     RECT  16.513 58.92 17.1 58.992 ;
     RECT  16.513 58.992 17.088 59.016 ;
     RECT  16.513 59.016 17.1 59.088 ;
     RECT  16.513 59.088 17.088 59.112 ;
     RECT  16.513 59.112 17.1 59.184 ;
     RECT  16.513 59.184 17.088 59.208 ;
     RECT  16.513 59.208 17.1 59.28 ;
     RECT  16.513 59.28 17.088 59.304 ;
     RECT  16.513 59.304 17.1 59.424 ;
     RECT  16.513 59.424 17.088 59.448 ;
     RECT  16.513 59.448 17.1 59.52 ;
     RECT  16.513 59.52 17.088 59.544 ;
     RECT  16.513 59.544 17.1 59.616 ;
     RECT  16.513 59.616 17.088 59.64 ;
     RECT  16.513 59.64 17.1 59.712 ;
     RECT  16.513 59.712 17.088 59.736 ;
     RECT  16.513 59.736 17.1 59.808 ;
     RECT  16.513 59.808 17.088 59.832 ;
     RECT  16.513 59.832 17.1 59.904 ;
     RECT  16.513 59.904 17.088 59.928 ;
     RECT  16.513 59.928 17.1 60.048 ;
     RECT  16.513 60.048 17.088 60.072 ;
     RECT  16.513 60.072 17.1 60.144 ;
     RECT  16.513 60.144 17.088 60.168 ;
     RECT  16.513 60.168 17.1 60.24 ;
     RECT  16.513 60.24 17.088 60.264 ;
     RECT  16.513 60.264 17.1 60.336 ;
     RECT  16.513 60.336 17.088 60.36 ;
     RECT  16.513 60.36 17.1 60.432 ;
     RECT  16.513 60.432 17.088 60.456 ;
    LAYER M5 ;
     RECT  2.4 2.137 2.52 2.151 ;
     RECT  5.1 2.137 5.22 2.151 ;
     RECT  7.8 2.137 7.92 2.151 ;
     RECT  10.5 2.137 10.62 2.151 ;
     RECT  13.2 2.137 13.32 2.151 ;
     RECT  3.744 2.581 3.768 2.915 ;
     RECT  2.4 2.151 2.712 3.109 ;
     RECT  2.304 3.109 2.712 3.299 ;
     RECT  7.8 2.151 8.112 4.597 ;
     RECT  7.8 4.597 8.232 5.893 ;
     RECT  7.8 5.893 8.616 6.227 ;
     RECT  7.8 6.227 8.328 6.611 ;
     RECT  2.4 3.299 2.712 6.853 ;
     RECT  2.304 6.853 2.712 7.043 ;
     RECT  7.8 6.611 8.112 7.957 ;
     RECT  7.536 7.957 8.112 8.389 ;
     RECT  5.1 2.151 5.412 9.541 ;
     RECT  7.056 8.389 8.112 9.685 ;
     RECT  7.056 9.685 8.232 10.019 ;
     RECT  1.248 9.877 1.272 10.115 ;
     RECT  7.056 10.019 8.112 11.509 ;
     RECT  7.056 11.509 9.048 11.699 ;
     RECT  4.8 9.541 5.412 12.517 ;
     RECT  4.8 12.517 5.688 13.139 ;
     RECT  5.1 13.139 5.688 13.715 ;
     RECT  7.056 11.699 8.112 15.109 ;
     RECT  7.056 15.109 8.232 15.395 ;
     RECT  7.056 15.395 8.112 15.493 ;
     RECT  6.912 15.493 8.112 15.923 ;
     RECT  7.008 15.923 8.112 16.405 ;
     RECT  7.008 16.405 8.232 16.549 ;
     RECT  7.008 16.549 8.76 16.931 ;
     RECT  2.4 7.043 2.712 17.077 ;
     RECT  7.008 16.931 8.232 17.941 ;
     RECT  7.008 17.941 8.52 18.323 ;
     RECT  7.008 18.323 8.232 18.661 ;
     RECT  5.1 13.715 5.412 18.805 ;
     RECT  6.864 18.661 8.232 18.805 ;
     RECT  5.1 18.805 8.232 20.051 ;
     RECT  2.4 17.077 3.288 20.053 ;
     RECT  2.4 20.053 3.384 20.339 ;
     RECT  2.4 20.339 3.288 20.627 ;
     RECT  10.5 2.151 10.812 22.501 ;
     RECT  9.744 22.501 10.812 22.787 ;
     RECT  7.8 20.051 8.232 24.469 ;
     RECT  5.1 20.051 5.928 25.045 ;
     RECT  2.4 20.627 2.712 25.285 ;
     RECT  5.1 25.045 6.264 25.285 ;
     RECT  2.304 25.285 2.712 25.475 ;
     RECT  5.1 25.285 6.36 25.621 ;
     RECT  7.44 24.469 8.232 25.621 ;
     RECT  4.032 25.573 4.056 25.763 ;
     RECT  5.1 25.621 8.232 26.051 ;
     RECT  5.1 26.051 6.6 27.059 ;
     RECT  7.8 26.051 8.232 28.501 ;
     RECT  7.584 28.501 8.232 28.835 ;
     RECT  5.1 27.059 6.36 30.275 ;
     RECT  2.4 25.475 2.712 30.757 ;
     RECT  2.4 30.757 2.856 30.899 ;
     RECT  7.8 28.835 8.232 31.381 ;
     RECT  7.8 31.381 8.328 31.523 ;
     RECT  5.1 30.275 5.928 31.909 ;
     RECT  2.4 30.899 2.712 32.245 ;
     RECT  2.304 32.245 2.712 32.435 ;
     RECT  5.1 31.909 6.408 32.579 ;
     RECT  0.288 35.077 0.312 35.267 ;
     RECT  3.936 36.325 3.96 37.573 ;
     RECT  5.1 32.579 5.784 37.573 ;
     RECT  3.936 37.573 5.784 37.619 ;
     RECT  2.4 32.435 2.712 38.773 ;
     RECT  7.8 31.523 8.112 38.917 ;
     RECT  2.304 38.773 2.712 38.963 ;
     RECT  7.8 38.917 9.096 39.107 ;
     RECT  9.456 39.349 9.48 39.635 ;
     RECT  4.8 37.619 5.784 40.405 ;
     RECT  4.8 40.405 6.408 41.413 ;
     RECT  7.8 39.107 8.112 41.413 ;
     RECT  2.4 38.963 2.712 41.605 ;
     RECT  4.8 41.413 8.112 42.085 ;
     RECT  4.8 42.085 9.096 42.227 ;
     RECT  2.4 41.605 3.432 42.323 ;
     RECT  7.248 42.227 9.096 42.707 ;
     RECT  4.8 42.227 5.88 42.803 ;
     RECT  7.248 42.707 8.112 43.285 ;
     RECT  0.288 43.141 0.312 43.331 ;
     RECT  4.8 42.803 5.784 44.195 ;
     RECT  5.1 44.195 5.784 44.245 ;
     RECT  6.96 43.285 8.112 44.245 ;
     RECT  5.1 44.245 8.112 45.059 ;
     RECT  9.312 45.205 9.336 45.347 ;
     RECT  9.216 47.797 9.24 47.987 ;
     RECT  7.8 45.059 8.112 48.037 ;
     RECT  5.1 45.059 6.36 48.229 ;
     RECT  4.752 48.229 6.36 48.275 ;
     RECT  7.68 48.037 8.112 48.517 ;
     RECT  6.912 48.517 8.112 49.331 ;
     RECT  9.456 49.621 9.48 49.811 ;
     RECT  7.392 49.331 8.112 49.861 ;
     RECT  10.5 22.787 10.812 50.005 ;
     RECT  7.392 49.861 8.328 50.051 ;
     RECT  10.32 50.005 10.812 50.147 ;
     RECT  7.392 50.051 8.112 50.195 ;
     RECT  7.8 50.195 8.112 51.733 ;
     RECT  7.8 51.733 8.328 51.971 ;
     RECT  10.5 50.147 10.812 52.021 ;
     RECT  10.32 52.021 10.812 52.259 ;
     RECT  6.624 52.309 6.648 53.267 ;
     RECT  7.8 51.971 8.112 53.413 ;
     RECT  7.8 53.413 9.048 53.699 ;
     RECT  1.152 53.989 1.176 54.131 ;
     RECT  2.4 42.323 2.712 55.045 ;
     RECT  2.4 55.045 3.336 55.525 ;
     RECT  7.8 53.699 8.112 56.149 ;
     RECT  4.752 48.275 5.592 56.485 ;
     RECT  4.752 56.485 6.36 56.531 ;
     RECT  7.8 56.149 8.328 56.629 ;
     RECT  2.4 55.525 3.432 56.869 ;
     RECT  2.4 56.869 3.864 57.011 ;
     RECT  7.8 56.629 8.472 57.493 ;
     RECT  7.8 57.493 8.904 57.731 ;
     RECT  2.4 57.011 3.432 58.163 ;
     RECT  5.1 56.531 6.36 58.499 ;
     RECT  0.192 58.501 0.216 58.691 ;
     RECT  2.4 58.163 2.712 60.489 ;
     RECT  7.8 57.731 8.112 60.489 ;
     RECT  10.5 52.259 10.812 60.489 ;
     RECT  13.2 2.151 13.512 60.489 ;
     RECT  2.4 60.489 2.52 60.503 ;
     RECT  5.1 58.499 5.592 60.503 ;
     RECT  7.8 60.489 7.92 60.503 ;
     RECT  10.5 60.489 10.62 60.503 ;
     RECT  13.2 60.489 13.32 60.503 ;
     RECT  5.568 60.503 5.592 61.619 ;
     RECT  2.712 2.581 3.744 2.915 ;
     RECT  3.768 2.581 5.1 2.915 ;
     RECT  1.272 9.877 2.4 10.115 ;
     RECT  8.112 10.019 8.232 11.509 ;
     RECT  9.048 11.509 10.5 11.699 ;
     RECT  5.688 12.517 7.056 13.715 ;
     RECT  8.112 15.395 8.232 16.405 ;
     RECT  5.412 15.493 6.912 15.923 ;
     RECT  8.232 16.931 8.52 17.941 ;
     RECT  5.412 18.661 6.864 18.805 ;
     RECT  8.232 22.501 9.744 22.787 ;
     RECT  5.928 24.469 7.44 25.045 ;
     RECT  6.264 25.045 7.44 25.285 ;
     RECT  6.36 25.285 7.44 25.621 ;
     RECT  2.712 25.573 4.032 25.763 ;
     RECT  4.056 25.573 5.1 25.763 ;
     RECT  6.6 26.051 7.8 27.059 ;
     RECT  6.36 27.059 7.8 28.501 ;
     RECT  6.36 28.501 7.584 28.835 ;
     RECT  6.36 28.835 7.8 30.275 ;
     RECT  6.408 31.909 7.8 32.579 ;
     RECT  2.712 36.325 3.936 37.619 ;
     RECT  3.96 36.325 5.1 37.573 ;
     RECT  9.096 38.917 10.5 39.107 ;
     RECT  8.112 39.107 10.5 39.349 ;
     RECT  8.112 39.349 9.456 39.635 ;
     RECT  9.48 39.349 10.5 39.635 ;
     RECT  6.408 40.405 7.8 41.413 ;
     RECT  3.432 41.605 4.8 42.323 ;
     RECT  9.096 42.085 10.5 42.707 ;
     RECT  5.88 42.227 7.248 42.803 ;
     RECT  5.784 42.803 7.248 43.285 ;
     RECT  5.784 43.285 6.96 44.245 ;
     RECT  6.36 45.059 7.8 48.037 ;
     RECT  8.112 45.205 9.312 45.347 ;
     RECT  9.336 45.205 10.5 45.347 ;
     RECT  8.112 47.797 9.216 47.987 ;
     RECT  9.24 47.797 10.5 47.987 ;
     RECT  6.36 48.037 7.68 48.275 ;
     RECT  5.592 48.275 7.68 48.517 ;
     RECT  5.592 48.517 6.912 49.331 ;
     RECT  8.112 49.621 9.456 49.811 ;
     RECT  9.48 49.621 10.5 49.811 ;
     RECT  8.112 49.811 8.328 49.861 ;
     RECT  10.32 49.811 10.5 50.005 ;
     RECT  8.112 51.971 8.328 53.413 ;
     RECT  10.32 52.259 10.5 53.413 ;
     RECT  5.592 52.309 6.624 53.267 ;
     RECT  6.648 52.309 7.8 53.267 ;
     RECT  9.048 53.413 10.5 53.699 ;
     RECT  1.176 53.989 2.4 54.131 ;
     RECT  3.336 55.045 4.752 55.525 ;
     RECT  3.432 55.525 4.752 56.531 ;
     RECT  6.36 56.485 7.8 58.499 ;
     RECT  3.432 56.531 5.1 56.869 ;
     RECT  3.864 56.869 5.1 57.011 ;
  END
END dsfd_dvrlyh_562_WE
END LIBRARY
